VERSION 5.8 ;
BUSBITCHARS "[]" ;
DIVIDERCHAR "/" ;
UNITS
    DATABASE MICRONS 1000 ;
END UNITS

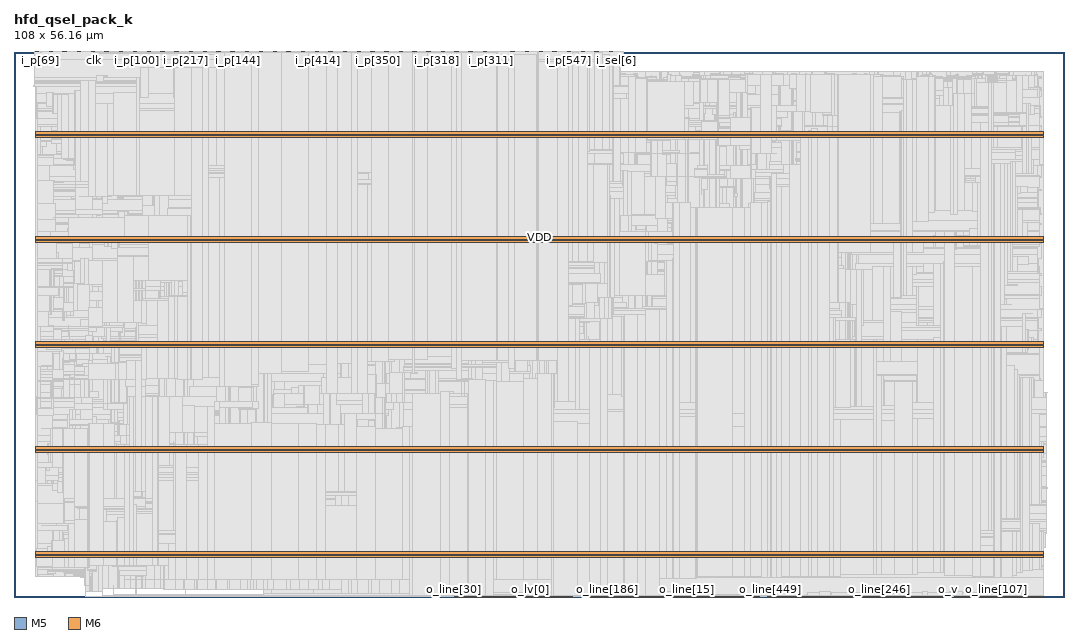
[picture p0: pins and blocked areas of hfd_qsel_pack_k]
MACRO hfd_qsel_pack_k
  FOREIGN hfd_qsel_pack_k 0 0 ;
  CLASS BLOCK ;
  SIZE 108 BY 56.16 ;
  PIN clk
    DIRECTION INPUT ;
    USE SIGNAL ;
    PORT
      LAYER M5 ;
        RECT  8.208 56.076 8.232 56.16 ;
    END
  END clk
  PIN i_fl
    DIRECTION INPUT ;
    USE SIGNAL ;
    PORT
      LAYER M5 ;
        RECT  8.304 56.076 8.328 56.16 ;
    END
  END i_fl
  PIN i_p[0]
    DIRECTION INPUT ;
    USE SIGNAL ;
    PORT
      LAYER M5 ;
        RECT  8.4 56.076 8.424 56.16 ;
    END
  END i_p[0]
  PIN i_p[100]
    DIRECTION INPUT ;
    USE SIGNAL ;
    PORT
      LAYER M5 ;
        RECT  12.624 56.076 12.648 56.16 ;
    END
  END i_p[100]
  PIN i_p[101]
    DIRECTION INPUT ;
    USE SIGNAL ;
    PORT
      LAYER M5 ;
        RECT  12.72 56.076 12.744 56.16 ;
    END
  END i_p[101]
  PIN i_p[102]
    DIRECTION INPUT ;
    USE SIGNAL ;
    PORT
      LAYER M5 ;
        RECT  12.816 56.076 12.84 56.16 ;
    END
  END i_p[102]
  PIN i_p[103]
    DIRECTION INPUT ;
    USE SIGNAL ;
    PORT
      LAYER M5 ;
        RECT  12.912 56.076 12.936 56.16 ;
    END
  END i_p[103]
  PIN i_p[104]
    DIRECTION INPUT ;
    USE SIGNAL ;
    PORT
      LAYER M5 ;
        RECT  13.008 56.076 13.032 56.16 ;
    END
  END i_p[104]
  PIN i_p[105]
    DIRECTION INPUT ;
    USE SIGNAL ;
    PORT
      LAYER M5 ;
        RECT  13.104 56.076 13.128 56.16 ;
    END
  END i_p[105]
  PIN i_p[106]
    DIRECTION INPUT ;
    USE SIGNAL ;
    PORT
      LAYER M5 ;
        RECT  13.2 56.076 13.224 56.16 ;
    END
  END i_p[106]
  PIN i_p[107]
    DIRECTION INPUT ;
    USE SIGNAL ;
    PORT
      LAYER M5 ;
        RECT  13.296 56.076 13.32 56.16 ;
    END
  END i_p[107]
  PIN i_p[108]
    DIRECTION INPUT ;
    USE SIGNAL ;
    PORT
      LAYER M5 ;
        RECT  13.392 56.076 13.416 56.16 ;
    END
  END i_p[108]
  PIN i_p[109]
    DIRECTION INPUT ;
    USE SIGNAL ;
    PORT
      LAYER M5 ;
        RECT  13.488 56.076 13.512 56.16 ;
    END
  END i_p[109]
  PIN i_p[10]
    DIRECTION INPUT ;
    USE SIGNAL ;
    PORT
      LAYER M5 ;
        RECT  9.36 56.076 9.384 56.16 ;
    END
  END i_p[10]
  PIN i_p[110]
    DIRECTION INPUT ;
    USE SIGNAL ;
    PORT
      LAYER M5 ;
        RECT  13.584 56.076 13.608 56.16 ;
    END
  END i_p[110]
  PIN i_p[111]
    DIRECTION INPUT ;
    USE SIGNAL ;
    PORT
      LAYER M5 ;
        RECT  13.68 56.076 13.704 56.16 ;
    END
  END i_p[111]
  PIN i_p[112]
    DIRECTION INPUT ;
    USE SIGNAL ;
    PORT
      LAYER M5 ;
        RECT  13.776 56.076 13.8 56.16 ;
    END
  END i_p[112]
  PIN i_p[113]
    DIRECTION INPUT ;
    USE SIGNAL ;
    PORT
      LAYER M5 ;
        RECT  13.872 56.076 13.896 56.16 ;
    END
  END i_p[113]
  PIN i_p[114]
    DIRECTION INPUT ;
    USE SIGNAL ;
    PORT
      LAYER M5 ;
        RECT  13.968 56.076 13.992 56.16 ;
    END
  END i_p[114]
  PIN i_p[115]
    DIRECTION INPUT ;
    USE SIGNAL ;
    PORT
      LAYER M5 ;
        RECT  14.064 56.076 14.088 56.16 ;
    END
  END i_p[115]
  PIN i_p[116]
    DIRECTION INPUT ;
    USE SIGNAL ;
    PORT
      LAYER M5 ;
        RECT  14.16 56.076 14.184 56.16 ;
    END
  END i_p[116]
  PIN i_p[117]
    DIRECTION INPUT ;
    USE SIGNAL ;
    PORT
      LAYER M5 ;
        RECT  14.256 56.076 14.28 56.16 ;
    END
  END i_p[117]
  PIN i_p[118]
    DIRECTION INPUT ;
    USE SIGNAL ;
    PORT
      LAYER M5 ;
        RECT  14.352 56.076 14.376 56.16 ;
    END
  END i_p[118]
  PIN i_p[119]
    DIRECTION INPUT ;
    USE SIGNAL ;
    PORT
      LAYER M5 ;
        RECT  14.448 56.076 14.472 56.16 ;
    END
  END i_p[119]
  PIN i_p[11]
    DIRECTION INPUT ;
    USE SIGNAL ;
    PORT
      LAYER M5 ;
        RECT  9.456 56.076 9.48 56.16 ;
    END
  END i_p[11]
  PIN i_p[120]
    DIRECTION INPUT ;
    USE SIGNAL ;
    PORT
      LAYER M5 ;
        RECT  14.544 56.076 14.568 56.16 ;
    END
  END i_p[120]
  PIN i_p[121]
    DIRECTION INPUT ;
    USE SIGNAL ;
    PORT
      LAYER M5 ;
        RECT  14.64 56.076 14.664 56.16 ;
    END
  END i_p[121]
  PIN i_p[122]
    DIRECTION INPUT ;
    USE SIGNAL ;
    PORT
      LAYER M5 ;
        RECT  14.736 56.076 14.76 56.16 ;
    END
  END i_p[122]
  PIN i_p[123]
    DIRECTION INPUT ;
    USE SIGNAL ;
    PORT
      LAYER M5 ;
        RECT  14.832 56.076 14.856 56.16 ;
    END
  END i_p[123]
  PIN i_p[124]
    DIRECTION INPUT ;
    USE SIGNAL ;
    PORT
      LAYER M5 ;
        RECT  14.928 56.076 14.952 56.16 ;
    END
  END i_p[124]
  PIN i_p[125]
    DIRECTION INPUT ;
    USE SIGNAL ;
    PORT
      LAYER M5 ;
        RECT  15.024 56.076 15.048 56.16 ;
    END
  END i_p[125]
  PIN i_p[126]
    DIRECTION INPUT ;
    USE SIGNAL ;
    PORT
      LAYER M5 ;
        RECT  21.264 56.076 21.288 56.16 ;
    END
  END i_p[126]
  PIN i_p[127]
    DIRECTION INPUT ;
    USE SIGNAL ;
    PORT
      LAYER M5 ;
        RECT  21.36 56.076 21.384 56.16 ;
    END
  END i_p[127]
  PIN i_p[128]
    DIRECTION INPUT ;
    USE SIGNAL ;
    PORT
      LAYER M5 ;
        RECT  21.456 56.076 21.48 56.16 ;
    END
  END i_p[128]
  PIN i_p[129]
    DIRECTION INPUT ;
    USE SIGNAL ;
    PORT
      LAYER M5 ;
        RECT  21.552 56.076 21.576 56.16 ;
    END
  END i_p[129]
  PIN i_p[12]
    DIRECTION INPUT ;
    USE SIGNAL ;
    PORT
      LAYER M5 ;
        RECT  9.552 56.076 9.576 56.16 ;
    END
  END i_p[12]
  PIN i_p[130]
    DIRECTION INPUT ;
    USE SIGNAL ;
    PORT
      LAYER M5 ;
        RECT  21.648 56.076 21.672 56.16 ;
    END
  END i_p[130]
  PIN i_p[131]
    DIRECTION INPUT ;
    USE SIGNAL ;
    PORT
      LAYER M5 ;
        RECT  21.744 56.076 21.768 56.16 ;
    END
  END i_p[131]
  PIN i_p[132]
    DIRECTION INPUT ;
    USE SIGNAL ;
    PORT
      LAYER M5 ;
        RECT  21.84 56.076 21.864 56.16 ;
    END
  END i_p[132]
  PIN i_p[133]
    DIRECTION INPUT ;
    USE SIGNAL ;
    PORT
      LAYER M5 ;
        RECT  21.936 56.076 21.96 56.16 ;
    END
  END i_p[133]
  PIN i_p[134]
    DIRECTION INPUT ;
    USE SIGNAL ;
    PORT
      LAYER M5 ;
        RECT  22.032 56.076 22.056 56.16 ;
    END
  END i_p[134]
  PIN i_p[135]
    DIRECTION INPUT ;
    USE SIGNAL ;
    PORT
      LAYER M5 ;
        RECT  22.128 56.076 22.152 56.16 ;
    END
  END i_p[135]
  PIN i_p[136]
    DIRECTION INPUT ;
    USE SIGNAL ;
    PORT
      LAYER M5 ;
        RECT  22.224 56.076 22.248 56.16 ;
    END
  END i_p[136]
  PIN i_p[137]
    DIRECTION INPUT ;
    USE SIGNAL ;
    PORT
      LAYER M5 ;
        RECT  22.32 56.076 22.344 56.16 ;
    END
  END i_p[137]
  PIN i_p[138]
    DIRECTION INPUT ;
    USE SIGNAL ;
    PORT
      LAYER M5 ;
        RECT  22.416 56.076 22.44 56.16 ;
    END
  END i_p[138]
  PIN i_p[139]
    DIRECTION INPUT ;
    USE SIGNAL ;
    PORT
      LAYER M5 ;
        RECT  22.512 56.076 22.536 56.16 ;
    END
  END i_p[139]
  PIN i_p[13]
    DIRECTION INPUT ;
    USE SIGNAL ;
    PORT
      LAYER M5 ;
        RECT  9.648 56.076 9.672 56.16 ;
    END
  END i_p[13]
  PIN i_p[140]
    DIRECTION INPUT ;
    USE SIGNAL ;
    PORT
      LAYER M5 ;
        RECT  22.608 56.076 22.632 56.16 ;
    END
  END i_p[140]
  PIN i_p[141]
    DIRECTION INPUT ;
    USE SIGNAL ;
    PORT
      LAYER M5 ;
        RECT  22.704 56.076 22.728 56.16 ;
    END
  END i_p[141]
  PIN i_p[142]
    DIRECTION INPUT ;
    USE SIGNAL ;
    PORT
      LAYER M5 ;
        RECT  22.8 56.076 22.824 56.16 ;
    END
  END i_p[142]
  PIN i_p[143]
    DIRECTION INPUT ;
    USE SIGNAL ;
    PORT
      LAYER M5 ;
        RECT  22.896 56.076 22.92 56.16 ;
    END
  END i_p[143]
  PIN i_p[144]
    DIRECTION INPUT ;
    USE SIGNAL ;
    PORT
      LAYER M5 ;
        RECT  22.992 56.076 23.016 56.16 ;
    END
  END i_p[144]
  PIN i_p[145]
    DIRECTION INPUT ;
    USE SIGNAL ;
    PORT
      LAYER M5 ;
        RECT  23.088 56.076 23.112 56.16 ;
    END
  END i_p[145]
  PIN i_p[146]
    DIRECTION INPUT ;
    USE SIGNAL ;
    PORT
      LAYER M5 ;
        RECT  23.184 56.076 23.208 56.16 ;
    END
  END i_p[146]
  PIN i_p[147]
    DIRECTION INPUT ;
    USE SIGNAL ;
    PORT
      LAYER M5 ;
        RECT  23.28 56.076 23.304 56.16 ;
    END
  END i_p[147]
  PIN i_p[148]
    DIRECTION INPUT ;
    USE SIGNAL ;
    PORT
      LAYER M5 ;
        RECT  23.376 56.076 23.4 56.16 ;
    END
  END i_p[148]
  PIN i_p[149]
    DIRECTION INPUT ;
    USE SIGNAL ;
    PORT
      LAYER M5 ;
        RECT  23.472 56.076 23.496 56.16 ;
    END
  END i_p[149]
  PIN i_p[14]
    DIRECTION INPUT ;
    USE SIGNAL ;
    PORT
      LAYER M5 ;
        RECT  9.744 56.076 9.768 56.16 ;
    END
  END i_p[14]
  PIN i_p[150]
    DIRECTION INPUT ;
    USE SIGNAL ;
    PORT
      LAYER M5 ;
        RECT  23.568 56.076 23.592 56.16 ;
    END
  END i_p[150]
  PIN i_p[151]
    DIRECTION INPUT ;
    USE SIGNAL ;
    PORT
      LAYER M5 ;
        RECT  23.664 56.076 23.688 56.16 ;
    END
  END i_p[151]
  PIN i_p[152]
    DIRECTION INPUT ;
    USE SIGNAL ;
    PORT
      LAYER M5 ;
        RECT  23.76 56.076 23.784 56.16 ;
    END
  END i_p[152]
  PIN i_p[153]
    DIRECTION INPUT ;
    USE SIGNAL ;
    PORT
      LAYER M5 ;
        RECT  23.856 56.076 23.88 56.16 ;
    END
  END i_p[153]
  PIN i_p[154]
    DIRECTION INPUT ;
    USE SIGNAL ;
    PORT
      LAYER M5 ;
        RECT  23.952 56.076 23.976 56.16 ;
    END
  END i_p[154]
  PIN i_p[155]
    DIRECTION INPUT ;
    USE SIGNAL ;
    PORT
      LAYER M5 ;
        RECT  24.048 56.076 24.072 56.16 ;
    END
  END i_p[155]
  PIN i_p[156]
    DIRECTION INPUT ;
    USE SIGNAL ;
    PORT
      LAYER M5 ;
        RECT  24.144 56.076 24.168 56.16 ;
    END
  END i_p[156]
  PIN i_p[157]
    DIRECTION INPUT ;
    USE SIGNAL ;
    PORT
      LAYER M5 ;
        RECT  24.24 56.076 24.264 56.16 ;
    END
  END i_p[157]
  PIN i_p[158]
    DIRECTION INPUT ;
    USE SIGNAL ;
    PORT
      LAYER M5 ;
        RECT  24.336 56.076 24.36 56.16 ;
    END
  END i_p[158]
  PIN i_p[159]
    DIRECTION INPUT ;
    USE SIGNAL ;
    PORT
      LAYER M5 ;
        RECT  24.432 56.076 24.456 56.16 ;
    END
  END i_p[159]
  PIN i_p[15]
    DIRECTION INPUT ;
    USE SIGNAL ;
    PORT
      LAYER M5 ;
        RECT  9.84 56.076 9.864 56.16 ;
    END
  END i_p[15]
  PIN i_p[160]
    DIRECTION INPUT ;
    USE SIGNAL ;
    PORT
      LAYER M5 ;
        RECT  24.528 56.076 24.552 56.16 ;
    END
  END i_p[160]
  PIN i_p[161]
    DIRECTION INPUT ;
    USE SIGNAL ;
    PORT
      LAYER M5 ;
        RECT  24.624 56.076 24.648 56.16 ;
    END
  END i_p[161]
  PIN i_p[162]
    DIRECTION INPUT ;
    USE SIGNAL ;
    PORT
      LAYER M5 ;
        RECT  24.72 56.076 24.744 56.16 ;
    END
  END i_p[162]
  PIN i_p[163]
    DIRECTION INPUT ;
    USE SIGNAL ;
    PORT
      LAYER M5 ;
        RECT  24.816 56.076 24.84 56.16 ;
    END
  END i_p[163]
  PIN i_p[164]
    DIRECTION INPUT ;
    USE SIGNAL ;
    PORT
      LAYER M5 ;
        RECT  24.912 56.076 24.936 56.16 ;
    END
  END i_p[164]
  PIN i_p[165]
    DIRECTION INPUT ;
    USE SIGNAL ;
    PORT
      LAYER M5 ;
        RECT  25.008 56.076 25.032 56.16 ;
    END
  END i_p[165]
  PIN i_p[166]
    DIRECTION INPUT ;
    USE SIGNAL ;
    PORT
      LAYER M5 ;
        RECT  25.104 56.076 25.128 56.16 ;
    END
  END i_p[166]
  PIN i_p[167]
    DIRECTION INPUT ;
    USE SIGNAL ;
    PORT
      LAYER M5 ;
        RECT  25.2 56.076 25.224 56.16 ;
    END
  END i_p[167]
  PIN i_p[168]
    DIRECTION INPUT ;
    USE SIGNAL ;
    PORT
      LAYER M5 ;
        RECT  25.296 56.076 25.32 56.16 ;
    END
  END i_p[168]
  PIN i_p[169]
    DIRECTION INPUT ;
    USE SIGNAL ;
    PORT
      LAYER M5 ;
        RECT  25.392 56.076 25.416 56.16 ;
    END
  END i_p[169]
  PIN i_p[16]
    DIRECTION INPUT ;
    USE SIGNAL ;
    PORT
      LAYER M5 ;
        RECT  9.936 56.076 9.96 56.16 ;
    END
  END i_p[16]
  PIN i_p[170]
    DIRECTION INPUT ;
    USE SIGNAL ;
    PORT
      LAYER M5 ;
        RECT  25.488 56.076 25.512 56.16 ;
    END
  END i_p[170]
  PIN i_p[171]
    DIRECTION INPUT ;
    USE SIGNAL ;
    PORT
      LAYER M5 ;
        RECT  25.584 56.076 25.608 56.16 ;
    END
  END i_p[171]
  PIN i_p[172]
    DIRECTION INPUT ;
    USE SIGNAL ;
    PORT
      LAYER M5 ;
        RECT  25.68 56.076 25.704 56.16 ;
    END
  END i_p[172]
  PIN i_p[173]
    DIRECTION INPUT ;
    USE SIGNAL ;
    PORT
      LAYER M5 ;
        RECT  25.776 56.076 25.8 56.16 ;
    END
  END i_p[173]
  PIN i_p[174]
    DIRECTION INPUT ;
    USE SIGNAL ;
    PORT
      LAYER M5 ;
        RECT  25.872 56.076 25.896 56.16 ;
    END
  END i_p[174]
  PIN i_p[175]
    DIRECTION INPUT ;
    USE SIGNAL ;
    PORT
      LAYER M5 ;
        RECT  25.968 56.076 25.992 56.16 ;
    END
  END i_p[175]
  PIN i_p[176]
    DIRECTION INPUT ;
    USE SIGNAL ;
    PORT
      LAYER M5 ;
        RECT  26.064 56.076 26.088 56.16 ;
    END
  END i_p[176]
  PIN i_p[177]
    DIRECTION INPUT ;
    USE SIGNAL ;
    PORT
      LAYER M5 ;
        RECT  26.16 56.076 26.184 56.16 ;
    END
  END i_p[177]
  PIN i_p[178]
    DIRECTION INPUT ;
    USE SIGNAL ;
    PORT
      LAYER M5 ;
        RECT  26.256 56.076 26.28 56.16 ;
    END
  END i_p[178]
  PIN i_p[179]
    DIRECTION INPUT ;
    USE SIGNAL ;
    PORT
      LAYER M5 ;
        RECT  26.352 56.076 26.376 56.16 ;
    END
  END i_p[179]
  PIN i_p[17]
    DIRECTION INPUT ;
    USE SIGNAL ;
    PORT
      LAYER M5 ;
        RECT  10.032 56.076 10.056 56.16 ;
    END
  END i_p[17]
  PIN i_p[180]
    DIRECTION INPUT ;
    USE SIGNAL ;
    PORT
      LAYER M5 ;
        RECT  26.448 56.076 26.472 56.16 ;
    END
  END i_p[180]
  PIN i_p[181]
    DIRECTION INPUT ;
    USE SIGNAL ;
    PORT
      LAYER M5 ;
        RECT  26.544 56.076 26.568 56.16 ;
    END
  END i_p[181]
  PIN i_p[182]
    DIRECTION INPUT ;
    USE SIGNAL ;
    PORT
      LAYER M5 ;
        RECT  26.64 56.076 26.664 56.16 ;
    END
  END i_p[182]
  PIN i_p[183]
    DIRECTION INPUT ;
    USE SIGNAL ;
    PORT
      LAYER M5 ;
        RECT  26.736 56.076 26.76 56.16 ;
    END
  END i_p[183]
  PIN i_p[184]
    DIRECTION INPUT ;
    USE SIGNAL ;
    PORT
      LAYER M5 ;
        RECT  26.832 56.076 26.856 56.16 ;
    END
  END i_p[184]
  PIN i_p[185]
    DIRECTION INPUT ;
    USE SIGNAL ;
    PORT
      LAYER M5 ;
        RECT  26.928 56.076 26.952 56.16 ;
    END
  END i_p[185]
  PIN i_p[186]
    DIRECTION INPUT ;
    USE SIGNAL ;
    PORT
      LAYER M5 ;
        RECT  27.024 56.076 27.048 56.16 ;
    END
  END i_p[186]
  PIN i_p[187]
    DIRECTION INPUT ;
    USE SIGNAL ;
    PORT
      LAYER M5 ;
        RECT  27.12 56.076 27.144 56.16 ;
    END
  END i_p[187]
  PIN i_p[188]
    DIRECTION INPUT ;
    USE SIGNAL ;
    PORT
      LAYER M5 ;
        RECT  27.216 56.076 27.24 56.16 ;
    END
  END i_p[188]
  PIN i_p[189]
    DIRECTION INPUT ;
    USE SIGNAL ;
    PORT
      LAYER M5 ;
        RECT  27.312 56.076 27.336 56.16 ;
    END
  END i_p[189]
  PIN i_p[18]
    DIRECTION INPUT ;
    USE SIGNAL ;
    PORT
      LAYER M5 ;
        RECT  10.128 56.076 10.152 56.16 ;
    END
  END i_p[18]
  PIN i_p[190]
    DIRECTION INPUT ;
    USE SIGNAL ;
    PORT
      LAYER M5 ;
        RECT  15.12 56.076 15.144 56.16 ;
    END
  END i_p[190]
  PIN i_p[191]
    DIRECTION INPUT ;
    USE SIGNAL ;
    PORT
      LAYER M5 ;
        RECT  15.216 56.076 15.24 56.16 ;
    END
  END i_p[191]
  PIN i_p[192]
    DIRECTION INPUT ;
    USE SIGNAL ;
    PORT
      LAYER M5 ;
        RECT  15.312 56.076 15.336 56.16 ;
    END
  END i_p[192]
  PIN i_p[193]
    DIRECTION INPUT ;
    USE SIGNAL ;
    PORT
      LAYER M5 ;
        RECT  15.408 56.076 15.432 56.16 ;
    END
  END i_p[193]
  PIN i_p[194]
    DIRECTION INPUT ;
    USE SIGNAL ;
    PORT
      LAYER M5 ;
        RECT  15.504 56.076 15.528 56.16 ;
    END
  END i_p[194]
  PIN i_p[195]
    DIRECTION INPUT ;
    USE SIGNAL ;
    PORT
      LAYER M5 ;
        RECT  15.6 56.076 15.624 56.16 ;
    END
  END i_p[195]
  PIN i_p[196]
    DIRECTION INPUT ;
    USE SIGNAL ;
    PORT
      LAYER M5 ;
        RECT  15.696 56.076 15.72 56.16 ;
    END
  END i_p[196]
  PIN i_p[197]
    DIRECTION INPUT ;
    USE SIGNAL ;
    PORT
      LAYER M5 ;
        RECT  15.792 56.076 15.816 56.16 ;
    END
  END i_p[197]
  PIN i_p[198]
    DIRECTION INPUT ;
    USE SIGNAL ;
    PORT
      LAYER M5 ;
        RECT  15.888 56.076 15.912 56.16 ;
    END
  END i_p[198]
  PIN i_p[199]
    DIRECTION INPUT ;
    USE SIGNAL ;
    PORT
      LAYER M5 ;
        RECT  15.984 56.076 16.008 56.16 ;
    END
  END i_p[199]
  PIN i_p[19]
    DIRECTION INPUT ;
    USE SIGNAL ;
    PORT
      LAYER M5 ;
        RECT  10.224 56.076 10.248 56.16 ;
    END
  END i_p[19]
  PIN i_p[1]
    DIRECTION INPUT ;
    USE SIGNAL ;
    PORT
      LAYER M5 ;
        RECT  8.496 56.076 8.52 56.16 ;
    END
  END i_p[1]
  PIN i_p[200]
    DIRECTION INPUT ;
    USE SIGNAL ;
    PORT
      LAYER M5 ;
        RECT  16.08 56.076 16.104 56.16 ;
    END
  END i_p[200]
  PIN i_p[201]
    DIRECTION INPUT ;
    USE SIGNAL ;
    PORT
      LAYER M5 ;
        RECT  16.176 56.076 16.2 56.16 ;
    END
  END i_p[201]
  PIN i_p[202]
    DIRECTION INPUT ;
    USE SIGNAL ;
    PORT
      LAYER M5 ;
        RECT  16.272 56.076 16.296 56.16 ;
    END
  END i_p[202]
  PIN i_p[203]
    DIRECTION INPUT ;
    USE SIGNAL ;
    PORT
      LAYER M5 ;
        RECT  16.368 56.076 16.392 56.16 ;
    END
  END i_p[203]
  PIN i_p[204]
    DIRECTION INPUT ;
    USE SIGNAL ;
    PORT
      LAYER M5 ;
        RECT  16.464 56.076 16.488 56.16 ;
    END
  END i_p[204]
  PIN i_p[205]
    DIRECTION INPUT ;
    USE SIGNAL ;
    PORT
      LAYER M5 ;
        RECT  16.56 56.076 16.584 56.16 ;
    END
  END i_p[205]
  PIN i_p[206]
    DIRECTION INPUT ;
    USE SIGNAL ;
    PORT
      LAYER M5 ;
        RECT  16.656 56.076 16.68 56.16 ;
    END
  END i_p[206]
  PIN i_p[207]
    DIRECTION INPUT ;
    USE SIGNAL ;
    PORT
      LAYER M5 ;
        RECT  16.752 56.076 16.776 56.16 ;
    END
  END i_p[207]
  PIN i_p[208]
    DIRECTION INPUT ;
    USE SIGNAL ;
    PORT
      LAYER M5 ;
        RECT  16.848 56.076 16.872 56.16 ;
    END
  END i_p[208]
  PIN i_p[209]
    DIRECTION INPUT ;
    USE SIGNAL ;
    PORT
      LAYER M5 ;
        RECT  16.944 56.076 16.968 56.16 ;
    END
  END i_p[209]
  PIN i_p[20]
    DIRECTION INPUT ;
    USE SIGNAL ;
    PORT
      LAYER M5 ;
        RECT  10.32 56.076 10.344 56.16 ;
    END
  END i_p[20]
  PIN i_p[210]
    DIRECTION INPUT ;
    USE SIGNAL ;
    PORT
      LAYER M5 ;
        RECT  17.04 56.076 17.064 56.16 ;
    END
  END i_p[210]
  PIN i_p[211]
    DIRECTION INPUT ;
    USE SIGNAL ;
    PORT
      LAYER M5 ;
        RECT  17.136 56.076 17.16 56.16 ;
    END
  END i_p[211]
  PIN i_p[212]
    DIRECTION INPUT ;
    USE SIGNAL ;
    PORT
      LAYER M5 ;
        RECT  17.232 56.076 17.256 56.16 ;
    END
  END i_p[212]
  PIN i_p[213]
    DIRECTION INPUT ;
    USE SIGNAL ;
    PORT
      LAYER M5 ;
        RECT  17.328 56.076 17.352 56.16 ;
    END
  END i_p[213]
  PIN i_p[214]
    DIRECTION INPUT ;
    USE SIGNAL ;
    PORT
      LAYER M5 ;
        RECT  17.424 56.076 17.448 56.16 ;
    END
  END i_p[214]
  PIN i_p[215]
    DIRECTION INPUT ;
    USE SIGNAL ;
    PORT
      LAYER M5 ;
        RECT  17.52 56.076 17.544 56.16 ;
    END
  END i_p[215]
  PIN i_p[216]
    DIRECTION INPUT ;
    USE SIGNAL ;
    PORT
      LAYER M5 ;
        RECT  17.616 56.076 17.64 56.16 ;
    END
  END i_p[216]
  PIN i_p[217]
    DIRECTION INPUT ;
    USE SIGNAL ;
    PORT
      LAYER M5 ;
        RECT  17.712 56.076 17.736 56.16 ;
    END
  END i_p[217]
  PIN i_p[218]
    DIRECTION INPUT ;
    USE SIGNAL ;
    PORT
      LAYER M5 ;
        RECT  17.808 56.076 17.832 56.16 ;
    END
  END i_p[218]
  PIN i_p[219]
    DIRECTION INPUT ;
    USE SIGNAL ;
    PORT
      LAYER M5 ;
        RECT  17.904 56.076 17.928 56.16 ;
    END
  END i_p[219]
  PIN i_p[21]
    DIRECTION INPUT ;
    USE SIGNAL ;
    PORT
      LAYER M5 ;
        RECT  10.416 56.076 10.44 56.16 ;
    END
  END i_p[21]
  PIN i_p[220]
    DIRECTION INPUT ;
    USE SIGNAL ;
    PORT
      LAYER M5 ;
        RECT  18 56.076 18.024 56.16 ;
    END
  END i_p[220]
  PIN i_p[221]
    DIRECTION INPUT ;
    USE SIGNAL ;
    PORT
      LAYER M5 ;
        RECT  18.096 56.076 18.12 56.16 ;
    END
  END i_p[221]
  PIN i_p[222]
    DIRECTION INPUT ;
    USE SIGNAL ;
    PORT
      LAYER M5 ;
        RECT  27.408 56.076 27.432 56.16 ;
    END
  END i_p[222]
  PIN i_p[223]
    DIRECTION INPUT ;
    USE SIGNAL ;
    PORT
      LAYER M5 ;
        RECT  27.504 56.076 27.528 56.16 ;
    END
  END i_p[223]
  PIN i_p[224]
    DIRECTION INPUT ;
    USE SIGNAL ;
    PORT
      LAYER M5 ;
        RECT  27.6 56.076 27.624 56.16 ;
    END
  END i_p[224]
  PIN i_p[225]
    DIRECTION INPUT ;
    USE SIGNAL ;
    PORT
      LAYER M5 ;
        RECT  27.696 56.076 27.72 56.16 ;
    END
  END i_p[225]
  PIN i_p[226]
    DIRECTION INPUT ;
    USE SIGNAL ;
    PORT
      LAYER M5 ;
        RECT  27.792 56.076 27.816 56.16 ;
    END
  END i_p[226]
  PIN i_p[227]
    DIRECTION INPUT ;
    USE SIGNAL ;
    PORT
      LAYER M5 ;
        RECT  27.888 56.076 27.912 56.16 ;
    END
  END i_p[227]
  PIN i_p[228]
    DIRECTION INPUT ;
    USE SIGNAL ;
    PORT
      LAYER M5 ;
        RECT  27.984 56.076 28.008 56.16 ;
    END
  END i_p[228]
  PIN i_p[229]
    DIRECTION INPUT ;
    USE SIGNAL ;
    PORT
      LAYER M5 ;
        RECT  28.08 56.076 28.104 56.16 ;
    END
  END i_p[229]
  PIN i_p[22]
    DIRECTION INPUT ;
    USE SIGNAL ;
    PORT
      LAYER M5 ;
        RECT  10.512 56.076 10.536 56.16 ;
    END
  END i_p[22]
  PIN i_p[230]
    DIRECTION INPUT ;
    USE SIGNAL ;
    PORT
      LAYER M5 ;
        RECT  28.176 56.076 28.2 56.16 ;
    END
  END i_p[230]
  PIN i_p[231]
    DIRECTION INPUT ;
    USE SIGNAL ;
    PORT
      LAYER M5 ;
        RECT  28.272 56.076 28.296 56.16 ;
    END
  END i_p[231]
  PIN i_p[232]
    DIRECTION INPUT ;
    USE SIGNAL ;
    PORT
      LAYER M5 ;
        RECT  28.368 56.076 28.392 56.16 ;
    END
  END i_p[232]
  PIN i_p[233]
    DIRECTION INPUT ;
    USE SIGNAL ;
    PORT
      LAYER M5 ;
        RECT  28.464 56.076 28.488 56.16 ;
    END
  END i_p[233]
  PIN i_p[234]
    DIRECTION INPUT ;
    USE SIGNAL ;
    PORT
      LAYER M5 ;
        RECT  28.56 56.076 28.584 56.16 ;
    END
  END i_p[234]
  PIN i_p[235]
    DIRECTION INPUT ;
    USE SIGNAL ;
    PORT
      LAYER M5 ;
        RECT  28.656 56.076 28.68 56.16 ;
    END
  END i_p[235]
  PIN i_p[236]
    DIRECTION INPUT ;
    USE SIGNAL ;
    PORT
      LAYER M5 ;
        RECT  28.752 56.076 28.776 56.16 ;
    END
  END i_p[236]
  PIN i_p[237]
    DIRECTION INPUT ;
    USE SIGNAL ;
    PORT
      LAYER M5 ;
        RECT  28.848 56.076 28.872 56.16 ;
    END
  END i_p[237]
  PIN i_p[238]
    DIRECTION INPUT ;
    USE SIGNAL ;
    PORT
      LAYER M5 ;
        RECT  28.944 56.076 28.968 56.16 ;
    END
  END i_p[238]
  PIN i_p[239]
    DIRECTION INPUT ;
    USE SIGNAL ;
    PORT
      LAYER M5 ;
        RECT  29.04 56.076 29.064 56.16 ;
    END
  END i_p[239]
  PIN i_p[23]
    DIRECTION INPUT ;
    USE SIGNAL ;
    PORT
      LAYER M5 ;
        RECT  10.608 56.076 10.632 56.16 ;
    END
  END i_p[23]
  PIN i_p[240]
    DIRECTION INPUT ;
    USE SIGNAL ;
    PORT
      LAYER M5 ;
        RECT  29.136 56.076 29.16 56.16 ;
    END
  END i_p[240]
  PIN i_p[241]
    DIRECTION INPUT ;
    USE SIGNAL ;
    PORT
      LAYER M5 ;
        RECT  29.232 56.076 29.256 56.16 ;
    END
  END i_p[241]
  PIN i_p[242]
    DIRECTION INPUT ;
    USE SIGNAL ;
    PORT
      LAYER M5 ;
        RECT  29.328 56.076 29.352 56.16 ;
    END
  END i_p[242]
  PIN i_p[243]
    DIRECTION INPUT ;
    USE SIGNAL ;
    PORT
      LAYER M5 ;
        RECT  29.424 56.076 29.448 56.16 ;
    END
  END i_p[243]
  PIN i_p[244]
    DIRECTION INPUT ;
    USE SIGNAL ;
    PORT
      LAYER M5 ;
        RECT  29.52 56.076 29.544 56.16 ;
    END
  END i_p[244]
  PIN i_p[245]
    DIRECTION INPUT ;
    USE SIGNAL ;
    PORT
      LAYER M5 ;
        RECT  29.616 56.076 29.64 56.16 ;
    END
  END i_p[245]
  PIN i_p[246]
    DIRECTION INPUT ;
    USE SIGNAL ;
    PORT
      LAYER M5 ;
        RECT  29.712 56.076 29.736 56.16 ;
    END
  END i_p[246]
  PIN i_p[247]
    DIRECTION INPUT ;
    USE SIGNAL ;
    PORT
      LAYER M5 ;
        RECT  29.808 56.076 29.832 56.16 ;
    END
  END i_p[247]
  PIN i_p[248]
    DIRECTION INPUT ;
    USE SIGNAL ;
    PORT
      LAYER M5 ;
        RECT  29.904 56.076 29.928 56.16 ;
    END
  END i_p[248]
  PIN i_p[249]
    DIRECTION INPUT ;
    USE SIGNAL ;
    PORT
      LAYER M5 ;
        RECT  30 56.076 30.024 56.16 ;
    END
  END i_p[249]
  PIN i_p[24]
    DIRECTION INPUT ;
    USE SIGNAL ;
    PORT
      LAYER M5 ;
        RECT  10.704 56.076 10.728 56.16 ;
    END
  END i_p[24]
  PIN i_p[250]
    DIRECTION INPUT ;
    USE SIGNAL ;
    PORT
      LAYER M5 ;
        RECT  30.096 56.076 30.12 56.16 ;
    END
  END i_p[250]
  PIN i_p[251]
    DIRECTION INPUT ;
    USE SIGNAL ;
    PORT
      LAYER M5 ;
        RECT  30.192 56.076 30.216 56.16 ;
    END
  END i_p[251]
  PIN i_p[252]
    DIRECTION INPUT ;
    USE SIGNAL ;
    PORT
      LAYER M5 ;
        RECT  30.288 56.076 30.312 56.16 ;
    END
  END i_p[252]
  PIN i_p[253]
    DIRECTION INPUT ;
    USE SIGNAL ;
    PORT
      LAYER M5 ;
        RECT  30.384 56.076 30.408 56.16 ;
    END
  END i_p[253]
  PIN i_p[254]
    DIRECTION INPUT ;
    USE SIGNAL ;
    PORT
      LAYER M5 ;
        RECT  18.192 56.076 18.216 56.16 ;
    END
  END i_p[254]
  PIN i_p[255]
    DIRECTION INPUT ;
    USE SIGNAL ;
    PORT
      LAYER M5 ;
        RECT  18.288 56.076 18.312 56.16 ;
    END
  END i_p[255]
  PIN i_p[256]
    DIRECTION INPUT ;
    USE SIGNAL ;
    PORT
      LAYER M5 ;
        RECT  18.384 56.076 18.408 56.16 ;
    END
  END i_p[256]
  PIN i_p[257]
    DIRECTION INPUT ;
    USE SIGNAL ;
    PORT
      LAYER M5 ;
        RECT  18.48 56.076 18.504 56.16 ;
    END
  END i_p[257]
  PIN i_p[258]
    DIRECTION INPUT ;
    USE SIGNAL ;
    PORT
      LAYER M5 ;
        RECT  18.576 56.076 18.6 56.16 ;
    END
  END i_p[258]
  PIN i_p[259]
    DIRECTION INPUT ;
    USE SIGNAL ;
    PORT
      LAYER M5 ;
        RECT  18.672 56.076 18.696 56.16 ;
    END
  END i_p[259]
  PIN i_p[25]
    DIRECTION INPUT ;
    USE SIGNAL ;
    PORT
      LAYER M5 ;
        RECT  10.8 56.076 10.824 56.16 ;
    END
  END i_p[25]
  PIN i_p[260]
    DIRECTION INPUT ;
    USE SIGNAL ;
    PORT
      LAYER M5 ;
        RECT  18.768 56.076 18.792 56.16 ;
    END
  END i_p[260]
  PIN i_p[261]
    DIRECTION INPUT ;
    USE SIGNAL ;
    PORT
      LAYER M5 ;
        RECT  18.864 56.076 18.888 56.16 ;
    END
  END i_p[261]
  PIN i_p[262]
    DIRECTION INPUT ;
    USE SIGNAL ;
    PORT
      LAYER M5 ;
        RECT  18.96 56.076 18.984 56.16 ;
    END
  END i_p[262]
  PIN i_p[263]
    DIRECTION INPUT ;
    USE SIGNAL ;
    PORT
      LAYER M5 ;
        RECT  19.056 56.076 19.08 56.16 ;
    END
  END i_p[263]
  PIN i_p[264]
    DIRECTION INPUT ;
    USE SIGNAL ;
    PORT
      LAYER M5 ;
        RECT  19.152 56.076 19.176 56.16 ;
    END
  END i_p[264]
  PIN i_p[265]
    DIRECTION INPUT ;
    USE SIGNAL ;
    PORT
      LAYER M5 ;
        RECT  19.248 56.076 19.272 56.16 ;
    END
  END i_p[265]
  PIN i_p[266]
    DIRECTION INPUT ;
    USE SIGNAL ;
    PORT
      LAYER M5 ;
        RECT  19.344 56.076 19.368 56.16 ;
    END
  END i_p[266]
  PIN i_p[267]
    DIRECTION INPUT ;
    USE SIGNAL ;
    PORT
      LAYER M5 ;
        RECT  19.44 56.076 19.464 56.16 ;
    END
  END i_p[267]
  PIN i_p[268]
    DIRECTION INPUT ;
    USE SIGNAL ;
    PORT
      LAYER M5 ;
        RECT  19.536 56.076 19.56 56.16 ;
    END
  END i_p[268]
  PIN i_p[269]
    DIRECTION INPUT ;
    USE SIGNAL ;
    PORT
      LAYER M5 ;
        RECT  19.632 56.076 19.656 56.16 ;
    END
  END i_p[269]
  PIN i_p[26]
    DIRECTION INPUT ;
    USE SIGNAL ;
    PORT
      LAYER M5 ;
        RECT  10.896 56.076 10.92 56.16 ;
    END
  END i_p[26]
  PIN i_p[270]
    DIRECTION INPUT ;
    USE SIGNAL ;
    PORT
      LAYER M5 ;
        RECT  19.728 56.076 19.752 56.16 ;
    END
  END i_p[270]
  PIN i_p[271]
    DIRECTION INPUT ;
    USE SIGNAL ;
    PORT
      LAYER M5 ;
        RECT  19.824 56.076 19.848 56.16 ;
    END
  END i_p[271]
  PIN i_p[272]
    DIRECTION INPUT ;
    USE SIGNAL ;
    PORT
      LAYER M5 ;
        RECT  19.92 56.076 19.944 56.16 ;
    END
  END i_p[272]
  PIN i_p[273]
    DIRECTION INPUT ;
    USE SIGNAL ;
    PORT
      LAYER M5 ;
        RECT  20.016 56.076 20.04 56.16 ;
    END
  END i_p[273]
  PIN i_p[274]
    DIRECTION INPUT ;
    USE SIGNAL ;
    PORT
      LAYER M5 ;
        RECT  20.112 56.076 20.136 56.16 ;
    END
  END i_p[274]
  PIN i_p[275]
    DIRECTION INPUT ;
    USE SIGNAL ;
    PORT
      LAYER M5 ;
        RECT  20.208 56.076 20.232 56.16 ;
    END
  END i_p[275]
  PIN i_p[276]
    DIRECTION INPUT ;
    USE SIGNAL ;
    PORT
      LAYER M5 ;
        RECT  20.304 56.076 20.328 56.16 ;
    END
  END i_p[276]
  PIN i_p[277]
    DIRECTION INPUT ;
    USE SIGNAL ;
    PORT
      LAYER M5 ;
        RECT  20.4 56.076 20.424 56.16 ;
    END
  END i_p[277]
  PIN i_p[278]
    DIRECTION INPUT ;
    USE SIGNAL ;
    PORT
      LAYER M5 ;
        RECT  20.496 56.076 20.52 56.16 ;
    END
  END i_p[278]
  PIN i_p[279]
    DIRECTION INPUT ;
    USE SIGNAL ;
    PORT
      LAYER M5 ;
        RECT  20.592 56.076 20.616 56.16 ;
    END
  END i_p[279]
  PIN i_p[27]
    DIRECTION INPUT ;
    USE SIGNAL ;
    PORT
      LAYER M5 ;
        RECT  10.992 56.076 11.016 56.16 ;
    END
  END i_p[27]
  PIN i_p[280]
    DIRECTION INPUT ;
    USE SIGNAL ;
    PORT
      LAYER M5 ;
        RECT  20.688 56.076 20.712 56.16 ;
    END
  END i_p[280]
  PIN i_p[281]
    DIRECTION INPUT ;
    USE SIGNAL ;
    PORT
      LAYER M5 ;
        RECT  20.784 56.076 20.808 56.16 ;
    END
  END i_p[281]
  PIN i_p[282]
    DIRECTION INPUT ;
    USE SIGNAL ;
    PORT
      LAYER M5 ;
        RECT  20.88 56.076 20.904 56.16 ;
    END
  END i_p[282]
  PIN i_p[283]
    DIRECTION INPUT ;
    USE SIGNAL ;
    PORT
      LAYER M5 ;
        RECT  20.976 56.076 21 56.16 ;
    END
  END i_p[283]
  PIN i_p[284]
    DIRECTION INPUT ;
    USE SIGNAL ;
    PORT
      LAYER M5 ;
        RECT  21.072 56.076 21.096 56.16 ;
    END
  END i_p[284]
  PIN i_p[285]
    DIRECTION INPUT ;
    USE SIGNAL ;
    PORT
      LAYER M5 ;
        RECT  21.168 56.076 21.192 56.16 ;
    END
  END i_p[285]
  PIN i_p[286]
    DIRECTION INPUT ;
    USE SIGNAL ;
    PORT
      LAYER M5 ;
        RECT  46.608 56.076 46.632 56.16 ;
    END
  END i_p[286]
  PIN i_p[287]
    DIRECTION INPUT ;
    USE SIGNAL ;
    PORT
      LAYER M5 ;
        RECT  46.704 56.076 46.728 56.16 ;
    END
  END i_p[287]
  PIN i_p[288]
    DIRECTION INPUT ;
    USE SIGNAL ;
    PORT
      LAYER M5 ;
        RECT  46.8 56.076 46.824 56.16 ;
    END
  END i_p[288]
  PIN i_p[289]
    DIRECTION INPUT ;
    USE SIGNAL ;
    PORT
      LAYER M5 ;
        RECT  46.896 56.076 46.92 56.16 ;
    END
  END i_p[289]
  PIN i_p[28]
    DIRECTION INPUT ;
    USE SIGNAL ;
    PORT
      LAYER M5 ;
        RECT  11.088 56.076 11.112 56.16 ;
    END
  END i_p[28]
  PIN i_p[290]
    DIRECTION INPUT ;
    USE SIGNAL ;
    PORT
      LAYER M5 ;
        RECT  46.992 56.076 47.016 56.16 ;
    END
  END i_p[290]
  PIN i_p[291]
    DIRECTION INPUT ;
    USE SIGNAL ;
    PORT
      LAYER M5 ;
        RECT  47.088 56.076 47.112 56.16 ;
    END
  END i_p[291]
  PIN i_p[292]
    DIRECTION INPUT ;
    USE SIGNAL ;
    PORT
      LAYER M5 ;
        RECT  47.184 56.076 47.208 56.16 ;
    END
  END i_p[292]
  PIN i_p[293]
    DIRECTION INPUT ;
    USE SIGNAL ;
    PORT
      LAYER M5 ;
        RECT  47.28 56.076 47.304 56.16 ;
    END
  END i_p[293]
  PIN i_p[294]
    DIRECTION INPUT ;
    USE SIGNAL ;
    PORT
      LAYER M5 ;
        RECT  47.376 56.076 47.4 56.16 ;
    END
  END i_p[294]
  PIN i_p[295]
    DIRECTION INPUT ;
    USE SIGNAL ;
    PORT
      LAYER M5 ;
        RECT  47.472 56.076 47.496 56.16 ;
    END
  END i_p[295]
  PIN i_p[296]
    DIRECTION INPUT ;
    USE SIGNAL ;
    PORT
      LAYER M5 ;
        RECT  47.568 56.076 47.592 56.16 ;
    END
  END i_p[296]
  PIN i_p[297]
    DIRECTION INPUT ;
    USE SIGNAL ;
    PORT
      LAYER M5 ;
        RECT  47.664 56.076 47.688 56.16 ;
    END
  END i_p[297]
  PIN i_p[298]
    DIRECTION INPUT ;
    USE SIGNAL ;
    PORT
      LAYER M5 ;
        RECT  47.76 56.076 47.784 56.16 ;
    END
  END i_p[298]
  PIN i_p[299]
    DIRECTION INPUT ;
    USE SIGNAL ;
    PORT
      LAYER M5 ;
        RECT  47.856 56.076 47.88 56.16 ;
    END
  END i_p[299]
  PIN i_p[29]
    DIRECTION INPUT ;
    USE SIGNAL ;
    PORT
      LAYER M5 ;
        RECT  11.184 56.076 11.208 56.16 ;
    END
  END i_p[29]
  PIN i_p[2]
    DIRECTION INPUT ;
    USE SIGNAL ;
    PORT
      LAYER M5 ;
        RECT  8.592 56.076 8.616 56.16 ;
    END
  END i_p[2]
  PIN i_p[300]
    DIRECTION INPUT ;
    USE SIGNAL ;
    PORT
      LAYER M5 ;
        RECT  47.952 56.076 47.976 56.16 ;
    END
  END i_p[300]
  PIN i_p[301]
    DIRECTION INPUT ;
    USE SIGNAL ;
    PORT
      LAYER M5 ;
        RECT  48.048 56.076 48.072 56.16 ;
    END
  END i_p[301]
  PIN i_p[302]
    DIRECTION INPUT ;
    USE SIGNAL ;
    PORT
      LAYER M5 ;
        RECT  48.144 56.076 48.168 56.16 ;
    END
  END i_p[302]
  PIN i_p[303]
    DIRECTION INPUT ;
    USE SIGNAL ;
    PORT
      LAYER M5 ;
        RECT  48.24 56.076 48.264 56.16 ;
    END
  END i_p[303]
  PIN i_p[304]
    DIRECTION INPUT ;
    USE SIGNAL ;
    PORT
      LAYER M5 ;
        RECT  48.336 56.076 48.36 56.16 ;
    END
  END i_p[304]
  PIN i_p[305]
    DIRECTION INPUT ;
    USE SIGNAL ;
    PORT
      LAYER M5 ;
        RECT  48.432 56.076 48.456 56.16 ;
    END
  END i_p[305]
  PIN i_p[306]
    DIRECTION INPUT ;
    USE SIGNAL ;
    PORT
      LAYER M5 ;
        RECT  48.528 56.076 48.552 56.16 ;
    END
  END i_p[306]
  PIN i_p[307]
    DIRECTION INPUT ;
    USE SIGNAL ;
    PORT
      LAYER M5 ;
        RECT  48.624 56.076 48.648 56.16 ;
    END
  END i_p[307]
  PIN i_p[308]
    DIRECTION INPUT ;
    USE SIGNAL ;
    PORT
      LAYER M5 ;
        RECT  48.72 56.076 48.744 56.16 ;
    END
  END i_p[308]
  PIN i_p[309]
    DIRECTION INPUT ;
    USE SIGNAL ;
    PORT
      LAYER M5 ;
        RECT  48.816 56.076 48.84 56.16 ;
    END
  END i_p[309]
  PIN i_p[30]
    DIRECTION INPUT ;
    USE SIGNAL ;
    PORT
      LAYER M5 ;
        RECT  5.136 56.076 5.16 56.16 ;
    END
  END i_p[30]
  PIN i_p[310]
    DIRECTION INPUT ;
    USE SIGNAL ;
    PORT
      LAYER M5 ;
        RECT  48.912 56.076 48.936 56.16 ;
    END
  END i_p[310]
  PIN i_p[311]
    DIRECTION INPUT ;
    USE SIGNAL ;
    PORT
      LAYER M5 ;
        RECT  49.008 56.076 49.032 56.16 ;
    END
  END i_p[311]
  PIN i_p[312]
    DIRECTION INPUT ;
    USE SIGNAL ;
    PORT
      LAYER M5 ;
        RECT  49.104 56.076 49.128 56.16 ;
    END
  END i_p[312]
  PIN i_p[313]
    DIRECTION INPUT ;
    USE SIGNAL ;
    PORT
      LAYER M5 ;
        RECT  49.2 56.076 49.224 56.16 ;
    END
  END i_p[313]
  PIN i_p[314]
    DIRECTION INPUT ;
    USE SIGNAL ;
    PORT
      LAYER M5 ;
        RECT  49.296 56.076 49.32 56.16 ;
    END
  END i_p[314]
  PIN i_p[315]
    DIRECTION INPUT ;
    USE SIGNAL ;
    PORT
      LAYER M5 ;
        RECT  49.392 56.076 49.416 56.16 ;
    END
  END i_p[315]
  PIN i_p[316]
    DIRECTION INPUT ;
    USE SIGNAL ;
    PORT
      LAYER M5 ;
        RECT  49.488 56.076 49.512 56.16 ;
    END
  END i_p[316]
  PIN i_p[317]
    DIRECTION INPUT ;
    USE SIGNAL ;
    PORT
      LAYER M5 ;
        RECT  49.584 56.076 49.608 56.16 ;
    END
  END i_p[317]
  PIN i_p[318]
    DIRECTION INPUT ;
    USE SIGNAL ;
    PORT
      LAYER M5 ;
        RECT  43.536 56.076 43.56 56.16 ;
    END
  END i_p[318]
  PIN i_p[319]
    DIRECTION INPUT ;
    USE SIGNAL ;
    PORT
      LAYER M5 ;
        RECT  43.632 56.076 43.656 56.16 ;
    END
  END i_p[319]
  PIN i_p[31]
    DIRECTION INPUT ;
    USE SIGNAL ;
    PORT
      LAYER M5 ;
        RECT  5.232 56.076 5.256 56.16 ;
    END
  END i_p[31]
  PIN i_p[320]
    DIRECTION INPUT ;
    USE SIGNAL ;
    PORT
      LAYER M5 ;
        RECT  43.728 56.076 43.752 56.16 ;
    END
  END i_p[320]
  PIN i_p[321]
    DIRECTION INPUT ;
    USE SIGNAL ;
    PORT
      LAYER M5 ;
        RECT  43.824 56.076 43.848 56.16 ;
    END
  END i_p[321]
  PIN i_p[322]
    DIRECTION INPUT ;
    USE SIGNAL ;
    PORT
      LAYER M5 ;
        RECT  43.92 56.076 43.944 56.16 ;
    END
  END i_p[322]
  PIN i_p[323]
    DIRECTION INPUT ;
    USE SIGNAL ;
    PORT
      LAYER M5 ;
        RECT  44.016 56.076 44.04 56.16 ;
    END
  END i_p[323]
  PIN i_p[324]
    DIRECTION INPUT ;
    USE SIGNAL ;
    PORT
      LAYER M5 ;
        RECT  44.112 56.076 44.136 56.16 ;
    END
  END i_p[324]
  PIN i_p[325]
    DIRECTION INPUT ;
    USE SIGNAL ;
    PORT
      LAYER M5 ;
        RECT  44.208 56.076 44.232 56.16 ;
    END
  END i_p[325]
  PIN i_p[326]
    DIRECTION INPUT ;
    USE SIGNAL ;
    PORT
      LAYER M5 ;
        RECT  44.304 56.076 44.328 56.16 ;
    END
  END i_p[326]
  PIN i_p[327]
    DIRECTION INPUT ;
    USE SIGNAL ;
    PORT
      LAYER M5 ;
        RECT  44.4 56.076 44.424 56.16 ;
    END
  END i_p[327]
  PIN i_p[328]
    DIRECTION INPUT ;
    USE SIGNAL ;
    PORT
      LAYER M5 ;
        RECT  44.496 56.076 44.52 56.16 ;
    END
  END i_p[328]
  PIN i_p[329]
    DIRECTION INPUT ;
    USE SIGNAL ;
    PORT
      LAYER M5 ;
        RECT  44.592 56.076 44.616 56.16 ;
    END
  END i_p[329]
  PIN i_p[32]
    DIRECTION INPUT ;
    USE SIGNAL ;
    PORT
      LAYER M5 ;
        RECT  5.328 56.076 5.352 56.16 ;
    END
  END i_p[32]
  PIN i_p[330]
    DIRECTION INPUT ;
    USE SIGNAL ;
    PORT
      LAYER M5 ;
        RECT  44.688 56.076 44.712 56.16 ;
    END
  END i_p[330]
  PIN i_p[331]
    DIRECTION INPUT ;
    USE SIGNAL ;
    PORT
      LAYER M5 ;
        RECT  44.784 56.076 44.808 56.16 ;
    END
  END i_p[331]
  PIN i_p[332]
    DIRECTION INPUT ;
    USE SIGNAL ;
    PORT
      LAYER M5 ;
        RECT  44.88 56.076 44.904 56.16 ;
    END
  END i_p[332]
  PIN i_p[333]
    DIRECTION INPUT ;
    USE SIGNAL ;
    PORT
      LAYER M5 ;
        RECT  44.976 56.076 45 56.16 ;
    END
  END i_p[333]
  PIN i_p[334]
    DIRECTION INPUT ;
    USE SIGNAL ;
    PORT
      LAYER M5 ;
        RECT  45.072 56.076 45.096 56.16 ;
    END
  END i_p[334]
  PIN i_p[335]
    DIRECTION INPUT ;
    USE SIGNAL ;
    PORT
      LAYER M5 ;
        RECT  45.168 56.076 45.192 56.16 ;
    END
  END i_p[335]
  PIN i_p[336]
    DIRECTION INPUT ;
    USE SIGNAL ;
    PORT
      LAYER M5 ;
        RECT  45.264 56.076 45.288 56.16 ;
    END
  END i_p[336]
  PIN i_p[337]
    DIRECTION INPUT ;
    USE SIGNAL ;
    PORT
      LAYER M5 ;
        RECT  45.36 56.076 45.384 56.16 ;
    END
  END i_p[337]
  PIN i_p[338]
    DIRECTION INPUT ;
    USE SIGNAL ;
    PORT
      LAYER M5 ;
        RECT  45.456 56.076 45.48 56.16 ;
    END
  END i_p[338]
  PIN i_p[339]
    DIRECTION INPUT ;
    USE SIGNAL ;
    PORT
      LAYER M5 ;
        RECT  45.552 56.076 45.576 56.16 ;
    END
  END i_p[339]
  PIN i_p[33]
    DIRECTION INPUT ;
    USE SIGNAL ;
    PORT
      LAYER M5 ;
        RECT  5.424 56.076 5.448 56.16 ;
    END
  END i_p[33]
  PIN i_p[340]
    DIRECTION INPUT ;
    USE SIGNAL ;
    PORT
      LAYER M5 ;
        RECT  45.648 56.076 45.672 56.16 ;
    END
  END i_p[340]
  PIN i_p[341]
    DIRECTION INPUT ;
    USE SIGNAL ;
    PORT
      LAYER M5 ;
        RECT  45.744 56.076 45.768 56.16 ;
    END
  END i_p[341]
  PIN i_p[342]
    DIRECTION INPUT ;
    USE SIGNAL ;
    PORT
      LAYER M5 ;
        RECT  45.84 56.076 45.864 56.16 ;
    END
  END i_p[342]
  PIN i_p[343]
    DIRECTION INPUT ;
    USE SIGNAL ;
    PORT
      LAYER M5 ;
        RECT  45.936 56.076 45.96 56.16 ;
    END
  END i_p[343]
  PIN i_p[344]
    DIRECTION INPUT ;
    USE SIGNAL ;
    PORT
      LAYER M5 ;
        RECT  46.032 56.076 46.056 56.16 ;
    END
  END i_p[344]
  PIN i_p[345]
    DIRECTION INPUT ;
    USE SIGNAL ;
    PORT
      LAYER M5 ;
        RECT  46.128 56.076 46.152 56.16 ;
    END
  END i_p[345]
  PIN i_p[346]
    DIRECTION INPUT ;
    USE SIGNAL ;
    PORT
      LAYER M5 ;
        RECT  46.224 56.076 46.248 56.16 ;
    END
  END i_p[346]
  PIN i_p[347]
    DIRECTION INPUT ;
    USE SIGNAL ;
    PORT
      LAYER M5 ;
        RECT  46.32 56.076 46.344 56.16 ;
    END
  END i_p[347]
  PIN i_p[348]
    DIRECTION INPUT ;
    USE SIGNAL ;
    PORT
      LAYER M5 ;
        RECT  46.416 56.076 46.44 56.16 ;
    END
  END i_p[348]
  PIN i_p[349]
    DIRECTION INPUT ;
    USE SIGNAL ;
    PORT
      LAYER M5 ;
        RECT  46.512 56.076 46.536 56.16 ;
    END
  END i_p[349]
  PIN i_p[34]
    DIRECTION INPUT ;
    USE SIGNAL ;
    PORT
      LAYER M5 ;
        RECT  5.52 56.076 5.544 56.16 ;
    END
  END i_p[34]
  PIN i_p[350]
    DIRECTION INPUT ;
    USE SIGNAL ;
    PORT
      LAYER M5 ;
        RECT  37.392 56.076 37.416 56.16 ;
    END
  END i_p[350]
  PIN i_p[351]
    DIRECTION INPUT ;
    USE SIGNAL ;
    PORT
      LAYER M5 ;
        RECT  37.488 56.076 37.512 56.16 ;
    END
  END i_p[351]
  PIN i_p[352]
    DIRECTION INPUT ;
    USE SIGNAL ;
    PORT
      LAYER M5 ;
        RECT  37.584 56.076 37.608 56.16 ;
    END
  END i_p[352]
  PIN i_p[353]
    DIRECTION INPUT ;
    USE SIGNAL ;
    PORT
      LAYER M5 ;
        RECT  37.68 56.076 37.704 56.16 ;
    END
  END i_p[353]
  PIN i_p[354]
    DIRECTION INPUT ;
    USE SIGNAL ;
    PORT
      LAYER M5 ;
        RECT  37.776 56.076 37.8 56.16 ;
    END
  END i_p[354]
  PIN i_p[355]
    DIRECTION INPUT ;
    USE SIGNAL ;
    PORT
      LAYER M5 ;
        RECT  37.872 56.076 37.896 56.16 ;
    END
  END i_p[355]
  PIN i_p[356]
    DIRECTION INPUT ;
    USE SIGNAL ;
    PORT
      LAYER M5 ;
        RECT  37.968 56.076 37.992 56.16 ;
    END
  END i_p[356]
  PIN i_p[357]
    DIRECTION INPUT ;
    USE SIGNAL ;
    PORT
      LAYER M5 ;
        RECT  38.064 56.076 38.088 56.16 ;
    END
  END i_p[357]
  PIN i_p[358]
    DIRECTION INPUT ;
    USE SIGNAL ;
    PORT
      LAYER M5 ;
        RECT  38.16 56.076 38.184 56.16 ;
    END
  END i_p[358]
  PIN i_p[359]
    DIRECTION INPUT ;
    USE SIGNAL ;
    PORT
      LAYER M5 ;
        RECT  38.256 56.076 38.28 56.16 ;
    END
  END i_p[359]
  PIN i_p[35]
    DIRECTION INPUT ;
    USE SIGNAL ;
    PORT
      LAYER M5 ;
        RECT  5.616 56.076 5.64 56.16 ;
    END
  END i_p[35]
  PIN i_p[360]
    DIRECTION INPUT ;
    USE SIGNAL ;
    PORT
      LAYER M5 ;
        RECT  38.352 56.076 38.376 56.16 ;
    END
  END i_p[360]
  PIN i_p[361]
    DIRECTION INPUT ;
    USE SIGNAL ;
    PORT
      LAYER M5 ;
        RECT  38.448 56.076 38.472 56.16 ;
    END
  END i_p[361]
  PIN i_p[362]
    DIRECTION INPUT ;
    USE SIGNAL ;
    PORT
      LAYER M5 ;
        RECT  38.544 56.076 38.568 56.16 ;
    END
  END i_p[362]
  PIN i_p[363]
    DIRECTION INPUT ;
    USE SIGNAL ;
    PORT
      LAYER M5 ;
        RECT  38.64 56.076 38.664 56.16 ;
    END
  END i_p[363]
  PIN i_p[364]
    DIRECTION INPUT ;
    USE SIGNAL ;
    PORT
      LAYER M5 ;
        RECT  38.736 56.076 38.76 56.16 ;
    END
  END i_p[364]
  PIN i_p[365]
    DIRECTION INPUT ;
    USE SIGNAL ;
    PORT
      LAYER M5 ;
        RECT  38.832 56.076 38.856 56.16 ;
    END
  END i_p[365]
  PIN i_p[366]
    DIRECTION INPUT ;
    USE SIGNAL ;
    PORT
      LAYER M5 ;
        RECT  38.928 56.076 38.952 56.16 ;
    END
  END i_p[366]
  PIN i_p[367]
    DIRECTION INPUT ;
    USE SIGNAL ;
    PORT
      LAYER M5 ;
        RECT  39.024 56.076 39.048 56.16 ;
    END
  END i_p[367]
  PIN i_p[368]
    DIRECTION INPUT ;
    USE SIGNAL ;
    PORT
      LAYER M5 ;
        RECT  39.12 56.076 39.144 56.16 ;
    END
  END i_p[368]
  PIN i_p[369]
    DIRECTION INPUT ;
    USE SIGNAL ;
    PORT
      LAYER M5 ;
        RECT  39.216 56.076 39.24 56.16 ;
    END
  END i_p[369]
  PIN i_p[36]
    DIRECTION INPUT ;
    USE SIGNAL ;
    PORT
      LAYER M5 ;
        RECT  5.712 56.076 5.736 56.16 ;
    END
  END i_p[36]
  PIN i_p[370]
    DIRECTION INPUT ;
    USE SIGNAL ;
    PORT
      LAYER M5 ;
        RECT  39.312 56.076 39.336 56.16 ;
    END
  END i_p[370]
  PIN i_p[371]
    DIRECTION INPUT ;
    USE SIGNAL ;
    PORT
      LAYER M5 ;
        RECT  39.408 56.076 39.432 56.16 ;
    END
  END i_p[371]
  PIN i_p[372]
    DIRECTION INPUT ;
    USE SIGNAL ;
    PORT
      LAYER M5 ;
        RECT  39.504 56.076 39.528 56.16 ;
    END
  END i_p[372]
  PIN i_p[373]
    DIRECTION INPUT ;
    USE SIGNAL ;
    PORT
      LAYER M5 ;
        RECT  39.6 56.076 39.624 56.16 ;
    END
  END i_p[373]
  PIN i_p[374]
    DIRECTION INPUT ;
    USE SIGNAL ;
    PORT
      LAYER M5 ;
        RECT  39.696 56.076 39.72 56.16 ;
    END
  END i_p[374]
  PIN i_p[375]
    DIRECTION INPUT ;
    USE SIGNAL ;
    PORT
      LAYER M5 ;
        RECT  39.792 56.076 39.816 56.16 ;
    END
  END i_p[375]
  PIN i_p[376]
    DIRECTION INPUT ;
    USE SIGNAL ;
    PORT
      LAYER M5 ;
        RECT  39.888 56.076 39.912 56.16 ;
    END
  END i_p[376]
  PIN i_p[377]
    DIRECTION INPUT ;
    USE SIGNAL ;
    PORT
      LAYER M5 ;
        RECT  39.984 56.076 40.008 56.16 ;
    END
  END i_p[377]
  PIN i_p[378]
    DIRECTION INPUT ;
    USE SIGNAL ;
    PORT
      LAYER M5 ;
        RECT  40.08 56.076 40.104 56.16 ;
    END
  END i_p[378]
  PIN i_p[379]
    DIRECTION INPUT ;
    USE SIGNAL ;
    PORT
      LAYER M5 ;
        RECT  40.176 56.076 40.2 56.16 ;
    END
  END i_p[379]
  PIN i_p[37]
    DIRECTION INPUT ;
    USE SIGNAL ;
    PORT
      LAYER M5 ;
        RECT  5.808 56.076 5.832 56.16 ;
    END
  END i_p[37]
  PIN i_p[380]
    DIRECTION INPUT ;
    USE SIGNAL ;
    PORT
      LAYER M5 ;
        RECT  40.272 56.076 40.296 56.16 ;
    END
  END i_p[380]
  PIN i_p[381]
    DIRECTION INPUT ;
    USE SIGNAL ;
    PORT
      LAYER M5 ;
        RECT  40.368 56.076 40.392 56.16 ;
    END
  END i_p[381]
  PIN i_p[382]
    DIRECTION INPUT ;
    USE SIGNAL ;
    PORT
      LAYER M5 ;
        RECT  34.32 56.076 34.344 56.16 ;
    END
  END i_p[382]
  PIN i_p[383]
    DIRECTION INPUT ;
    USE SIGNAL ;
    PORT
      LAYER M5 ;
        RECT  34.416 56.076 34.44 56.16 ;
    END
  END i_p[383]
  PIN i_p[384]
    DIRECTION INPUT ;
    USE SIGNAL ;
    PORT
      LAYER M5 ;
        RECT  34.512 56.076 34.536 56.16 ;
    END
  END i_p[384]
  PIN i_p[385]
    DIRECTION INPUT ;
    USE SIGNAL ;
    PORT
      LAYER M5 ;
        RECT  34.608 56.076 34.632 56.16 ;
    END
  END i_p[385]
  PIN i_p[386]
    DIRECTION INPUT ;
    USE SIGNAL ;
    PORT
      LAYER M5 ;
        RECT  34.704 56.076 34.728 56.16 ;
    END
  END i_p[386]
  PIN i_p[387]
    DIRECTION INPUT ;
    USE SIGNAL ;
    PORT
      LAYER M5 ;
        RECT  34.8 56.076 34.824 56.16 ;
    END
  END i_p[387]
  PIN i_p[388]
    DIRECTION INPUT ;
    USE SIGNAL ;
    PORT
      LAYER M5 ;
        RECT  34.896 56.076 34.92 56.16 ;
    END
  END i_p[388]
  PIN i_p[389]
    DIRECTION INPUT ;
    USE SIGNAL ;
    PORT
      LAYER M5 ;
        RECT  34.992 56.076 35.016 56.16 ;
    END
  END i_p[389]
  PIN i_p[38]
    DIRECTION INPUT ;
    USE SIGNAL ;
    PORT
      LAYER M5 ;
        RECT  5.904 56.076 5.928 56.16 ;
    END
  END i_p[38]
  PIN i_p[390]
    DIRECTION INPUT ;
    USE SIGNAL ;
    PORT
      LAYER M5 ;
        RECT  35.088 56.076 35.112 56.16 ;
    END
  END i_p[390]
  PIN i_p[391]
    DIRECTION INPUT ;
    USE SIGNAL ;
    PORT
      LAYER M5 ;
        RECT  35.184 56.076 35.208 56.16 ;
    END
  END i_p[391]
  PIN i_p[392]
    DIRECTION INPUT ;
    USE SIGNAL ;
    PORT
      LAYER M5 ;
        RECT  35.28 56.076 35.304 56.16 ;
    END
  END i_p[392]
  PIN i_p[393]
    DIRECTION INPUT ;
    USE SIGNAL ;
    PORT
      LAYER M5 ;
        RECT  35.376 56.076 35.4 56.16 ;
    END
  END i_p[393]
  PIN i_p[394]
    DIRECTION INPUT ;
    USE SIGNAL ;
    PORT
      LAYER M5 ;
        RECT  35.472 56.076 35.496 56.16 ;
    END
  END i_p[394]
  PIN i_p[395]
    DIRECTION INPUT ;
    USE SIGNAL ;
    PORT
      LAYER M5 ;
        RECT  35.568 56.076 35.592 56.16 ;
    END
  END i_p[395]
  PIN i_p[396]
    DIRECTION INPUT ;
    USE SIGNAL ;
    PORT
      LAYER M5 ;
        RECT  35.664 56.076 35.688 56.16 ;
    END
  END i_p[396]
  PIN i_p[397]
    DIRECTION INPUT ;
    USE SIGNAL ;
    PORT
      LAYER M5 ;
        RECT  35.76 56.076 35.784 56.16 ;
    END
  END i_p[397]
  PIN i_p[398]
    DIRECTION INPUT ;
    USE SIGNAL ;
    PORT
      LAYER M5 ;
        RECT  35.856 56.076 35.88 56.16 ;
    END
  END i_p[398]
  PIN i_p[399]
    DIRECTION INPUT ;
    USE SIGNAL ;
    PORT
      LAYER M5 ;
        RECT  35.952 56.076 35.976 56.16 ;
    END
  END i_p[399]
  PIN i_p[39]
    DIRECTION INPUT ;
    USE SIGNAL ;
    PORT
      LAYER M5 ;
        RECT  6 56.076 6.024 56.16 ;
    END
  END i_p[39]
  PIN i_p[3]
    DIRECTION INPUT ;
    USE SIGNAL ;
    PORT
      LAYER M5 ;
        RECT  8.688 56.076 8.712 56.16 ;
    END
  END i_p[3]
  PIN i_p[400]
    DIRECTION INPUT ;
    USE SIGNAL ;
    PORT
      LAYER M5 ;
        RECT  36.048 56.076 36.072 56.16 ;
    END
  END i_p[400]
  PIN i_p[401]
    DIRECTION INPUT ;
    USE SIGNAL ;
    PORT
      LAYER M5 ;
        RECT  36.144 56.076 36.168 56.16 ;
    END
  END i_p[401]
  PIN i_p[402]
    DIRECTION INPUT ;
    USE SIGNAL ;
    PORT
      LAYER M5 ;
        RECT  36.24 56.076 36.264 56.16 ;
    END
  END i_p[402]
  PIN i_p[403]
    DIRECTION INPUT ;
    USE SIGNAL ;
    PORT
      LAYER M5 ;
        RECT  36.336 56.076 36.36 56.16 ;
    END
  END i_p[403]
  PIN i_p[404]
    DIRECTION INPUT ;
    USE SIGNAL ;
    PORT
      LAYER M5 ;
        RECT  36.432 56.076 36.456 56.16 ;
    END
  END i_p[404]
  PIN i_p[405]
    DIRECTION INPUT ;
    USE SIGNAL ;
    PORT
      LAYER M5 ;
        RECT  36.528 56.076 36.552 56.16 ;
    END
  END i_p[405]
  PIN i_p[406]
    DIRECTION INPUT ;
    USE SIGNAL ;
    PORT
      LAYER M5 ;
        RECT  36.624 56.076 36.648 56.16 ;
    END
  END i_p[406]
  PIN i_p[407]
    DIRECTION INPUT ;
    USE SIGNAL ;
    PORT
      LAYER M5 ;
        RECT  36.72 56.076 36.744 56.16 ;
    END
  END i_p[407]
  PIN i_p[408]
    DIRECTION INPUT ;
    USE SIGNAL ;
    PORT
      LAYER M5 ;
        RECT  36.816 56.076 36.84 56.16 ;
    END
  END i_p[408]
  PIN i_p[409]
    DIRECTION INPUT ;
    USE SIGNAL ;
    PORT
      LAYER M5 ;
        RECT  36.912 56.076 36.936 56.16 ;
    END
  END i_p[409]
  PIN i_p[40]
    DIRECTION INPUT ;
    USE SIGNAL ;
    PORT
      LAYER M5 ;
        RECT  6.096 56.076 6.12 56.16 ;
    END
  END i_p[40]
  PIN i_p[410]
    DIRECTION INPUT ;
    USE SIGNAL ;
    PORT
      LAYER M5 ;
        RECT  37.008 56.076 37.032 56.16 ;
    END
  END i_p[410]
  PIN i_p[411]
    DIRECTION INPUT ;
    USE SIGNAL ;
    PORT
      LAYER M5 ;
        RECT  37.104 56.076 37.128 56.16 ;
    END
  END i_p[411]
  PIN i_p[412]
    DIRECTION INPUT ;
    USE SIGNAL ;
    PORT
      LAYER M5 ;
        RECT  37.2 56.076 37.224 56.16 ;
    END
  END i_p[412]
  PIN i_p[413]
    DIRECTION INPUT ;
    USE SIGNAL ;
    PORT
      LAYER M5 ;
        RECT  37.296 56.076 37.32 56.16 ;
    END
  END i_p[413]
  PIN i_p[414]
    DIRECTION INPUT ;
    USE SIGNAL ;
    PORT
      LAYER M5 ;
        RECT  31.248 56.076 31.272 56.16 ;
    END
  END i_p[414]
  PIN i_p[415]
    DIRECTION INPUT ;
    USE SIGNAL ;
    PORT
      LAYER M5 ;
        RECT  31.344 56.076 31.368 56.16 ;
    END
  END i_p[415]
  PIN i_p[416]
    DIRECTION INPUT ;
    USE SIGNAL ;
    PORT
      LAYER M5 ;
        RECT  31.44 56.076 31.464 56.16 ;
    END
  END i_p[416]
  PIN i_p[417]
    DIRECTION INPUT ;
    USE SIGNAL ;
    PORT
      LAYER M5 ;
        RECT  31.536 56.076 31.56 56.16 ;
    END
  END i_p[417]
  PIN i_p[418]
    DIRECTION INPUT ;
    USE SIGNAL ;
    PORT
      LAYER M5 ;
        RECT  31.632 56.076 31.656 56.16 ;
    END
  END i_p[418]
  PIN i_p[419]
    DIRECTION INPUT ;
    USE SIGNAL ;
    PORT
      LAYER M5 ;
        RECT  31.728 56.076 31.752 56.16 ;
    END
  END i_p[419]
  PIN i_p[41]
    DIRECTION INPUT ;
    USE SIGNAL ;
    PORT
      LAYER M5 ;
        RECT  6.192 56.076 6.216 56.16 ;
    END
  END i_p[41]
  PIN i_p[420]
    DIRECTION INPUT ;
    USE SIGNAL ;
    PORT
      LAYER M5 ;
        RECT  31.824 56.076 31.848 56.16 ;
    END
  END i_p[420]
  PIN i_p[421]
    DIRECTION INPUT ;
    USE SIGNAL ;
    PORT
      LAYER M5 ;
        RECT  31.92 56.076 31.944 56.16 ;
    END
  END i_p[421]
  PIN i_p[422]
    DIRECTION INPUT ;
    USE SIGNAL ;
    PORT
      LAYER M5 ;
        RECT  32.016 56.076 32.04 56.16 ;
    END
  END i_p[422]
  PIN i_p[423]
    DIRECTION INPUT ;
    USE SIGNAL ;
    PORT
      LAYER M5 ;
        RECT  32.112 56.076 32.136 56.16 ;
    END
  END i_p[423]
  PIN i_p[424]
    DIRECTION INPUT ;
    USE SIGNAL ;
    PORT
      LAYER M5 ;
        RECT  32.208 56.076 32.232 56.16 ;
    END
  END i_p[424]
  PIN i_p[425]
    DIRECTION INPUT ;
    USE SIGNAL ;
    PORT
      LAYER M5 ;
        RECT  32.304 56.076 32.328 56.16 ;
    END
  END i_p[425]
  PIN i_p[426]
    DIRECTION INPUT ;
    USE SIGNAL ;
    PORT
      LAYER M5 ;
        RECT  32.4 56.076 32.424 56.16 ;
    END
  END i_p[426]
  PIN i_p[427]
    DIRECTION INPUT ;
    USE SIGNAL ;
    PORT
      LAYER M5 ;
        RECT  32.496 56.076 32.52 56.16 ;
    END
  END i_p[427]
  PIN i_p[428]
    DIRECTION INPUT ;
    USE SIGNAL ;
    PORT
      LAYER M5 ;
        RECT  32.592 56.076 32.616 56.16 ;
    END
  END i_p[428]
  PIN i_p[429]
    DIRECTION INPUT ;
    USE SIGNAL ;
    PORT
      LAYER M5 ;
        RECT  32.688 56.076 32.712 56.16 ;
    END
  END i_p[429]
  PIN i_p[42]
    DIRECTION INPUT ;
    USE SIGNAL ;
    PORT
      LAYER M5 ;
        RECT  6.288 56.076 6.312 56.16 ;
    END
  END i_p[42]
  PIN i_p[430]
    DIRECTION INPUT ;
    USE SIGNAL ;
    PORT
      LAYER M5 ;
        RECT  32.784 56.076 32.808 56.16 ;
    END
  END i_p[430]
  PIN i_p[431]
    DIRECTION INPUT ;
    USE SIGNAL ;
    PORT
      LAYER M5 ;
        RECT  32.88 56.076 32.904 56.16 ;
    END
  END i_p[431]
  PIN i_p[432]
    DIRECTION INPUT ;
    USE SIGNAL ;
    PORT
      LAYER M5 ;
        RECT  32.976 56.076 33 56.16 ;
    END
  END i_p[432]
  PIN i_p[433]
    DIRECTION INPUT ;
    USE SIGNAL ;
    PORT
      LAYER M5 ;
        RECT  33.072 56.076 33.096 56.16 ;
    END
  END i_p[433]
  PIN i_p[434]
    DIRECTION INPUT ;
    USE SIGNAL ;
    PORT
      LAYER M5 ;
        RECT  33.168 56.076 33.192 56.16 ;
    END
  END i_p[434]
  PIN i_p[435]
    DIRECTION INPUT ;
    USE SIGNAL ;
    PORT
      LAYER M5 ;
        RECT  33.264 56.076 33.288 56.16 ;
    END
  END i_p[435]
  PIN i_p[436]
    DIRECTION INPUT ;
    USE SIGNAL ;
    PORT
      LAYER M5 ;
        RECT  33.36 56.076 33.384 56.16 ;
    END
  END i_p[436]
  PIN i_p[437]
    DIRECTION INPUT ;
    USE SIGNAL ;
    PORT
      LAYER M5 ;
        RECT  33.456 56.076 33.48 56.16 ;
    END
  END i_p[437]
  PIN i_p[438]
    DIRECTION INPUT ;
    USE SIGNAL ;
    PORT
      LAYER M5 ;
        RECT  33.552 56.076 33.576 56.16 ;
    END
  END i_p[438]
  PIN i_p[439]
    DIRECTION INPUT ;
    USE SIGNAL ;
    PORT
      LAYER M5 ;
        RECT  33.648 56.076 33.672 56.16 ;
    END
  END i_p[439]
  PIN i_p[43]
    DIRECTION INPUT ;
    USE SIGNAL ;
    PORT
      LAYER M5 ;
        RECT  6.384 56.076 6.408 56.16 ;
    END
  END i_p[43]
  PIN i_p[440]
    DIRECTION INPUT ;
    USE SIGNAL ;
    PORT
      LAYER M5 ;
        RECT  33.744 56.076 33.768 56.16 ;
    END
  END i_p[440]
  PIN i_p[441]
    DIRECTION INPUT ;
    USE SIGNAL ;
    PORT
      LAYER M5 ;
        RECT  33.84 56.076 33.864 56.16 ;
    END
  END i_p[441]
  PIN i_p[442]
    DIRECTION INPUT ;
    USE SIGNAL ;
    PORT
      LAYER M5 ;
        RECT  33.936 56.076 33.96 56.16 ;
    END
  END i_p[442]
  PIN i_p[443]
    DIRECTION INPUT ;
    USE SIGNAL ;
    PORT
      LAYER M5 ;
        RECT  34.032 56.076 34.056 56.16 ;
    END
  END i_p[443]
  PIN i_p[444]
    DIRECTION INPUT ;
    USE SIGNAL ;
    PORT
      LAYER M5 ;
        RECT  34.128 56.076 34.152 56.16 ;
    END
  END i_p[444]
  PIN i_p[445]
    DIRECTION INPUT ;
    USE SIGNAL ;
    PORT
      LAYER M5 ;
        RECT  34.224 56.076 34.248 56.16 ;
    END
  END i_p[445]
  PIN i_p[446]
    DIRECTION INPUT ;
    USE SIGNAL ;
    PORT
      LAYER M5 ;
        RECT  40.464 56.076 40.488 56.16 ;
    END
  END i_p[446]
  PIN i_p[447]
    DIRECTION INPUT ;
    USE SIGNAL ;
    PORT
      LAYER M5 ;
        RECT  40.56 56.076 40.584 56.16 ;
    END
  END i_p[447]
  PIN i_p[448]
    DIRECTION INPUT ;
    USE SIGNAL ;
    PORT
      LAYER M5 ;
        RECT  40.656 56.076 40.68 56.16 ;
    END
  END i_p[448]
  PIN i_p[449]
    DIRECTION INPUT ;
    USE SIGNAL ;
    PORT
      LAYER M5 ;
        RECT  40.752 56.076 40.776 56.16 ;
    END
  END i_p[449]
  PIN i_p[44]
    DIRECTION INPUT ;
    USE SIGNAL ;
    PORT
      LAYER M5 ;
        RECT  6.48 56.076 6.504 56.16 ;
    END
  END i_p[44]
  PIN i_p[450]
    DIRECTION INPUT ;
    USE SIGNAL ;
    PORT
      LAYER M5 ;
        RECT  40.848 56.076 40.872 56.16 ;
    END
  END i_p[450]
  PIN i_p[451]
    DIRECTION INPUT ;
    USE SIGNAL ;
    PORT
      LAYER M5 ;
        RECT  40.944 56.076 40.968 56.16 ;
    END
  END i_p[451]
  PIN i_p[452]
    DIRECTION INPUT ;
    USE SIGNAL ;
    PORT
      LAYER M5 ;
        RECT  41.04 56.076 41.064 56.16 ;
    END
  END i_p[452]
  PIN i_p[453]
    DIRECTION INPUT ;
    USE SIGNAL ;
    PORT
      LAYER M5 ;
        RECT  41.136 56.076 41.16 56.16 ;
    END
  END i_p[453]
  PIN i_p[454]
    DIRECTION INPUT ;
    USE SIGNAL ;
    PORT
      LAYER M5 ;
        RECT  41.232 56.076 41.256 56.16 ;
    END
  END i_p[454]
  PIN i_p[455]
    DIRECTION INPUT ;
    USE SIGNAL ;
    PORT
      LAYER M5 ;
        RECT  41.328 56.076 41.352 56.16 ;
    END
  END i_p[455]
  PIN i_p[456]
    DIRECTION INPUT ;
    USE SIGNAL ;
    PORT
      LAYER M5 ;
        RECT  41.424 56.076 41.448 56.16 ;
    END
  END i_p[456]
  PIN i_p[457]
    DIRECTION INPUT ;
    USE SIGNAL ;
    PORT
      LAYER M5 ;
        RECT  41.52 56.076 41.544 56.16 ;
    END
  END i_p[457]
  PIN i_p[458]
    DIRECTION INPUT ;
    USE SIGNAL ;
    PORT
      LAYER M5 ;
        RECT  41.616 56.076 41.64 56.16 ;
    END
  END i_p[458]
  PIN i_p[459]
    DIRECTION INPUT ;
    USE SIGNAL ;
    PORT
      LAYER M5 ;
        RECT  41.712 56.076 41.736 56.16 ;
    END
  END i_p[459]
  PIN i_p[45]
    DIRECTION INPUT ;
    USE SIGNAL ;
    PORT
      LAYER M5 ;
        RECT  6.576 56.076 6.6 56.16 ;
    END
  END i_p[45]
  PIN i_p[460]
    DIRECTION INPUT ;
    USE SIGNAL ;
    PORT
      LAYER M5 ;
        RECT  41.808 56.076 41.832 56.16 ;
    END
  END i_p[460]
  PIN i_p[461]
    DIRECTION INPUT ;
    USE SIGNAL ;
    PORT
      LAYER M5 ;
        RECT  41.904 56.076 41.928 56.16 ;
    END
  END i_p[461]
  PIN i_p[462]
    DIRECTION INPUT ;
    USE SIGNAL ;
    PORT
      LAYER M5 ;
        RECT  42 56.076 42.024 56.16 ;
    END
  END i_p[462]
  PIN i_p[463]
    DIRECTION INPUT ;
    USE SIGNAL ;
    PORT
      LAYER M5 ;
        RECT  42.096 56.076 42.12 56.16 ;
    END
  END i_p[463]
  PIN i_p[464]
    DIRECTION INPUT ;
    USE SIGNAL ;
    PORT
      LAYER M5 ;
        RECT  42.192 56.076 42.216 56.16 ;
    END
  END i_p[464]
  PIN i_p[465]
    DIRECTION INPUT ;
    USE SIGNAL ;
    PORT
      LAYER M5 ;
        RECT  42.288 56.076 42.312 56.16 ;
    END
  END i_p[465]
  PIN i_p[466]
    DIRECTION INPUT ;
    USE SIGNAL ;
    PORT
      LAYER M5 ;
        RECT  42.384 56.076 42.408 56.16 ;
    END
  END i_p[466]
  PIN i_p[467]
    DIRECTION INPUT ;
    USE SIGNAL ;
    PORT
      LAYER M5 ;
        RECT  42.48 56.076 42.504 56.16 ;
    END
  END i_p[467]
  PIN i_p[468]
    DIRECTION INPUT ;
    USE SIGNAL ;
    PORT
      LAYER M5 ;
        RECT  42.576 56.076 42.6 56.16 ;
    END
  END i_p[468]
  PIN i_p[469]
    DIRECTION INPUT ;
    USE SIGNAL ;
    PORT
      LAYER M5 ;
        RECT  42.672 56.076 42.696 56.16 ;
    END
  END i_p[469]
  PIN i_p[46]
    DIRECTION INPUT ;
    USE SIGNAL ;
    PORT
      LAYER M5 ;
        RECT  6.672 56.076 6.696 56.16 ;
    END
  END i_p[46]
  PIN i_p[470]
    DIRECTION INPUT ;
    USE SIGNAL ;
    PORT
      LAYER M5 ;
        RECT  42.768 56.076 42.792 56.16 ;
    END
  END i_p[470]
  PIN i_p[471]
    DIRECTION INPUT ;
    USE SIGNAL ;
    PORT
      LAYER M5 ;
        RECT  42.864 56.076 42.888 56.16 ;
    END
  END i_p[471]
  PIN i_p[472]
    DIRECTION INPUT ;
    USE SIGNAL ;
    PORT
      LAYER M5 ;
        RECT  42.96 56.076 42.984 56.16 ;
    END
  END i_p[472]
  PIN i_p[473]
    DIRECTION INPUT ;
    USE SIGNAL ;
    PORT
      LAYER M5 ;
        RECT  43.056 56.076 43.08 56.16 ;
    END
  END i_p[473]
  PIN i_p[474]
    DIRECTION INPUT ;
    USE SIGNAL ;
    PORT
      LAYER M5 ;
        RECT  43.152 56.076 43.176 56.16 ;
    END
  END i_p[474]
  PIN i_p[475]
    DIRECTION INPUT ;
    USE SIGNAL ;
    PORT
      LAYER M5 ;
        RECT  43.248 56.076 43.272 56.16 ;
    END
  END i_p[475]
  PIN i_p[476]
    DIRECTION INPUT ;
    USE SIGNAL ;
    PORT
      LAYER M5 ;
        RECT  43.344 56.076 43.368 56.16 ;
    END
  END i_p[476]
  PIN i_p[477]
    DIRECTION INPUT ;
    USE SIGNAL ;
    PORT
      LAYER M5 ;
        RECT  43.44 56.076 43.464 56.16 ;
    END
  END i_p[477]
  PIN i_p[478]
    DIRECTION INPUT ;
    USE SIGNAL ;
    PORT
      LAYER M5 ;
        RECT  50.448 56.076 50.472 56.16 ;
    END
  END i_p[478]
  PIN i_p[479]
    DIRECTION INPUT ;
    USE SIGNAL ;
    PORT
      LAYER M5 ;
        RECT  50.544 56.076 50.568 56.16 ;
    END
  END i_p[479]
  PIN i_p[47]
    DIRECTION INPUT ;
    USE SIGNAL ;
    PORT
      LAYER M5 ;
        RECT  6.768 56.076 6.792 56.16 ;
    END
  END i_p[47]
  PIN i_p[480]
    DIRECTION INPUT ;
    USE SIGNAL ;
    PORT
      LAYER M5 ;
        RECT  50.64 56.076 50.664 56.16 ;
    END
  END i_p[480]
  PIN i_p[481]
    DIRECTION INPUT ;
    USE SIGNAL ;
    PORT
      LAYER M5 ;
        RECT  50.736 56.076 50.76 56.16 ;
    END
  END i_p[481]
  PIN i_p[482]
    DIRECTION INPUT ;
    USE SIGNAL ;
    PORT
      LAYER M5 ;
        RECT  50.832 56.076 50.856 56.16 ;
    END
  END i_p[482]
  PIN i_p[483]
    DIRECTION INPUT ;
    USE SIGNAL ;
    PORT
      LAYER M5 ;
        RECT  50.928 56.076 50.952 56.16 ;
    END
  END i_p[483]
  PIN i_p[484]
    DIRECTION INPUT ;
    USE SIGNAL ;
    PORT
      LAYER M5 ;
        RECT  51.024 56.076 51.048 56.16 ;
    END
  END i_p[484]
  PIN i_p[485]
    DIRECTION INPUT ;
    USE SIGNAL ;
    PORT
      LAYER M5 ;
        RECT  51.12 56.076 51.144 56.16 ;
    END
  END i_p[485]
  PIN i_p[486]
    DIRECTION INPUT ;
    USE SIGNAL ;
    PORT
      LAYER M5 ;
        RECT  51.216 56.076 51.24 56.16 ;
    END
  END i_p[486]
  PIN i_p[487]
    DIRECTION INPUT ;
    USE SIGNAL ;
    PORT
      LAYER M5 ;
        RECT  51.312 56.076 51.336 56.16 ;
    END
  END i_p[487]
  PIN i_p[488]
    DIRECTION INPUT ;
    USE SIGNAL ;
    PORT
      LAYER M5 ;
        RECT  51.408 56.076 51.432 56.16 ;
    END
  END i_p[488]
  PIN i_p[489]
    DIRECTION INPUT ;
    USE SIGNAL ;
    PORT
      LAYER M5 ;
        RECT  51.504 56.076 51.528 56.16 ;
    END
  END i_p[489]
  PIN i_p[48]
    DIRECTION INPUT ;
    USE SIGNAL ;
    PORT
      LAYER M5 ;
        RECT  6.864 56.076 6.888 56.16 ;
    END
  END i_p[48]
  PIN i_p[490]
    DIRECTION INPUT ;
    USE SIGNAL ;
    PORT
      LAYER M5 ;
        RECT  51.6 56.076 51.624 56.16 ;
    END
  END i_p[490]
  PIN i_p[491]
    DIRECTION INPUT ;
    USE SIGNAL ;
    PORT
      LAYER M5 ;
        RECT  51.696 56.076 51.72 56.16 ;
    END
  END i_p[491]
  PIN i_p[492]
    DIRECTION INPUT ;
    USE SIGNAL ;
    PORT
      LAYER M5 ;
        RECT  51.792 56.076 51.816 56.16 ;
    END
  END i_p[492]
  PIN i_p[493]
    DIRECTION INPUT ;
    USE SIGNAL ;
    PORT
      LAYER M5 ;
        RECT  51.888 56.076 51.912 56.16 ;
    END
  END i_p[493]
  PIN i_p[494]
    DIRECTION INPUT ;
    USE SIGNAL ;
    PORT
      LAYER M5 ;
        RECT  51.984 56.076 52.008 56.16 ;
    END
  END i_p[494]
  PIN i_p[495]
    DIRECTION INPUT ;
    USE SIGNAL ;
    PORT
      LAYER M5 ;
        RECT  52.08 56.076 52.104 56.16 ;
    END
  END i_p[495]
  PIN i_p[496]
    DIRECTION INPUT ;
    USE SIGNAL ;
    PORT
      LAYER M5 ;
        RECT  52.176 56.076 52.2 56.16 ;
    END
  END i_p[496]
  PIN i_p[497]
    DIRECTION INPUT ;
    USE SIGNAL ;
    PORT
      LAYER M5 ;
        RECT  52.272 56.076 52.296 56.16 ;
    END
  END i_p[497]
  PIN i_p[498]
    DIRECTION INPUT ;
    USE SIGNAL ;
    PORT
      LAYER M5 ;
        RECT  52.368 56.076 52.392 56.16 ;
    END
  END i_p[498]
  PIN i_p[499]
    DIRECTION INPUT ;
    USE SIGNAL ;
    PORT
      LAYER M5 ;
        RECT  52.464 56.076 52.488 56.16 ;
    END
  END i_p[499]
  PIN i_p[49]
    DIRECTION INPUT ;
    USE SIGNAL ;
    PORT
      LAYER M5 ;
        RECT  6.96 56.076 6.984 56.16 ;
    END
  END i_p[49]
  PIN i_p[4]
    DIRECTION INPUT ;
    USE SIGNAL ;
    PORT
      LAYER M5 ;
        RECT  8.784 56.076 8.808 56.16 ;
    END
  END i_p[4]
  PIN i_p[500]
    DIRECTION INPUT ;
    USE SIGNAL ;
    PORT
      LAYER M5 ;
        RECT  52.56 56.076 52.584 56.16 ;
    END
  END i_p[500]
  PIN i_p[501]
    DIRECTION INPUT ;
    USE SIGNAL ;
    PORT
      LAYER M5 ;
        RECT  52.656 56.076 52.68 56.16 ;
    END
  END i_p[501]
  PIN i_p[502]
    DIRECTION INPUT ;
    USE SIGNAL ;
    PORT
      LAYER M5 ;
        RECT  52.752 56.076 52.776 56.16 ;
    END
  END i_p[502]
  PIN i_p[503]
    DIRECTION INPUT ;
    USE SIGNAL ;
    PORT
      LAYER M5 ;
        RECT  52.848 56.076 52.872 56.16 ;
    END
  END i_p[503]
  PIN i_p[504]
    DIRECTION INPUT ;
    USE SIGNAL ;
    PORT
      LAYER M5 ;
        RECT  52.944 56.076 52.968 56.16 ;
    END
  END i_p[504]
  PIN i_p[505]
    DIRECTION INPUT ;
    USE SIGNAL ;
    PORT
      LAYER M5 ;
        RECT  53.04 56.076 53.064 56.16 ;
    END
  END i_p[505]
  PIN i_p[506]
    DIRECTION INPUT ;
    USE SIGNAL ;
    PORT
      LAYER M5 ;
        RECT  53.136 56.076 53.16 56.16 ;
    END
  END i_p[506]
  PIN i_p[507]
    DIRECTION INPUT ;
    USE SIGNAL ;
    PORT
      LAYER M5 ;
        RECT  53.232 56.076 53.256 56.16 ;
    END
  END i_p[507]
  PIN i_p[508]
    DIRECTION INPUT ;
    USE SIGNAL ;
    PORT
      LAYER M5 ;
        RECT  53.328 56.076 53.352 56.16 ;
    END
  END i_p[508]
  PIN i_p[509]
    DIRECTION INPUT ;
    USE SIGNAL ;
    PORT
      LAYER M5 ;
        RECT  53.424 56.076 53.448 56.16 ;
    END
  END i_p[509]
  PIN i_p[50]
    DIRECTION INPUT ;
    USE SIGNAL ;
    PORT
      LAYER M5 ;
        RECT  7.056 56.076 7.08 56.16 ;
    END
  END i_p[50]
  PIN i_p[510]
    DIRECTION INPUT ;
    USE SIGNAL ;
    PORT
      LAYER M5 ;
        RECT  53.52 56.076 53.544 56.16 ;
    END
  END i_p[510]
  PIN i_p[511]
    DIRECTION INPUT ;
    USE SIGNAL ;
    PORT
      LAYER M5 ;
        RECT  53.616 56.076 53.64 56.16 ;
    END
  END i_p[511]
  PIN i_p[512]
    DIRECTION INPUT ;
    USE SIGNAL ;
    PORT
      LAYER M5 ;
        RECT  53.712 56.076 53.736 56.16 ;
    END
  END i_p[512]
  PIN i_p[513]
    DIRECTION INPUT ;
    USE SIGNAL ;
    PORT
      LAYER M5 ;
        RECT  53.808 56.076 53.832 56.16 ;
    END
  END i_p[513]
  PIN i_p[514]
    DIRECTION INPUT ;
    USE SIGNAL ;
    PORT
      LAYER M5 ;
        RECT  53.904 56.076 53.928 56.16 ;
    END
  END i_p[514]
  PIN i_p[515]
    DIRECTION INPUT ;
    USE SIGNAL ;
    PORT
      LAYER M5 ;
        RECT  54 56.076 54.024 56.16 ;
    END
  END i_p[515]
  PIN i_p[516]
    DIRECTION INPUT ;
    USE SIGNAL ;
    PORT
      LAYER M5 ;
        RECT  54.096 56.076 54.12 56.16 ;
    END
  END i_p[516]
  PIN i_p[517]
    DIRECTION INPUT ;
    USE SIGNAL ;
    PORT
      LAYER M5 ;
        RECT  54.192 56.076 54.216 56.16 ;
    END
  END i_p[517]
  PIN i_p[518]
    DIRECTION INPUT ;
    USE SIGNAL ;
    PORT
      LAYER M5 ;
        RECT  54.288 56.076 54.312 56.16 ;
    END
  END i_p[518]
  PIN i_p[519]
    DIRECTION INPUT ;
    USE SIGNAL ;
    PORT
      LAYER M5 ;
        RECT  54.384 56.076 54.408 56.16 ;
    END
  END i_p[519]
  PIN i_p[51]
    DIRECTION INPUT ;
    USE SIGNAL ;
    PORT
      LAYER M5 ;
        RECT  7.152 56.076 7.176 56.16 ;
    END
  END i_p[51]
  PIN i_p[520]
    DIRECTION INPUT ;
    USE SIGNAL ;
    PORT
      LAYER M5 ;
        RECT  54.48 56.076 54.504 56.16 ;
    END
  END i_p[520]
  PIN i_p[521]
    DIRECTION INPUT ;
    USE SIGNAL ;
    PORT
      LAYER M5 ;
        RECT  54.576 56.076 54.6 56.16 ;
    END
  END i_p[521]
  PIN i_p[522]
    DIRECTION INPUT ;
    USE SIGNAL ;
    PORT
      LAYER M5 ;
        RECT  54.672 56.076 54.696 56.16 ;
    END
  END i_p[522]
  PIN i_p[523]
    DIRECTION INPUT ;
    USE SIGNAL ;
    PORT
      LAYER M5 ;
        RECT  54.768 56.076 54.792 56.16 ;
    END
  END i_p[523]
  PIN i_p[524]
    DIRECTION INPUT ;
    USE SIGNAL ;
    PORT
      LAYER M5 ;
        RECT  54.864 56.076 54.888 56.16 ;
    END
  END i_p[524]
  PIN i_p[525]
    DIRECTION INPUT ;
    USE SIGNAL ;
    PORT
      LAYER M5 ;
        RECT  54.96 56.076 54.984 56.16 ;
    END
  END i_p[525]
  PIN i_p[526]
    DIRECTION INPUT ;
    USE SIGNAL ;
    PORT
      LAYER M5 ;
        RECT  55.056 56.076 55.08 56.16 ;
    END
  END i_p[526]
  PIN i_p[527]
    DIRECTION INPUT ;
    USE SIGNAL ;
    PORT
      LAYER M5 ;
        RECT  55.152 56.076 55.176 56.16 ;
    END
  END i_p[527]
  PIN i_p[528]
    DIRECTION INPUT ;
    USE SIGNAL ;
    PORT
      LAYER M5 ;
        RECT  55.248 56.076 55.272 56.16 ;
    END
  END i_p[528]
  PIN i_p[529]
    DIRECTION INPUT ;
    USE SIGNAL ;
    PORT
      LAYER M5 ;
        RECT  55.344 56.076 55.368 56.16 ;
    END
  END i_p[529]
  PIN i_p[52]
    DIRECTION INPUT ;
    USE SIGNAL ;
    PORT
      LAYER M5 ;
        RECT  7.248 56.076 7.272 56.16 ;
    END
  END i_p[52]
  PIN i_p[530]
    DIRECTION INPUT ;
    USE SIGNAL ;
    PORT
      LAYER M5 ;
        RECT  55.44 56.076 55.464 56.16 ;
    END
  END i_p[530]
  PIN i_p[531]
    DIRECTION INPUT ;
    USE SIGNAL ;
    PORT
      LAYER M5 ;
        RECT  55.536 56.076 55.56 56.16 ;
    END
  END i_p[531]
  PIN i_p[532]
    DIRECTION INPUT ;
    USE SIGNAL ;
    PORT
      LAYER M5 ;
        RECT  55.632 56.076 55.656 56.16 ;
    END
  END i_p[532]
  PIN i_p[533]
    DIRECTION INPUT ;
    USE SIGNAL ;
    PORT
      LAYER M5 ;
        RECT  55.728 56.076 55.752 56.16 ;
    END
  END i_p[533]
  PIN i_p[534]
    DIRECTION INPUT ;
    USE SIGNAL ;
    PORT
      LAYER M5 ;
        RECT  55.824 56.076 55.848 56.16 ;
    END
  END i_p[534]
  PIN i_p[535]
    DIRECTION INPUT ;
    USE SIGNAL ;
    PORT
      LAYER M5 ;
        RECT  55.92 56.076 55.944 56.16 ;
    END
  END i_p[535]
  PIN i_p[536]
    DIRECTION INPUT ;
    USE SIGNAL ;
    PORT
      LAYER M5 ;
        RECT  56.016 56.076 56.04 56.16 ;
    END
  END i_p[536]
  PIN i_p[537]
    DIRECTION INPUT ;
    USE SIGNAL ;
    PORT
      LAYER M5 ;
        RECT  56.112 56.076 56.136 56.16 ;
    END
  END i_p[537]
  PIN i_p[538]
    DIRECTION INPUT ;
    USE SIGNAL ;
    PORT
      LAYER M5 ;
        RECT  56.208 56.076 56.232 56.16 ;
    END
  END i_p[538]
  PIN i_p[539]
    DIRECTION INPUT ;
    USE SIGNAL ;
    PORT
      LAYER M5 ;
        RECT  56.304 56.076 56.328 56.16 ;
    END
  END i_p[539]
  PIN i_p[53]
    DIRECTION INPUT ;
    USE SIGNAL ;
    PORT
      LAYER M5 ;
        RECT  7.344 56.076 7.368 56.16 ;
    END
  END i_p[53]
  PIN i_p[540]
    DIRECTION INPUT ;
    USE SIGNAL ;
    PORT
      LAYER M5 ;
        RECT  56.4 56.076 56.424 56.16 ;
    END
  END i_p[540]
  PIN i_p[541]
    DIRECTION INPUT ;
    USE SIGNAL ;
    PORT
      LAYER M5 ;
        RECT  56.496 56.076 56.52 56.16 ;
    END
  END i_p[541]
  PIN i_p[542]
    DIRECTION INPUT ;
    USE SIGNAL ;
    PORT
      LAYER M5 ;
        RECT  56.592 56.076 56.616 56.16 ;
    END
  END i_p[542]
  PIN i_p[543]
    DIRECTION INPUT ;
    USE SIGNAL ;
    PORT
      LAYER M5 ;
        RECT  56.688 56.076 56.712 56.16 ;
    END
  END i_p[543]
  PIN i_p[544]
    DIRECTION INPUT ;
    USE SIGNAL ;
    PORT
      LAYER M5 ;
        RECT  56.784 56.076 56.808 56.16 ;
    END
  END i_p[544]
  PIN i_p[545]
    DIRECTION INPUT ;
    USE SIGNAL ;
    PORT
      LAYER M5 ;
        RECT  56.88 56.076 56.904 56.16 ;
    END
  END i_p[545]
  PIN i_p[546]
    DIRECTION INPUT ;
    USE SIGNAL ;
    PORT
      LAYER M5 ;
        RECT  56.976 56.076 57 56.16 ;
    END
  END i_p[546]
  PIN i_p[547]
    DIRECTION INPUT ;
    USE SIGNAL ;
    PORT
      LAYER M5 ;
        RECT  57.072 56.076 57.096 56.16 ;
    END
  END i_p[547]
  PIN i_p[548]
    DIRECTION INPUT ;
    USE SIGNAL ;
    PORT
      LAYER M5 ;
        RECT  57.168 56.076 57.192 56.16 ;
    END
  END i_p[548]
  PIN i_p[549]
    DIRECTION INPUT ;
    USE SIGNAL ;
    PORT
      LAYER M5 ;
        RECT  57.264 56.076 57.288 56.16 ;
    END
  END i_p[549]
  PIN i_p[54]
    DIRECTION INPUT ;
    USE SIGNAL ;
    PORT
      LAYER M5 ;
        RECT  7.44 56.076 7.464 56.16 ;
    END
  END i_p[54]
  PIN i_p[550]
    DIRECTION INPUT ;
    USE SIGNAL ;
    PORT
      LAYER M5 ;
        RECT  57.36 56.076 57.384 56.16 ;
    END
  END i_p[550]
  PIN i_p[551]
    DIRECTION INPUT ;
    USE SIGNAL ;
    PORT
      LAYER M5 ;
        RECT  57.456 56.076 57.48 56.16 ;
    END
  END i_p[551]
  PIN i_p[552]
    DIRECTION INPUT ;
    USE SIGNAL ;
    PORT
      LAYER M5 ;
        RECT  57.552 56.076 57.576 56.16 ;
    END
  END i_p[552]
  PIN i_p[553]
    DIRECTION INPUT ;
    USE SIGNAL ;
    PORT
      LAYER M5 ;
        RECT  57.648 56.076 57.672 56.16 ;
    END
  END i_p[553]
  PIN i_p[554]
    DIRECTION INPUT ;
    USE SIGNAL ;
    PORT
      LAYER M5 ;
        RECT  57.744 56.076 57.768 56.16 ;
    END
  END i_p[554]
  PIN i_p[555]
    DIRECTION INPUT ;
    USE SIGNAL ;
    PORT
      LAYER M5 ;
        RECT  57.84 56.076 57.864 56.16 ;
    END
  END i_p[555]
  PIN i_p[556]
    DIRECTION INPUT ;
    USE SIGNAL ;
    PORT
      LAYER M5 ;
        RECT  57.936 56.076 57.96 56.16 ;
    END
  END i_p[556]
  PIN i_p[557]
    DIRECTION INPUT ;
    USE SIGNAL ;
    PORT
      LAYER M5 ;
        RECT  58.032 56.076 58.056 56.16 ;
    END
  END i_p[557]
  PIN i_p[558]
    DIRECTION INPUT ;
    USE SIGNAL ;
    PORT
      LAYER M5 ;
        RECT  58.128 56.076 58.152 56.16 ;
    END
  END i_p[558]
  PIN i_p[559]
    DIRECTION INPUT ;
    USE SIGNAL ;
    PORT
      LAYER M5 ;
        RECT  58.224 56.076 58.248 56.16 ;
    END
  END i_p[559]
  PIN i_p[55]
    DIRECTION INPUT ;
    USE SIGNAL ;
    PORT
      LAYER M5 ;
        RECT  7.536 56.076 7.56 56.16 ;
    END
  END i_p[55]
  PIN i_p[560]
    DIRECTION INPUT ;
    USE SIGNAL ;
    PORT
      LAYER M5 ;
        RECT  58.32 56.076 58.344 56.16 ;
    END
  END i_p[560]
  PIN i_p[561]
    DIRECTION INPUT ;
    USE SIGNAL ;
    PORT
      LAYER M5 ;
        RECT  58.416 56.076 58.44 56.16 ;
    END
  END i_p[561]
  PIN i_p[562]
    DIRECTION INPUT ;
    USE SIGNAL ;
    PORT
      LAYER M5 ;
        RECT  58.512 56.076 58.536 56.16 ;
    END
  END i_p[562]
  PIN i_p[563]
    DIRECTION INPUT ;
    USE SIGNAL ;
    PORT
      LAYER M5 ;
        RECT  58.608 56.076 58.632 56.16 ;
    END
  END i_p[563]
  PIN i_p[564]
    DIRECTION INPUT ;
    USE SIGNAL ;
    PORT
      LAYER M5 ;
        RECT  58.704 56.076 58.728 56.16 ;
    END
  END i_p[564]
  PIN i_p[565]
    DIRECTION INPUT ;
    USE SIGNAL ;
    PORT
      LAYER M5 ;
        RECT  58.8 56.076 58.824 56.16 ;
    END
  END i_p[565]
  PIN i_p[566]
    DIRECTION INPUT ;
    USE SIGNAL ;
    PORT
      LAYER M5 ;
        RECT  58.896 56.076 58.92 56.16 ;
    END
  END i_p[566]
  PIN i_p[567]
    DIRECTION INPUT ;
    USE SIGNAL ;
    PORT
      LAYER M5 ;
        RECT  58.992 56.076 59.016 56.16 ;
    END
  END i_p[567]
  PIN i_p[568]
    DIRECTION INPUT ;
    USE SIGNAL ;
    PORT
      LAYER M5 ;
        RECT  59.088 56.076 59.112 56.16 ;
    END
  END i_p[568]
  PIN i_p[569]
    DIRECTION INPUT ;
    USE SIGNAL ;
    PORT
      LAYER M5 ;
        RECT  59.184 56.076 59.208 56.16 ;
    END
  END i_p[569]
  PIN i_p[56]
    DIRECTION INPUT ;
    USE SIGNAL ;
    PORT
      LAYER M5 ;
        RECT  7.632 56.076 7.656 56.16 ;
    END
  END i_p[56]
  PIN i_p[570]
    DIRECTION INPUT ;
    USE SIGNAL ;
    PORT
      LAYER M5 ;
        RECT  59.28 56.076 59.304 56.16 ;
    END
  END i_p[570]
  PIN i_p[571]
    DIRECTION INPUT ;
    USE SIGNAL ;
    PORT
      LAYER M5 ;
        RECT  59.376 56.076 59.4 56.16 ;
    END
  END i_p[571]
  PIN i_p[572]
    DIRECTION INPUT ;
    USE SIGNAL ;
    PORT
      LAYER M5 ;
        RECT  59.472 56.076 59.496 56.16 ;
    END
  END i_p[572]
  PIN i_p[573]
    DIRECTION INPUT ;
    USE SIGNAL ;
    PORT
      LAYER M5 ;
        RECT  59.568 56.076 59.592 56.16 ;
    END
  END i_p[573]
  PIN i_p[574]
    DIRECTION INPUT ;
    USE SIGNAL ;
    PORT
      LAYER M5 ;
        RECT  59.664 56.076 59.688 56.16 ;
    END
  END i_p[574]
  PIN i_p[575]
    DIRECTION INPUT ;
    USE SIGNAL ;
    PORT
      LAYER M5 ;
        RECT  59.76 56.076 59.784 56.16 ;
    END
  END i_p[575]
  PIN i_p[576]
    DIRECTION INPUT ;
    USE SIGNAL ;
    PORT
      LAYER M5 ;
        RECT  59.856 56.076 59.88 56.16 ;
    END
  END i_p[576]
  PIN i_p[577]
    DIRECTION INPUT ;
    USE SIGNAL ;
    PORT
      LAYER M5 ;
        RECT  59.952 56.076 59.976 56.16 ;
    END
  END i_p[577]
  PIN i_p[578]
    DIRECTION INPUT ;
    USE SIGNAL ;
    PORT
      LAYER M5 ;
        RECT  60.048 56.076 60.072 56.16 ;
    END
  END i_p[578]
  PIN i_p[579]
    DIRECTION INPUT ;
    USE SIGNAL ;
    PORT
      LAYER M5 ;
        RECT  60.144 56.076 60.168 56.16 ;
    END
  END i_p[579]
  PIN i_p[57]
    DIRECTION INPUT ;
    USE SIGNAL ;
    PORT
      LAYER M5 ;
        RECT  7.728 56.076 7.752 56.16 ;
    END
  END i_p[57]
  PIN i_p[580]
    DIRECTION INPUT ;
    USE SIGNAL ;
    PORT
      LAYER M5 ;
        RECT  60.24 56.076 60.264 56.16 ;
    END
  END i_p[580]
  PIN i_p[581]
    DIRECTION INPUT ;
    USE SIGNAL ;
    PORT
      LAYER M5 ;
        RECT  60.336 56.076 60.36 56.16 ;
    END
  END i_p[581]
  PIN i_p[582]
    DIRECTION INPUT ;
    USE SIGNAL ;
    PORT
      LAYER M5 ;
        RECT  60.432 56.076 60.456 56.16 ;
    END
  END i_p[582]
  PIN i_p[583]
    DIRECTION INPUT ;
    USE SIGNAL ;
    PORT
      LAYER M5 ;
        RECT  60.528 56.076 60.552 56.16 ;
    END
  END i_p[583]
  PIN i_p[584]
    DIRECTION INPUT ;
    USE SIGNAL ;
    PORT
      LAYER M5 ;
        RECT  60.624 56.076 60.648 56.16 ;
    END
  END i_p[584]
  PIN i_p[585]
    DIRECTION INPUT ;
    USE SIGNAL ;
    PORT
      LAYER M5 ;
        RECT  60.72 56.076 60.744 56.16 ;
    END
  END i_p[585]
  PIN i_p[586]
    DIRECTION INPUT ;
    USE SIGNAL ;
    PORT
      LAYER M5 ;
        RECT  60.816 56.076 60.84 56.16 ;
    END
  END i_p[586]
  PIN i_p[587]
    DIRECTION INPUT ;
    USE SIGNAL ;
    PORT
      LAYER M5 ;
        RECT  60.912 56.076 60.936 56.16 ;
    END
  END i_p[587]
  PIN i_p[588]
    DIRECTION INPUT ;
    USE SIGNAL ;
    PORT
      LAYER M5 ;
        RECT  61.008 56.076 61.032 56.16 ;
    END
  END i_p[588]
  PIN i_p[589]
    DIRECTION INPUT ;
    USE SIGNAL ;
    PORT
      LAYER M5 ;
        RECT  61.104 56.076 61.128 56.16 ;
    END
  END i_p[589]
  PIN i_p[58]
    DIRECTION INPUT ;
    USE SIGNAL ;
    PORT
      LAYER M5 ;
        RECT  7.824 56.076 7.848 56.16 ;
    END
  END i_p[58]
  PIN i_p[590]
    DIRECTION INPUT ;
    USE SIGNAL ;
    PORT
      LAYER M5 ;
        RECT  61.2 56.076 61.224 56.16 ;
    END
  END i_p[590]
  PIN i_p[591]
    DIRECTION INPUT ;
    USE SIGNAL ;
    PORT
      LAYER M5 ;
        RECT  61.296 56.076 61.32 56.16 ;
    END
  END i_p[591]
  PIN i_p[59]
    DIRECTION INPUT ;
    USE SIGNAL ;
    PORT
      LAYER M5 ;
        RECT  7.92 56.076 7.944 56.16 ;
    END
  END i_p[59]
  PIN i_p[5]
    DIRECTION INPUT ;
    USE SIGNAL ;
    PORT
      LAYER M5 ;
        RECT  8.88 56.076 8.904 56.16 ;
    END
  END i_p[5]
  PIN i_p[60]
    DIRECTION INPUT ;
    USE SIGNAL ;
    PORT
      LAYER M5 ;
        RECT  8.016 56.076 8.04 56.16 ;
    END
  END i_p[60]
  PIN i_p[61]
    DIRECTION INPUT ;
    USE SIGNAL ;
    PORT
      LAYER M5 ;
        RECT  8.112 56.076 8.136 56.16 ;
    END
  END i_p[61]
  PIN i_p[62]
    DIRECTION INPUT ;
    USE SIGNAL ;
    PORT
      LAYER M5 ;
        RECT  2.064 56.076 2.088 56.16 ;
    END
  END i_p[62]
  PIN i_p[63]
    DIRECTION INPUT ;
    USE SIGNAL ;
    PORT
      LAYER M5 ;
        RECT  2.16 56.076 2.184 56.16 ;
    END
  END i_p[63]
  PIN i_p[64]
    DIRECTION INPUT ;
    USE SIGNAL ;
    PORT
      LAYER M5 ;
        RECT  2.256 56.076 2.28 56.16 ;
    END
  END i_p[64]
  PIN i_p[65]
    DIRECTION INPUT ;
    USE SIGNAL ;
    PORT
      LAYER M5 ;
        RECT  2.352 56.076 2.376 56.16 ;
    END
  END i_p[65]
  PIN i_p[66]
    DIRECTION INPUT ;
    USE SIGNAL ;
    PORT
      LAYER M5 ;
        RECT  2.448 56.076 2.472 56.16 ;
    END
  END i_p[66]
  PIN i_p[67]
    DIRECTION INPUT ;
    USE SIGNAL ;
    PORT
      LAYER M5 ;
        RECT  2.544 56.076 2.568 56.16 ;
    END
  END i_p[67]
  PIN i_p[68]
    DIRECTION INPUT ;
    USE SIGNAL ;
    PORT
      LAYER M5 ;
        RECT  2.64 56.076 2.664 56.16 ;
    END
  END i_p[68]
  PIN i_p[69]
    DIRECTION INPUT ;
    USE SIGNAL ;
    PORT
      LAYER M5 ;
        RECT  2.736 56.076 2.76 56.16 ;
    END
  END i_p[69]
  PIN i_p[6]
    DIRECTION INPUT ;
    USE SIGNAL ;
    PORT
      LAYER M5 ;
        RECT  8.976 56.076 9 56.16 ;
    END
  END i_p[6]
  PIN i_p[70]
    DIRECTION INPUT ;
    USE SIGNAL ;
    PORT
      LAYER M5 ;
        RECT  2.832 56.076 2.856 56.16 ;
    END
  END i_p[70]
  PIN i_p[71]
    DIRECTION INPUT ;
    USE SIGNAL ;
    PORT
      LAYER M5 ;
        RECT  2.928 56.076 2.952 56.16 ;
    END
  END i_p[71]
  PIN i_p[72]
    DIRECTION INPUT ;
    USE SIGNAL ;
    PORT
      LAYER M5 ;
        RECT  3.024 56.076 3.048 56.16 ;
    END
  END i_p[72]
  PIN i_p[73]
    DIRECTION INPUT ;
    USE SIGNAL ;
    PORT
      LAYER M5 ;
        RECT  3.12 56.076 3.144 56.16 ;
    END
  END i_p[73]
  PIN i_p[74]
    DIRECTION INPUT ;
    USE SIGNAL ;
    PORT
      LAYER M5 ;
        RECT  3.216 56.076 3.24 56.16 ;
    END
  END i_p[74]
  PIN i_p[75]
    DIRECTION INPUT ;
    USE SIGNAL ;
    PORT
      LAYER M5 ;
        RECT  3.312 56.076 3.336 56.16 ;
    END
  END i_p[75]
  PIN i_p[76]
    DIRECTION INPUT ;
    USE SIGNAL ;
    PORT
      LAYER M5 ;
        RECT  3.408 56.076 3.432 56.16 ;
    END
  END i_p[76]
  PIN i_p[77]
    DIRECTION INPUT ;
    USE SIGNAL ;
    PORT
      LAYER M5 ;
        RECT  3.504 56.076 3.528 56.16 ;
    END
  END i_p[77]
  PIN i_p[78]
    DIRECTION INPUT ;
    USE SIGNAL ;
    PORT
      LAYER M5 ;
        RECT  3.6 56.076 3.624 56.16 ;
    END
  END i_p[78]
  PIN i_p[79]
    DIRECTION INPUT ;
    USE SIGNAL ;
    PORT
      LAYER M5 ;
        RECT  3.696 56.076 3.72 56.16 ;
    END
  END i_p[79]
  PIN i_p[7]
    DIRECTION INPUT ;
    USE SIGNAL ;
    PORT
      LAYER M5 ;
        RECT  9.072 56.076 9.096 56.16 ;
    END
  END i_p[7]
  PIN i_p[80]
    DIRECTION INPUT ;
    USE SIGNAL ;
    PORT
      LAYER M5 ;
        RECT  3.792 56.076 3.816 56.16 ;
    END
  END i_p[80]
  PIN i_p[81]
    DIRECTION INPUT ;
    USE SIGNAL ;
    PORT
      LAYER M5 ;
        RECT  3.888 56.076 3.912 56.16 ;
    END
  END i_p[81]
  PIN i_p[82]
    DIRECTION INPUT ;
    USE SIGNAL ;
    PORT
      LAYER M5 ;
        RECT  3.984 56.076 4.008 56.16 ;
    END
  END i_p[82]
  PIN i_p[83]
    DIRECTION INPUT ;
    USE SIGNAL ;
    PORT
      LAYER M5 ;
        RECT  4.08 56.076 4.104 56.16 ;
    END
  END i_p[83]
  PIN i_p[84]
    DIRECTION INPUT ;
    USE SIGNAL ;
    PORT
      LAYER M5 ;
        RECT  4.176 56.076 4.2 56.16 ;
    END
  END i_p[84]
  PIN i_p[85]
    DIRECTION INPUT ;
    USE SIGNAL ;
    PORT
      LAYER M5 ;
        RECT  4.272 56.076 4.296 56.16 ;
    END
  END i_p[85]
  PIN i_p[86]
    DIRECTION INPUT ;
    USE SIGNAL ;
    PORT
      LAYER M5 ;
        RECT  4.368 56.076 4.392 56.16 ;
    END
  END i_p[86]
  PIN i_p[87]
    DIRECTION INPUT ;
    USE SIGNAL ;
    PORT
      LAYER M5 ;
        RECT  4.464 56.076 4.488 56.16 ;
    END
  END i_p[87]
  PIN i_p[88]
    DIRECTION INPUT ;
    USE SIGNAL ;
    PORT
      LAYER M5 ;
        RECT  4.56 56.076 4.584 56.16 ;
    END
  END i_p[88]
  PIN i_p[89]
    DIRECTION INPUT ;
    USE SIGNAL ;
    PORT
      LAYER M5 ;
        RECT  4.656 56.076 4.68 56.16 ;
    END
  END i_p[89]
  PIN i_p[8]
    DIRECTION INPUT ;
    USE SIGNAL ;
    PORT
      LAYER M5 ;
        RECT  9.168 56.076 9.192 56.16 ;
    END
  END i_p[8]
  PIN i_p[90]
    DIRECTION INPUT ;
    USE SIGNAL ;
    PORT
      LAYER M5 ;
        RECT  4.752 56.076 4.776 56.16 ;
    END
  END i_p[90]
  PIN i_p[91]
    DIRECTION INPUT ;
    USE SIGNAL ;
    PORT
      LAYER M5 ;
        RECT  4.848 56.076 4.872 56.16 ;
    END
  END i_p[91]
  PIN i_p[92]
    DIRECTION INPUT ;
    USE SIGNAL ;
    PORT
      LAYER M5 ;
        RECT  4.944 56.076 4.968 56.16 ;
    END
  END i_p[92]
  PIN i_p[93]
    DIRECTION INPUT ;
    USE SIGNAL ;
    PORT
      LAYER M5 ;
        RECT  5.04 56.076 5.064 56.16 ;
    END
  END i_p[93]
  PIN i_p[94]
    DIRECTION INPUT ;
    USE SIGNAL ;
    PORT
      LAYER M5 ;
        RECT  12.048 56.076 12.072 56.16 ;
    END
  END i_p[94]
  PIN i_p[95]
    DIRECTION INPUT ;
    USE SIGNAL ;
    PORT
      LAYER M5 ;
        RECT  12.144 56.076 12.168 56.16 ;
    END
  END i_p[95]
  PIN i_p[96]
    DIRECTION INPUT ;
    USE SIGNAL ;
    PORT
      LAYER M5 ;
        RECT  12.24 56.076 12.264 56.16 ;
    END
  END i_p[96]
  PIN i_p[97]
    DIRECTION INPUT ;
    USE SIGNAL ;
    PORT
      LAYER M5 ;
        RECT  12.336 56.076 12.36 56.16 ;
    END
  END i_p[97]
  PIN i_p[98]
    DIRECTION INPUT ;
    USE SIGNAL ;
    PORT
      LAYER M5 ;
        RECT  12.432 56.076 12.456 56.16 ;
    END
  END i_p[98]
  PIN i_p[99]
    DIRECTION INPUT ;
    USE SIGNAL ;
    PORT
      LAYER M5 ;
        RECT  12.528 56.076 12.552 56.16 ;
    END
  END i_p[99]
  PIN i_p[9]
    DIRECTION INPUT ;
    USE SIGNAL ;
    PORT
      LAYER M5 ;
        RECT  9.264 56.076 9.288 56.16 ;
    END
  END i_p[9]
  PIN i_sel[0]
    DIRECTION INPUT ;
    USE SIGNAL ;
    PORT
      LAYER M5 ;
        RECT  61.392 56.076 61.416 56.16 ;
    END
  END i_sel[0]
  PIN i_sel[10]
    DIRECTION INPUT ;
    USE SIGNAL ;
    PORT
      LAYER M5 ;
        RECT  62.352 56.076 62.376 56.16 ;
    END
  END i_sel[10]
  PIN i_sel[11]
    DIRECTION INPUT ;
    USE SIGNAL ;
    PORT
      LAYER M5 ;
        RECT  62.448 56.076 62.472 56.16 ;
    END
  END i_sel[11]
  PIN i_sel[12]
    DIRECTION INPUT ;
    USE SIGNAL ;
    PORT
      LAYER M5 ;
        RECT  62.544 56.076 62.568 56.16 ;
    END
  END i_sel[12]
  PIN i_sel[13]
    DIRECTION INPUT ;
    USE SIGNAL ;
    PORT
      LAYER M5 ;
        RECT  62.64 56.076 62.664 56.16 ;
    END
  END i_sel[13]
  PIN i_sel[14]
    DIRECTION INPUT ;
    USE SIGNAL ;
    PORT
      LAYER M5 ;
        RECT  30.864 56.076 30.888 56.16 ;
    END
  END i_sel[14]
  PIN i_sel[15]
    DIRECTION INPUT ;
    USE SIGNAL ;
    PORT
      LAYER M5 ;
        RECT  30.96 56.076 30.984 56.16 ;
    END
  END i_sel[15]
  PIN i_sel[1]
    DIRECTION INPUT ;
    USE SIGNAL ;
    PORT
      LAYER M5 ;
        RECT  61.488 56.076 61.512 56.16 ;
    END
  END i_sel[1]
  PIN i_sel[2]
    DIRECTION INPUT ;
    USE SIGNAL ;
    PORT
      LAYER M5 ;
        RECT  61.584 56.076 61.608 56.16 ;
    END
  END i_sel[2]
  PIN i_sel[3]
    DIRECTION INPUT ;
    USE SIGNAL ;
    PORT
      LAYER M5 ;
        RECT  61.68 56.076 61.704 56.16 ;
    END
  END i_sel[3]
  PIN i_sel[4]
    DIRECTION INPUT ;
    USE SIGNAL ;
    PORT
      LAYER M5 ;
        RECT  61.776 56.076 61.8 56.16 ;
    END
  END i_sel[4]
  PIN i_sel[5]
    DIRECTION INPUT ;
    USE SIGNAL ;
    PORT
      LAYER M5 ;
        RECT  61.872 56.076 61.896 56.16 ;
    END
  END i_sel[5]
  PIN i_sel[6]
    DIRECTION INPUT ;
    USE SIGNAL ;
    PORT
      LAYER M5 ;
        RECT  61.968 56.076 61.992 56.16 ;
    END
  END i_sel[6]
  PIN i_sel[7]
    DIRECTION INPUT ;
    USE SIGNAL ;
    PORT
      LAYER M5 ;
        RECT  62.064 56.076 62.088 56.16 ;
    END
  END i_sel[7]
  PIN i_sel[8]
    DIRECTION INPUT ;
    USE SIGNAL ;
    PORT
      LAYER M5 ;
        RECT  62.16 56.076 62.184 56.16 ;
    END
  END i_sel[8]
  PIN i_sel[9]
    DIRECTION INPUT ;
    USE SIGNAL ;
    PORT
      LAYER M5 ;
        RECT  62.256 56.076 62.28 56.16 ;
    END
  END i_sel[9]
  PIN i_v
    DIRECTION INPUT ;
    USE SIGNAL ;
    PORT
      LAYER M5 ;
        RECT  31.056 56.076 31.08 56.16 ;
    END
  END i_v
  PIN o_bv
    DIRECTION OUTPUT ;
    USE SIGNAL ;
    PORT
      LAYER M5 ;
        RECT  67.536 0 67.56 0.084 ;
    END
  END o_bv
  PIN o_fl
    DIRECTION OUTPUT ;
    USE SIGNAL ;
    PORT
      LAYER M5 ;
        RECT  67.632 0 67.656 0.084 ;
    END
  END o_fl
  PIN o_line[0]
    DIRECTION OUTPUT ;
    USE SIGNAL ;
    PORT
      LAYER M5 ;
        RECT  67.728 0 67.752 0.084 ;
    END
  END o_line[0]
  PIN o_line[100]
    DIRECTION OUTPUT ;
    USE SIGNAL ;
    PORT
      LAYER M5 ;
        RECT  100.368 0 100.392 0.084 ;
    END
  END o_line[100]
  PIN o_line[101]
    DIRECTION OUTPUT ;
    USE SIGNAL ;
    PORT
      LAYER M5 ;
        RECT  100.464 0 100.488 0.084 ;
    END
  END o_line[101]
  PIN o_line[102]
    DIRECTION OUTPUT ;
    USE SIGNAL ;
    PORT
      LAYER M5 ;
        RECT  100.56 0 100.584 0.084 ;
    END
  END o_line[102]
  PIN o_line[103]
    DIRECTION OUTPUT ;
    USE SIGNAL ;
    PORT
      LAYER M5 ;
        RECT  100.656 0 100.68 0.084 ;
    END
  END o_line[103]
  PIN o_line[104]
    DIRECTION OUTPUT ;
    USE SIGNAL ;
    PORT
      LAYER M5 ;
        RECT  100.752 0 100.776 0.084 ;
    END
  END o_line[104]
  PIN o_line[105]
    DIRECTION OUTPUT ;
    USE SIGNAL ;
    PORT
      LAYER M5 ;
        RECT  100.848 0 100.872 0.084 ;
    END
  END o_line[105]
  PIN o_line[106]
    DIRECTION OUTPUT ;
    USE SIGNAL ;
    PORT
      LAYER M5 ;
        RECT  100.944 0 100.968 0.084 ;
    END
  END o_line[106]
  PIN o_line[107]
    DIRECTION OUTPUT ;
    USE SIGNAL ;
    PORT
      LAYER M5 ;
        RECT  101.04 0 101.064 0.084 ;
    END
  END o_line[107]
  PIN o_line[108]
    DIRECTION OUTPUT ;
    USE SIGNAL ;
    PORT
      LAYER M5 ;
        RECT  101.136 0 101.16 0.084 ;
    END
  END o_line[108]
  PIN o_line[109]
    DIRECTION OUTPUT ;
    USE SIGNAL ;
    PORT
      LAYER M5 ;
        RECT  101.232 0 101.256 0.084 ;
    END
  END o_line[109]
  PIN o_line[10]
    DIRECTION OUTPUT ;
    USE SIGNAL ;
    PORT
      LAYER M5 ;
        RECT  68.688 0 68.712 0.084 ;
    END
  END o_line[10]
  PIN o_line[110]
    DIRECTION OUTPUT ;
    USE SIGNAL ;
    PORT
      LAYER M5 ;
        RECT  101.328 0 101.352 0.084 ;
    END
  END o_line[110]
  PIN o_line[111]
    DIRECTION OUTPUT ;
    USE SIGNAL ;
    PORT
      LAYER M5 ;
        RECT  101.424 0 101.448 0.084 ;
    END
  END o_line[111]
  PIN o_line[112]
    DIRECTION OUTPUT ;
    USE SIGNAL ;
    PORT
      LAYER M5 ;
        RECT  101.52 0 101.544 0.084 ;
    END
  END o_line[112]
  PIN o_line[113]
    DIRECTION OUTPUT ;
    USE SIGNAL ;
    PORT
      LAYER M5 ;
        RECT  101.616 0 101.64 0.084 ;
    END
  END o_line[113]
  PIN o_line[114]
    DIRECTION OUTPUT ;
    USE SIGNAL ;
    PORT
      LAYER M5 ;
        RECT  101.712 0 101.736 0.084 ;
    END
  END o_line[114]
  PIN o_line[115]
    DIRECTION OUTPUT ;
    USE SIGNAL ;
    PORT
      LAYER M5 ;
        RECT  101.808 0 101.832 0.084 ;
    END
  END o_line[115]
  PIN o_line[116]
    DIRECTION OUTPUT ;
    USE SIGNAL ;
    PORT
      LAYER M5 ;
        RECT  101.904 0 101.928 0.084 ;
    END
  END o_line[116]
  PIN o_line[117]
    DIRECTION OUTPUT ;
    USE SIGNAL ;
    PORT
      LAYER M5 ;
        RECT  102 0 102.024 0.084 ;
    END
  END o_line[117]
  PIN o_line[118]
    DIRECTION OUTPUT ;
    USE SIGNAL ;
    PORT
      LAYER M5 ;
        RECT  102.096 0 102.12 0.084 ;
    END
  END o_line[118]
  PIN o_line[119]
    DIRECTION OUTPUT ;
    USE SIGNAL ;
    PORT
      LAYER M5 ;
        RECT  102.192 0 102.216 0.084 ;
    END
  END o_line[119]
  PIN o_line[11]
    DIRECTION OUTPUT ;
    USE SIGNAL ;
    PORT
      LAYER M5 ;
        RECT  68.784 0 68.808 0.084 ;
    END
  END o_line[11]
  PIN o_line[120]
    DIRECTION OUTPUT ;
    USE SIGNAL ;
    PORT
      LAYER M5 ;
        RECT  102.288 0 102.312 0.084 ;
    END
  END o_line[120]
  PIN o_line[121]
    DIRECTION OUTPUT ;
    USE SIGNAL ;
    PORT
      LAYER M5 ;
        RECT  102.384 0 102.408 0.084 ;
    END
  END o_line[121]
  PIN o_line[122]
    DIRECTION OUTPUT ;
    USE SIGNAL ;
    PORT
      LAYER M5 ;
        RECT  102.48 0 102.504 0.084 ;
    END
  END o_line[122]
  PIN o_line[123]
    DIRECTION OUTPUT ;
    USE SIGNAL ;
    PORT
      LAYER M5 ;
        RECT  102.576 0 102.6 0.084 ;
    END
  END o_line[123]
  PIN o_line[124]
    DIRECTION OUTPUT ;
    USE SIGNAL ;
    PORT
      LAYER M5 ;
        RECT  102.672 0 102.696 0.084 ;
    END
  END o_line[124]
  PIN o_line[125]
    DIRECTION OUTPUT ;
    USE SIGNAL ;
    PORT
      LAYER M5 ;
        RECT  102.768 0 102.792 0.084 ;
    END
  END o_line[125]
  PIN o_line[126]
    DIRECTION OUTPUT ;
    USE SIGNAL ;
    PORT
      LAYER M5 ;
        RECT  96.72 0 96.744 0.084 ;
    END
  END o_line[126]
  PIN o_line[127]
    DIRECTION OUTPUT ;
    USE SIGNAL ;
    PORT
      LAYER M5 ;
        RECT  96.816 0 96.84 0.084 ;
    END
  END o_line[127]
  PIN o_line[128]
    DIRECTION OUTPUT ;
    USE SIGNAL ;
    PORT
      LAYER M5 ;
        RECT  96.912 0 96.936 0.084 ;
    END
  END o_line[128]
  PIN o_line[129]
    DIRECTION OUTPUT ;
    USE SIGNAL ;
    PORT
      LAYER M5 ;
        RECT  97.008 0 97.032 0.084 ;
    END
  END o_line[129]
  PIN o_line[12]
    DIRECTION OUTPUT ;
    USE SIGNAL ;
    PORT
      LAYER M5 ;
        RECT  68.88 0 68.904 0.084 ;
    END
  END o_line[12]
  PIN o_line[130]
    DIRECTION OUTPUT ;
    USE SIGNAL ;
    PORT
      LAYER M5 ;
        RECT  97.104 0 97.128 0.084 ;
    END
  END o_line[130]
  PIN o_line[131]
    DIRECTION OUTPUT ;
    USE SIGNAL ;
    PORT
      LAYER M5 ;
        RECT  97.2 0 97.224 0.084 ;
    END
  END o_line[131]
  PIN o_line[132]
    DIRECTION OUTPUT ;
    USE SIGNAL ;
    PORT
      LAYER M5 ;
        RECT  97.296 0 97.32 0.084 ;
    END
  END o_line[132]
  PIN o_line[133]
    DIRECTION OUTPUT ;
    USE SIGNAL ;
    PORT
      LAYER M5 ;
        RECT  97.392 0 97.416 0.084 ;
    END
  END o_line[133]
  PIN o_line[134]
    DIRECTION OUTPUT ;
    USE SIGNAL ;
    PORT
      LAYER M5 ;
        RECT  97.488 0 97.512 0.084 ;
    END
  END o_line[134]
  PIN o_line[135]
    DIRECTION OUTPUT ;
    USE SIGNAL ;
    PORT
      LAYER M5 ;
        RECT  97.584 0 97.608 0.084 ;
    END
  END o_line[135]
  PIN o_line[136]
    DIRECTION OUTPUT ;
    USE SIGNAL ;
    PORT
      LAYER M5 ;
        RECT  97.68 0 97.704 0.084 ;
    END
  END o_line[136]
  PIN o_line[137]
    DIRECTION OUTPUT ;
    USE SIGNAL ;
    PORT
      LAYER M5 ;
        RECT  97.776 0 97.8 0.084 ;
    END
  END o_line[137]
  PIN o_line[138]
    DIRECTION OUTPUT ;
    USE SIGNAL ;
    PORT
      LAYER M5 ;
        RECT  97.872 0 97.896 0.084 ;
    END
  END o_line[138]
  PIN o_line[139]
    DIRECTION OUTPUT ;
    USE SIGNAL ;
    PORT
      LAYER M5 ;
        RECT  97.968 0 97.992 0.084 ;
    END
  END o_line[139]
  PIN o_line[13]
    DIRECTION OUTPUT ;
    USE SIGNAL ;
    PORT
      LAYER M5 ;
        RECT  68.976 0 69 0.084 ;
    END
  END o_line[13]
  PIN o_line[140]
    DIRECTION OUTPUT ;
    USE SIGNAL ;
    PORT
      LAYER M5 ;
        RECT  98.064 0 98.088 0.084 ;
    END
  END o_line[140]
  PIN o_line[141]
    DIRECTION OUTPUT ;
    USE SIGNAL ;
    PORT
      LAYER M5 ;
        RECT  98.16 0 98.184 0.084 ;
    END
  END o_line[141]
  PIN o_line[142]
    DIRECTION OUTPUT ;
    USE SIGNAL ;
    PORT
      LAYER M5 ;
        RECT  98.256 0 98.28 0.084 ;
    END
  END o_line[142]
  PIN o_line[143]
    DIRECTION OUTPUT ;
    USE SIGNAL ;
    PORT
      LAYER M5 ;
        RECT  98.352 0 98.376 0.084 ;
    END
  END o_line[143]
  PIN o_line[144]
    DIRECTION OUTPUT ;
    USE SIGNAL ;
    PORT
      LAYER M5 ;
        RECT  98.448 0 98.472 0.084 ;
    END
  END o_line[144]
  PIN o_line[145]
    DIRECTION OUTPUT ;
    USE SIGNAL ;
    PORT
      LAYER M5 ;
        RECT  98.544 0 98.568 0.084 ;
    END
  END o_line[145]
  PIN o_line[146]
    DIRECTION OUTPUT ;
    USE SIGNAL ;
    PORT
      LAYER M5 ;
        RECT  98.64 0 98.664 0.084 ;
    END
  END o_line[146]
  PIN o_line[147]
    DIRECTION OUTPUT ;
    USE SIGNAL ;
    PORT
      LAYER M5 ;
        RECT  98.736 0 98.76 0.084 ;
    END
  END o_line[147]
  PIN o_line[148]
    DIRECTION OUTPUT ;
    USE SIGNAL ;
    PORT
      LAYER M5 ;
        RECT  98.832 0 98.856 0.084 ;
    END
  END o_line[148]
  PIN o_line[149]
    DIRECTION OUTPUT ;
    USE SIGNAL ;
    PORT
      LAYER M5 ;
        RECT  98.928 0 98.952 0.084 ;
    END
  END o_line[149]
  PIN o_line[14]
    DIRECTION OUTPUT ;
    USE SIGNAL ;
    PORT
      LAYER M5 ;
        RECT  69.072 0 69.096 0.084 ;
    END
  END o_line[14]
  PIN o_line[150]
    DIRECTION OUTPUT ;
    USE SIGNAL ;
    PORT
      LAYER M5 ;
        RECT  99.024 0 99.048 0.084 ;
    END
  END o_line[150]
  PIN o_line[151]
    DIRECTION OUTPUT ;
    USE SIGNAL ;
    PORT
      LAYER M5 ;
        RECT  99.12 0 99.144 0.084 ;
    END
  END o_line[151]
  PIN o_line[152]
    DIRECTION OUTPUT ;
    USE SIGNAL ;
    PORT
      LAYER M5 ;
        RECT  99.216 0 99.24 0.084 ;
    END
  END o_line[152]
  PIN o_line[153]
    DIRECTION OUTPUT ;
    USE SIGNAL ;
    PORT
      LAYER M5 ;
        RECT  99.312 0 99.336 0.084 ;
    END
  END o_line[153]
  PIN o_line[154]
    DIRECTION OUTPUT ;
    USE SIGNAL ;
    PORT
      LAYER M5 ;
        RECT  99.408 0 99.432 0.084 ;
    END
  END o_line[154]
  PIN o_line[155]
    DIRECTION OUTPUT ;
    USE SIGNAL ;
    PORT
      LAYER M5 ;
        RECT  99.504 0 99.528 0.084 ;
    END
  END o_line[155]
  PIN o_line[156]
    DIRECTION OUTPUT ;
    USE SIGNAL ;
    PORT
      LAYER M5 ;
        RECT  99.6 0 99.624 0.084 ;
    END
  END o_line[156]
  PIN o_line[157]
    DIRECTION OUTPUT ;
    USE SIGNAL ;
    PORT
      LAYER M5 ;
        RECT  99.696 0 99.72 0.084 ;
    END
  END o_line[157]
  PIN o_line[158]
    DIRECTION OUTPUT ;
    USE SIGNAL ;
    PORT
      LAYER M5 ;
        RECT  58.32 0 58.344 0.084 ;
    END
  END o_line[158]
  PIN o_line[159]
    DIRECTION OUTPUT ;
    USE SIGNAL ;
    PORT
      LAYER M5 ;
        RECT  58.416 0 58.44 0.084 ;
    END
  END o_line[159]
  PIN o_line[15]
    DIRECTION OUTPUT ;
    USE SIGNAL ;
    PORT
      LAYER M5 ;
        RECT  69.168 0 69.192 0.084 ;
    END
  END o_line[15]
  PIN o_line[160]
    DIRECTION OUTPUT ;
    USE SIGNAL ;
    PORT
      LAYER M5 ;
        RECT  58.512 0 58.536 0.084 ;
    END
  END o_line[160]
  PIN o_line[161]
    DIRECTION OUTPUT ;
    USE SIGNAL ;
    PORT
      LAYER M5 ;
        RECT  58.608 0 58.632 0.084 ;
    END
  END o_line[161]
  PIN o_line[162]
    DIRECTION OUTPUT ;
    USE SIGNAL ;
    PORT
      LAYER M5 ;
        RECT  58.704 0 58.728 0.084 ;
    END
  END o_line[162]
  PIN o_line[163]
    DIRECTION OUTPUT ;
    USE SIGNAL ;
    PORT
      LAYER M5 ;
        RECT  58.8 0 58.824 0.084 ;
    END
  END o_line[163]
  PIN o_line[164]
    DIRECTION OUTPUT ;
    USE SIGNAL ;
    PORT
      LAYER M5 ;
        RECT  58.896 0 58.92 0.084 ;
    END
  END o_line[164]
  PIN o_line[165]
    DIRECTION OUTPUT ;
    USE SIGNAL ;
    PORT
      LAYER M5 ;
        RECT  58.992 0 59.016 0.084 ;
    END
  END o_line[165]
  PIN o_line[166]
    DIRECTION OUTPUT ;
    USE SIGNAL ;
    PORT
      LAYER M5 ;
        RECT  59.088 0 59.112 0.084 ;
    END
  END o_line[166]
  PIN o_line[167]
    DIRECTION OUTPUT ;
    USE SIGNAL ;
    PORT
      LAYER M5 ;
        RECT  59.184 0 59.208 0.084 ;
    END
  END o_line[167]
  PIN o_line[168]
    DIRECTION OUTPUT ;
    USE SIGNAL ;
    PORT
      LAYER M5 ;
        RECT  59.28 0 59.304 0.084 ;
    END
  END o_line[168]
  PIN o_line[169]
    DIRECTION OUTPUT ;
    USE SIGNAL ;
    PORT
      LAYER M5 ;
        RECT  59.376 0 59.4 0.084 ;
    END
  END o_line[169]
  PIN o_line[16]
    DIRECTION OUTPUT ;
    USE SIGNAL ;
    PORT
      LAYER M5 ;
        RECT  69.264 0 69.288 0.084 ;
    END
  END o_line[16]
  PIN o_line[170]
    DIRECTION OUTPUT ;
    USE SIGNAL ;
    PORT
      LAYER M5 ;
        RECT  59.472 0 59.496 0.084 ;
    END
  END o_line[170]
  PIN o_line[171]
    DIRECTION OUTPUT ;
    USE SIGNAL ;
    PORT
      LAYER M5 ;
        RECT  59.568 0 59.592 0.084 ;
    END
  END o_line[171]
  PIN o_line[172]
    DIRECTION OUTPUT ;
    USE SIGNAL ;
    PORT
      LAYER M5 ;
        RECT  59.664 0 59.688 0.084 ;
    END
  END o_line[172]
  PIN o_line[173]
    DIRECTION OUTPUT ;
    USE SIGNAL ;
    PORT
      LAYER M5 ;
        RECT  59.76 0 59.784 0.084 ;
    END
  END o_line[173]
  PIN o_line[174]
    DIRECTION OUTPUT ;
    USE SIGNAL ;
    PORT
      LAYER M5 ;
        RECT  59.856 0 59.88 0.084 ;
    END
  END o_line[174]
  PIN o_line[175]
    DIRECTION OUTPUT ;
    USE SIGNAL ;
    PORT
      LAYER M5 ;
        RECT  59.952 0 59.976 0.084 ;
    END
  END o_line[175]
  PIN o_line[176]
    DIRECTION OUTPUT ;
    USE SIGNAL ;
    PORT
      LAYER M5 ;
        RECT  60.048 0 60.072 0.084 ;
    END
  END o_line[176]
  PIN o_line[177]
    DIRECTION OUTPUT ;
    USE SIGNAL ;
    PORT
      LAYER M5 ;
        RECT  60.144 0 60.168 0.084 ;
    END
  END o_line[177]
  PIN o_line[178]
    DIRECTION OUTPUT ;
    USE SIGNAL ;
    PORT
      LAYER M5 ;
        RECT  60.24 0 60.264 0.084 ;
    END
  END o_line[178]
  PIN o_line[179]
    DIRECTION OUTPUT ;
    USE SIGNAL ;
    PORT
      LAYER M5 ;
        RECT  60.336 0 60.36 0.084 ;
    END
  END o_line[179]
  PIN o_line[17]
    DIRECTION OUTPUT ;
    USE SIGNAL ;
    PORT
      LAYER M5 ;
        RECT  69.36 0 69.384 0.084 ;
    END
  END o_line[17]
  PIN o_line[180]
    DIRECTION OUTPUT ;
    USE SIGNAL ;
    PORT
      LAYER M5 ;
        RECT  60.432 0 60.456 0.084 ;
    END
  END o_line[180]
  PIN o_line[181]
    DIRECTION OUTPUT ;
    USE SIGNAL ;
    PORT
      LAYER M5 ;
        RECT  60.528 0 60.552 0.084 ;
    END
  END o_line[181]
  PIN o_line[182]
    DIRECTION OUTPUT ;
    USE SIGNAL ;
    PORT
      LAYER M5 ;
        RECT  60.624 0 60.648 0.084 ;
    END
  END o_line[182]
  PIN o_line[183]
    DIRECTION OUTPUT ;
    USE SIGNAL ;
    PORT
      LAYER M5 ;
        RECT  60.72 0 60.744 0.084 ;
    END
  END o_line[183]
  PIN o_line[184]
    DIRECTION OUTPUT ;
    USE SIGNAL ;
    PORT
      LAYER M5 ;
        RECT  60.816 0 60.84 0.084 ;
    END
  END o_line[184]
  PIN o_line[185]
    DIRECTION OUTPUT ;
    USE SIGNAL ;
    PORT
      LAYER M5 ;
        RECT  60.912 0 60.936 0.084 ;
    END
  END o_line[185]
  PIN o_line[186]
    DIRECTION OUTPUT ;
    USE SIGNAL ;
    PORT
      LAYER M5 ;
        RECT  61.008 0 61.032 0.084 ;
    END
  END o_line[186]
  PIN o_line[187]
    DIRECTION OUTPUT ;
    USE SIGNAL ;
    PORT
      LAYER M5 ;
        RECT  61.104 0 61.128 0.084 ;
    END
  END o_line[187]
  PIN o_line[188]
    DIRECTION OUTPUT ;
    USE SIGNAL ;
    PORT
      LAYER M5 ;
        RECT  61.2 0 61.224 0.084 ;
    END
  END o_line[188]
  PIN o_line[189]
    DIRECTION OUTPUT ;
    USE SIGNAL ;
    PORT
      LAYER M5 ;
        RECT  61.296 0 61.32 0.084 ;
    END
  END o_line[189]
  PIN o_line[18]
    DIRECTION OUTPUT ;
    USE SIGNAL ;
    PORT
      LAYER M5 ;
        RECT  69.456 0 69.48 0.084 ;
    END
  END o_line[18]
  PIN o_line[190]
    DIRECTION OUTPUT ;
    USE SIGNAL ;
    PORT
      LAYER M5 ;
        RECT  64.464 0 64.488 0.084 ;
    END
  END o_line[190]
  PIN o_line[191]
    DIRECTION OUTPUT ;
    USE SIGNAL ;
    PORT
      LAYER M5 ;
        RECT  64.56 0 64.584 0.084 ;
    END
  END o_line[191]
  PIN o_line[192]
    DIRECTION OUTPUT ;
    USE SIGNAL ;
    PORT
      LAYER M5 ;
        RECT  64.656 0 64.68 0.084 ;
    END
  END o_line[192]
  PIN o_line[193]
    DIRECTION OUTPUT ;
    USE SIGNAL ;
    PORT
      LAYER M5 ;
        RECT  64.752 0 64.776 0.084 ;
    END
  END o_line[193]
  PIN o_line[194]
    DIRECTION OUTPUT ;
    USE SIGNAL ;
    PORT
      LAYER M5 ;
        RECT  64.848 0 64.872 0.084 ;
    END
  END o_line[194]
  PIN o_line[195]
    DIRECTION OUTPUT ;
    USE SIGNAL ;
    PORT
      LAYER M5 ;
        RECT  64.944 0 64.968 0.084 ;
    END
  END o_line[195]
  PIN o_line[196]
    DIRECTION OUTPUT ;
    USE SIGNAL ;
    PORT
      LAYER M5 ;
        RECT  65.04 0 65.064 0.084 ;
    END
  END o_line[196]
  PIN o_line[197]
    DIRECTION OUTPUT ;
    USE SIGNAL ;
    PORT
      LAYER M5 ;
        RECT  65.136 0 65.16 0.084 ;
    END
  END o_line[197]
  PIN o_line[198]
    DIRECTION OUTPUT ;
    USE SIGNAL ;
    PORT
      LAYER M5 ;
        RECT  65.232 0 65.256 0.084 ;
    END
  END o_line[198]
  PIN o_line[199]
    DIRECTION OUTPUT ;
    USE SIGNAL ;
    PORT
      LAYER M5 ;
        RECT  65.328 0 65.352 0.084 ;
    END
  END o_line[199]
  PIN o_line[19]
    DIRECTION OUTPUT ;
    USE SIGNAL ;
    PORT
      LAYER M5 ;
        RECT  69.552 0 69.576 0.084 ;
    END
  END o_line[19]
  PIN o_line[1]
    DIRECTION OUTPUT ;
    USE SIGNAL ;
    PORT
      LAYER M5 ;
        RECT  67.824 0 67.848 0.084 ;
    END
  END o_line[1]
  PIN o_line[200]
    DIRECTION OUTPUT ;
    USE SIGNAL ;
    PORT
      LAYER M5 ;
        RECT  65.424 0 65.448 0.084 ;
    END
  END o_line[200]
  PIN o_line[201]
    DIRECTION OUTPUT ;
    USE SIGNAL ;
    PORT
      LAYER M5 ;
        RECT  65.52 0 65.544 0.084 ;
    END
  END o_line[201]
  PIN o_line[202]
    DIRECTION OUTPUT ;
    USE SIGNAL ;
    PORT
      LAYER M5 ;
        RECT  65.616 0 65.64 0.084 ;
    END
  END o_line[202]
  PIN o_line[203]
    DIRECTION OUTPUT ;
    USE SIGNAL ;
    PORT
      LAYER M5 ;
        RECT  65.712 0 65.736 0.084 ;
    END
  END o_line[203]
  PIN o_line[204]
    DIRECTION OUTPUT ;
    USE SIGNAL ;
    PORT
      LAYER M5 ;
        RECT  65.808 0 65.832 0.084 ;
    END
  END o_line[204]
  PIN o_line[205]
    DIRECTION OUTPUT ;
    USE SIGNAL ;
    PORT
      LAYER M5 ;
        RECT  65.904 0 65.928 0.084 ;
    END
  END o_line[205]
  PIN o_line[206]
    DIRECTION OUTPUT ;
    USE SIGNAL ;
    PORT
      LAYER M5 ;
        RECT  66 0 66.024 0.084 ;
    END
  END o_line[206]
  PIN o_line[207]
    DIRECTION OUTPUT ;
    USE SIGNAL ;
    PORT
      LAYER M5 ;
        RECT  66.096 0 66.12 0.084 ;
    END
  END o_line[207]
  PIN o_line[208]
    DIRECTION OUTPUT ;
    USE SIGNAL ;
    PORT
      LAYER M5 ;
        RECT  66.192 0 66.216 0.084 ;
    END
  END o_line[208]
  PIN o_line[209]
    DIRECTION OUTPUT ;
    USE SIGNAL ;
    PORT
      LAYER M5 ;
        RECT  66.288 0 66.312 0.084 ;
    END
  END o_line[209]
  PIN o_line[20]
    DIRECTION OUTPUT ;
    USE SIGNAL ;
    PORT
      LAYER M5 ;
        RECT  69.648 0 69.672 0.084 ;
    END
  END o_line[20]
  PIN o_line[210]
    DIRECTION OUTPUT ;
    USE SIGNAL ;
    PORT
      LAYER M5 ;
        RECT  66.384 0 66.408 0.084 ;
    END
  END o_line[210]
  PIN o_line[211]
    DIRECTION OUTPUT ;
    USE SIGNAL ;
    PORT
      LAYER M5 ;
        RECT  66.48 0 66.504 0.084 ;
    END
  END o_line[211]
  PIN o_line[212]
    DIRECTION OUTPUT ;
    USE SIGNAL ;
    PORT
      LAYER M5 ;
        RECT  66.576 0 66.6 0.084 ;
    END
  END o_line[212]
  PIN o_line[213]
    DIRECTION OUTPUT ;
    USE SIGNAL ;
    PORT
      LAYER M5 ;
        RECT  66.672 0 66.696 0.084 ;
    END
  END o_line[213]
  PIN o_line[214]
    DIRECTION OUTPUT ;
    USE SIGNAL ;
    PORT
      LAYER M5 ;
        RECT  66.768 0 66.792 0.084 ;
    END
  END o_line[214]
  PIN o_line[215]
    DIRECTION OUTPUT ;
    USE SIGNAL ;
    PORT
      LAYER M5 ;
        RECT  66.864 0 66.888 0.084 ;
    END
  END o_line[215]
  PIN o_line[216]
    DIRECTION OUTPUT ;
    USE SIGNAL ;
    PORT
      LAYER M5 ;
        RECT  66.96 0 66.984 0.084 ;
    END
  END o_line[216]
  PIN o_line[217]
    DIRECTION OUTPUT ;
    USE SIGNAL ;
    PORT
      LAYER M5 ;
        RECT  67.056 0 67.08 0.084 ;
    END
  END o_line[217]
  PIN o_line[218]
    DIRECTION OUTPUT ;
    USE SIGNAL ;
    PORT
      LAYER M5 ;
        RECT  67.152 0 67.176 0.084 ;
    END
  END o_line[218]
  PIN o_line[219]
    DIRECTION OUTPUT ;
    USE SIGNAL ;
    PORT
      LAYER M5 ;
        RECT  67.248 0 67.272 0.084 ;
    END
  END o_line[219]
  PIN o_line[21]
    DIRECTION OUTPUT ;
    USE SIGNAL ;
    PORT
      LAYER M5 ;
        RECT  69.744 0 69.768 0.084 ;
    END
  END o_line[21]
  PIN o_line[220]
    DIRECTION OUTPUT ;
    USE SIGNAL ;
    PORT
      LAYER M5 ;
        RECT  67.344 0 67.368 0.084 ;
    END
  END o_line[220]
  PIN o_line[221]
    DIRECTION OUTPUT ;
    USE SIGNAL ;
    PORT
      LAYER M5 ;
        RECT  67.44 0 67.464 0.084 ;
    END
  END o_line[221]
  PIN o_line[222]
    DIRECTION OUTPUT ;
    USE SIGNAL ;
    PORT
      LAYER M5 ;
        RECT  86.736 0 86.76 0.084 ;
    END
  END o_line[222]
  PIN o_line[223]
    DIRECTION OUTPUT ;
    USE SIGNAL ;
    PORT
      LAYER M5 ;
        RECT  86.832 0 86.856 0.084 ;
    END
  END o_line[223]
  PIN o_line[224]
    DIRECTION OUTPUT ;
    USE SIGNAL ;
    PORT
      LAYER M5 ;
        RECT  86.928 0 86.952 0.084 ;
    END
  END o_line[224]
  PIN o_line[225]
    DIRECTION OUTPUT ;
    USE SIGNAL ;
    PORT
      LAYER M5 ;
        RECT  87.024 0 87.048 0.084 ;
    END
  END o_line[225]
  PIN o_line[226]
    DIRECTION OUTPUT ;
    USE SIGNAL ;
    PORT
      LAYER M5 ;
        RECT  87.12 0 87.144 0.084 ;
    END
  END o_line[226]
  PIN o_line[227]
    DIRECTION OUTPUT ;
    USE SIGNAL ;
    PORT
      LAYER M5 ;
        RECT  87.216 0 87.24 0.084 ;
    END
  END o_line[227]
  PIN o_line[228]
    DIRECTION OUTPUT ;
    USE SIGNAL ;
    PORT
      LAYER M5 ;
        RECT  87.312 0 87.336 0.084 ;
    END
  END o_line[228]
  PIN o_line[229]
    DIRECTION OUTPUT ;
    USE SIGNAL ;
    PORT
      LAYER M5 ;
        RECT  87.408 0 87.432 0.084 ;
    END
  END o_line[229]
  PIN o_line[22]
    DIRECTION OUTPUT ;
    USE SIGNAL ;
    PORT
      LAYER M5 ;
        RECT  69.84 0 69.864 0.084 ;
    END
  END o_line[22]
  PIN o_line[230]
    DIRECTION OUTPUT ;
    USE SIGNAL ;
    PORT
      LAYER M5 ;
        RECT  87.504 0 87.528 0.084 ;
    END
  END o_line[230]
  PIN o_line[231]
    DIRECTION OUTPUT ;
    USE SIGNAL ;
    PORT
      LAYER M5 ;
        RECT  87.6 0 87.624 0.084 ;
    END
  END o_line[231]
  PIN o_line[232]
    DIRECTION OUTPUT ;
    USE SIGNAL ;
    PORT
      LAYER M5 ;
        RECT  87.696 0 87.72 0.084 ;
    END
  END o_line[232]
  PIN o_line[233]
    DIRECTION OUTPUT ;
    USE SIGNAL ;
    PORT
      LAYER M5 ;
        RECT  87.792 0 87.816 0.084 ;
    END
  END o_line[233]
  PIN o_line[234]
    DIRECTION OUTPUT ;
    USE SIGNAL ;
    PORT
      LAYER M5 ;
        RECT  87.888 0 87.912 0.084 ;
    END
  END o_line[234]
  PIN o_line[235]
    DIRECTION OUTPUT ;
    USE SIGNAL ;
    PORT
      LAYER M5 ;
        RECT  87.984 0 88.008 0.084 ;
    END
  END o_line[235]
  PIN o_line[236]
    DIRECTION OUTPUT ;
    USE SIGNAL ;
    PORT
      LAYER M5 ;
        RECT  88.08 0 88.104 0.084 ;
    END
  END o_line[236]
  PIN o_line[237]
    DIRECTION OUTPUT ;
    USE SIGNAL ;
    PORT
      LAYER M5 ;
        RECT  88.176 0 88.2 0.084 ;
    END
  END o_line[237]
  PIN o_line[238]
    DIRECTION OUTPUT ;
    USE SIGNAL ;
    PORT
      LAYER M5 ;
        RECT  88.272 0 88.296 0.084 ;
    END
  END o_line[238]
  PIN o_line[239]
    DIRECTION OUTPUT ;
    USE SIGNAL ;
    PORT
      LAYER M5 ;
        RECT  88.368 0 88.392 0.084 ;
    END
  END o_line[239]
  PIN o_line[23]
    DIRECTION OUTPUT ;
    USE SIGNAL ;
    PORT
      LAYER M5 ;
        RECT  69.936 0 69.96 0.084 ;
    END
  END o_line[23]
  PIN o_line[240]
    DIRECTION OUTPUT ;
    USE SIGNAL ;
    PORT
      LAYER M5 ;
        RECT  88.464 0 88.488 0.084 ;
    END
  END o_line[240]
  PIN o_line[241]
    DIRECTION OUTPUT ;
    USE SIGNAL ;
    PORT
      LAYER M5 ;
        RECT  88.56 0 88.584 0.084 ;
    END
  END o_line[241]
  PIN o_line[242]
    DIRECTION OUTPUT ;
    USE SIGNAL ;
    PORT
      LAYER M5 ;
        RECT  88.656 0 88.68 0.084 ;
    END
  END o_line[242]
  PIN o_line[243]
    DIRECTION OUTPUT ;
    USE SIGNAL ;
    PORT
      LAYER M5 ;
        RECT  88.752 0 88.776 0.084 ;
    END
  END o_line[243]
  PIN o_line[244]
    DIRECTION OUTPUT ;
    USE SIGNAL ;
    PORT
      LAYER M5 ;
        RECT  88.848 0 88.872 0.084 ;
    END
  END o_line[244]
  PIN o_line[245]
    DIRECTION OUTPUT ;
    USE SIGNAL ;
    PORT
      LAYER M5 ;
        RECT  88.944 0 88.968 0.084 ;
    END
  END o_line[245]
  PIN o_line[246]
    DIRECTION OUTPUT ;
    USE SIGNAL ;
    PORT
      LAYER M5 ;
        RECT  89.04 0 89.064 0.084 ;
    END
  END o_line[246]
  PIN o_line[247]
    DIRECTION OUTPUT ;
    USE SIGNAL ;
    PORT
      LAYER M5 ;
        RECT  89.136 0 89.16 0.084 ;
    END
  END o_line[247]
  PIN o_line[248]
    DIRECTION OUTPUT ;
    USE SIGNAL ;
    PORT
      LAYER M5 ;
        RECT  89.232 0 89.256 0.084 ;
    END
  END o_line[248]
  PIN o_line[249]
    DIRECTION OUTPUT ;
    USE SIGNAL ;
    PORT
      LAYER M5 ;
        RECT  89.328 0 89.352 0.084 ;
    END
  END o_line[249]
  PIN o_line[24]
    DIRECTION OUTPUT ;
    USE SIGNAL ;
    PORT
      LAYER M5 ;
        RECT  70.032 0 70.056 0.084 ;
    END
  END o_line[24]
  PIN o_line[250]
    DIRECTION OUTPUT ;
    USE SIGNAL ;
    PORT
      LAYER M5 ;
        RECT  89.424 0 89.448 0.084 ;
    END
  END o_line[250]
  PIN o_line[251]
    DIRECTION OUTPUT ;
    USE SIGNAL ;
    PORT
      LAYER M5 ;
        RECT  89.52 0 89.544 0.084 ;
    END
  END o_line[251]
  PIN o_line[252]
    DIRECTION OUTPUT ;
    USE SIGNAL ;
    PORT
      LAYER M5 ;
        RECT  89.616 0 89.64 0.084 ;
    END
  END o_line[252]
  PIN o_line[253]
    DIRECTION OUTPUT ;
    USE SIGNAL ;
    PORT
      LAYER M5 ;
        RECT  89.712 0 89.736 0.084 ;
    END
  END o_line[253]
  PIN o_line[254]
    DIRECTION OUTPUT ;
    USE SIGNAL ;
    PORT
      LAYER M5 ;
        RECT  102.864 0 102.888 0.084 ;
    END
  END o_line[254]
  PIN o_line[255]
    DIRECTION OUTPUT ;
    USE SIGNAL ;
    PORT
      LAYER M5 ;
        RECT  102.96 0 102.984 0.084 ;
    END
  END o_line[255]
  PIN o_line[256]
    DIRECTION OUTPUT ;
    USE SIGNAL ;
    PORT
      LAYER M5 ;
        RECT  103.056 0 103.08 0.084 ;
    END
  END o_line[256]
  PIN o_line[257]
    DIRECTION OUTPUT ;
    USE SIGNAL ;
    PORT
      LAYER M5 ;
        RECT  103.152 0 103.176 0.084 ;
    END
  END o_line[257]
  PIN o_line[258]
    DIRECTION OUTPUT ;
    USE SIGNAL ;
    PORT
      LAYER M5 ;
        RECT  103.248 0 103.272 0.084 ;
    END
  END o_line[258]
  PIN o_line[259]
    DIRECTION OUTPUT ;
    USE SIGNAL ;
    PORT
      LAYER M5 ;
        RECT  103.344 0 103.368 0.084 ;
    END
  END o_line[259]
  PIN o_line[25]
    DIRECTION OUTPUT ;
    USE SIGNAL ;
    PORT
      LAYER M5 ;
        RECT  70.128 0 70.152 0.084 ;
    END
  END o_line[25]
  PIN o_line[260]
    DIRECTION OUTPUT ;
    USE SIGNAL ;
    PORT
      LAYER M5 ;
        RECT  103.44 0 103.464 0.084 ;
    END
  END o_line[260]
  PIN o_line[261]
    DIRECTION OUTPUT ;
    USE SIGNAL ;
    PORT
      LAYER M5 ;
        RECT  103.536 0 103.56 0.084 ;
    END
  END o_line[261]
  PIN o_line[262]
    DIRECTION OUTPUT ;
    USE SIGNAL ;
    PORT
      LAYER M5 ;
        RECT  103.632 0 103.656 0.084 ;
    END
  END o_line[262]
  PIN o_line[263]
    DIRECTION OUTPUT ;
    USE SIGNAL ;
    PORT
      LAYER M5 ;
        RECT  103.728 0 103.752 0.084 ;
    END
  END o_line[263]
  PIN o_line[264]
    DIRECTION OUTPUT ;
    USE SIGNAL ;
    PORT
      LAYER M5 ;
        RECT  103.824 0 103.848 0.084 ;
    END
  END o_line[264]
  PIN o_line[265]
    DIRECTION OUTPUT ;
    USE SIGNAL ;
    PORT
      LAYER M5 ;
        RECT  103.92 0 103.944 0.084 ;
    END
  END o_line[265]
  PIN o_line[266]
    DIRECTION OUTPUT ;
    USE SIGNAL ;
    PORT
      LAYER M5 ;
        RECT  104.016 0 104.04 0.084 ;
    END
  END o_line[266]
  PIN o_line[267]
    DIRECTION OUTPUT ;
    USE SIGNAL ;
    PORT
      LAYER M5 ;
        RECT  104.112 0 104.136 0.084 ;
    END
  END o_line[267]
  PIN o_line[268]
    DIRECTION OUTPUT ;
    USE SIGNAL ;
    PORT
      LAYER M5 ;
        RECT  104.208 0 104.232 0.084 ;
    END
  END o_line[268]
  PIN o_line[269]
    DIRECTION OUTPUT ;
    USE SIGNAL ;
    PORT
      LAYER M5 ;
        RECT  104.304 0 104.328 0.084 ;
    END
  END o_line[269]
  PIN o_line[26]
    DIRECTION OUTPUT ;
    USE SIGNAL ;
    PORT
      LAYER M5 ;
        RECT  70.224 0 70.248 0.084 ;
    END
  END o_line[26]
  PIN o_line[270]
    DIRECTION OUTPUT ;
    USE SIGNAL ;
    PORT
      LAYER M5 ;
        RECT  104.4 0 104.424 0.084 ;
    END
  END o_line[270]
  PIN o_line[271]
    DIRECTION OUTPUT ;
    USE SIGNAL ;
    PORT
      LAYER M5 ;
        RECT  104.496 0 104.52 0.084 ;
    END
  END o_line[271]
  PIN o_line[272]
    DIRECTION OUTPUT ;
    USE SIGNAL ;
    PORT
      LAYER M5 ;
        RECT  104.592 0 104.616 0.084 ;
    END
  END o_line[272]
  PIN o_line[273]
    DIRECTION OUTPUT ;
    USE SIGNAL ;
    PORT
      LAYER M5 ;
        RECT  104.688 0 104.712 0.084 ;
    END
  END o_line[273]
  PIN o_line[274]
    DIRECTION OUTPUT ;
    USE SIGNAL ;
    PORT
      LAYER M5 ;
        RECT  104.784 0 104.808 0.084 ;
    END
  END o_line[274]
  PIN o_line[275]
    DIRECTION OUTPUT ;
    USE SIGNAL ;
    PORT
      LAYER M5 ;
        RECT  104.88 0 104.904 0.084 ;
    END
  END o_line[275]
  PIN o_line[276]
    DIRECTION OUTPUT ;
    USE SIGNAL ;
    PORT
      LAYER M5 ;
        RECT  104.976 0 105 0.084 ;
    END
  END o_line[276]
  PIN o_line[277]
    DIRECTION OUTPUT ;
    USE SIGNAL ;
    PORT
      LAYER M5 ;
        RECT  105.072 0 105.096 0.084 ;
    END
  END o_line[277]
  PIN o_line[278]
    DIRECTION OUTPUT ;
    USE SIGNAL ;
    PORT
      LAYER M5 ;
        RECT  105.168 0 105.192 0.084 ;
    END
  END o_line[278]
  PIN o_line[279]
    DIRECTION OUTPUT ;
    USE SIGNAL ;
    PORT
      LAYER M5 ;
        RECT  105.264 0 105.288 0.084 ;
    END
  END o_line[279]
  PIN o_line[27]
    DIRECTION OUTPUT ;
    USE SIGNAL ;
    PORT
      LAYER M5 ;
        RECT  70.32 0 70.344 0.084 ;
    END
  END o_line[27]
  PIN o_line[280]
    DIRECTION OUTPUT ;
    USE SIGNAL ;
    PORT
      LAYER M5 ;
        RECT  105.36 0 105.384 0.084 ;
    END
  END o_line[280]
  PIN o_line[281]
    DIRECTION OUTPUT ;
    USE SIGNAL ;
    PORT
      LAYER M5 ;
        RECT  105.456 0 105.48 0.084 ;
    END
  END o_line[281]
  PIN o_line[282]
    DIRECTION OUTPUT ;
    USE SIGNAL ;
    PORT
      LAYER M5 ;
        RECT  105.552 0 105.576 0.084 ;
    END
  END o_line[282]
  PIN o_line[283]
    DIRECTION OUTPUT ;
    USE SIGNAL ;
    PORT
      LAYER M5 ;
        RECT  105.648 0 105.672 0.084 ;
    END
  END o_line[283]
  PIN o_line[284]
    DIRECTION OUTPUT ;
    USE SIGNAL ;
    PORT
      LAYER M5 ;
        RECT  105.744 0 105.768 0.084 ;
    END
  END o_line[284]
  PIN o_line[285]
    DIRECTION OUTPUT ;
    USE SIGNAL ;
    PORT
      LAYER M5 ;
        RECT  105.84 0 105.864 0.084 ;
    END
  END o_line[285]
  PIN o_line[286]
    DIRECTION OUTPUT ;
    USE SIGNAL ;
    PORT
      LAYER M5 ;
        RECT  83.664 0 83.688 0.084 ;
    END
  END o_line[286]
  PIN o_line[287]
    DIRECTION OUTPUT ;
    USE SIGNAL ;
    PORT
      LAYER M5 ;
        RECT  83.76 0 83.784 0.084 ;
    END
  END o_line[287]
  PIN o_line[288]
    DIRECTION OUTPUT ;
    USE SIGNAL ;
    PORT
      LAYER M5 ;
        RECT  83.856 0 83.88 0.084 ;
    END
  END o_line[288]
  PIN o_line[289]
    DIRECTION OUTPUT ;
    USE SIGNAL ;
    PORT
      LAYER M5 ;
        RECT  83.952 0 83.976 0.084 ;
    END
  END o_line[289]
  PIN o_line[28]
    DIRECTION OUTPUT ;
    USE SIGNAL ;
    PORT
      LAYER M5 ;
        RECT  70.416 0 70.44 0.084 ;
    END
  END o_line[28]
  PIN o_line[290]
    DIRECTION OUTPUT ;
    USE SIGNAL ;
    PORT
      LAYER M5 ;
        RECT  84.048 0 84.072 0.084 ;
    END
  END o_line[290]
  PIN o_line[291]
    DIRECTION OUTPUT ;
    USE SIGNAL ;
    PORT
      LAYER M5 ;
        RECT  84.144 0 84.168 0.084 ;
    END
  END o_line[291]
  PIN o_line[292]
    DIRECTION OUTPUT ;
    USE SIGNAL ;
    PORT
      LAYER M5 ;
        RECT  84.24 0 84.264 0.084 ;
    END
  END o_line[292]
  PIN o_line[293]
    DIRECTION OUTPUT ;
    USE SIGNAL ;
    PORT
      LAYER M5 ;
        RECT  84.336 0 84.36 0.084 ;
    END
  END o_line[293]
  PIN o_line[294]
    DIRECTION OUTPUT ;
    USE SIGNAL ;
    PORT
      LAYER M5 ;
        RECT  84.432 0 84.456 0.084 ;
    END
  END o_line[294]
  PIN o_line[295]
    DIRECTION OUTPUT ;
    USE SIGNAL ;
    PORT
      LAYER M5 ;
        RECT  84.528 0 84.552 0.084 ;
    END
  END o_line[295]
  PIN o_line[296]
    DIRECTION OUTPUT ;
    USE SIGNAL ;
    PORT
      LAYER M5 ;
        RECT  84.624 0 84.648 0.084 ;
    END
  END o_line[296]
  PIN o_line[297]
    DIRECTION OUTPUT ;
    USE SIGNAL ;
    PORT
      LAYER M5 ;
        RECT  84.72 0 84.744 0.084 ;
    END
  END o_line[297]
  PIN o_line[298]
    DIRECTION OUTPUT ;
    USE SIGNAL ;
    PORT
      LAYER M5 ;
        RECT  84.816 0 84.84 0.084 ;
    END
  END o_line[298]
  PIN o_line[299]
    DIRECTION OUTPUT ;
    USE SIGNAL ;
    PORT
      LAYER M5 ;
        RECT  84.912 0 84.936 0.084 ;
    END
  END o_line[299]
  PIN o_line[29]
    DIRECTION OUTPUT ;
    USE SIGNAL ;
    PORT
      LAYER M5 ;
        RECT  70.512 0 70.536 0.084 ;
    END
  END o_line[29]
  PIN o_line[2]
    DIRECTION OUTPUT ;
    USE SIGNAL ;
    PORT
      LAYER M5 ;
        RECT  67.92 0 67.944 0.084 ;
    END
  END o_line[2]
  PIN o_line[300]
    DIRECTION OUTPUT ;
    USE SIGNAL ;
    PORT
      LAYER M5 ;
        RECT  85.008 0 85.032 0.084 ;
    END
  END o_line[300]
  PIN o_line[301]
    DIRECTION OUTPUT ;
    USE SIGNAL ;
    PORT
      LAYER M5 ;
        RECT  85.104 0 85.128 0.084 ;
    END
  END o_line[301]
  PIN o_line[302]
    DIRECTION OUTPUT ;
    USE SIGNAL ;
    PORT
      LAYER M5 ;
        RECT  85.2 0 85.224 0.084 ;
    END
  END o_line[302]
  PIN o_line[303]
    DIRECTION OUTPUT ;
    USE SIGNAL ;
    PORT
      LAYER M5 ;
        RECT  85.296 0 85.32 0.084 ;
    END
  END o_line[303]
  PIN o_line[304]
    DIRECTION OUTPUT ;
    USE SIGNAL ;
    PORT
      LAYER M5 ;
        RECT  85.392 0 85.416 0.084 ;
    END
  END o_line[304]
  PIN o_line[305]
    DIRECTION OUTPUT ;
    USE SIGNAL ;
    PORT
      LAYER M5 ;
        RECT  85.488 0 85.512 0.084 ;
    END
  END o_line[305]
  PIN o_line[306]
    DIRECTION OUTPUT ;
    USE SIGNAL ;
    PORT
      LAYER M5 ;
        RECT  85.584 0 85.608 0.084 ;
    END
  END o_line[306]
  PIN o_line[307]
    DIRECTION OUTPUT ;
    USE SIGNAL ;
    PORT
      LAYER M5 ;
        RECT  85.68 0 85.704 0.084 ;
    END
  END o_line[307]
  PIN o_line[308]
    DIRECTION OUTPUT ;
    USE SIGNAL ;
    PORT
      LAYER M5 ;
        RECT  85.776 0 85.8 0.084 ;
    END
  END o_line[308]
  PIN o_line[309]
    DIRECTION OUTPUT ;
    USE SIGNAL ;
    PORT
      LAYER M5 ;
        RECT  85.872 0 85.896 0.084 ;
    END
  END o_line[309]
  PIN o_line[30]
    DIRECTION OUTPUT ;
    USE SIGNAL ;
    PORT
      LAYER M5 ;
        RECT  45.264 0 45.288 0.084 ;
    END
  END o_line[30]
  PIN o_line[310]
    DIRECTION OUTPUT ;
    USE SIGNAL ;
    PORT
      LAYER M5 ;
        RECT  85.968 0 85.992 0.084 ;
    END
  END o_line[310]
  PIN o_line[311]
    DIRECTION OUTPUT ;
    USE SIGNAL ;
    PORT
      LAYER M5 ;
        RECT  86.064 0 86.088 0.084 ;
    END
  END o_line[311]
  PIN o_line[312]
    DIRECTION OUTPUT ;
    USE SIGNAL ;
    PORT
      LAYER M5 ;
        RECT  86.16 0 86.184 0.084 ;
    END
  END o_line[312]
  PIN o_line[313]
    DIRECTION OUTPUT ;
    USE SIGNAL ;
    PORT
      LAYER M5 ;
        RECT  86.256 0 86.28 0.084 ;
    END
  END o_line[313]
  PIN o_line[314]
    DIRECTION OUTPUT ;
    USE SIGNAL ;
    PORT
      LAYER M5 ;
        RECT  86.352 0 86.376 0.084 ;
    END
  END o_line[314]
  PIN o_line[315]
    DIRECTION OUTPUT ;
    USE SIGNAL ;
    PORT
      LAYER M5 ;
        RECT  86.448 0 86.472 0.084 ;
    END
  END o_line[315]
  PIN o_line[316]
    DIRECTION OUTPUT ;
    USE SIGNAL ;
    PORT
      LAYER M5 ;
        RECT  86.544 0 86.568 0.084 ;
    END
  END o_line[316]
  PIN o_line[317]
    DIRECTION OUTPUT ;
    USE SIGNAL ;
    PORT
      LAYER M5 ;
        RECT  86.64 0 86.664 0.084 ;
    END
  END o_line[317]
  PIN o_line[318]
    DIRECTION OUTPUT ;
    USE SIGNAL ;
    PORT
      LAYER M5 ;
        RECT  61.392 0 61.416 0.084 ;
    END
  END o_line[318]
  PIN o_line[319]
    DIRECTION OUTPUT ;
    USE SIGNAL ;
    PORT
      LAYER M5 ;
        RECT  61.488 0 61.512 0.084 ;
    END
  END o_line[319]
  PIN o_line[31]
    DIRECTION OUTPUT ;
    USE SIGNAL ;
    PORT
      LAYER M5 ;
        RECT  45.36 0 45.384 0.084 ;
    END
  END o_line[31]
  PIN o_line[320]
    DIRECTION OUTPUT ;
    USE SIGNAL ;
    PORT
      LAYER M5 ;
        RECT  61.584 0 61.608 0.084 ;
    END
  END o_line[320]
  PIN o_line[321]
    DIRECTION OUTPUT ;
    USE SIGNAL ;
    PORT
      LAYER M5 ;
        RECT  61.68 0 61.704 0.084 ;
    END
  END o_line[321]
  PIN o_line[322]
    DIRECTION OUTPUT ;
    USE SIGNAL ;
    PORT
      LAYER M5 ;
        RECT  61.776 0 61.8 0.084 ;
    END
  END o_line[322]
  PIN o_line[323]
    DIRECTION OUTPUT ;
    USE SIGNAL ;
    PORT
      LAYER M5 ;
        RECT  61.872 0 61.896 0.084 ;
    END
  END o_line[323]
  PIN o_line[324]
    DIRECTION OUTPUT ;
    USE SIGNAL ;
    PORT
      LAYER M5 ;
        RECT  61.968 0 61.992 0.084 ;
    END
  END o_line[324]
  PIN o_line[325]
    DIRECTION OUTPUT ;
    USE SIGNAL ;
    PORT
      LAYER M5 ;
        RECT  62.064 0 62.088 0.084 ;
    END
  END o_line[325]
  PIN o_line[326]
    DIRECTION OUTPUT ;
    USE SIGNAL ;
    PORT
      LAYER M5 ;
        RECT  62.16 0 62.184 0.084 ;
    END
  END o_line[326]
  PIN o_line[327]
    DIRECTION OUTPUT ;
    USE SIGNAL ;
    PORT
      LAYER M5 ;
        RECT  62.256 0 62.28 0.084 ;
    END
  END o_line[327]
  PIN o_line[328]
    DIRECTION OUTPUT ;
    USE SIGNAL ;
    PORT
      LAYER M5 ;
        RECT  62.352 0 62.376 0.084 ;
    END
  END o_line[328]
  PIN o_line[329]
    DIRECTION OUTPUT ;
    USE SIGNAL ;
    PORT
      LAYER M5 ;
        RECT  62.448 0 62.472 0.084 ;
    END
  END o_line[329]
  PIN o_line[32]
    DIRECTION OUTPUT ;
    USE SIGNAL ;
    PORT
      LAYER M5 ;
        RECT  45.456 0 45.48 0.084 ;
    END
  END o_line[32]
  PIN o_line[330]
    DIRECTION OUTPUT ;
    USE SIGNAL ;
    PORT
      LAYER M5 ;
        RECT  62.544 0 62.568 0.084 ;
    END
  END o_line[330]
  PIN o_line[331]
    DIRECTION OUTPUT ;
    USE SIGNAL ;
    PORT
      LAYER M5 ;
        RECT  62.64 0 62.664 0.084 ;
    END
  END o_line[331]
  PIN o_line[332]
    DIRECTION OUTPUT ;
    USE SIGNAL ;
    PORT
      LAYER M5 ;
        RECT  62.736 0 62.76 0.084 ;
    END
  END o_line[332]
  PIN o_line[333]
    DIRECTION OUTPUT ;
    USE SIGNAL ;
    PORT
      LAYER M5 ;
        RECT  62.832 0 62.856 0.084 ;
    END
  END o_line[333]
  PIN o_line[334]
    DIRECTION OUTPUT ;
    USE SIGNAL ;
    PORT
      LAYER M5 ;
        RECT  62.928 0 62.952 0.084 ;
    END
  END o_line[334]
  PIN o_line[335]
    DIRECTION OUTPUT ;
    USE SIGNAL ;
    PORT
      LAYER M5 ;
        RECT  63.024 0 63.048 0.084 ;
    END
  END o_line[335]
  PIN o_line[336]
    DIRECTION OUTPUT ;
    USE SIGNAL ;
    PORT
      LAYER M5 ;
        RECT  63.12 0 63.144 0.084 ;
    END
  END o_line[336]
  PIN o_line[337]
    DIRECTION OUTPUT ;
    USE SIGNAL ;
    PORT
      LAYER M5 ;
        RECT  63.216 0 63.24 0.084 ;
    END
  END o_line[337]
  PIN o_line[338]
    DIRECTION OUTPUT ;
    USE SIGNAL ;
    PORT
      LAYER M5 ;
        RECT  63.312 0 63.336 0.084 ;
    END
  END o_line[338]
  PIN o_line[339]
    DIRECTION OUTPUT ;
    USE SIGNAL ;
    PORT
      LAYER M5 ;
        RECT  63.408 0 63.432 0.084 ;
    END
  END o_line[339]
  PIN o_line[33]
    DIRECTION OUTPUT ;
    USE SIGNAL ;
    PORT
      LAYER M5 ;
        RECT  45.552 0 45.576 0.084 ;
    END
  END o_line[33]
  PIN o_line[340]
    DIRECTION OUTPUT ;
    USE SIGNAL ;
    PORT
      LAYER M5 ;
        RECT  63.504 0 63.528 0.084 ;
    END
  END o_line[340]
  PIN o_line[341]
    DIRECTION OUTPUT ;
    USE SIGNAL ;
    PORT
      LAYER M5 ;
        RECT  63.6 0 63.624 0.084 ;
    END
  END o_line[341]
  PIN o_line[342]
    DIRECTION OUTPUT ;
    USE SIGNAL ;
    PORT
      LAYER M5 ;
        RECT  63.696 0 63.72 0.084 ;
    END
  END o_line[342]
  PIN o_line[343]
    DIRECTION OUTPUT ;
    USE SIGNAL ;
    PORT
      LAYER M5 ;
        RECT  63.792 0 63.816 0.084 ;
    END
  END o_line[343]
  PIN o_line[344]
    DIRECTION OUTPUT ;
    USE SIGNAL ;
    PORT
      LAYER M5 ;
        RECT  63.888 0 63.912 0.084 ;
    END
  END o_line[344]
  PIN o_line[345]
    DIRECTION OUTPUT ;
    USE SIGNAL ;
    PORT
      LAYER M5 ;
        RECT  63.984 0 64.008 0.084 ;
    END
  END o_line[345]
  PIN o_line[346]
    DIRECTION OUTPUT ;
    USE SIGNAL ;
    PORT
      LAYER M5 ;
        RECT  64.08 0 64.104 0.084 ;
    END
  END o_line[346]
  PIN o_line[347]
    DIRECTION OUTPUT ;
    USE SIGNAL ;
    PORT
      LAYER M5 ;
        RECT  64.176 0 64.2 0.084 ;
    END
  END o_line[347]
  PIN o_line[348]
    DIRECTION OUTPUT ;
    USE SIGNAL ;
    PORT
      LAYER M5 ;
        RECT  64.272 0 64.296 0.084 ;
    END
  END o_line[348]
  PIN o_line[349]
    DIRECTION OUTPUT ;
    USE SIGNAL ;
    PORT
      LAYER M5 ;
        RECT  64.368 0 64.392 0.084 ;
    END
  END o_line[349]
  PIN o_line[34]
    DIRECTION OUTPUT ;
    USE SIGNAL ;
    PORT
      LAYER M5 ;
        RECT  45.648 0 45.672 0.084 ;
    END
  END o_line[34]
  PIN o_line[350]
    DIRECTION OUTPUT ;
    USE SIGNAL ;
    PORT
      LAYER M5 ;
        RECT  70.608 0 70.632 0.084 ;
    END
  END o_line[350]
  PIN o_line[351]
    DIRECTION OUTPUT ;
    USE SIGNAL ;
    PORT
      LAYER M5 ;
        RECT  70.704 0 70.728 0.084 ;
    END
  END o_line[351]
  PIN o_line[352]
    DIRECTION OUTPUT ;
    USE SIGNAL ;
    PORT
      LAYER M5 ;
        RECT  70.8 0 70.824 0.084 ;
    END
  END o_line[352]
  PIN o_line[353]
    DIRECTION OUTPUT ;
    USE SIGNAL ;
    PORT
      LAYER M5 ;
        RECT  70.896 0 70.92 0.084 ;
    END
  END o_line[353]
  PIN o_line[354]
    DIRECTION OUTPUT ;
    USE SIGNAL ;
    PORT
      LAYER M5 ;
        RECT  70.992 0 71.016 0.084 ;
    END
  END o_line[354]
  PIN o_line[355]
    DIRECTION OUTPUT ;
    USE SIGNAL ;
    PORT
      LAYER M5 ;
        RECT  71.088 0 71.112 0.084 ;
    END
  END o_line[355]
  PIN o_line[356]
    DIRECTION OUTPUT ;
    USE SIGNAL ;
    PORT
      LAYER M5 ;
        RECT  71.184 0 71.208 0.084 ;
    END
  END o_line[356]
  PIN o_line[357]
    DIRECTION OUTPUT ;
    USE SIGNAL ;
    PORT
      LAYER M5 ;
        RECT  71.28 0 71.304 0.084 ;
    END
  END o_line[357]
  PIN o_line[358]
    DIRECTION OUTPUT ;
    USE SIGNAL ;
    PORT
      LAYER M5 ;
        RECT  71.376 0 71.4 0.084 ;
    END
  END o_line[358]
  PIN o_line[359]
    DIRECTION OUTPUT ;
    USE SIGNAL ;
    PORT
      LAYER M5 ;
        RECT  71.472 0 71.496 0.084 ;
    END
  END o_line[359]
  PIN o_line[35]
    DIRECTION OUTPUT ;
    USE SIGNAL ;
    PORT
      LAYER M5 ;
        RECT  45.744 0 45.768 0.084 ;
    END
  END o_line[35]
  PIN o_line[360]
    DIRECTION OUTPUT ;
    USE SIGNAL ;
    PORT
      LAYER M5 ;
        RECT  71.568 0 71.592 0.084 ;
    END
  END o_line[360]
  PIN o_line[361]
    DIRECTION OUTPUT ;
    USE SIGNAL ;
    PORT
      LAYER M5 ;
        RECT  71.664 0 71.688 0.084 ;
    END
  END o_line[361]
  PIN o_line[362]
    DIRECTION OUTPUT ;
    USE SIGNAL ;
    PORT
      LAYER M5 ;
        RECT  71.76 0 71.784 0.084 ;
    END
  END o_line[362]
  PIN o_line[363]
    DIRECTION OUTPUT ;
    USE SIGNAL ;
    PORT
      LAYER M5 ;
        RECT  71.856 0 71.88 0.084 ;
    END
  END o_line[363]
  PIN o_line[364]
    DIRECTION OUTPUT ;
    USE SIGNAL ;
    PORT
      LAYER M5 ;
        RECT  71.952 0 71.976 0.084 ;
    END
  END o_line[364]
  PIN o_line[365]
    DIRECTION OUTPUT ;
    USE SIGNAL ;
    PORT
      LAYER M5 ;
        RECT  72.048 0 72.072 0.084 ;
    END
  END o_line[365]
  PIN o_line[366]
    DIRECTION OUTPUT ;
    USE SIGNAL ;
    PORT
      LAYER M5 ;
        RECT  72.144 0 72.168 0.084 ;
    END
  END o_line[366]
  PIN o_line[367]
    DIRECTION OUTPUT ;
    USE SIGNAL ;
    PORT
      LAYER M5 ;
        RECT  72.24 0 72.264 0.084 ;
    END
  END o_line[367]
  PIN o_line[368]
    DIRECTION OUTPUT ;
    USE SIGNAL ;
    PORT
      LAYER M5 ;
        RECT  72.336 0 72.36 0.084 ;
    END
  END o_line[368]
  PIN o_line[369]
    DIRECTION OUTPUT ;
    USE SIGNAL ;
    PORT
      LAYER M5 ;
        RECT  72.432 0 72.456 0.084 ;
    END
  END o_line[369]
  PIN o_line[36]
    DIRECTION OUTPUT ;
    USE SIGNAL ;
    PORT
      LAYER M5 ;
        RECT  45.84 0 45.864 0.084 ;
    END
  END o_line[36]
  PIN o_line[370]
    DIRECTION OUTPUT ;
    USE SIGNAL ;
    PORT
      LAYER M5 ;
        RECT  72.528 0 72.552 0.084 ;
    END
  END o_line[370]
  PIN o_line[371]
    DIRECTION OUTPUT ;
    USE SIGNAL ;
    PORT
      LAYER M5 ;
        RECT  72.624 0 72.648 0.084 ;
    END
  END o_line[371]
  PIN o_line[372]
    DIRECTION OUTPUT ;
    USE SIGNAL ;
    PORT
      LAYER M5 ;
        RECT  72.72 0 72.744 0.084 ;
    END
  END o_line[372]
  PIN o_line[373]
    DIRECTION OUTPUT ;
    USE SIGNAL ;
    PORT
      LAYER M5 ;
        RECT  72.816 0 72.84 0.084 ;
    END
  END o_line[373]
  PIN o_line[374]
    DIRECTION OUTPUT ;
    USE SIGNAL ;
    PORT
      LAYER M5 ;
        RECT  72.912 0 72.936 0.084 ;
    END
  END o_line[374]
  PIN o_line[375]
    DIRECTION OUTPUT ;
    USE SIGNAL ;
    PORT
      LAYER M5 ;
        RECT  73.008 0 73.032 0.084 ;
    END
  END o_line[375]
  PIN o_line[376]
    DIRECTION OUTPUT ;
    USE SIGNAL ;
    PORT
      LAYER M5 ;
        RECT  73.104 0 73.128 0.084 ;
    END
  END o_line[376]
  PIN o_line[377]
    DIRECTION OUTPUT ;
    USE SIGNAL ;
    PORT
      LAYER M5 ;
        RECT  73.2 0 73.224 0.084 ;
    END
  END o_line[377]
  PIN o_line[378]
    DIRECTION OUTPUT ;
    USE SIGNAL ;
    PORT
      LAYER M5 ;
        RECT  73.296 0 73.32 0.084 ;
    END
  END o_line[378]
  PIN o_line[379]
    DIRECTION OUTPUT ;
    USE SIGNAL ;
    PORT
      LAYER M5 ;
        RECT  73.392 0 73.416 0.084 ;
    END
  END o_line[379]
  PIN o_line[37]
    DIRECTION OUTPUT ;
    USE SIGNAL ;
    PORT
      LAYER M5 ;
        RECT  45.936 0 45.96 0.084 ;
    END
  END o_line[37]
  PIN o_line[380]
    DIRECTION OUTPUT ;
    USE SIGNAL ;
    PORT
      LAYER M5 ;
        RECT  73.488 0 73.512 0.084 ;
    END
  END o_line[380]
  PIN o_line[381]
    DIRECTION OUTPUT ;
    USE SIGNAL ;
    PORT
      LAYER M5 ;
        RECT  73.584 0 73.608 0.084 ;
    END
  END o_line[381]
  PIN o_line[382]
    DIRECTION OUTPUT ;
    USE SIGNAL ;
    PORT
      LAYER M5 ;
        RECT  89.808 0 89.832 0.084 ;
    END
  END o_line[382]
  PIN o_line[383]
    DIRECTION OUTPUT ;
    USE SIGNAL ;
    PORT
      LAYER M5 ;
        RECT  89.904 0 89.928 0.084 ;
    END
  END o_line[383]
  PIN o_line[384]
    DIRECTION OUTPUT ;
    USE SIGNAL ;
    PORT
      LAYER M5 ;
        RECT  90 0 90.024 0.084 ;
    END
  END o_line[384]
  PIN o_line[385]
    DIRECTION OUTPUT ;
    USE SIGNAL ;
    PORT
      LAYER M5 ;
        RECT  90.096 0 90.12 0.084 ;
    END
  END o_line[385]
  PIN o_line[386]
    DIRECTION OUTPUT ;
    USE SIGNAL ;
    PORT
      LAYER M5 ;
        RECT  90.192 0 90.216 0.084 ;
    END
  END o_line[386]
  PIN o_line[387]
    DIRECTION OUTPUT ;
    USE SIGNAL ;
    PORT
      LAYER M5 ;
        RECT  90.288 0 90.312 0.084 ;
    END
  END o_line[387]
  PIN o_line[388]
    DIRECTION OUTPUT ;
    USE SIGNAL ;
    PORT
      LAYER M5 ;
        RECT  90.384 0 90.408 0.084 ;
    END
  END o_line[388]
  PIN o_line[389]
    DIRECTION OUTPUT ;
    USE SIGNAL ;
    PORT
      LAYER M5 ;
        RECT  90.48 0 90.504 0.084 ;
    END
  END o_line[389]
  PIN o_line[38]
    DIRECTION OUTPUT ;
    USE SIGNAL ;
    PORT
      LAYER M5 ;
        RECT  46.032 0 46.056 0.084 ;
    END
  END o_line[38]
  PIN o_line[390]
    DIRECTION OUTPUT ;
    USE SIGNAL ;
    PORT
      LAYER M5 ;
        RECT  90.576 0 90.6 0.084 ;
    END
  END o_line[390]
  PIN o_line[391]
    DIRECTION OUTPUT ;
    USE SIGNAL ;
    PORT
      LAYER M5 ;
        RECT  90.672 0 90.696 0.084 ;
    END
  END o_line[391]
  PIN o_line[392]
    DIRECTION OUTPUT ;
    USE SIGNAL ;
    PORT
      LAYER M5 ;
        RECT  90.768 0 90.792 0.084 ;
    END
  END o_line[392]
  PIN o_line[393]
    DIRECTION OUTPUT ;
    USE SIGNAL ;
    PORT
      LAYER M5 ;
        RECT  90.864 0 90.888 0.084 ;
    END
  END o_line[393]
  PIN o_line[394]
    DIRECTION OUTPUT ;
    USE SIGNAL ;
    PORT
      LAYER M5 ;
        RECT  90.96 0 90.984 0.084 ;
    END
  END o_line[394]
  PIN o_line[395]
    DIRECTION OUTPUT ;
    USE SIGNAL ;
    PORT
      LAYER M5 ;
        RECT  91.056 0 91.08 0.084 ;
    END
  END o_line[395]
  PIN o_line[396]
    DIRECTION OUTPUT ;
    USE SIGNAL ;
    PORT
      LAYER M5 ;
        RECT  91.152 0 91.176 0.084 ;
    END
  END o_line[396]
  PIN o_line[397]
    DIRECTION OUTPUT ;
    USE SIGNAL ;
    PORT
      LAYER M5 ;
        RECT  91.248 0 91.272 0.084 ;
    END
  END o_line[397]
  PIN o_line[398]
    DIRECTION OUTPUT ;
    USE SIGNAL ;
    PORT
      LAYER M5 ;
        RECT  91.344 0 91.368 0.084 ;
    END
  END o_line[398]
  PIN o_line[399]
    DIRECTION OUTPUT ;
    USE SIGNAL ;
    PORT
      LAYER M5 ;
        RECT  91.44 0 91.464 0.084 ;
    END
  END o_line[399]
  PIN o_line[39]
    DIRECTION OUTPUT ;
    USE SIGNAL ;
    PORT
      LAYER M5 ;
        RECT  46.128 0 46.152 0.084 ;
    END
  END o_line[39]
  PIN o_line[3]
    DIRECTION OUTPUT ;
    USE SIGNAL ;
    PORT
      LAYER M5 ;
        RECT  68.016 0 68.04 0.084 ;
    END
  END o_line[3]
  PIN o_line[400]
    DIRECTION OUTPUT ;
    USE SIGNAL ;
    PORT
      LAYER M5 ;
        RECT  91.536 0 91.56 0.084 ;
    END
  END o_line[400]
  PIN o_line[401]
    DIRECTION OUTPUT ;
    USE SIGNAL ;
    PORT
      LAYER M5 ;
        RECT  91.632 0 91.656 0.084 ;
    END
  END o_line[401]
  PIN o_line[402]
    DIRECTION OUTPUT ;
    USE SIGNAL ;
    PORT
      LAYER M5 ;
        RECT  91.728 0 91.752 0.084 ;
    END
  END o_line[402]
  PIN o_line[403]
    DIRECTION OUTPUT ;
    USE SIGNAL ;
    PORT
      LAYER M5 ;
        RECT  91.824 0 91.848 0.084 ;
    END
  END o_line[403]
  PIN o_line[404]
    DIRECTION OUTPUT ;
    USE SIGNAL ;
    PORT
      LAYER M5 ;
        RECT  91.92 0 91.944 0.084 ;
    END
  END o_line[404]
  PIN o_line[405]
    DIRECTION OUTPUT ;
    USE SIGNAL ;
    PORT
      LAYER M5 ;
        RECT  92.016 0 92.04 0.084 ;
    END
  END o_line[405]
  PIN o_line[406]
    DIRECTION OUTPUT ;
    USE SIGNAL ;
    PORT
      LAYER M5 ;
        RECT  92.112 0 92.136 0.084 ;
    END
  END o_line[406]
  PIN o_line[407]
    DIRECTION OUTPUT ;
    USE SIGNAL ;
    PORT
      LAYER M5 ;
        RECT  92.208 0 92.232 0.084 ;
    END
  END o_line[407]
  PIN o_line[408]
    DIRECTION OUTPUT ;
    USE SIGNAL ;
    PORT
      LAYER M5 ;
        RECT  92.304 0 92.328 0.084 ;
    END
  END o_line[408]
  PIN o_line[409]
    DIRECTION OUTPUT ;
    USE SIGNAL ;
    PORT
      LAYER M5 ;
        RECT  92.4 0 92.424 0.084 ;
    END
  END o_line[409]
  PIN o_line[40]
    DIRECTION OUTPUT ;
    USE SIGNAL ;
    PORT
      LAYER M5 ;
        RECT  46.224 0 46.248 0.084 ;
    END
  END o_line[40]
  PIN o_line[410]
    DIRECTION OUTPUT ;
    USE SIGNAL ;
    PORT
      LAYER M5 ;
        RECT  92.496 0 92.52 0.084 ;
    END
  END o_line[410]
  PIN o_line[411]
    DIRECTION OUTPUT ;
    USE SIGNAL ;
    PORT
      LAYER M5 ;
        RECT  92.592 0 92.616 0.084 ;
    END
  END o_line[411]
  PIN o_line[412]
    DIRECTION OUTPUT ;
    USE SIGNAL ;
    PORT
      LAYER M5 ;
        RECT  92.688 0 92.712 0.084 ;
    END
  END o_line[412]
  PIN o_line[413]
    DIRECTION OUTPUT ;
    USE SIGNAL ;
    PORT
      LAYER M5 ;
        RECT  92.784 0 92.808 0.084 ;
    END
  END o_line[413]
  PIN o_line[414]
    DIRECTION OUTPUT ;
    USE SIGNAL ;
    PORT
      LAYER M5 ;
        RECT  92.88 0 92.904 0.084 ;
    END
  END o_line[414]
  PIN o_line[415]
    DIRECTION OUTPUT ;
    USE SIGNAL ;
    PORT
      LAYER M5 ;
        RECT  92.976 0 93 0.084 ;
    END
  END o_line[415]
  PIN o_line[416]
    DIRECTION OUTPUT ;
    USE SIGNAL ;
    PORT
      LAYER M5 ;
        RECT  93.072 0 93.096 0.084 ;
    END
  END o_line[416]
  PIN o_line[417]
    DIRECTION OUTPUT ;
    USE SIGNAL ;
    PORT
      LAYER M5 ;
        RECT  93.168 0 93.192 0.084 ;
    END
  END o_line[417]
  PIN o_line[418]
    DIRECTION OUTPUT ;
    USE SIGNAL ;
    PORT
      LAYER M5 ;
        RECT  93.264 0 93.288 0.084 ;
    END
  END o_line[418]
  PIN o_line[419]
    DIRECTION OUTPUT ;
    USE SIGNAL ;
    PORT
      LAYER M5 ;
        RECT  93.36 0 93.384 0.084 ;
    END
  END o_line[419]
  PIN o_line[41]
    DIRECTION OUTPUT ;
    USE SIGNAL ;
    PORT
      LAYER M5 ;
        RECT  46.32 0 46.344 0.084 ;
    END
  END o_line[41]
  PIN o_line[420]
    DIRECTION OUTPUT ;
    USE SIGNAL ;
    PORT
      LAYER M5 ;
        RECT  93.456 0 93.48 0.084 ;
    END
  END o_line[420]
  PIN o_line[421]
    DIRECTION OUTPUT ;
    USE SIGNAL ;
    PORT
      LAYER M5 ;
        RECT  93.552 0 93.576 0.084 ;
    END
  END o_line[421]
  PIN o_line[422]
    DIRECTION OUTPUT ;
    USE SIGNAL ;
    PORT
      LAYER M5 ;
        RECT  93.648 0 93.672 0.084 ;
    END
  END o_line[422]
  PIN o_line[423]
    DIRECTION OUTPUT ;
    USE SIGNAL ;
    PORT
      LAYER M5 ;
        RECT  93.744 0 93.768 0.084 ;
    END
  END o_line[423]
  PIN o_line[424]
    DIRECTION OUTPUT ;
    USE SIGNAL ;
    PORT
      LAYER M5 ;
        RECT  93.84 0 93.864 0.084 ;
    END
  END o_line[424]
  PIN o_line[425]
    DIRECTION OUTPUT ;
    USE SIGNAL ;
    PORT
      LAYER M5 ;
        RECT  93.936 0 93.96 0.084 ;
    END
  END o_line[425]
  PIN o_line[426]
    DIRECTION OUTPUT ;
    USE SIGNAL ;
    PORT
      LAYER M5 ;
        RECT  94.032 0 94.056 0.084 ;
    END
  END o_line[426]
  PIN o_line[427]
    DIRECTION OUTPUT ;
    USE SIGNAL ;
    PORT
      LAYER M5 ;
        RECT  94.128 0 94.152 0.084 ;
    END
  END o_line[427]
  PIN o_line[428]
    DIRECTION OUTPUT ;
    USE SIGNAL ;
    PORT
      LAYER M5 ;
        RECT  94.224 0 94.248 0.084 ;
    END
  END o_line[428]
  PIN o_line[429]
    DIRECTION OUTPUT ;
    USE SIGNAL ;
    PORT
      LAYER M5 ;
        RECT  94.32 0 94.344 0.084 ;
    END
  END o_line[429]
  PIN o_line[42]
    DIRECTION OUTPUT ;
    USE SIGNAL ;
    PORT
      LAYER M5 ;
        RECT  46.416 0 46.44 0.084 ;
    END
  END o_line[42]
  PIN o_line[430]
    DIRECTION OUTPUT ;
    USE SIGNAL ;
    PORT
      LAYER M5 ;
        RECT  94.416 0 94.44 0.084 ;
    END
  END o_line[430]
  PIN o_line[431]
    DIRECTION OUTPUT ;
    USE SIGNAL ;
    PORT
      LAYER M5 ;
        RECT  94.512 0 94.536 0.084 ;
    END
  END o_line[431]
  PIN o_line[432]
    DIRECTION OUTPUT ;
    USE SIGNAL ;
    PORT
      LAYER M5 ;
        RECT  94.608 0 94.632 0.084 ;
    END
  END o_line[432]
  PIN o_line[433]
    DIRECTION OUTPUT ;
    USE SIGNAL ;
    PORT
      LAYER M5 ;
        RECT  94.704 0 94.728 0.084 ;
    END
  END o_line[433]
  PIN o_line[434]
    DIRECTION OUTPUT ;
    USE SIGNAL ;
    PORT
      LAYER M5 ;
        RECT  94.8 0 94.824 0.084 ;
    END
  END o_line[434]
  PIN o_line[435]
    DIRECTION OUTPUT ;
    USE SIGNAL ;
    PORT
      LAYER M5 ;
        RECT  94.896 0 94.92 0.084 ;
    END
  END o_line[435]
  PIN o_line[436]
    DIRECTION OUTPUT ;
    USE SIGNAL ;
    PORT
      LAYER M5 ;
        RECT  94.992 0 95.016 0.084 ;
    END
  END o_line[436]
  PIN o_line[437]
    DIRECTION OUTPUT ;
    USE SIGNAL ;
    PORT
      LAYER M5 ;
        RECT  95.088 0 95.112 0.084 ;
    END
  END o_line[437]
  PIN o_line[438]
    DIRECTION OUTPUT ;
    USE SIGNAL ;
    PORT
      LAYER M5 ;
        RECT  95.184 0 95.208 0.084 ;
    END
  END o_line[438]
  PIN o_line[439]
    DIRECTION OUTPUT ;
    USE SIGNAL ;
    PORT
      LAYER M5 ;
        RECT  95.28 0 95.304 0.084 ;
    END
  END o_line[439]
  PIN o_line[43]
    DIRECTION OUTPUT ;
    USE SIGNAL ;
    PORT
      LAYER M5 ;
        RECT  46.512 0 46.536 0.084 ;
    END
  END o_line[43]
  PIN o_line[440]
    DIRECTION OUTPUT ;
    USE SIGNAL ;
    PORT
      LAYER M5 ;
        RECT  95.376 0 95.4 0.084 ;
    END
  END o_line[440]
  PIN o_line[441]
    DIRECTION OUTPUT ;
    USE SIGNAL ;
    PORT
      LAYER M5 ;
        RECT  95.472 0 95.496 0.084 ;
    END
  END o_line[441]
  PIN o_line[442]
    DIRECTION OUTPUT ;
    USE SIGNAL ;
    PORT
      LAYER M5 ;
        RECT  95.568 0 95.592 0.084 ;
    END
  END o_line[442]
  PIN o_line[443]
    DIRECTION OUTPUT ;
    USE SIGNAL ;
    PORT
      LAYER M5 ;
        RECT  95.664 0 95.688 0.084 ;
    END
  END o_line[443]
  PIN o_line[444]
    DIRECTION OUTPUT ;
    USE SIGNAL ;
    PORT
      LAYER M5 ;
        RECT  95.76 0 95.784 0.084 ;
    END
  END o_line[444]
  PIN o_line[445]
    DIRECTION OUTPUT ;
    USE SIGNAL ;
    PORT
      LAYER M5 ;
        RECT  95.856 0 95.88 0.084 ;
    END
  END o_line[445]
  PIN o_line[446]
    DIRECTION OUTPUT ;
    USE SIGNAL ;
    PORT
      LAYER M5 ;
        RECT  77.52 0 77.544 0.084 ;
    END
  END o_line[446]
  PIN o_line[447]
    DIRECTION OUTPUT ;
    USE SIGNAL ;
    PORT
      LAYER M5 ;
        RECT  77.616 0 77.64 0.084 ;
    END
  END o_line[447]
  PIN o_line[448]
    DIRECTION OUTPUT ;
    USE SIGNAL ;
    PORT
      LAYER M5 ;
        RECT  77.712 0 77.736 0.084 ;
    END
  END o_line[448]
  PIN o_line[449]
    DIRECTION OUTPUT ;
    USE SIGNAL ;
    PORT
      LAYER M5 ;
        RECT  77.808 0 77.832 0.084 ;
    END
  END o_line[449]
  PIN o_line[44]
    DIRECTION OUTPUT ;
    USE SIGNAL ;
    PORT
      LAYER M5 ;
        RECT  46.608 0 46.632 0.084 ;
    END
  END o_line[44]
  PIN o_line[450]
    DIRECTION OUTPUT ;
    USE SIGNAL ;
    PORT
      LAYER M5 ;
        RECT  77.904 0 77.928 0.084 ;
    END
  END o_line[450]
  PIN o_line[451]
    DIRECTION OUTPUT ;
    USE SIGNAL ;
    PORT
      LAYER M5 ;
        RECT  78 0 78.024 0.084 ;
    END
  END o_line[451]
  PIN o_line[452]
    DIRECTION OUTPUT ;
    USE SIGNAL ;
    PORT
      LAYER M5 ;
        RECT  78.096 0 78.12 0.084 ;
    END
  END o_line[452]
  PIN o_line[453]
    DIRECTION OUTPUT ;
    USE SIGNAL ;
    PORT
      LAYER M5 ;
        RECT  78.192 0 78.216 0.084 ;
    END
  END o_line[453]
  PIN o_line[454]
    DIRECTION OUTPUT ;
    USE SIGNAL ;
    PORT
      LAYER M5 ;
        RECT  78.288 0 78.312 0.084 ;
    END
  END o_line[454]
  PIN o_line[455]
    DIRECTION OUTPUT ;
    USE SIGNAL ;
    PORT
      LAYER M5 ;
        RECT  78.384 0 78.408 0.084 ;
    END
  END o_line[455]
  PIN o_line[456]
    DIRECTION OUTPUT ;
    USE SIGNAL ;
    PORT
      LAYER M5 ;
        RECT  78.48 0 78.504 0.084 ;
    END
  END o_line[456]
  PIN o_line[457]
    DIRECTION OUTPUT ;
    USE SIGNAL ;
    PORT
      LAYER M5 ;
        RECT  78.576 0 78.6 0.084 ;
    END
  END o_line[457]
  PIN o_line[458]
    DIRECTION OUTPUT ;
    USE SIGNAL ;
    PORT
      LAYER M5 ;
        RECT  78.672 0 78.696 0.084 ;
    END
  END o_line[458]
  PIN o_line[459]
    DIRECTION OUTPUT ;
    USE SIGNAL ;
    PORT
      LAYER M5 ;
        RECT  78.768 0 78.792 0.084 ;
    END
  END o_line[459]
  PIN o_line[45]
    DIRECTION OUTPUT ;
    USE SIGNAL ;
    PORT
      LAYER M5 ;
        RECT  46.704 0 46.728 0.084 ;
    END
  END o_line[45]
  PIN o_line[460]
    DIRECTION OUTPUT ;
    USE SIGNAL ;
    PORT
      LAYER M5 ;
        RECT  78.864 0 78.888 0.084 ;
    END
  END o_line[460]
  PIN o_line[461]
    DIRECTION OUTPUT ;
    USE SIGNAL ;
    PORT
      LAYER M5 ;
        RECT  78.96 0 78.984 0.084 ;
    END
  END o_line[461]
  PIN o_line[462]
    DIRECTION OUTPUT ;
    USE SIGNAL ;
    PORT
      LAYER M5 ;
        RECT  79.056 0 79.08 0.084 ;
    END
  END o_line[462]
  PIN o_line[463]
    DIRECTION OUTPUT ;
    USE SIGNAL ;
    PORT
      LAYER M5 ;
        RECT  79.152 0 79.176 0.084 ;
    END
  END o_line[463]
  PIN o_line[464]
    DIRECTION OUTPUT ;
    USE SIGNAL ;
    PORT
      LAYER M5 ;
        RECT  79.248 0 79.272 0.084 ;
    END
  END o_line[464]
  PIN o_line[465]
    DIRECTION OUTPUT ;
    USE SIGNAL ;
    PORT
      LAYER M5 ;
        RECT  79.344 0 79.368 0.084 ;
    END
  END o_line[465]
  PIN o_line[466]
    DIRECTION OUTPUT ;
    USE SIGNAL ;
    PORT
      LAYER M5 ;
        RECT  79.44 0 79.464 0.084 ;
    END
  END o_line[466]
  PIN o_line[467]
    DIRECTION OUTPUT ;
    USE SIGNAL ;
    PORT
      LAYER M5 ;
        RECT  79.536 0 79.56 0.084 ;
    END
  END o_line[467]
  PIN o_line[468]
    DIRECTION OUTPUT ;
    USE SIGNAL ;
    PORT
      LAYER M5 ;
        RECT  79.632 0 79.656 0.084 ;
    END
  END o_line[468]
  PIN o_line[469]
    DIRECTION OUTPUT ;
    USE SIGNAL ;
    PORT
      LAYER M5 ;
        RECT  79.728 0 79.752 0.084 ;
    END
  END o_line[469]
  PIN o_line[46]
    DIRECTION OUTPUT ;
    USE SIGNAL ;
    PORT
      LAYER M5 ;
        RECT  46.8 0 46.824 0.084 ;
    END
  END o_line[46]
  PIN o_line[470]
    DIRECTION OUTPUT ;
    USE SIGNAL ;
    PORT
      LAYER M5 ;
        RECT  79.824 0 79.848 0.084 ;
    END
  END o_line[470]
  PIN o_line[471]
    DIRECTION OUTPUT ;
    USE SIGNAL ;
    PORT
      LAYER M5 ;
        RECT  79.92 0 79.944 0.084 ;
    END
  END o_line[471]
  PIN o_line[472]
    DIRECTION OUTPUT ;
    USE SIGNAL ;
    PORT
      LAYER M5 ;
        RECT  80.016 0 80.04 0.084 ;
    END
  END o_line[472]
  PIN o_line[473]
    DIRECTION OUTPUT ;
    USE SIGNAL ;
    PORT
      LAYER M5 ;
        RECT  80.112 0 80.136 0.084 ;
    END
  END o_line[473]
  PIN o_line[474]
    DIRECTION OUTPUT ;
    USE SIGNAL ;
    PORT
      LAYER M5 ;
        RECT  80.208 0 80.232 0.084 ;
    END
  END o_line[474]
  PIN o_line[475]
    DIRECTION OUTPUT ;
    USE SIGNAL ;
    PORT
      LAYER M5 ;
        RECT  80.304 0 80.328 0.084 ;
    END
  END o_line[475]
  PIN o_line[476]
    DIRECTION OUTPUT ;
    USE SIGNAL ;
    PORT
      LAYER M5 ;
        RECT  80.4 0 80.424 0.084 ;
    END
  END o_line[476]
  PIN o_line[477]
    DIRECTION OUTPUT ;
    USE SIGNAL ;
    PORT
      LAYER M5 ;
        RECT  80.496 0 80.52 0.084 ;
    END
  END o_line[477]
  PIN o_line[478]
    DIRECTION OUTPUT ;
    USE SIGNAL ;
    PORT
      LAYER M5 ;
        RECT  48.336 0 48.36 0.084 ;
    END
  END o_line[478]
  PIN o_line[479]
    DIRECTION OUTPUT ;
    USE SIGNAL ;
    PORT
      LAYER M5 ;
        RECT  48.432 0 48.456 0.084 ;
    END
  END o_line[479]
  PIN o_line[47]
    DIRECTION OUTPUT ;
    USE SIGNAL ;
    PORT
      LAYER M5 ;
        RECT  46.896 0 46.92 0.084 ;
    END
  END o_line[47]
  PIN o_line[480]
    DIRECTION OUTPUT ;
    USE SIGNAL ;
    PORT
      LAYER M5 ;
        RECT  48.528 0 48.552 0.084 ;
    END
  END o_line[480]
  PIN o_line[481]
    DIRECTION OUTPUT ;
    USE SIGNAL ;
    PORT
      LAYER M5 ;
        RECT  48.624 0 48.648 0.084 ;
    END
  END o_line[481]
  PIN o_line[482]
    DIRECTION OUTPUT ;
    USE SIGNAL ;
    PORT
      LAYER M5 ;
        RECT  48.72 0 48.744 0.084 ;
    END
  END o_line[482]
  PIN o_line[483]
    DIRECTION OUTPUT ;
    USE SIGNAL ;
    PORT
      LAYER M5 ;
        RECT  48.816 0 48.84 0.084 ;
    END
  END o_line[483]
  PIN o_line[484]
    DIRECTION OUTPUT ;
    USE SIGNAL ;
    PORT
      LAYER M5 ;
        RECT  48.912 0 48.936 0.084 ;
    END
  END o_line[484]
  PIN o_line[485]
    DIRECTION OUTPUT ;
    USE SIGNAL ;
    PORT
      LAYER M5 ;
        RECT  49.008 0 49.032 0.084 ;
    END
  END o_line[485]
  PIN o_line[486]
    DIRECTION OUTPUT ;
    USE SIGNAL ;
    PORT
      LAYER M5 ;
        RECT  49.104 0 49.128 0.084 ;
    END
  END o_line[486]
  PIN o_line[487]
    DIRECTION OUTPUT ;
    USE SIGNAL ;
    PORT
      LAYER M5 ;
        RECT  49.2 0 49.224 0.084 ;
    END
  END o_line[487]
  PIN o_line[488]
    DIRECTION OUTPUT ;
    USE SIGNAL ;
    PORT
      LAYER M5 ;
        RECT  49.296 0 49.32 0.084 ;
    END
  END o_line[488]
  PIN o_line[489]
    DIRECTION OUTPUT ;
    USE SIGNAL ;
    PORT
      LAYER M5 ;
        RECT  49.392 0 49.416 0.084 ;
    END
  END o_line[489]
  PIN o_line[48]
    DIRECTION OUTPUT ;
    USE SIGNAL ;
    PORT
      LAYER M5 ;
        RECT  46.992 0 47.016 0.084 ;
    END
  END o_line[48]
  PIN o_line[490]
    DIRECTION OUTPUT ;
    USE SIGNAL ;
    PORT
      LAYER M5 ;
        RECT  49.488 0 49.512 0.084 ;
    END
  END o_line[490]
  PIN o_line[491]
    DIRECTION OUTPUT ;
    USE SIGNAL ;
    PORT
      LAYER M5 ;
        RECT  49.584 0 49.608 0.084 ;
    END
  END o_line[491]
  PIN o_line[492]
    DIRECTION OUTPUT ;
    USE SIGNAL ;
    PORT
      LAYER M5 ;
        RECT  49.68 0 49.704 0.084 ;
    END
  END o_line[492]
  PIN o_line[493]
    DIRECTION OUTPUT ;
    USE SIGNAL ;
    PORT
      LAYER M5 ;
        RECT  49.776 0 49.8 0.084 ;
    END
  END o_line[493]
  PIN o_line[494]
    DIRECTION OUTPUT ;
    USE SIGNAL ;
    PORT
      LAYER M5 ;
        RECT  49.872 0 49.896 0.084 ;
    END
  END o_line[494]
  PIN o_line[495]
    DIRECTION OUTPUT ;
    USE SIGNAL ;
    PORT
      LAYER M5 ;
        RECT  49.968 0 49.992 0.084 ;
    END
  END o_line[495]
  PIN o_line[496]
    DIRECTION OUTPUT ;
    USE SIGNAL ;
    PORT
      LAYER M5 ;
        RECT  50.064 0 50.088 0.084 ;
    END
  END o_line[496]
  PIN o_line[497]
    DIRECTION OUTPUT ;
    USE SIGNAL ;
    PORT
      LAYER M5 ;
        RECT  50.16 0 50.184 0.084 ;
    END
  END o_line[497]
  PIN o_line[498]
    DIRECTION OUTPUT ;
    USE SIGNAL ;
    PORT
      LAYER M5 ;
        RECT  50.256 0 50.28 0.084 ;
    END
  END o_line[498]
  PIN o_line[499]
    DIRECTION OUTPUT ;
    USE SIGNAL ;
    PORT
      LAYER M5 ;
        RECT  50.352 0 50.376 0.084 ;
    END
  END o_line[499]
  PIN o_line[49]
    DIRECTION OUTPUT ;
    USE SIGNAL ;
    PORT
      LAYER M5 ;
        RECT  47.088 0 47.112 0.084 ;
    END
  END o_line[49]
  PIN o_line[4]
    DIRECTION OUTPUT ;
    USE SIGNAL ;
    PORT
      LAYER M5 ;
        RECT  68.112 0 68.136 0.084 ;
    END
  END o_line[4]
  PIN o_line[500]
    DIRECTION OUTPUT ;
    USE SIGNAL ;
    PORT
      LAYER M5 ;
        RECT  50.448 0 50.472 0.084 ;
    END
  END o_line[500]
  PIN o_line[501]
    DIRECTION OUTPUT ;
    USE SIGNAL ;
    PORT
      LAYER M5 ;
        RECT  50.544 0 50.568 0.084 ;
    END
  END o_line[501]
  PIN o_line[502]
    DIRECTION OUTPUT ;
    USE SIGNAL ;
    PORT
      LAYER M5 ;
        RECT  50.64 0 50.664 0.084 ;
    END
  END o_line[502]
  PIN o_line[503]
    DIRECTION OUTPUT ;
    USE SIGNAL ;
    PORT
      LAYER M5 ;
        RECT  50.736 0 50.76 0.084 ;
    END
  END o_line[503]
  PIN o_line[504]
    DIRECTION OUTPUT ;
    USE SIGNAL ;
    PORT
      LAYER M5 ;
        RECT  50.832 0 50.856 0.084 ;
    END
  END o_line[504]
  PIN o_line[505]
    DIRECTION OUTPUT ;
    USE SIGNAL ;
    PORT
      LAYER M5 ;
        RECT  50.928 0 50.952 0.084 ;
    END
  END o_line[505]
  PIN o_line[506]
    DIRECTION OUTPUT ;
    USE SIGNAL ;
    PORT
      LAYER M5 ;
        RECT  51.024 0 51.048 0.084 ;
    END
  END o_line[506]
  PIN o_line[507]
    DIRECTION OUTPUT ;
    USE SIGNAL ;
    PORT
      LAYER M5 ;
        RECT  51.12 0 51.144 0.084 ;
    END
  END o_line[507]
  PIN o_line[508]
    DIRECTION OUTPUT ;
    USE SIGNAL ;
    PORT
      LAYER M5 ;
        RECT  51.216 0 51.24 0.084 ;
    END
  END o_line[508]
  PIN o_line[509]
    DIRECTION OUTPUT ;
    USE SIGNAL ;
    PORT
      LAYER M5 ;
        RECT  51.312 0 51.336 0.084 ;
    END
  END o_line[509]
  PIN o_line[50]
    DIRECTION OUTPUT ;
    USE SIGNAL ;
    PORT
      LAYER M5 ;
        RECT  47.184 0 47.208 0.084 ;
    END
  END o_line[50]
  PIN o_line[510]
    DIRECTION OUTPUT ;
    USE SIGNAL ;
    PORT
      LAYER M5 ;
        RECT  80.592 0 80.616 0.084 ;
    END
  END o_line[510]
  PIN o_line[511]
    DIRECTION OUTPUT ;
    USE SIGNAL ;
    PORT
      LAYER M5 ;
        RECT  80.688 0 80.712 0.084 ;
    END
  END o_line[511]
  PIN o_line[512]
    DIRECTION OUTPUT ;
    USE SIGNAL ;
    PORT
      LAYER M5 ;
        RECT  80.784 0 80.808 0.084 ;
    END
  END o_line[512]
  PIN o_line[513]
    DIRECTION OUTPUT ;
    USE SIGNAL ;
    PORT
      LAYER M5 ;
        RECT  80.88 0 80.904 0.084 ;
    END
  END o_line[513]
  PIN o_line[514]
    DIRECTION OUTPUT ;
    USE SIGNAL ;
    PORT
      LAYER M5 ;
        RECT  80.976 0 81 0.084 ;
    END
  END o_line[514]
  PIN o_line[515]
    DIRECTION OUTPUT ;
    USE SIGNAL ;
    PORT
      LAYER M5 ;
        RECT  81.072 0 81.096 0.084 ;
    END
  END o_line[515]
  PIN o_line[516]
    DIRECTION OUTPUT ;
    USE SIGNAL ;
    PORT
      LAYER M5 ;
        RECT  81.168 0 81.192 0.084 ;
    END
  END o_line[516]
  PIN o_line[517]
    DIRECTION OUTPUT ;
    USE SIGNAL ;
    PORT
      LAYER M5 ;
        RECT  81.264 0 81.288 0.084 ;
    END
  END o_line[517]
  PIN o_line[518]
    DIRECTION OUTPUT ;
    USE SIGNAL ;
    PORT
      LAYER M5 ;
        RECT  81.36 0 81.384 0.084 ;
    END
  END o_line[518]
  PIN o_line[519]
    DIRECTION OUTPUT ;
    USE SIGNAL ;
    PORT
      LAYER M5 ;
        RECT  81.456 0 81.48 0.084 ;
    END
  END o_line[519]
  PIN o_line[51]
    DIRECTION OUTPUT ;
    USE SIGNAL ;
    PORT
      LAYER M5 ;
        RECT  47.28 0 47.304 0.084 ;
    END
  END o_line[51]
  PIN o_line[520]
    DIRECTION OUTPUT ;
    USE SIGNAL ;
    PORT
      LAYER M5 ;
        RECT  81.552 0 81.576 0.084 ;
    END
  END o_line[520]
  PIN o_line[521]
    DIRECTION OUTPUT ;
    USE SIGNAL ;
    PORT
      LAYER M5 ;
        RECT  81.648 0 81.672 0.084 ;
    END
  END o_line[521]
  PIN o_line[522]
    DIRECTION OUTPUT ;
    USE SIGNAL ;
    PORT
      LAYER M5 ;
        RECT  81.744 0 81.768 0.084 ;
    END
  END o_line[522]
  PIN o_line[523]
    DIRECTION OUTPUT ;
    USE SIGNAL ;
    PORT
      LAYER M5 ;
        RECT  81.84 0 81.864 0.084 ;
    END
  END o_line[523]
  PIN o_line[524]
    DIRECTION OUTPUT ;
    USE SIGNAL ;
    PORT
      LAYER M5 ;
        RECT  81.936 0 81.96 0.084 ;
    END
  END o_line[524]
  PIN o_line[525]
    DIRECTION OUTPUT ;
    USE SIGNAL ;
    PORT
      LAYER M5 ;
        RECT  82.032 0 82.056 0.084 ;
    END
  END o_line[525]
  PIN o_line[526]
    DIRECTION OUTPUT ;
    USE SIGNAL ;
    PORT
      LAYER M5 ;
        RECT  82.128 0 82.152 0.084 ;
    END
  END o_line[526]
  PIN o_line[527]
    DIRECTION OUTPUT ;
    USE SIGNAL ;
    PORT
      LAYER M5 ;
        RECT  82.224 0 82.248 0.084 ;
    END
  END o_line[527]
  PIN o_line[528]
    DIRECTION OUTPUT ;
    USE SIGNAL ;
    PORT
      LAYER M5 ;
        RECT  82.32 0 82.344 0.084 ;
    END
  END o_line[528]
  PIN o_line[529]
    DIRECTION OUTPUT ;
    USE SIGNAL ;
    PORT
      LAYER M5 ;
        RECT  82.416 0 82.44 0.084 ;
    END
  END o_line[529]
  PIN o_line[52]
    DIRECTION OUTPUT ;
    USE SIGNAL ;
    PORT
      LAYER M5 ;
        RECT  47.376 0 47.4 0.084 ;
    END
  END o_line[52]
  PIN o_line[530]
    DIRECTION OUTPUT ;
    USE SIGNAL ;
    PORT
      LAYER M5 ;
        RECT  82.512 0 82.536 0.084 ;
    END
  END o_line[530]
  PIN o_line[531]
    DIRECTION OUTPUT ;
    USE SIGNAL ;
    PORT
      LAYER M5 ;
        RECT  82.608 0 82.632 0.084 ;
    END
  END o_line[531]
  PIN o_line[532]
    DIRECTION OUTPUT ;
    USE SIGNAL ;
    PORT
      LAYER M5 ;
        RECT  82.704 0 82.728 0.084 ;
    END
  END o_line[532]
  PIN o_line[533]
    DIRECTION OUTPUT ;
    USE SIGNAL ;
    PORT
      LAYER M5 ;
        RECT  82.8 0 82.824 0.084 ;
    END
  END o_line[533]
  PIN o_line[534]
    DIRECTION OUTPUT ;
    USE SIGNAL ;
    PORT
      LAYER M5 ;
        RECT  82.896 0 82.92 0.084 ;
    END
  END o_line[534]
  PIN o_line[535]
    DIRECTION OUTPUT ;
    USE SIGNAL ;
    PORT
      LAYER M5 ;
        RECT  82.992 0 83.016 0.084 ;
    END
  END o_line[535]
  PIN o_line[536]
    DIRECTION OUTPUT ;
    USE SIGNAL ;
    PORT
      LAYER M5 ;
        RECT  83.088 0 83.112 0.084 ;
    END
  END o_line[536]
  PIN o_line[537]
    DIRECTION OUTPUT ;
    USE SIGNAL ;
    PORT
      LAYER M5 ;
        RECT  83.184 0 83.208 0.084 ;
    END
  END o_line[537]
  PIN o_line[538]
    DIRECTION OUTPUT ;
    USE SIGNAL ;
    PORT
      LAYER M5 ;
        RECT  83.28 0 83.304 0.084 ;
    END
  END o_line[538]
  PIN o_line[539]
    DIRECTION OUTPUT ;
    USE SIGNAL ;
    PORT
      LAYER M5 ;
        RECT  83.376 0 83.4 0.084 ;
    END
  END o_line[539]
  PIN o_line[53]
    DIRECTION OUTPUT ;
    USE SIGNAL ;
    PORT
      LAYER M5 ;
        RECT  47.472 0 47.496 0.084 ;
    END
  END o_line[53]
  PIN o_line[540]
    DIRECTION OUTPUT ;
    USE SIGNAL ;
    PORT
      LAYER M5 ;
        RECT  83.472 0 83.496 0.084 ;
    END
  END o_line[540]
  PIN o_line[541]
    DIRECTION OUTPUT ;
    USE SIGNAL ;
    PORT
      LAYER M5 ;
        RECT  83.568 0 83.592 0.084 ;
    END
  END o_line[541]
  PIN o_line[542]
    DIRECTION OUTPUT ;
    USE SIGNAL ;
    PORT
      LAYER M5 ;
        RECT  54.48 0 54.504 0.084 ;
    END
  END o_line[542]
  PIN o_line[543]
    DIRECTION OUTPUT ;
    USE SIGNAL ;
    PORT
      LAYER M5 ;
        RECT  54.576 0 54.6 0.084 ;
    END
  END o_line[543]
  PIN o_line[544]
    DIRECTION OUTPUT ;
    USE SIGNAL ;
    PORT
      LAYER M5 ;
        RECT  54.672 0 54.696 0.084 ;
    END
  END o_line[544]
  PIN o_line[545]
    DIRECTION OUTPUT ;
    USE SIGNAL ;
    PORT
      LAYER M5 ;
        RECT  54.768 0 54.792 0.084 ;
    END
  END o_line[545]
  PIN o_line[546]
    DIRECTION OUTPUT ;
    USE SIGNAL ;
    PORT
      LAYER M5 ;
        RECT  54.864 0 54.888 0.084 ;
    END
  END o_line[546]
  PIN o_line[547]
    DIRECTION OUTPUT ;
    USE SIGNAL ;
    PORT
      LAYER M5 ;
        RECT  54.96 0 54.984 0.084 ;
    END
  END o_line[547]
  PIN o_line[548]
    DIRECTION OUTPUT ;
    USE SIGNAL ;
    PORT
      LAYER M5 ;
        RECT  55.056 0 55.08 0.084 ;
    END
  END o_line[548]
  PIN o_line[549]
    DIRECTION OUTPUT ;
    USE SIGNAL ;
    PORT
      LAYER M5 ;
        RECT  55.152 0 55.176 0.084 ;
    END
  END o_line[549]
  PIN o_line[54]
    DIRECTION OUTPUT ;
    USE SIGNAL ;
    PORT
      LAYER M5 ;
        RECT  47.568 0 47.592 0.084 ;
    END
  END o_line[54]
  PIN o_line[550]
    DIRECTION OUTPUT ;
    USE SIGNAL ;
    PORT
      LAYER M5 ;
        RECT  55.248 0 55.272 0.084 ;
    END
  END o_line[550]
  PIN o_line[551]
    DIRECTION OUTPUT ;
    USE SIGNAL ;
    PORT
      LAYER M5 ;
        RECT  55.344 0 55.368 0.084 ;
    END
  END o_line[551]
  PIN o_line[552]
    DIRECTION OUTPUT ;
    USE SIGNAL ;
    PORT
      LAYER M5 ;
        RECT  55.44 0 55.464 0.084 ;
    END
  END o_line[552]
  PIN o_line[553]
    DIRECTION OUTPUT ;
    USE SIGNAL ;
    PORT
      LAYER M5 ;
        RECT  55.536 0 55.56 0.084 ;
    END
  END o_line[553]
  PIN o_line[554]
    DIRECTION OUTPUT ;
    USE SIGNAL ;
    PORT
      LAYER M5 ;
        RECT  55.632 0 55.656 0.084 ;
    END
  END o_line[554]
  PIN o_line[555]
    DIRECTION OUTPUT ;
    USE SIGNAL ;
    PORT
      LAYER M5 ;
        RECT  55.728 0 55.752 0.084 ;
    END
  END o_line[555]
  PIN o_line[556]
    DIRECTION OUTPUT ;
    USE SIGNAL ;
    PORT
      LAYER M5 ;
        RECT  55.824 0 55.848 0.084 ;
    END
  END o_line[556]
  PIN o_line[557]
    DIRECTION OUTPUT ;
    USE SIGNAL ;
    PORT
      LAYER M5 ;
        RECT  55.92 0 55.944 0.084 ;
    END
  END o_line[557]
  PIN o_line[558]
    DIRECTION OUTPUT ;
    USE SIGNAL ;
    PORT
      LAYER M5 ;
        RECT  56.016 0 56.04 0.084 ;
    END
  END o_line[558]
  PIN o_line[559]
    DIRECTION OUTPUT ;
    USE SIGNAL ;
    PORT
      LAYER M5 ;
        RECT  56.112 0 56.136 0.084 ;
    END
  END o_line[559]
  PIN o_line[55]
    DIRECTION OUTPUT ;
    USE SIGNAL ;
    PORT
      LAYER M5 ;
        RECT  47.664 0 47.688 0.084 ;
    END
  END o_line[55]
  PIN o_line[560]
    DIRECTION OUTPUT ;
    USE SIGNAL ;
    PORT
      LAYER M5 ;
        RECT  56.208 0 56.232 0.084 ;
    END
  END o_line[560]
  PIN o_line[561]
    DIRECTION OUTPUT ;
    USE SIGNAL ;
    PORT
      LAYER M5 ;
        RECT  56.304 0 56.328 0.084 ;
    END
  END o_line[561]
  PIN o_line[562]
    DIRECTION OUTPUT ;
    USE SIGNAL ;
    PORT
      LAYER M5 ;
        RECT  56.4 0 56.424 0.084 ;
    END
  END o_line[562]
  PIN o_line[563]
    DIRECTION OUTPUT ;
    USE SIGNAL ;
    PORT
      LAYER M5 ;
        RECT  56.496 0 56.52 0.084 ;
    END
  END o_line[563]
  PIN o_line[564]
    DIRECTION OUTPUT ;
    USE SIGNAL ;
    PORT
      LAYER M5 ;
        RECT  56.592 0 56.616 0.084 ;
    END
  END o_line[564]
  PIN o_line[565]
    DIRECTION OUTPUT ;
    USE SIGNAL ;
    PORT
      LAYER M5 ;
        RECT  56.688 0 56.712 0.084 ;
    END
  END o_line[565]
  PIN o_line[566]
    DIRECTION OUTPUT ;
    USE SIGNAL ;
    PORT
      LAYER M5 ;
        RECT  56.784 0 56.808 0.084 ;
    END
  END o_line[566]
  PIN o_line[567]
    DIRECTION OUTPUT ;
    USE SIGNAL ;
    PORT
      LAYER M5 ;
        RECT  56.88 0 56.904 0.084 ;
    END
  END o_line[567]
  PIN o_line[568]
    DIRECTION OUTPUT ;
    USE SIGNAL ;
    PORT
      LAYER M5 ;
        RECT  56.976 0 57 0.084 ;
    END
  END o_line[568]
  PIN o_line[569]
    DIRECTION OUTPUT ;
    USE SIGNAL ;
    PORT
      LAYER M5 ;
        RECT  57.072 0 57.096 0.084 ;
    END
  END o_line[569]
  PIN o_line[56]
    DIRECTION OUTPUT ;
    USE SIGNAL ;
    PORT
      LAYER M5 ;
        RECT  47.76 0 47.784 0.084 ;
    END
  END o_line[56]
  PIN o_line[570]
    DIRECTION OUTPUT ;
    USE SIGNAL ;
    PORT
      LAYER M5 ;
        RECT  57.168 0 57.192 0.084 ;
    END
  END o_line[570]
  PIN o_line[571]
    DIRECTION OUTPUT ;
    USE SIGNAL ;
    PORT
      LAYER M5 ;
        RECT  57.264 0 57.288 0.084 ;
    END
  END o_line[571]
  PIN o_line[572]
    DIRECTION OUTPUT ;
    USE SIGNAL ;
    PORT
      LAYER M5 ;
        RECT  57.36 0 57.384 0.084 ;
    END
  END o_line[572]
  PIN o_line[573]
    DIRECTION OUTPUT ;
    USE SIGNAL ;
    PORT
      LAYER M5 ;
        RECT  57.456 0 57.48 0.084 ;
    END
  END o_line[573]
  PIN o_line[574]
    DIRECTION OUTPUT ;
    USE SIGNAL ;
    PORT
      LAYER M5 ;
        RECT  51.408 0 51.432 0.084 ;
    END
  END o_line[574]
  PIN o_line[575]
    DIRECTION OUTPUT ;
    USE SIGNAL ;
    PORT
      LAYER M5 ;
        RECT  51.504 0 51.528 0.084 ;
    END
  END o_line[575]
  PIN o_line[576]
    DIRECTION OUTPUT ;
    USE SIGNAL ;
    PORT
      LAYER M5 ;
        RECT  51.6 0 51.624 0.084 ;
    END
  END o_line[576]
  PIN o_line[577]
    DIRECTION OUTPUT ;
    USE SIGNAL ;
    PORT
      LAYER M5 ;
        RECT  51.696 0 51.72 0.084 ;
    END
  END o_line[577]
  PIN o_line[578]
    DIRECTION OUTPUT ;
    USE SIGNAL ;
    PORT
      LAYER M5 ;
        RECT  51.792 0 51.816 0.084 ;
    END
  END o_line[578]
  PIN o_line[579]
    DIRECTION OUTPUT ;
    USE SIGNAL ;
    PORT
      LAYER M5 ;
        RECT  51.888 0 51.912 0.084 ;
    END
  END o_line[579]
  PIN o_line[57]
    DIRECTION OUTPUT ;
    USE SIGNAL ;
    PORT
      LAYER M5 ;
        RECT  47.856 0 47.88 0.084 ;
    END
  END o_line[57]
  PIN o_line[580]
    DIRECTION OUTPUT ;
    USE SIGNAL ;
    PORT
      LAYER M5 ;
        RECT  51.984 0 52.008 0.084 ;
    END
  END o_line[580]
  PIN o_line[581]
    DIRECTION OUTPUT ;
    USE SIGNAL ;
    PORT
      LAYER M5 ;
        RECT  52.08 0 52.104 0.084 ;
    END
  END o_line[581]
  PIN o_line[582]
    DIRECTION OUTPUT ;
    USE SIGNAL ;
    PORT
      LAYER M5 ;
        RECT  52.176 0 52.2 0.084 ;
    END
  END o_line[582]
  PIN o_line[583]
    DIRECTION OUTPUT ;
    USE SIGNAL ;
    PORT
      LAYER M5 ;
        RECT  52.272 0 52.296 0.084 ;
    END
  END o_line[583]
  PIN o_line[584]
    DIRECTION OUTPUT ;
    USE SIGNAL ;
    PORT
      LAYER M5 ;
        RECT  52.368 0 52.392 0.084 ;
    END
  END o_line[584]
  PIN o_line[585]
    DIRECTION OUTPUT ;
    USE SIGNAL ;
    PORT
      LAYER M5 ;
        RECT  52.464 0 52.488 0.084 ;
    END
  END o_line[585]
  PIN o_line[586]
    DIRECTION OUTPUT ;
    USE SIGNAL ;
    PORT
      LAYER M5 ;
        RECT  52.56 0 52.584 0.084 ;
    END
  END o_line[586]
  PIN o_line[587]
    DIRECTION OUTPUT ;
    USE SIGNAL ;
    PORT
      LAYER M5 ;
        RECT  52.656 0 52.68 0.084 ;
    END
  END o_line[587]
  PIN o_line[588]
    DIRECTION OUTPUT ;
    USE SIGNAL ;
    PORT
      LAYER M5 ;
        RECT  52.752 0 52.776 0.084 ;
    END
  END o_line[588]
  PIN o_line[589]
    DIRECTION OUTPUT ;
    USE SIGNAL ;
    PORT
      LAYER M5 ;
        RECT  52.848 0 52.872 0.084 ;
    END
  END o_line[589]
  PIN o_line[58]
    DIRECTION OUTPUT ;
    USE SIGNAL ;
    PORT
      LAYER M5 ;
        RECT  47.952 0 47.976 0.084 ;
    END
  END o_line[58]
  PIN o_line[590]
    DIRECTION OUTPUT ;
    USE SIGNAL ;
    PORT
      LAYER M5 ;
        RECT  52.944 0 52.968 0.084 ;
    END
  END o_line[590]
  PIN o_line[591]
    DIRECTION OUTPUT ;
    USE SIGNAL ;
    PORT
      LAYER M5 ;
        RECT  53.04 0 53.064 0.084 ;
    END
  END o_line[591]
  PIN o_line[59]
    DIRECTION OUTPUT ;
    USE SIGNAL ;
    PORT
      LAYER M5 ;
        RECT  48.048 0 48.072 0.084 ;
    END
  END o_line[59]
  PIN o_line[5]
    DIRECTION OUTPUT ;
    USE SIGNAL ;
    PORT
      LAYER M5 ;
        RECT  68.208 0 68.232 0.084 ;
    END
  END o_line[5]
  PIN o_line[60]
    DIRECTION OUTPUT ;
    USE SIGNAL ;
    PORT
      LAYER M5 ;
        RECT  48.144 0 48.168 0.084 ;
    END
  END o_line[60]
  PIN o_line[61]
    DIRECTION OUTPUT ;
    USE SIGNAL ;
    PORT
      LAYER M5 ;
        RECT  48.24 0 48.264 0.084 ;
    END
  END o_line[61]
  PIN o_line[62]
    DIRECTION OUTPUT ;
    USE SIGNAL ;
    PORT
      LAYER M5 ;
        RECT  73.68 0 73.704 0.084 ;
    END
  END o_line[62]
  PIN o_line[63]
    DIRECTION OUTPUT ;
    USE SIGNAL ;
    PORT
      LAYER M5 ;
        RECT  73.776 0 73.8 0.084 ;
    END
  END o_line[63]
  PIN o_line[64]
    DIRECTION OUTPUT ;
    USE SIGNAL ;
    PORT
      LAYER M5 ;
        RECT  73.872 0 73.896 0.084 ;
    END
  END o_line[64]
  PIN o_line[65]
    DIRECTION OUTPUT ;
    USE SIGNAL ;
    PORT
      LAYER M5 ;
        RECT  73.968 0 73.992 0.084 ;
    END
  END o_line[65]
  PIN o_line[66]
    DIRECTION OUTPUT ;
    USE SIGNAL ;
    PORT
      LAYER M5 ;
        RECT  74.064 0 74.088 0.084 ;
    END
  END o_line[66]
  PIN o_line[67]
    DIRECTION OUTPUT ;
    USE SIGNAL ;
    PORT
      LAYER M5 ;
        RECT  74.16 0 74.184 0.084 ;
    END
  END o_line[67]
  PIN o_line[68]
    DIRECTION OUTPUT ;
    USE SIGNAL ;
    PORT
      LAYER M5 ;
        RECT  74.256 0 74.28 0.084 ;
    END
  END o_line[68]
  PIN o_line[69]
    DIRECTION OUTPUT ;
    USE SIGNAL ;
    PORT
      LAYER M5 ;
        RECT  74.352 0 74.376 0.084 ;
    END
  END o_line[69]
  PIN o_line[6]
    DIRECTION OUTPUT ;
    USE SIGNAL ;
    PORT
      LAYER M5 ;
        RECT  68.304 0 68.328 0.084 ;
    END
  END o_line[6]
  PIN o_line[70]
    DIRECTION OUTPUT ;
    USE SIGNAL ;
    PORT
      LAYER M5 ;
        RECT  74.448 0 74.472 0.084 ;
    END
  END o_line[70]
  PIN o_line[71]
    DIRECTION OUTPUT ;
    USE SIGNAL ;
    PORT
      LAYER M5 ;
        RECT  74.544 0 74.568 0.084 ;
    END
  END o_line[71]
  PIN o_line[72]
    DIRECTION OUTPUT ;
    USE SIGNAL ;
    PORT
      LAYER M5 ;
        RECT  74.64 0 74.664 0.084 ;
    END
  END o_line[72]
  PIN o_line[73]
    DIRECTION OUTPUT ;
    USE SIGNAL ;
    PORT
      LAYER M5 ;
        RECT  74.736 0 74.76 0.084 ;
    END
  END o_line[73]
  PIN o_line[74]
    DIRECTION OUTPUT ;
    USE SIGNAL ;
    PORT
      LAYER M5 ;
        RECT  74.832 0 74.856 0.084 ;
    END
  END o_line[74]
  PIN o_line[75]
    DIRECTION OUTPUT ;
    USE SIGNAL ;
    PORT
      LAYER M5 ;
        RECT  74.928 0 74.952 0.084 ;
    END
  END o_line[75]
  PIN o_line[76]
    DIRECTION OUTPUT ;
    USE SIGNAL ;
    PORT
      LAYER M5 ;
        RECT  75.024 0 75.048 0.084 ;
    END
  END o_line[76]
  PIN o_line[77]
    DIRECTION OUTPUT ;
    USE SIGNAL ;
    PORT
      LAYER M5 ;
        RECT  75.12 0 75.144 0.084 ;
    END
  END o_line[77]
  PIN o_line[78]
    DIRECTION OUTPUT ;
    USE SIGNAL ;
    PORT
      LAYER M5 ;
        RECT  75.216 0 75.24 0.084 ;
    END
  END o_line[78]
  PIN o_line[79]
    DIRECTION OUTPUT ;
    USE SIGNAL ;
    PORT
      LAYER M5 ;
        RECT  75.312 0 75.336 0.084 ;
    END
  END o_line[79]
  PIN o_line[7]
    DIRECTION OUTPUT ;
    USE SIGNAL ;
    PORT
      LAYER M5 ;
        RECT  68.4 0 68.424 0.084 ;
    END
  END o_line[7]
  PIN o_line[80]
    DIRECTION OUTPUT ;
    USE SIGNAL ;
    PORT
      LAYER M5 ;
        RECT  75.408 0 75.432 0.084 ;
    END
  END o_line[80]
  PIN o_line[81]
    DIRECTION OUTPUT ;
    USE SIGNAL ;
    PORT
      LAYER M5 ;
        RECT  75.504 0 75.528 0.084 ;
    END
  END o_line[81]
  PIN o_line[82]
    DIRECTION OUTPUT ;
    USE SIGNAL ;
    PORT
      LAYER M5 ;
        RECT  75.6 0 75.624 0.084 ;
    END
  END o_line[82]
  PIN o_line[83]
    DIRECTION OUTPUT ;
    USE SIGNAL ;
    PORT
      LAYER M5 ;
        RECT  75.696 0 75.72 0.084 ;
    END
  END o_line[83]
  PIN o_line[84]
    DIRECTION OUTPUT ;
    USE SIGNAL ;
    PORT
      LAYER M5 ;
        RECT  75.792 0 75.816 0.084 ;
    END
  END o_line[84]
  PIN o_line[85]
    DIRECTION OUTPUT ;
    USE SIGNAL ;
    PORT
      LAYER M5 ;
        RECT  75.888 0 75.912 0.084 ;
    END
  END o_line[85]
  PIN o_line[86]
    DIRECTION OUTPUT ;
    USE SIGNAL ;
    PORT
      LAYER M5 ;
        RECT  75.984 0 76.008 0.084 ;
    END
  END o_line[86]
  PIN o_line[87]
    DIRECTION OUTPUT ;
    USE SIGNAL ;
    PORT
      LAYER M5 ;
        RECT  76.08 0 76.104 0.084 ;
    END
  END o_line[87]
  PIN o_line[88]
    DIRECTION OUTPUT ;
    USE SIGNAL ;
    PORT
      LAYER M5 ;
        RECT  76.176 0 76.2 0.084 ;
    END
  END o_line[88]
  PIN o_line[89]
    DIRECTION OUTPUT ;
    USE SIGNAL ;
    PORT
      LAYER M5 ;
        RECT  76.272 0 76.296 0.084 ;
    END
  END o_line[89]
  PIN o_line[8]
    DIRECTION OUTPUT ;
    USE SIGNAL ;
    PORT
      LAYER M5 ;
        RECT  68.496 0 68.52 0.084 ;
    END
  END o_line[8]
  PIN o_line[90]
    DIRECTION OUTPUT ;
    USE SIGNAL ;
    PORT
      LAYER M5 ;
        RECT  76.368 0 76.392 0.084 ;
    END
  END o_line[90]
  PIN o_line[91]
    DIRECTION OUTPUT ;
    USE SIGNAL ;
    PORT
      LAYER M5 ;
        RECT  76.464 0 76.488 0.084 ;
    END
  END o_line[91]
  PIN o_line[92]
    DIRECTION OUTPUT ;
    USE SIGNAL ;
    PORT
      LAYER M5 ;
        RECT  76.56 0 76.584 0.084 ;
    END
  END o_line[92]
  PIN o_line[93]
    DIRECTION OUTPUT ;
    USE SIGNAL ;
    PORT
      LAYER M5 ;
        RECT  76.656 0 76.68 0.084 ;
    END
  END o_line[93]
  PIN o_line[94]
    DIRECTION OUTPUT ;
    USE SIGNAL ;
    PORT
      LAYER M5 ;
        RECT  99.792 0 99.816 0.084 ;
    END
  END o_line[94]
  PIN o_line[95]
    DIRECTION OUTPUT ;
    USE SIGNAL ;
    PORT
      LAYER M5 ;
        RECT  99.888 0 99.912 0.084 ;
    END
  END o_line[95]
  PIN o_line[96]
    DIRECTION OUTPUT ;
    USE SIGNAL ;
    PORT
      LAYER M5 ;
        RECT  99.984 0 100.008 0.084 ;
    END
  END o_line[96]
  PIN o_line[97]
    DIRECTION OUTPUT ;
    USE SIGNAL ;
    PORT
      LAYER M5 ;
        RECT  100.08 0 100.104 0.084 ;
    END
  END o_line[97]
  PIN o_line[98]
    DIRECTION OUTPUT ;
    USE SIGNAL ;
    PORT
      LAYER M5 ;
        RECT  100.176 0 100.2 0.084 ;
    END
  END o_line[98]
  PIN o_line[99]
    DIRECTION OUTPUT ;
    USE SIGNAL ;
    PORT
      LAYER M5 ;
        RECT  100.272 0 100.296 0.084 ;
    END
  END o_line[99]
  PIN o_line[9]
    DIRECTION OUTPUT ;
    USE SIGNAL ;
    PORT
      LAYER M5 ;
        RECT  68.592 0 68.616 0.084 ;
    END
  END o_line[9]
  PIN o_lv[0]
    DIRECTION OUTPUT ;
    USE SIGNAL ;
    PORT
      LAYER M5 ;
        RECT  53.136 0 53.16 0.084 ;
    END
  END o_lv[0]
  PIN o_lv[10]
    DIRECTION OUTPUT ;
    USE SIGNAL ;
    PORT
      LAYER M5 ;
        RECT  54.096 0 54.12 0.084 ;
    END
  END o_lv[10]
  PIN o_lv[11]
    DIRECTION OUTPUT ;
    USE SIGNAL ;
    PORT
      LAYER M5 ;
        RECT  54.192 0 54.216 0.084 ;
    END
  END o_lv[11]
  PIN o_lv[12]
    DIRECTION OUTPUT ;
    USE SIGNAL ;
    PORT
      LAYER M5 ;
        RECT  54.288 0 54.312 0.084 ;
    END
  END o_lv[12]
  PIN o_lv[13]
    DIRECTION OUTPUT ;
    USE SIGNAL ;
    PORT
      LAYER M5 ;
        RECT  54.384 0 54.408 0.084 ;
    END
  END o_lv[13]
  PIN o_lv[14]
    DIRECTION OUTPUT ;
    USE SIGNAL ;
    PORT
      LAYER M5 ;
        RECT  95.952 0 95.976 0.084 ;
    END
  END o_lv[14]
  PIN o_lv[15]
    DIRECTION OUTPUT ;
    USE SIGNAL ;
    PORT
      LAYER M5 ;
        RECT  96.048 0 96.072 0.084 ;
    END
  END o_lv[15]
  PIN o_lv[1]
    DIRECTION OUTPUT ;
    USE SIGNAL ;
    PORT
      LAYER M5 ;
        RECT  53.232 0 53.256 0.084 ;
    END
  END o_lv[1]
  PIN o_lv[2]
    DIRECTION OUTPUT ;
    USE SIGNAL ;
    PORT
      LAYER M5 ;
        RECT  53.328 0 53.352 0.084 ;
    END
  END o_lv[2]
  PIN o_lv[3]
    DIRECTION OUTPUT ;
    USE SIGNAL ;
    PORT
      LAYER M5 ;
        RECT  53.424 0 53.448 0.084 ;
    END
  END o_lv[3]
  PIN o_lv[4]
    DIRECTION OUTPUT ;
    USE SIGNAL ;
    PORT
      LAYER M5 ;
        RECT  53.52 0 53.544 0.084 ;
    END
  END o_lv[4]
  PIN o_lv[5]
    DIRECTION OUTPUT ;
    USE SIGNAL ;
    PORT
      LAYER M5 ;
        RECT  53.616 0 53.64 0.084 ;
    END
  END o_lv[5]
  PIN o_lv[6]
    DIRECTION OUTPUT ;
    USE SIGNAL ;
    PORT
      LAYER M5 ;
        RECT  53.712 0 53.736 0.084 ;
    END
  END o_lv[6]
  PIN o_lv[7]
    DIRECTION OUTPUT ;
    USE SIGNAL ;
    PORT
      LAYER M5 ;
        RECT  53.808 0 53.832 0.084 ;
    END
  END o_lv[7]
  PIN o_lv[8]
    DIRECTION OUTPUT ;
    USE SIGNAL ;
    PORT
      LAYER M5 ;
        RECT  53.904 0 53.928 0.084 ;
    END
  END o_lv[8]
  PIN o_lv[9]
    DIRECTION OUTPUT ;
    USE SIGNAL ;
    PORT
      LAYER M5 ;
        RECT  54 0 54.024 0.084 ;
    END
  END o_lv[9]
  PIN o_v
    DIRECTION OUTPUT ;
    USE SIGNAL ;
    PORT
      LAYER M5 ;
        RECT  96.144 0 96.168 0.084 ;
    END
  END o_v
  PIN rst_n
    DIRECTION INPUT ;
    USE SIGNAL ;
    PORT
      LAYER M5 ;
        RECT  31.152 56.076 31.176 56.16 ;
    END
  END rst_n
  PIN VDD
    DIRECTION INOUT ;
    USE POWER ;
    PORT
      LAYER M6 ;
        RECT  2.16 47.6 105.84 47.888 ;
        RECT  2.16 36.8 105.84 37.088 ;
        RECT  2.16 26 105.84 26.288 ;
        RECT  2.16 15.2 105.84 15.488 ;
        RECT  2.16 4.4 105.84 4.688 ;
    END
  END VDD
  PIN VSS
    DIRECTION INOUT ;
    USE GROUND ;
    PORT
      LAYER M6 ;
        RECT  2.16 47.216 105.84 47.504 ;
        RECT  2.16 36.416 105.84 36.704 ;
        RECT  2.16 25.616 105.84 25.904 ;
        RECT  2.16 14.816 105.84 15.104 ;
        RECT  2.16 4.016 105.84 4.304 ;
    END
  END VSS
  OBS
    LAYER RVTN ;
     RECT  2.16 2.16 105.84 2.295 ;
     RECT  2.16 2.565 105.84 2.835 ;
     RECT  2.16 3.105 105.84 3.375 ;
     RECT  2.16 3.645 105.84 3.915 ;
     RECT  2.16 4.185 105.84 4.455 ;
     RECT  2.16 4.725 105.84 4.995 ;
     RECT  2.16 5.265 105.84 5.535 ;
     RECT  2.16 5.805 105.84 6.075 ;
     RECT  2.16 6.345 105.84 6.615 ;
     RECT  2.16 6.885 105.84 7.155 ;
     RECT  2.16 7.425 105.84 7.695 ;
     RECT  2.16 7.965 105.84 8.235 ;
     RECT  2.16 8.505 105.84 8.775 ;
     RECT  2.16 9.045 105.84 9.315 ;
     RECT  2.16 9.585 105.84 9.855 ;
     RECT  2.16 10.125 105.84 10.395 ;
     RECT  2.16 10.665 105.84 10.935 ;
     RECT  2.16 11.205 105.84 11.475 ;
     RECT  2.16 11.745 105.84 12.015 ;
     RECT  2.16 12.285 105.84 12.555 ;
     RECT  2.16 12.825 105.84 13.095 ;
     RECT  2.16 13.365 105.84 13.635 ;
     RECT  2.16 13.905 105.84 14.175 ;
     RECT  2.16 14.445 105.84 14.715 ;
     RECT  2.16 14.985 105.84 15.255 ;
     RECT  2.16 15.525 105.84 15.795 ;
     RECT  2.16 16.065 105.84 16.335 ;
     RECT  2.16 16.605 105.84 16.875 ;
     RECT  2.16 17.145 105.84 17.415 ;
     RECT  2.16 17.685 105.84 17.955 ;
     RECT  2.16 18.225 105.84 18.495 ;
     RECT  2.16 18.765 105.84 19.035 ;
     RECT  2.16 19.305 105.84 19.575 ;
     RECT  2.16 19.845 105.84 20.115 ;
     RECT  2.16 20.385 105.84 20.655 ;
     RECT  2.16 20.925 105.84 21.195 ;
     RECT  2.16 21.465 105.84 21.735 ;
     RECT  2.16 22.005 105.84 22.275 ;
     RECT  2.16 22.545 105.84 22.815 ;
     RECT  2.16 23.085 105.84 23.355 ;
     RECT  2.16 23.625 105.84 23.895 ;
     RECT  2.16 24.165 105.84 24.435 ;
     RECT  2.16 24.705 105.84 24.975 ;
     RECT  2.16 25.245 105.84 25.515 ;
     RECT  2.16 25.785 105.84 26.055 ;
     RECT  2.16 26.325 105.84 26.595 ;
     RECT  2.16 26.865 105.84 27.135 ;
     RECT  2.16 27.405 105.84 27.675 ;
     RECT  2.16 27.945 105.84 28.215 ;
     RECT  2.16 28.485 105.84 28.755 ;
     RECT  2.16 29.025 105.84 29.295 ;
     RECT  2.16 29.565 105.84 29.835 ;
     RECT  2.16 30.105 105.84 30.375 ;
     RECT  2.16 30.645 105.84 30.915 ;
     RECT  2.16 31.185 105.84 31.455 ;
     RECT  2.16 31.725 105.84 31.995 ;
     RECT  2.16 32.265 105.84 32.535 ;
     RECT  2.16 32.805 105.84 33.075 ;
     RECT  2.16 33.345 105.84 33.615 ;
     RECT  2.16 33.885 105.84 34.155 ;
     RECT  2.16 34.425 105.84 34.695 ;
     RECT  2.16 34.965 105.84 35.235 ;
     RECT  2.16 35.505 105.84 35.775 ;
     RECT  2.16 36.045 105.84 36.315 ;
     RECT  2.16 36.585 105.84 36.855 ;
     RECT  2.16 37.125 105.84 37.395 ;
     RECT  2.16 37.665 105.84 37.935 ;
     RECT  2.16 38.205 105.84 38.475 ;
     RECT  2.16 38.745 105.84 39.015 ;
     RECT  2.16 39.285 105.84 39.555 ;
     RECT  2.16 39.825 105.84 40.095 ;
     RECT  2.16 40.365 105.84 40.635 ;
     RECT  2.16 40.905 105.84 41.175 ;
     RECT  2.16 41.445 105.84 41.715 ;
     RECT  2.16 41.985 105.84 42.255 ;
     RECT  2.16 42.525 105.84 42.795 ;
     RECT  2.16 43.065 105.84 43.335 ;
     RECT  2.16 43.605 105.84 43.875 ;
     RECT  2.16 44.145 105.84 44.415 ;
     RECT  2.16 44.685 105.84 44.955 ;
     RECT  2.16 45.225 105.84 45.495 ;
     RECT  2.16 45.765 105.84 46.035 ;
     RECT  2.16 46.305 105.84 46.575 ;
     RECT  2.16 46.845 105.84 47.115 ;
     RECT  2.16 47.385 105.84 47.655 ;
     RECT  2.16 47.925 105.84 48.195 ;
     RECT  2.16 48.465 105.84 48.735 ;
     RECT  2.16 49.005 105.84 49.275 ;
     RECT  2.16 49.545 105.84 49.815 ;
     RECT  2.16 50.085 105.84 50.355 ;
     RECT  2.16 50.625 105.84 50.895 ;
     RECT  2.16 51.165 105.84 51.435 ;
     RECT  2.16 51.705 105.84 51.975 ;
     RECT  2.16 52.245 105.84 52.515 ;
     RECT  2.16 52.785 105.84 53.055 ;
     RECT  2.16 53.325 105.84 53.595 ;
     RECT  2.16 53.865 105.84 54 ;
    LAYER RVTP ;
     RECT  2.16 2.295 105.84 2.565 ;
     RECT  2.16 2.835 105.84 3.105 ;
     RECT  2.16 3.375 105.84 3.645 ;
     RECT  2.16 3.915 105.84 4.185 ;
     RECT  2.16 4.455 105.84 4.725 ;
     RECT  2.16 4.995 105.84 5.265 ;
     RECT  2.16 5.535 105.84 5.805 ;
     RECT  2.16 6.075 105.84 6.345 ;
     RECT  2.16 6.615 105.84 6.885 ;
     RECT  2.16 7.155 105.84 7.425 ;
     RECT  2.16 7.695 105.84 7.965 ;
     RECT  2.16 8.235 105.84 8.505 ;
     RECT  2.16 8.775 105.84 9.045 ;
     RECT  2.16 9.315 105.84 9.585 ;
     RECT  2.16 9.855 105.84 10.125 ;
     RECT  2.16 10.395 105.84 10.665 ;
     RECT  2.16 10.935 105.84 11.205 ;
     RECT  2.16 11.475 105.84 11.745 ;
     RECT  2.16 12.015 105.84 12.285 ;
     RECT  2.16 12.555 105.84 12.825 ;
     RECT  2.16 13.095 105.84 13.365 ;
     RECT  2.16 13.635 105.84 13.905 ;
     RECT  2.16 14.175 105.84 14.445 ;
     RECT  2.16 14.715 105.84 14.985 ;
     RECT  2.16 15.255 105.84 15.525 ;
     RECT  2.16 15.795 105.84 16.065 ;
     RECT  2.16 16.335 105.84 16.605 ;
     RECT  2.16 16.875 105.84 17.145 ;
     RECT  2.16 17.415 105.84 17.685 ;
     RECT  2.16 17.955 105.84 18.225 ;
     RECT  2.16 18.495 105.84 18.765 ;
     RECT  2.16 19.035 105.84 19.305 ;
     RECT  2.16 19.575 105.84 19.845 ;
     RECT  2.16 20.115 105.84 20.385 ;
     RECT  2.16 20.655 105.84 20.925 ;
     RECT  2.16 21.195 105.84 21.465 ;
     RECT  2.16 21.735 105.84 22.005 ;
     RECT  2.16 22.275 105.84 22.545 ;
     RECT  2.16 22.815 105.84 23.085 ;
     RECT  2.16 23.355 105.84 23.625 ;
     RECT  2.16 23.895 105.84 24.165 ;
     RECT  2.16 24.435 105.84 24.705 ;
     RECT  2.16 24.975 105.84 25.245 ;
     RECT  2.16 25.515 105.84 25.785 ;
     RECT  2.16 26.055 105.84 26.325 ;
     RECT  2.16 26.595 105.84 26.865 ;
     RECT  2.16 27.135 105.84 27.405 ;
     RECT  2.16 27.675 105.84 27.945 ;
     RECT  2.16 28.215 105.84 28.485 ;
     RECT  2.16 28.755 105.84 29.025 ;
     RECT  2.16 29.295 105.84 29.565 ;
     RECT  2.16 29.835 105.84 30.105 ;
     RECT  2.16 30.375 105.84 30.645 ;
     RECT  2.16 30.915 105.84 31.185 ;
     RECT  2.16 31.455 105.84 31.725 ;
     RECT  2.16 31.995 105.84 32.265 ;
     RECT  2.16 32.535 105.84 32.805 ;
     RECT  2.16 33.075 105.84 33.345 ;
     RECT  2.16 33.615 105.84 33.885 ;
     RECT  2.16 34.155 105.84 34.425 ;
     RECT  2.16 34.695 105.84 34.965 ;
     RECT  2.16 35.235 105.84 35.505 ;
     RECT  2.16 35.775 105.84 36.045 ;
     RECT  2.16 36.315 105.84 36.585 ;
     RECT  2.16 36.855 105.84 37.125 ;
     RECT  2.16 37.395 105.84 37.665 ;
     RECT  2.16 37.935 105.84 38.205 ;
     RECT  2.16 38.475 105.84 38.745 ;
     RECT  2.16 39.015 105.84 39.285 ;
     RECT  2.16 39.555 105.84 39.825 ;
     RECT  2.16 40.095 105.84 40.365 ;
     RECT  2.16 40.635 105.84 40.905 ;
     RECT  2.16 41.175 105.84 41.445 ;
     RECT  2.16 41.715 105.84 41.985 ;
     RECT  2.16 42.255 105.84 42.525 ;
     RECT  2.16 42.795 105.84 43.065 ;
     RECT  2.16 43.335 105.84 43.605 ;
     RECT  2.16 43.875 105.84 44.145 ;
     RECT  2.16 44.415 105.84 44.685 ;
     RECT  2.16 44.955 105.84 45.225 ;
     RECT  2.16 45.495 105.84 45.765 ;
     RECT  2.16 46.035 105.84 46.305 ;
     RECT  2.16 46.575 105.84 46.845 ;
     RECT  2.16 47.115 105.84 47.385 ;
     RECT  2.16 47.655 105.84 47.925 ;
     RECT  2.16 48.195 105.84 48.465 ;
     RECT  2.16 48.735 105.84 49.005 ;
     RECT  2.16 49.275 105.84 49.545 ;
     RECT  2.16 49.815 105.84 50.085 ;
     RECT  2.16 50.355 105.84 50.625 ;
     RECT  2.16 50.895 105.84 51.165 ;
     RECT  2.16 51.435 105.84 51.705 ;
     RECT  2.16 51.975 105.84 52.245 ;
     RECT  2.16 52.515 105.84 52.785 ;
     RECT  2.16 53.055 105.84 53.325 ;
     RECT  2.16 53.595 105.84 53.865 ;
    LAYER M1 ;
     RECT  2.16 2.151 105.84 54.009 ;
    LAYER M2 ;
     RECT  2.16 2.151 5.179 54.009 ;
     RECT  5.179 2.106 6.799 54.009 ;
     RECT  6.799 2.034 8.663 54.009 ;
     RECT  9.067 0.846 10.219 0.864 ;
     RECT  8.663 2.106 10.219 54.009 ;
     RECT  7.375 0.036 17.599 0.054 ;
     RECT  10.219 0.846 18.967 54.009 ;
     RECT  18.967 0.846 25.619 54.126 ;
     RECT  17.599 0.036 25.663 0.09 ;
     RECT  25.619 0.846 25.663 54.054 ;
     RECT  25.663 0.036 30.803 54.054 ;
     RECT  30.803 0.036 39.307 54.009 ;
     RECT  39.307 0.036 41.063 54.126 ;
     RECT  41.063 0.036 43.231 54.009 ;
     RECT  43.231 0.036 45.059 54.126 ;
     RECT  45.059 0.036 46.147 54.009 ;
     RECT  46.147 0.036 48.551 54.054 ;
     RECT  48.551 0.036 54.383 54.009 ;
     RECT  54.383 0.846 56.299 54.009 ;
     RECT  56.299 0.846 56.615 54.054 ;
     RECT  54.383 0.036 58.747 0.054 ;
     RECT  56.615 0.846 58.747 54.009 ;
     RECT  58.747 0.036 58.847 54.009 ;
     RECT  58.847 0.846 61.115 54.009 ;
     RECT  58.847 0.036 63.995 0.054 ;
     RECT  61.115 0.882 64.967 54.009 ;
     RECT  64.967 0.882 65.147 0.9 ;
     RECT  64.967 1.692 66.343 54.009 ;
     RECT  66.343 1.152 66.479 54.009 ;
     RECT  66.479 1.224 66.551 54.009 ;
     RECT  66.551 1.692 71.051 54.009 ;
     RECT  71.051 2.151 72.931 54.009 ;
     RECT  73.327 1.152 73.535 1.17 ;
     RECT  72.931 2.106 73.823 54.009 ;
     RECT  73.823 2.151 75.091 54.009 ;
     RECT  75.091 2.106 75.991 54.009 ;
     RECT  75.991 1.926 76.963 54.009 ;
     RECT  76.963 1.881 78.331 54.009 ;
     RECT  78.331 1.152 79.583 54.009 ;
     RECT  79.583 1.881 80.843 54.009 ;
     RECT  80.843 2.151 83.587 54.009 ;
     RECT  83.587 1.881 87.971 54.009 ;
     RECT  87.971 1.926 88.511 54.009 ;
     RECT  88.511 1.962 90.419 54.009 ;
     RECT  90.419 2.106 91.651 54.009 ;
     RECT  91.651 2.034 91.723 54.009 ;
     RECT  91.723 1.998 92.299 54.009 ;
     RECT  92.299 1.881 92.803 54.009 ;
     RECT  92.803 1.836 92.911 54.009 ;
     RECT  92.911 1.152 93.047 54.009 ;
     RECT  93.047 1.836 93.847 54.009 ;
     RECT  93.847 1.764 94.171 54.009 ;
     RECT  94.171 1.728 95.891 54.009 ;
     RECT  95.891 1.764 96.287 54.009 ;
     RECT  96.287 1.836 98.599 54.009 ;
     RECT  98.599 1.836 98.987 54.054 ;
     RECT  98.987 1.926 100.823 54.054 ;
     RECT  100.823 2.034 100.931 54.054 ;
     RECT  100.931 2.07 102.371 54.054 ;
     RECT  102.371 2.07 102.839 54.009 ;
     RECT  102.839 2.151 104.611 54.009 ;
     RECT  104.611 2.106 104.999 54.009 ;
     RECT  104.999 2.151 105.84 54.009 ;
     RECT  105.84 4.086 105.863 4.104 ;
     RECT  105.84 14.346 105.899 14.364 ;
    LAYER M3 ;
     RECT  49.68 0.031 50.202 0.067 ;
     RECT  46.26 0.043 46.278 0.091 ;
     RECT  49.608 0.067 50.202 0.091 ;
     RECT  63.972 0.031 63.99 0.091 ;
     RECT  100.116 0.043 100.134 0.091 ;
     RECT  54.72 0.091 58.662 0.103 ;
     RECT  42.768 0.043 42.786 0.139 ;
     RECT  45.144 0.091 45.306 0.139 ;
     RECT  46.26 0.091 47.466 0.139 ;
     RECT  49.608 0.091 51.534 0.139 ;
     RECT  52.38 0.091 53.01 0.139 ;
     RECT  54.36 0.103 58.662 0.139 ;
     RECT  60.372 0.091 63.99 0.139 ;
     RECT  64.944 0.091 65.142 0.139 ;
     RECT  68.544 0.091 69.498 0.139 ;
     RECT  70.632 0.091 72.954 0.139 ;
     RECT  73.764 0.091 74.43 0.139 ;
     RECT  75.168 0.091 75.186 0.139 ;
     RECT  76.788 0.091 76.806 0.139 ;
     RECT  81.828 0.091 84.006 0.139 ;
     RECT  84.816 0.091 84.834 0.139 ;
     RECT  85.788 0.091 85.806 0.139 ;
     RECT  87.084 0.091 87.102 0.139 ;
     RECT  88.236 0.091 88.254 0.139 ;
     RECT  89.856 0.091 91.674 0.139 ;
     RECT  92.916 0.091 93.042 0.139 ;
     RECT  96.552 0.091 96.966 0.139 ;
     RECT  99.036 0.091 99.054 0.139 ;
     RECT  100.044 0.091 100.566 0.139 ;
     RECT  101.304 0.091 103.266 0.139 ;
     RECT  52.38 0.139 53.37 0.187 ;
     RECT  54.108 0.139 59.202 0.187 ;
     RECT  87.084 0.139 87.174 0.187 ;
     RECT  89.856 0.139 93.114 0.187 ;
     RECT  96.444 0.139 96.966 0.187 ;
     RECT  98.784 0.139 99.054 0.187 ;
     RECT  42.768 0.139 42.822 0.221 ;
     RECT  60.372 0.139 65.142 0.235 ;
     RECT  89.1 0.187 93.51 0.235 ;
     RECT  95.22 0.043 95.238 0.235 ;
     RECT  89.1 0.235 95.238 0.269 ;
     RECT  78.876 0.091 80.658 0.283 ;
     RECT  98.46 0.187 99.054 0.283 ;
     RECT  42.804 0.221 42.822 0.284 ;
     RECT  49.5 0.139 51.534 0.317 ;
     RECT  45.144 0.139 47.466 0.413 ;
     RECT  45.144 0.413 45.306 0.427 ;
     RECT  96.444 0.187 97.146 0.475 ;
     RECT  97.956 0.283 99.09 0.475 ;
     RECT  67.5 0.091 67.518 0.523 ;
     RECT  78.48 0.283 80.658 0.523 ;
     RECT  86.976 0.187 87.174 0.523 ;
     RECT  88.236 0.139 88.326 0.523 ;
     RECT  7.38 0.031 7.398 0.571 ;
     RECT  66.06 0.091 66.69 0.571 ;
     RECT  67.5 0.523 67.626 0.571 ;
     RECT  68.544 0.139 76.914 0.571 ;
     RECT  78.336 0.523 80.658 0.571 ;
     RECT  81.396 0.139 84.834 0.571 ;
     RECT  85.788 0.139 85.914 0.571 ;
     RECT  86.976 0.523 88.326 0.571 ;
     RECT  89.1 0.269 95.166 0.571 ;
     RECT  96.444 0.475 99.09 0.571 ;
     RECT  100.044 0.139 103.266 0.571 ;
     RECT  60.264 0.235 65.142 0.619 ;
     RECT  66.06 0.571 67.626 0.619 ;
     RECT  78.336 0.571 84.834 0.667 ;
     RECT  34.74 0.475 34.758 0.715 ;
     RECT  9.072 0.841 9.09 0.859 ;
     RECT  60.048 0.619 65.142 0.905 ;
     RECT  25.668 0.139 25.686 0.985 ;
     RECT  31.32 1.003 31.338 1.021 ;
     RECT  31.32 1.021 32.058 1.051 ;
     RECT  66.06 0.619 67.698 1.099 ;
     RECT  85.788 0.571 95.166 1.099 ;
     RECT  7.38 0.571 7.758 1.147 ;
     RECT  33.696 0.091 33.714 1.147 ;
     RECT  44.568 0.427 45.306 1.147 ;
     RECT  46.044 0.413 47.466 1.147 ;
     RECT  48.348 0.571 48.366 1.147 ;
     RECT  49.608 0.317 51.534 1.147 ;
     RECT  78.336 0.667 84.978 1.147 ;
     RECT  85.788 1.099 95.202 1.147 ;
     RECT  33.696 1.147 33.786 1.175 ;
     RECT  78.336 1.147 95.202 1.175 ;
     RECT  78.48 1.175 95.202 1.195 ;
     RECT  9.072 0.859 9.486 1.387 ;
     RECT  15.372 0.811 15.39 1.387 ;
     RECT  13.572 0.877 13.59 1.453 ;
     RECT  14.544 0.949 14.562 1.453 ;
     RECT  60.048 0.905 64.962 1.481 ;
     RECT  26.46 0.103 26.478 1.489 ;
     RECT  27.288 0.907 27.306 1.489 ;
     RECT  30.204 1.099 30.222 1.579 ;
     RECT  18.756 0.763 18.774 1.627 ;
     RECT  12.384 0.913 12.402 1.675 ;
     RECT  13.572 1.453 14.562 1.675 ;
     RECT  44.568 1.147 47.466 1.675 ;
     RECT  48.204 1.147 48.366 1.675 ;
     RECT  16.524 1.435 16.542 1.687 ;
     RECT  44.568 1.675 48.366 1.723 ;
     RECT  49.608 1.147 51.606 1.723 ;
     RECT  52.38 0.187 59.202 1.723 ;
     RECT  60.048 1.481 62.694 1.723 ;
     RECT  63.432 1.481 64.962 1.723 ;
     RECT  78.48 1.195 95.562 1.723 ;
     RECT  96.444 0.571 103.266 1.723 ;
     RECT  104.148 0.091 105.678 1.723 ;
     RECT  43.344 1.723 43.362 1.759 ;
     RECT  44.568 1.723 51.606 1.759 ;
     RECT  52.38 1.723 62.694 1.759 ;
     RECT  65.808 1.099 67.698 1.771 ;
     RECT  36.576 0.235 36.594 1.819 ;
     RECT  37.476 0.139 37.494 1.819 ;
     RECT  36.576 1.819 37.494 1.831 ;
     RECT  41.22 1.795 41.238 1.831 ;
     RECT  41.148 1.831 41.886 1.876 ;
     RECT  44.568 1.759 62.694 1.876 ;
     RECT  25.632 0.985 25.686 1.921 ;
     RECT  26.46 1.489 27.306 1.921 ;
     RECT  42.984 1.759 43.362 1.921 ;
     RECT  36.18 1.831 37.494 1.957 ;
     RECT  42.804 1.921 43.362 1.957 ;
     RECT  68.508 0.571 77.49 1.957 ;
     RECT  78.48 1.723 105.678 1.957 ;
     RECT  18.756 1.627 19.206 1.963 ;
     RECT  12.384 1.675 14.562 1.993 ;
     RECT  15.372 1.387 15.75 1.993 ;
     RECT  31.32 1.051 32.382 1.993 ;
     RECT  34.74 0.715 34.902 1.993 ;
     RECT  30.024 1.579 30.222 2.011 ;
     RECT  31.176 1.993 32.382 2.011 ;
     RECT  7.236 1.147 7.758 2.029 ;
     RECT  8.82 1.387 9.486 2.029 ;
     RECT  10.224 1.417 10.242 2.029 ;
     RECT  11.376 1.819 11.394 2.029 ;
     RECT  12.384 1.993 15.75 2.029 ;
     RECT  24.336 1.531 24.354 2.029 ;
     RECT  36.18 1.957 37.782 2.029 ;
     RECT  38.736 0.187 38.754 2.029 ;
     RECT  65.772 1.771 67.698 2.029 ;
     RECT  68.508 1.957 105.678 2.029 ;
     RECT  63.432 1.723 65.034 2.059 ;
     RECT  65.772 2.029 105.678 2.059 ;
     RECT  6.804 2.029 7.758 2.101 ;
     RECT  8.64 2.029 9.486 2.101 ;
     RECT  10.224 2.029 11.394 2.101 ;
     RECT  12.168 2.029 15.75 2.101 ;
     RECT  16.524 1.687 16.83 2.101 ;
     RECT  22.14 1.993 22.158 2.101 ;
     RECT  25.632 1.921 27.306 2.101 ;
     RECT  28.152 0.955 28.17 2.101 ;
     RECT  36.18 2.029 38.754 2.101 ;
     RECT  42.804 1.957 43.614 2.101 ;
     RECT  44.352 1.876 62.694 2.101 ;
     RECT  6.084 2.101 7.758 2.143 ;
     RECT  8.568 2.101 9.486 2.143 ;
     RECT  18.756 1.963 19.566 2.143 ;
     RECT  24.336 2.029 24.39 2.143 ;
     RECT  25.632 2.101 28.746 2.143 ;
     RECT  30.024 2.011 32.382 2.143 ;
     RECT  40.215 2.143 40.305 2.155 ;
     RECT  41.04 1.876 41.886 2.155 ;
     RECT  42.804 2.101 62.694 2.155 ;
     RECT  6.084 2.143 9.486 2.191 ;
     RECT  10.224 2.101 16.83 2.191 ;
     RECT  17.604 0.067 17.622 2.191 ;
     RECT  20.736 1.483 20.754 2.191 ;
     RECT  24.015 2.143 24.39 2.191 ;
     RECT  25.632 2.143 32.382 2.191 ;
     RECT  33.768 1.175 33.786 2.191 ;
     RECT  34.74 1.993 34.974 2.191 ;
     RECT  39.6 2.155 40.305 2.191 ;
     RECT  41.04 2.155 62.694 2.191 ;
     RECT  34.74 2.191 35.154 2.203 ;
     RECT  35.928 2.101 38.754 2.203 ;
     RECT  5.184 2.101 5.202 2.227 ;
     RECT  6.084 2.191 17.622 2.227 ;
     RECT  22.068 2.101 22.158 2.227 ;
     RECT  24.015 2.191 24.858 2.227 ;
     RECT  25.632 2.191 32.634 2.227 ;
     RECT  33.696 2.191 33.786 2.227 ;
     RECT  34.74 2.203 38.754 2.227 ;
     RECT  39.6 2.191 62.694 2.227 ;
     RECT  24.015 2.227 32.778 2.251 ;
     RECT  34.74 2.227 62.694 2.251 ;
     RECT  63.432 2.059 105.678 2.251 ;
     RECT  6.084 2.227 17.694 2.263 ;
     RECT  18.615 2.143 19.566 2.263 ;
     RECT  20.412 2.191 21.078 2.263 ;
     RECT  22.068 2.227 22.23 2.263 ;
     RECT  23.724 2.251 32.778 2.263 ;
     RECT  33.696 2.227 33.966 2.263 ;
     RECT  34.74 2.251 105.678 2.263 ;
     RECT  4.032 2.227 4.05 2.299 ;
     RECT  6.084 2.263 21.078 2.299 ;
     RECT  22.068 2.263 22.446 2.299 ;
     RECT  2.415 2.143 2.505 2.335 ;
     RECT  3.456 2.299 4.05 2.335 ;
     RECT  2.415 2.335 2.646 2.371 ;
     RECT  3.42 2.335 4.05 2.371 ;
     RECT  5.184 2.227 5.31 2.371 ;
     RECT  6.084 2.299 22.446 2.371 ;
     RECT  23.4 2.263 105.678 2.371 ;
     RECT  5.148 2.371 22.446 2.497 ;
     RECT  23.184 2.371 105.678 2.497 ;
     RECT  2.415 2.371 4.302 2.641 ;
     RECT  5.076 2.497 105.678 2.641 ;
     RECT  2.415 2.641 105.678 2.731 ;
     RECT  2.376 2.731 105.678 2.831 ;
     RECT  2.415 2.831 105.678 2.839 ;
     RECT  2.415 2.839 105.75 3.811 ;
     RECT  2.415 3.811 105.786 3.979 ;
     RECT  2.415 3.979 105.858 4.109 ;
     RECT  2.415 4.109 105.786 4.801 ;
     RECT  2.34 4.801 105.786 4.955 ;
     RECT  2.415 4.955 105.786 8.879 ;
     RECT  54.972 8.879 105.786 8.969 ;
     RECT  2.415 8.879 51.606 9.085 ;
     RECT  2.376 9.085 51.606 9.643 ;
     RECT  52.488 8.879 54.234 9.643 ;
     RECT  2.376 9.643 54.234 9.691 ;
     RECT  54.972 8.969 105.714 9.691 ;
     RECT  2.376 9.691 105.714 9.821 ;
     RECT  2.415 9.821 105.714 10.319 ;
     RECT  19.944 10.319 105.714 10.589 ;
     RECT  2.415 10.319 19.17 11.137 ;
     RECT  19.944 10.589 105.678 11.137 ;
     RECT  2.415 11.137 105.678 11.467 ;
     RECT  2.415 11.467 105.714 11.995 ;
     RECT  2.376 11.995 105.714 12.479 ;
     RECT  2.415 12.479 105.714 14.135 ;
     RECT  20.628 14.135 105.714 14.251 ;
     RECT  20.628 14.251 105.894 14.369 ;
     RECT  20.628 14.369 105.714 14.639 ;
     RECT  2.415 14.135 19.854 14.675 ;
     RECT  4.716 14.675 19.854 14.875 ;
     RECT  20.628 14.639 105.642 14.875 ;
     RECT  2.415 14.675 3.978 15.403 ;
     RECT  4.716 14.875 105.642 15.403 ;
     RECT  2.415 15.403 105.714 15.449 ;
     RECT  2.415 15.449 105.642 15.755 ;
     RECT  5.004 15.755 105.642 15.863 ;
     RECT  2.415 15.755 4.266 16.141 ;
     RECT  5.112 15.863 105.642 16.259 ;
     RECT  2.376 16.141 4.266 16.445 ;
     RECT  2.376 16.445 4.194 16.565 ;
     RECT  5.112 16.259 105.606 16.651 ;
     RECT  5.004 16.651 105.606 16.799 ;
     RECT  5.004 16.799 105.534 17.339 ;
     RECT  2.376 16.565 4.122 17.455 ;
     RECT  5.004 17.339 96.318 17.455 ;
     RECT  97.056 17.339 105.534 17.617 ;
     RECT  97.056 17.617 105.714 17.693 ;
     RECT  2.376 17.455 96.318 18.121 ;
     RECT  97.056 17.693 105.57 18.121 ;
     RECT  2.376 18.121 105.57 18.221 ;
     RECT  2.376 18.221 105.534 18.293 ;
     RECT  2.376 18.293 105.462 18.805 ;
     RECT  2.34 18.805 105.462 19.507 ;
     RECT  2.34 19.507 105.642 20.155 ;
     RECT  2.34 20.155 105.714 20.579 ;
     RECT  2.415 20.579 105.714 20.909 ;
     RECT  2.415 20.909 105.534 21.821 ;
     RECT  71.244 21.821 105.534 22.469 ;
     RECT  2.415 21.821 70.506 22.621 ;
     RECT  2.376 22.621 70.506 22.891 ;
     RECT  71.244 22.469 105.39 22.891 ;
     RECT  2.376 22.891 105.39 23.189 ;
     RECT  2.415 23.189 105.297 23.935 ;
     RECT  2.376 23.935 105.297 24.431 ;
     RECT  2.415 24.431 105.297 25.085 ;
     RECT  2.415 25.085 8.478 25.511 ;
     RECT  6.012 25.511 8.478 25.853 ;
     RECT  2.415 25.511 5.238 25.861 ;
     RECT  2.376 25.861 5.238 26.045 ;
     RECT  9.216 25.085 105.297 26.365 ;
     RECT  2.415 26.045 5.238 26.491 ;
     RECT  6.012 25.853 8.19 26.491 ;
     RECT  9.216 26.365 105.426 26.563 ;
     RECT  2.415 26.491 8.19 26.761 ;
     RECT  9 26.563 105.426 26.761 ;
     RECT  2.415 26.761 105.426 27.445 ;
     RECT  2.415 27.445 105.714 27.599 ;
     RECT  2.415 27.599 105.39 28.795 ;
     RECT  2.415 28.795 105.714 29.605 ;
     RECT  2.415 29.605 105.75 29.645 ;
     RECT  2.415 29.645 105.354 30.919 ;
     RECT  2.415 30.919 105.39 30.991 ;
     RECT  2.415 30.991 105.714 31.919 ;
     RECT  2.415 31.919 105.498 33.115 ;
     RECT  2.415 33.115 105.714 33.269 ;
     RECT  2.415 33.269 105.498 33.539 ;
     RECT  2.415 33.539 105.462 33.989 ;
     RECT  2.415 33.989 105.39 34.771 ;
     RECT  2.415 34.771 105.714 36.383 ;
     RECT  2.415 36.383 105.354 38.281 ;
     RECT  2.415 38.281 105.714 38.399 ;
     RECT  2.415 38.399 105.39 38.525 ;
     RECT  2.415 38.525 105.354 39.361 ;
     RECT  2.415 39.361 105.714 39.479 ;
     RECT  2.415 39.479 105.606 39.749 ;
     RECT  97.452 39.749 105.606 39.893 ;
     RECT  97.488 39.893 105.606 40.019 ;
     RECT  97.488 40.019 105.39 40.055 ;
     RECT  97.488 40.055 105.354 40.469 ;
     RECT  2.415 39.749 96.714 40.873 ;
     RECT  2.415 40.873 96.75 41.179 ;
     RECT  2.415 41.179 96.894 41.215 ;
     RECT  97.704 40.469 105.354 41.215 ;
     RECT  2.415 41.215 105.354 41.719 ;
     RECT  2.415 41.719 105.39 41.791 ;
     RECT  2.415 41.791 105.714 41.909 ;
     RECT  2.415 41.909 105.39 42.089 ;
     RECT  2.415 42.089 94.59 42.449 ;
     RECT  95.364 42.089 105.39 42.799 ;
     RECT  10.26 42.449 94.59 42.835 ;
     RECT  95.364 42.799 105.498 42.835 ;
     RECT  10.26 42.835 105.498 43.105 ;
     RECT  2.415 42.449 9.414 43.267 ;
     RECT  10.26 43.105 105.714 43.267 ;
     RECT  2.415 43.267 105.714 44.419 ;
     RECT  2.415 44.419 105.75 44.447 ;
     RECT  86.58 44.447 105.75 44.477 ;
     RECT  86.58 44.477 105.354 44.483 ;
     RECT  2.415 44.447 85.842 44.519 ;
     RECT  86.58 44.483 105.297 44.789 ;
     RECT  2.415 44.519 85.698 45.419 ;
     RECT  96.012 44.789 105.297 45.427 ;
     RECT  4.14 45.419 85.698 45.563 ;
     RECT  4.32 45.563 85.698 45.571 ;
     RECT  86.58 44.789 95.238 45.571 ;
     RECT  4.32 45.571 95.238 45.841 ;
     RECT  96.012 45.427 105.39 45.841 ;
     RECT  4.32 45.841 105.39 45.869 ;
     RECT  2.415 45.419 2.934 46.381 ;
     RECT  95.472 45.869 105.39 46.409 ;
     RECT  95.472 46.409 105.297 46.499 ;
     RECT  4.32 45.869 94.554 46.615 ;
     RECT  95.76 46.499 105.297 46.769 ;
     RECT  4.14 46.615 94.554 46.843 ;
     RECT  2.415 46.381 3.33 46.885 ;
     RECT  4.14 46.843 94.878 46.885 ;
     RECT  96.192 46.769 105.297 47.323 ;
     RECT  2.415 46.885 94.878 47.453 ;
     RECT  6.156 47.453 94.878 47.461 ;
     RECT  96.192 47.323 105.39 47.461 ;
     RECT  6.156 47.461 95.13 47.623 ;
     RECT  96.192 47.461 105.714 47.623 ;
     RECT  6.156 47.623 105.714 47.921 ;
     RECT  96.984 47.921 105.714 47.957 ;
     RECT  2.415 47.453 5.382 48.379 ;
     RECT  6.156 47.921 96.138 48.379 ;
     RECT  97.092 47.957 105.714 48.461 ;
     RECT  2.415 48.379 96.138 48.695 ;
     RECT  97.092 48.461 105.297 48.811 ;
     RECT  71.748 48.695 96.138 48.839 ;
     RECT  71.928 48.839 96.138 48.893 ;
     RECT  72 48.893 96.138 48.901 ;
     RECT  97.02 48.811 105.297 48.901 ;
     RECT  2.415 48.695 70.902 49.243 ;
     RECT  72 48.901 105.297 49.315 ;
     RECT  72 49.315 105.714 49.469 ;
     RECT  72 49.469 105.606 49.621 ;
     RECT  2.34 49.243 70.902 49.711 ;
     RECT  2.34 49.711 71.082 50.251 ;
     RECT  71.892 49.621 105.606 50.251 ;
     RECT  2.34 50.251 105.606 50.459 ;
     RECT  2.34 50.459 95.382 50.549 ;
     RECT  96.12 50.459 105.606 50.549 ;
     RECT  72.288 50.549 95.382 50.573 ;
     RECT  96.12 50.549 105.39 50.621 ;
     RECT  72.324 50.573 95.382 51.125 ;
     RECT  2.34 50.549 71.514 51.205 ;
     RECT  80.64 51.125 95.382 51.211 ;
     RECT  96.12 50.621 105.297 51.211 ;
     RECT  2.304 51.205 71.514 51.241 ;
     RECT  80.64 51.211 105.297 51.293 ;
     RECT  2.268 51.241 71.514 51.439 ;
     RECT  80.712 51.293 105.297 51.511 ;
     RECT  2.232 51.439 71.514 51.907 ;
     RECT  72.324 51.125 79.902 51.907 ;
     RECT  2.232 51.907 79.902 51.917 ;
     RECT  68.328 51.917 79.902 52.051 ;
     RECT  80.712 51.511 105.714 52.051 ;
     RECT  68.328 52.051 105.714 52.205 ;
     RECT  76.68 52.205 105.714 52.313 ;
     RECT  76.86 52.313 105.714 52.439 ;
     RECT  76.86 52.439 105.498 52.445 ;
     RECT  2.232 51.917 67.59 52.681 ;
     RECT  68.328 52.205 75.942 52.681 ;
     RECT  2.232 52.681 75.942 52.979 ;
     RECT  64.944 52.979 75.942 53.035 ;
     RECT  76.86 52.445 105.354 53.035 ;
     RECT  64.944 53.035 105.354 53.123 ;
     RECT  64.944 53.123 76.986 53.249 ;
     RECT  77.724 53.123 105.354 53.249 ;
     RECT  77.724 53.249 91.53 53.321 ;
     RECT  77.724 53.321 89.514 53.357 ;
     RECT  92.268 53.249 105.354 53.357 ;
     RECT  92.844 53.357 105.354 53.365 ;
     RECT  77.724 53.357 85.302 53.393 ;
     RECT  92.844 53.365 105.714 53.393 ;
     RECT  64.944 53.249 66.078 53.429 ;
     RECT  66.816 53.249 76.986 53.429 ;
     RECT  65.124 53.429 66.078 53.519 ;
     RECT  67.104 53.429 76.986 53.519 ;
     RECT  78.015 53.393 85.302 53.519 ;
     RECT  86.076 53.357 89.514 53.519 ;
     RECT  90.252 53.321 91.53 53.519 ;
     RECT  92.844 53.393 95.49 53.519 ;
     RECT  96.336 53.393 105.714 53.519 ;
     RECT  2.232 52.979 64.206 53.555 ;
     RECT  65.556 53.519 65.934 53.555 ;
     RECT  67.104 53.519 68.67 53.555 ;
     RECT  69.804 53.519 76.986 53.555 ;
     RECT  78.015 53.519 85.158 53.555 ;
     RECT  90.252 53.519 91.458 53.555 ;
     RECT  92.844 53.519 95.418 53.555 ;
     RECT  65.556 53.555 65.574 53.591 ;
     RECT  90.54 53.555 91.17 53.591 ;
     RECT  96.408 53.519 97.182 53.591 ;
     RECT  97.992 53.519 105.297 53.591 ;
     RECT  67.176 53.555 68.67 53.597 ;
     RECT  86.112 53.519 89.514 53.597 ;
     RECT  97.992 53.591 104.094 53.597 ;
     RECT  90.576 53.591 91.17 53.627 ;
     RECT  93.276 53.555 94.77 53.627 ;
     RECT  96.408 53.591 97.146 53.627 ;
     RECT  103.752 53.597 104.094 53.627 ;
     RECT  97.992 53.597 103.014 53.645 ;
     RECT  104.976 53.591 105.297 53.645 ;
     RECT  67.176 53.597 68.598 53.663 ;
     RECT  69.804 53.555 76.194 53.663 ;
     RECT  79.884 53.555 85.05 53.663 ;
     RECT  90.756 53.627 91.17 53.663 ;
     RECT  93.42 53.627 94.77 53.663 ;
     RECT  97.992 53.645 102.942 53.663 ;
     RECT  104.04 53.627 104.094 53.663 ;
     RECT  67.176 53.663 67.662 53.699 ;
     RECT  79.92 53.663 80.478 53.699 ;
     RECT  84.708 53.663 85.05 53.699 ;
     RECT  86.112 53.597 89.478 53.699 ;
     RECT  93.42 53.663 94.497 53.699 ;
     RECT  94.215 53.699 94.497 53.747 ;
     RECT  98.604 53.663 102.366 53.747 ;
     RECT  105.015 53.645 105.297 53.747 ;
     RECT  2.232 53.555 64.134 53.789 ;
     RECT  67.176 53.699 67.626 53.789 ;
     RECT  68.4 53.663 68.598 53.789 ;
     RECT  69.804 53.663 70.542 53.789 ;
     RECT  71.64 53.663 76.194 53.789 ;
     RECT  76.968 53.555 76.986 53.789 ;
     RECT  82.08 53.663 83.898 53.789 ;
     RECT  84.708 53.699 84.726 53.789 ;
     RECT  86.292 53.699 88.002 53.789 ;
     RECT  88.776 53.699 89.478 53.789 ;
     RECT  96.876 53.627 97.146 53.789 ;
     RECT  100.584 53.747 102.366 53.789 ;
     RECT  104.04 53.663 104.058 53.789 ;
     RECT  2.268 53.789 26.622 53.825 ;
     RECT  63.72 53.789 64.134 53.825 ;
     RECT  67.176 53.789 67.305 53.825 ;
     RECT  71.64 53.789 72.705 53.825 ;
     RECT  73.872 53.789 73.89 53.825 ;
     RECT  74.7 53.789 74.718 53.825 ;
     RECT  78.015 53.555 78.678 53.825 ;
     RECT  79.992 53.699 80.478 53.825 ;
     RECT  82.08 53.789 82.17 53.825 ;
     RECT  86.292 53.789 86.634 53.825 ;
     RECT  87.516 53.789 87.678 53.825 ;
     RECT  88.776 53.789 88.905 53.825 ;
     RECT  94.215 53.747 94.374 53.825 ;
     RECT  97.02 53.789 97.038 53.825 ;
     RECT  98.604 53.747 99.705 53.825 ;
     RECT  101.052 53.789 102.366 53.825 ;
     RECT  11.988 53.825 19.17 53.861 ;
     RECT  19.98 53.825 26.622 53.861 ;
     RECT  47.052 53.789 62.91 53.861 ;
     RECT  75.564 53.789 75.726 53.861 ;
     RECT  87.66 53.825 87.678 53.861 ;
     RECT  47.088 53.861 62.91 53.897 ;
     RECT  64.116 53.825 64.134 53.897 ;
     RECT  72.324 53.825 72.705 53.897 ;
     RECT  86.292 53.825 86.31 53.897 ;
     RECT  91.152 53.663 91.17 53.897 ;
     RECT  12.168 53.861 19.17 53.933 ;
     RECT  47.088 53.897 62.19 53.933 ;
     RECT  69.84 53.789 70.542 53.933 ;
     RECT  75.636 53.861 75.654 53.933 ;
     RECT  101.052 53.825 101.07 53.933 ;
     RECT  102.312 53.825 102.366 53.933 ;
     RECT  2.268 53.825 11.25 53.969 ;
     RECT  68.4 53.789 68.418 53.969 ;
     RECT  69.84 53.933 69.858 53.969 ;
     RECT  82.08 53.825 82.098 53.969 ;
     RECT  93.42 53.699 93.438 53.969 ;
     RECT  12.276 53.933 19.17 53.981 ;
     RECT  20.052 53.861 26.622 53.981 ;
     RECT  27.468 53.789 46.17 53.981 ;
     RECT  33.552 53.981 46.17 54.017 ;
     RECT  47.088 53.933 61.905 54.017 ;
     RECT  67.215 53.825 67.305 54.017 ;
     RECT  72.615 53.897 72.705 54.017 ;
     RECT  78.015 53.825 78.105 54.017 ;
     RECT  83.415 53.789 83.505 54.017 ;
     RECT  88.815 53.825 88.905 54.017 ;
     RECT  94.215 53.825 94.305 54.017 ;
     RECT  99.615 53.825 99.705 54.017 ;
     RECT  105.015 53.747 105.105 54.017 ;
     RECT  27.468 53.981 32.814 54.029 ;
     RECT  45.864 54.017 46.17 54.059 ;
     RECT  98.604 53.825 98.622 54.059 ;
     RECT  102.348 53.933 102.366 54.059 ;
     RECT  2.268 53.969 11.178 54.125 ;
     RECT  12.816 53.981 19.17 54.125 ;
     RECT  20.052 53.981 21.87 54.125 ;
     RECT  33.552 54.017 45.09 54.125 ;
     RECT  47.088 54.017 61.542 54.125 ;
     RECT  4.284 54.125 11.178 54.173 ;
     RECT  2.268 54.125 3.438 54.221 ;
     RECT  3.096 54.221 3.438 55.325 ;
     RECT  4.284 54.173 7.794 55.325 ;
     RECT  8.568 54.173 11.178 55.325 ;
     RECT  16.884 54.125 19.17 55.325 ;
     RECT  22.608 53.981 24.606 55.325 ;
     RECT  25.416 53.981 26.622 55.325 ;
     RECT  27.468 54.029 31.626 55.325 ;
     RECT  33.552 54.125 41.058 55.325 ;
     RECT  41.904 54.125 45.09 55.325 ;
     RECT  47.088 54.125 54.306 55.325 ;
     RECT  55.296 54.125 61.434 55.325 ;
     RECT  27.468 55.325 29.322 55.373 ;
     RECT  52.2 55.325 54.306 55.373 ;
     RECT  30.78 55.325 31.374 55.421 ;
     RECT  48.204 55.325 48.546 55.421 ;
     RECT  57.42 55.325 61.434 55.421 ;
     RECT  24.336 55.325 24.606 55.517 ;
     RECT  55.764 55.325 56.214 55.853 ;
     RECT  17.1 55.325 19.17 55.901 ;
     RECT  55.764 55.853 56.142 55.901 ;
     RECT  9 55.325 10.17 55.949 ;
     RECT  38.052 55.325 40.194 55.949 ;
     RECT  41.004 55.325 41.022 55.949 ;
     RECT  15.084 54.125 16.11 55.997 ;
     RECT  35.82 55.325 36.45 55.997 ;
     RECT  38.052 55.949 40.122 55.997 ;
     RECT  57.42 55.421 60.246 55.997 ;
     RECT  61.164 55.421 61.434 55.997 ;
     RECT  41.94 55.325 45.09 56.011 ;
     RECT  45.864 54.059 45.882 56.011 ;
     RECT  2.268 54.221 2.286 56.045 ;
     RECT  3.42 55.325 3.438 56.045 ;
     RECT  4.392 55.325 4.662 56.045 ;
     RECT  5.652 55.325 7.65 56.045 ;
     RECT  9.036 55.949 10.17 56.045 ;
     RECT  11.16 55.325 11.178 56.045 ;
     RECT  12.816 54.125 14.202 56.045 ;
     RECT  15.084 55.997 16.038 56.045 ;
     RECT  17.1 55.901 18.882 56.045 ;
     RECT  20.052 54.125 21.582 56.045 ;
     RECT  22.608 55.325 23.166 56.045 ;
     RECT  24.336 55.517 24.354 56.045 ;
     RECT  26.424 55.325 26.442 56.045 ;
     RECT  27.468 55.373 28.386 56.045 ;
     RECT  29.304 55.373 29.322 56.045 ;
     RECT  31.356 55.421 31.374 56.045 ;
     RECT  32.58 54.029 32.814 56.045 ;
     RECT  33.552 55.325 34.758 56.045 ;
     RECT  35.82 55.997 36.162 56.045 ;
     RECT  38.052 55.997 40.014 56.045 ;
     RECT  41.94 56.011 45.882 56.045 ;
     RECT  47.16 55.325 47.178 56.045 ;
     RECT  48.204 55.421 48.474 56.045 ;
     RECT  49.392 55.325 49.878 56.045 ;
     RECT  50.832 55.325 51.426 56.045 ;
     RECT  52.2 55.373 54.018 56.045 ;
     RECT  55.764 55.901 55.782 56.045 ;
     RECT  57.42 55.997 57.942 56.045 ;
     RECT  58.968 55.997 60.246 56.045 ;
     RECT  61.164 55.997 61.182 56.045 ;
     RECT  38.052 56.045 38.718 56.093 ;
     RECT  44.1 56.045 44.118 56.093 ;
     RECT  25.416 55.325 25.434 56.141 ;
     RECT  38.052 56.093 38.07 56.141 ;
     RECT  39.708 56.045 39.726 56.141 ;
     RECT  45.144 56.045 45.162 56.141 ;
    LAYER M4 ;
     RECT  2.245 56.016 2.293 56.04 ;
     RECT  2.293 55.92 2.297 56.04 ;
     RECT  2.149 53.568 2.341 53.592 ;
     RECT  2.293 3.12 2.408 3.144 ;
     RECT  2.293 4.944 2.408 4.968 ;
     RECT  2.365 9.792 2.408 9.816 ;
     RECT  2.365 12 2.408 12.024 ;
     RECT  2.329 19.344 2.408 19.368 ;
     RECT  2.365 26.016 2.408 26.04 ;
     RECT  2.293 50.928 2.408 51.24 ;
     RECT  2.053 52.56 2.408 52.584 ;
     RECT  2.341 53.568 2.408 54.168 ;
     RECT  2.408 2.148 2.437 54.168 ;
     RECT  2.437 2.148 2.512 54.216 ;
     RECT  2.512 2.304 2.585 54.216 ;
     RECT  2.585 2.304 2.704 54.12 ;
     RECT  2.297 55.92 2.725 55.992 ;
     RECT  2.704 2.304 2.819 18.216 ;
     RECT  2.725 55.872 3.085 55.992 ;
     RECT  3.085 55.296 3.155 55.992 ;
     RECT  3.155 55.968 3.301 55.992 ;
     RECT  2.819 13.056 3.341 18.216 ;
     RECT  2.704 19.344 3.341 19.416 ;
     RECT  2.704 23.424 3.443 26.232 ;
     RECT  2.819 2.304 3.491 12.024 ;
     RECT  3.341 13.056 3.701 17.496 ;
     RECT  2.704 20.448 3.769 21 ;
     RECT  2.704 22.176 3.769 22.2 ;
     RECT  2.704 29.04 3.769 29.352 ;
     RECT  2.704 30.48 3.769 35.448 ;
     RECT  2.704 37.584 3.779 37.608 ;
     RECT  3.491 2.736 3.809 12.024 ;
     RECT  2.704 42.144 3.809 42.168 ;
     RECT  2.704 46.896 3.829 46.92 ;
     RECT  3.769 29.04 3.845 35.448 ;
     RECT  3.769 20.448 3.877 22.2 ;
     RECT  3.829 46.656 3.877 46.92 ;
     RECT  3.809 3.936 3.923 12.024 ;
     RECT  3.701 13.296 3.923 17.496 ;
     RECT  3.809 2.736 3.971 2.904 ;
     RECT  3.923 13.296 3.971 17.16 ;
     RECT  3.877 19.968 3.973 22.2 ;
     RECT  3.443 23.424 3.973 25.08 ;
     RECT  2.704 45.12 3.985 45.144 ;
     RECT  3.443 26.208 4.019 26.232 ;
     RECT  2.704 27.36 4.021 27.912 ;
     RECT  3.971 2.736 4.025 2.76 ;
     RECT  3.973 19.968 4.025 25.08 ;
     RECT  4.021 26.448 4.025 27.912 ;
     RECT  3.971 13.92 4.061 17.16 ;
     RECT  4.025 20.448 4.061 25.08 ;
     RECT  3.923 4.416 4.067 12.024 ;
     RECT  3.949 18.72 4.067 18.792 ;
     RECT  3.985 44.352 4.067 45.144 ;
     RECT  3.845 29.328 4.097 35.448 ;
     RECT  4.057 42.672 4.115 42.792 ;
     RECT  4.097 30.816 4.205 35.448 ;
     RECT  2.704 38.784 4.213 38.808 ;
     RECT  2.704 40.464 4.259 40.488 ;
     RECT  3.301 55.968 4.273 56.04 ;
     RECT  4.213 38.784 4.277 39.096 ;
     RECT  4.277 38.784 4.307 38.808 ;
     RECT  4.205 33.984 4.309 35.448 ;
     RECT  4.309 33.984 4.349 35.736 ;
     RECT  4.349 34.8 4.355 35.736 ;
     RECT  3.877 46.656 4.453 47.208 ;
     RECT  2.704 48.384 4.453 54.12 ;
     RECT  4.355 34.8 4.601 35.448 ;
     RECT  4.061 23.232 4.669 25.08 ;
     RECT  4.205 30.816 4.673 32.952 ;
     RECT  4.067 4.512 4.705 12.024 ;
     RECT  4.453 46.656 4.709 54.12 ;
     RECT  4.025 26.448 4.853 27.528 ;
     RECT  4.853 26.448 4.889 27.384 ;
     RECT  4.129 45.216 4.921 45.528 ;
     RECT  4.709 46.656 4.921 53.976 ;
     RECT  4.097 29.328 4.957 29.544 ;
     RECT  4.705 4.512 4.981 12.264 ;
     RECT  4.061 13.92 4.981 16.68 ;
     RECT  4.957 29.04 5.029 29.544 ;
     RECT  5.029 28.464 5.077 29.544 ;
     RECT  4.673 30.816 5.077 31.944 ;
     RECT  4.061 20.448 5.101 22.248 ;
     RECT  4.669 23.232 5.101 25.32 ;
     RECT  4.601 34.8 5.105 34.824 ;
     RECT  5.065 3.36 5.123 3.384 ;
     RECT  4.115 42.672 5.123 42.696 ;
     RECT  5.101 20.448 5.141 25.32 ;
     RECT  5.077 28.464 5.171 31.944 ;
     RECT  4.981 4.512 5.177 16.68 ;
     RECT  4.921 45.216 5.209 53.976 ;
     RECT  5.177 4.512 5.219 6.888 ;
     RECT  5.209 44.976 5.249 53.976 ;
     RECT  5.249 44.976 5.353 53.64 ;
     RECT  5.171 28.8 5.393 31.944 ;
     RECT  5.219 4.512 5.413 6.84 ;
     RECT  4.067 18.768 5.497 18.792 ;
     RECT  5.353 44.928 5.501 53.64 ;
     RECT  5.177 10.704 5.533 16.68 ;
     RECT  5.497 18.288 5.533 18.792 ;
     RECT  4.261 37.008 5.533 37.032 ;
     RECT  5.413 3.888 5.609 6.84 ;
     RECT  5.533 37.008 5.641 37.896 ;
     RECT  4.889 26.496 5.681 27.336 ;
     RECT  5.609 4.512 5.699 6.84 ;
     RECT  5.141 20.448 5.699 22.824 ;
     RECT  5.641 37.008 5.699 38.04 ;
     RECT  5.533 10.704 5.701 18.792 ;
     RECT  5.141 24.096 5.717 25.08 ;
     RECT  5.681 26.496 5.717 26.52 ;
     RECT  4.673 32.928 5.749 32.952 ;
     RECT  5.713 34.32 5.749 34.344 ;
     RECT  5.699 22.8 5.789 22.824 ;
     RECT  5.393 28.944 5.821 31.944 ;
     RECT  5.749 32.928 5.821 34.344 ;
     RECT  5.281 41.184 5.893 41.208 ;
     RECT  5.701 10.704 5.987 19.272 ;
     RECT  5.987 10.704 6.077 13.224 ;
     RECT  5.821 28.944 6.077 34.344 ;
     RECT  6.077 29.376 6.083 34.344 ;
     RECT  6.037 36.48 6.083 36.504 ;
     RECT  5.501 44.928 6.145 49.704 ;
     RECT  5.501 50.736 6.229 53.64 ;
     RECT  5.177 7.872 6.253 9.672 ;
     RECT  6.077 10.704 6.253 13.176 ;
     RECT  5.987 14.208 6.275 19.272 ;
     RECT  6.145 26.256 6.277 26.28 ;
     RECT  6.073 42.72 6.289 42.744 ;
     RECT  6.145 44.016 6.289 49.704 ;
     RECT  5.717 25.056 6.419 25.08 ;
     RECT  5.893 41.04 6.421 41.208 ;
     RECT  6.289 42.72 6.421 49.704 ;
     RECT  6.421 41.04 6.505 49.704 ;
     RECT  6.229 50.736 6.505 53.784 ;
     RECT  6.505 41.04 6.509 53.784 ;
     RECT  6.509 42.72 6.541 53.784 ;
     RECT  6.541 42.72 6.545 53.976 ;
     RECT  6.083 29.472 6.581 34.344 ;
     RECT  6.581 33.216 6.649 34.344 ;
     RECT  6.325 39.312 6.661 39.336 ;
     RECT  6.649 33.216 6.707 35.016 ;
     RECT  6.545 43.2 6.707 53.976 ;
     RECT  5.699 4.512 6.721 6.6 ;
     RECT  6.509 41.04 6.721 41.208 ;
     RECT  6.721 4.512 6.757 6.648 ;
     RECT  6.253 7.872 6.757 13.176 ;
     RECT  5.699 20.448 6.805 21.816 ;
     RECT  5.699 38.016 6.853 38.04 ;
     RECT  6.661 39.072 6.853 39.336 ;
     RECT  6.829 3.408 6.937 3.432 ;
     RECT  6.853 38.016 7.009 39.336 ;
     RECT  6.721 40.416 7.009 41.208 ;
     RECT  6.757 4.512 7.081 13.176 ;
     RECT  6.275 14.208 7.081 18.792 ;
     RECT  6.937 3.216 7.189 3.432 ;
     RECT  7.081 4.512 7.189 18.792 ;
     RECT  7.189 3.216 7.225 18.792 ;
     RECT  7.225 2.88 7.297 18.792 ;
     RECT  6.805 20.448 7.297 22.728 ;
     RECT  6.973 23.712 7.297 23.736 ;
     RECT  7.225 1.152 7.333 1.176 ;
     RECT  7.297 2.352 7.333 18.792 ;
     RECT  6.707 46.464 7.369 53.976 ;
     RECT  6.277 26.208 7.381 26.28 ;
     RECT  6.793 28.32 7.477 28.344 ;
     RECT  7.297 20.448 7.621 23.736 ;
     RECT  7.009 38.016 7.621 41.208 ;
     RECT  4.273 55.296 7.661 56.04 ;
     RECT  7.381 26.208 7.669 26.904 ;
     RECT  7.477 28.32 7.669 28.488 ;
     RECT  7.621 38.016 7.669 41.688 ;
     RECT  6.707 43.2 7.669 45.384 ;
     RECT  7.333 1.152 7.729 18.792 ;
     RECT  7.661 55.296 7.763 55.944 ;
     RECT  7.729 0.576 7.808 18.792 ;
     RECT  7.621 20.448 7.808 24.312 ;
     RECT  7.669 26.208 7.808 28.488 ;
     RECT  6.581 29.472 7.808 32.184 ;
     RECT  6.707 33.216 7.808 34.824 ;
     RECT  6.829 35.952 7.808 35.976 ;
     RECT  7.669 38.016 7.808 45.384 ;
     RECT  7.369 46.464 7.808 54.12 ;
     RECT  7.808 0.576 7.909 54.12 ;
     RECT  7.909 0.576 7.985 54.168 ;
     RECT  7.985 0.576 8.104 53.88 ;
     RECT  8.104 34.512 8.387 34.536 ;
     RECT  8.104 8.64 8.453 18.552 ;
     RECT  8.104 41.04 8.489 44.472 ;
     RECT  8.104 39.072 8.525 39.816 ;
     RECT  8.489 41.04 8.525 42.552 ;
     RECT  8.453 8.64 8.531 18.264 ;
     RECT  8.104 33.36 8.531 33.384 ;
     RECT  8.104 25.056 8.561 25.848 ;
     RECT  8.104 29.472 8.705 31.896 ;
     RECT  8.104 45.648 8.705 53.88 ;
     RECT  8.104 0.576 8.723 7.416 ;
     RECT  7.763 55.296 8.819 55.848 ;
     RECT  8.525 39.264 8.849 39.816 ;
     RECT  8.849 39.264 8.885 39.288 ;
     RECT  8.525 41.04 8.993 42.168 ;
     RECT  8.723 6.576 9.097 7.416 ;
     RECT  8.531 8.64 9.097 12.6 ;
     RECT  8.705 46.224 9.097 53.88 ;
     RECT  8.723 0.576 9.107 5.496 ;
     RECT  9.097 6.576 9.107 12.6 ;
     RECT  8.705 29.472 9.107 31.416 ;
     RECT  8.993 41.04 9.109 41.976 ;
     RECT  9.107 29.472 9.157 31.368 ;
     RECT  8.104 20.304 9.169 23.688 ;
     RECT  8.104 26.832 9.277 27.72 ;
     RECT  9.157 29.28 9.277 31.368 ;
     RECT  8.104 36.288 9.313 37.704 ;
     RECT  8.561 25.824 9.529 25.848 ;
     RECT  9.277 26.832 9.529 31.368 ;
     RECT  9.313 36.096 9.569 37.704 ;
     RECT  8.489 43.824 9.589 44.472 ;
     RECT  9.109 40.464 9.635 41.976 ;
     RECT  9.589 43.296 9.635 44.472 ;
     RECT  9.169 19.296 9.637 23.688 ;
     RECT  9.385 24.72 9.637 24.744 ;
     RECT  9.635 40.464 9.641 41.688 ;
     RECT  9.635 43.296 9.677 43.848 ;
     RECT  9.107 0.864 9.683 5.496 ;
     RECT  9.569 36.096 9.683 36.84 ;
     RECT  9.107 6.576 9.733 9 ;
     RECT  9.107 10.128 9.733 12.6 ;
     RECT  8.531 13.68 9.733 18.264 ;
     RECT  9.733 10.128 9.889 18.264 ;
     RECT  9.637 19.296 9.889 24.744 ;
     RECT  9.097 46.224 9.889 54.408 ;
     RECT  9.529 25.824 9.929 31.368 ;
     RECT  9.889 45.552 9.961 54.408 ;
     RECT  8.869 55.92 9.961 56.04 ;
     RECT  9.683 36.096 10.033 36.504 ;
     RECT  9.889 10.128 10.069 24.744 ;
     RECT  9.733 6.48 10.309 9 ;
     RECT  10.069 10.08 10.309 25.704 ;
     RECT  10.177 32.448 10.357 32.472 ;
     RECT  9.641 40.848 10.597 41.688 ;
     RECT  9.683 0.864 10.645 5.256 ;
     RECT  10.357 32.448 10.645 32.52 ;
     RECT  9.529 34.08 10.645 34.104 ;
     RECT  10.597 40.848 10.685 42.6 ;
     RECT  10.645 32.448 10.691 32.568 ;
     RECT  10.033 35.856 10.693 36.504 ;
     RECT  10.141 38.256 10.693 38.28 ;
     RECT  9.677 43.824 10.717 43.848 ;
     RECT  10.645 0.864 10.741 5.448 ;
     RECT  10.309 6.48 10.741 25.704 ;
     RECT  9.929 26.784 10.741 31.368 ;
     RECT  10.693 35.856 10.741 38.28 ;
     RECT  10.609 39.6 10.741 39.624 ;
     RECT  10.741 35.856 10.757 39.624 ;
     RECT  10.685 40.848 10.757 41.688 ;
     RECT  10.717 43.68 10.789 43.848 ;
     RECT  10.741 0.864 10.835 25.704 ;
     RECT  10.741 26.784 10.835 31.704 ;
     RECT  10.757 35.856 10.835 36.504 ;
     RECT  9.961 45.552 10.835 56.04 ;
     RECT  10.645 34.08 10.837 34.248 ;
     RECT  10.757 41.04 10.883 41.448 ;
     RECT  10.835 45.552 10.897 54.408 ;
     RECT  10.835 13.536 10.901 25.704 ;
     RECT  10.835 26.784 10.901 31.56 ;
     RECT  10.835 35.856 10.901 36.168 ;
     RECT  10.897 44.976 10.931 54.408 ;
     RECT  11.005 32.688 11.113 32.712 ;
     RECT  10.837 34.08 11.113 34.824 ;
     RECT  10.789 43.632 11.185 43.848 ;
     RECT  10.931 44.976 11.185 50.808 ;
     RECT  10.835 56.016 11.189 56.04 ;
     RECT  10.883 41.04 11.261 41.064 ;
     RECT  10.901 30.336 11.267 31.56 ;
     RECT  10.901 26.784 11.333 29.112 ;
     RECT  10.757 38.16 11.405 39.624 ;
     RECT  10.835 0.864 11.411 12.504 ;
     RECT  11.333 28.56 11.441 29.112 ;
     RECT  10.901 14.064 11.545 25.704 ;
     RECT  11.185 43.632 11.621 50.808 ;
     RECT  11.411 11.52 11.651 12.504 ;
     RECT  11.405 39.216 11.657 39.624 ;
     RECT  11.657 39.6 11.765 39.624 ;
     RECT  11.545 14.064 11.833 25.752 ;
     RECT  11.113 32.688 11.977 35.256 ;
     RECT  11.621 50.784 11.977 50.808 ;
     RECT  10.931 51.888 11.977 54.408 ;
     RECT  11.411 0.864 11.981 10.104 ;
     RECT  11.621 43.632 12.013 49.608 ;
     RECT  11.651 11.568 12.037 12.504 ;
     RECT  11.833 14.064 12.037 25.8 ;
     RECT  11.267 30.336 12.049 31.224 ;
     RECT  12.049 30.288 12.229 31.224 ;
     RECT  12.229 30.288 12.265 31.56 ;
     RECT  11.977 32.688 12.265 35.928 ;
     RECT  11.333 26.784 12.481 27.336 ;
     RECT  11.441 29.04 12.481 29.112 ;
     RECT  12.265 30.288 12.481 36.12 ;
     RECT  12.037 11.568 12.517 25.8 ;
     RECT  12.481 26.784 12.517 27.672 ;
     RECT  12.517 11.568 12.613 27.672 ;
     RECT  12.481 29.04 12.613 36.12 ;
     RECT  12.445 41.76 12.613 41.784 ;
     RECT  12.013 43.104 12.613 49.608 ;
     RECT  12.613 41.76 12.625 49.608 ;
     RECT  12.625 41.616 12.709 49.608 ;
     RECT  11.977 50.784 12.709 54.408 ;
     RECT  12.613 11.568 12.805 36.12 ;
     RECT  12.277 37.104 12.805 37.128 ;
     RECT  12.805 11.568 12.853 37.128 ;
     RECT  12.853 11.28 12.877 37.128 ;
     RECT  11.981 0.864 13.129 9.96 ;
     RECT  12.877 11.184 13.129 37.128 ;
     RECT  12.709 41.616 13.165 54.408 ;
     RECT  12.709 56.016 13.165 56.04 ;
     RECT  13.129 0.864 13.208 37.128 ;
     RECT  11.405 38.16 13.208 38.184 ;
     RECT  13.165 41.616 13.208 56.04 ;
     RECT  13.208 0.864 13.235 56.04 ;
     RECT  13.235 0.864 13.504 54.408 ;
     RECT  13.504 32.88 13.619 54.408 ;
     RECT  13.235 55.68 13.667 56.04 ;
     RECT  13.619 32.928 13.925 54.408 ;
     RECT  13.504 10.128 13.955 14.76 ;
     RECT  13.925 32.928 14.249 49.656 ;
     RECT  13.925 50.688 14.341 54.408 ;
     RECT  14.249 32.976 14.357 49.656 ;
     RECT  13.955 10.704 14.429 14.76 ;
     RECT  13.504 0.864 14.485 8.76 ;
     RECT  14.357 36.288 14.501 49.656 ;
     RECT  14.357 32.976 14.645 35.304 ;
     RECT  14.501 36.288 14.717 37.128 ;
     RECT  14.341 50.688 14.723 54.696 ;
     RECT  14.429 11.712 14.821 14.76 ;
     RECT  13.504 15.744 14.821 20.712 ;
     RECT  14.821 11.712 14.857 20.712 ;
     RECT  13.504 21.744 14.857 31.56 ;
     RECT  14.717 36.48 14.861 37.128 ;
     RECT  14.645 34.224 14.897 35.304 ;
     RECT  14.857 11.712 14.915 31.56 ;
     RECT  14.501 38.208 14.965 49.656 ;
     RECT  14.723 50.688 14.965 54.408 ;
     RECT  14.485 0.864 15.061 9.672 ;
     RECT  15.061 0.864 15.361 10.584 ;
     RECT  15.361 0.816 15.433 10.584 ;
     RECT  14.915 11.712 15.433 14.76 ;
     RECT  14.915 15.792 15.433 31.56 ;
     RECT  14.645 32.976 15.433 33.24 ;
     RECT  15.433 15.792 15.725 33.24 ;
     RECT  14.861 36.48 15.829 36.6 ;
     RECT  15.725 24.624 15.865 33.24 ;
     RECT  14.897 34.224 15.865 34.776 ;
     RECT  14.965 38.208 15.973 54.408 ;
     RECT  13.667 56.016 16.069 56.04 ;
     RECT  15.973 38.16 16.189 54.408 ;
     RECT  15.829 36.48 16.333 37.032 ;
     RECT  16.189 38.112 16.333 54.408 ;
     RECT  15.865 24.624 16.477 34.776 ;
     RECT  16.477 24.624 16.513 35.352 ;
     RECT  16.333 36.48 16.513 54.408 ;
     RECT  15.433 0.816 16.597 14.76 ;
     RECT  15.725 15.792 16.597 23.64 ;
     RECT  16.513 24.624 16.873 54.408 ;
     RECT  16.069 55.968 16.873 56.04 ;
     RECT  16.873 24.624 16.877 56.04 ;
     RECT  16.877 32.448 16.979 56.04 ;
     RECT  16.597 0.816 17.485 23.64 ;
     RECT  16.877 24.624 17.485 30.936 ;
     RECT  17.485 0.816 17.489 30.936 ;
     RECT  17.489 0.816 17.507 10.92 ;
     RECT  17.489 12.336 17.881 30.936 ;
     RECT  16.979 32.448 17.881 54.408 ;
     RECT  17.881 12.336 18.469 54.408 ;
     RECT  17.507 0.816 18.608 10.632 ;
     RECT  18.469 11.712 18.608 54.408 ;
     RECT  18.608 0.816 18.745 54.408 ;
     RECT  16.979 55.872 18.893 56.04 ;
     RECT  18.745 0.768 18.904 54.408 ;
     RECT  18.893 55.872 19.621 55.992 ;
     RECT  19.621 55.776 19.763 55.992 ;
     RECT  18.904 0.768 19.933 11.256 ;
     RECT  18.904 12.336 19.933 54.408 ;
     RECT  19.933 0.768 20.693 54.408 ;
     RECT  20.693 0.768 20.765 37.368 ;
     RECT  20.765 0.768 20.801 12.12 ;
     RECT  20.693 38.544 20.869 54.408 ;
     RECT  20.005 56.016 20.869 56.04 ;
     RECT  20.801 11.376 20.981 12.12 ;
     RECT  20.981 11.376 21.299 11.4 ;
     RECT  20.869 38.544 21.491 56.04 ;
     RECT  20.765 13.104 21.733 37.368 ;
     RECT  20.801 0.768 21.985 10.248 ;
     RECT  21.733 12.672 22.093 37.368 ;
     RECT  21.491 38.544 22.093 54.408 ;
     RECT  22.093 12.672 22.165 54.408 ;
     RECT  21.985 0.768 22.211 10.872 ;
     RECT  22.165 12.528 22.211 54.408 ;
     RECT  22.211 12.528 22.213 22.536 ;
     RECT  22.211 8.976 22.273 10.872 ;
     RECT  22.213 12.288 22.273 22.536 ;
     RECT  22.211 23.664 22.421 54.408 ;
     RECT  21.491 56.016 22.597 56.04 ;
     RECT  22.421 23.664 22.787 37.128 ;
     RECT  22.597 55.968 23.029 56.04 ;
     RECT  23.029 55.92 23.173 56.04 ;
     RECT  22.273 8.976 23.245 22.536 ;
     RECT  22.787 23.664 23.245 26.232 ;
     RECT  22.211 0.768 23.281 7.992 ;
     RECT  23.245 8.976 23.281 26.232 ;
     RECT  22.787 27.696 23.413 37.128 ;
     RECT  22.421 38.112 23.413 54.408 ;
     RECT  23.413 27.696 23.713 54.408 ;
     RECT  23.173 55.824 23.713 56.04 ;
     RECT  23.713 27.696 23.821 56.04 ;
     RECT  23.281 0.768 24.008 26.232 ;
     RECT  23.821 27.408 24.008 56.04 ;
     RECT  24.008 0.768 24.365 56.04 ;
     RECT  24.365 0.768 24.659 55.992 ;
     RECT  24.659 55.392 24.755 55.992 ;
     RECT  24.755 55.488 24.851 55.992 ;
     RECT  24.659 0.768 24.977 54.408 ;
     RECT  24.977 9.984 25.625 54.408 ;
     RECT  25.625 30.624 25.667 54.408 ;
     RECT  25.625 9.984 25.763 29.544 ;
     RECT  24.977 0.768 26.053 8.904 ;
     RECT  25.763 9.984 26.053 29.16 ;
     RECT  25.667 30.768 26.053 54.408 ;
     RECT  25.405 56.112 26.053 56.136 ;
     RECT  26.053 30.768 26.675 56.136 ;
     RECT  26.675 30.768 26.677 54.408 ;
     RECT  26.053 0.768 26.725 29.16 ;
     RECT  26.677 30.384 26.725 54.408 ;
     RECT  26.675 56.016 27.973 56.136 ;
     RECT  26.725 0.768 28.073 54.408 ;
     RECT  28.073 0.768 28.433 29.544 ;
     RECT  28.073 30.624 28.789 54.408 ;
     RECT  27.973 55.968 28.789 56.136 ;
     RECT  28.433 9.888 29.329 29.544 ;
     RECT  28.433 0.768 29.401 8.76 ;
     RECT  29.329 9.888 29.401 29.64 ;
     RECT  29.401 0.768 29.408 29.64 ;
     RECT  28.789 30.624 29.408 56.136 ;
     RECT  29.408 0.768 30.275 56.136 ;
     RECT  30.275 0.768 31.285 8.328 ;
     RECT  30.275 9.36 31.285 56.136 ;
     RECT  31.285 0.768 31.763 56.136 ;
     RECT  31.763 0.768 32.501 54.408 ;
     RECT  32.501 7.344 32.579 54.408 ;
     RECT  31.763 56.016 33.637 56.136 ;
     RECT  32.501 0.768 33.685 6.312 ;
     RECT  32.579 7.68 33.685 54.408 ;
     RECT  33.685 0.096 34.357 54.408 ;
     RECT  34.357 0.096 34.765 54.456 ;
     RECT  33.637 55.824 34.765 56.136 ;
     RECT  34.765 0.096 35.315 56.136 ;
     RECT  35.315 0.096 35.363 53.4 ;
     RECT  35.363 7.344 36.467 53.4 ;
     RECT  35.363 0.096 36.469 6.072 ;
     RECT  36.469 0.096 36.785 6.84 ;
     RECT  36.467 7.872 37.045 53.4 ;
     RECT  35.315 54.384 37.045 56.136 ;
     RECT  36.785 0.096 37.619 6.696 ;
     RECT  37.045 7.872 37.861 56.136 ;
     RECT  37.861 7.728 38.077 56.136 ;
     RECT  38.077 7.44 38.081 56.136 ;
     RECT  37.619 0.096 38.797 6.312 ;
     RECT  38.081 7.44 38.797 56.088 ;
     RECT  38.797 0.096 39.697 56.088 ;
     RECT  39.697 0.096 41.501 56.136 ;
     RECT  41.501 5.424 42.227 56.136 ;
     RECT  42.227 5.424 42.565 54.744 ;
     RECT  41.501 0.096 42.577 4.248 ;
     RECT  42.565 5.328 42.577 54.744 ;
     RECT  42.577 0.096 42.757 54.744 ;
     RECT  42.757 0.048 43.333 54.744 ;
     RECT  42.227 55.92 43.333 56.136 ;
     RECT  43.333 0.048 45.173 56.136 ;
     RECT  45.173 0.048 45.491 56.04 ;
     RECT  45.491 55.92 45.893 56.04 ;
     RECT  45.893 55.92 46.067 55.944 ;
     RECT  45.491 0.048 46.289 54.504 ;
     RECT  46.289 0.096 47.077 54.504 ;
     RECT  47.077 0.096 47.507 56.04 ;
     RECT  47.507 0.144 49.187 56.04 ;
     RECT  49.187 0.144 49.669 54.984 ;
     RECT  49.669 0.096 50.173 54.984 ;
     RECT  49.187 56.016 50.173 56.04 ;
     RECT  50.173 0.096 51.539 56.04 ;
     RECT  51.539 56.016 52.645 56.04 ;
     RECT  51.539 0.096 53.021 54.984 ;
     RECT  53.021 0.096 53.129 6.888 ;
     RECT  53.129 0.096 53.201 6.648 ;
     RECT  53.021 7.872 53.305 54.984 ;
     RECT  52.645 55.968 53.305 56.04 ;
     RECT  53.305 7.872 53.885 56.04 ;
     RECT  53.885 9.6 53.891 56.04 ;
     RECT  53.891 9.696 54.035 56.04 ;
     RECT  53.201 0.096 54.349 6.6 ;
     RECT  53.885 7.872 54.349 8.328 ;
     RECT  54.035 9.696 54.755 55.8 ;
     RECT  54.755 9.888 54.997 55.8 ;
     RECT  54.997 9.888 55.753 55.896 ;
     RECT  55.753 9.888 55.859 56.04 ;
     RECT  54.349 0.096 56.005 8.328 ;
     RECT  55.859 9.888 56.005 55.992 ;
     RECT  56.005 0.096 57.349 55.992 ;
     RECT  57.349 0.096 58.673 56.04 ;
     RECT  58.673 0.144 58.835 56.04 ;
     RECT  58.835 0.144 60.229 54.984 ;
     RECT  60.229 0.096 60.721 54.984 ;
     RECT  58.835 55.968 60.721 56.04 ;
     RECT  60.721 0.096 61.193 56.04 ;
     RECT  61.193 0.096 61.445 55.992 ;
     RECT  61.445 0.096 61.523 55.416 ;
     RECT  61.523 0.096 62.099 54.984 ;
     RECT  62.099 0.096 62.195 54.744 ;
     RECT  62.195 54.432 62.483 54.744 ;
     RECT  62.483 54.48 62.579 54.744 ;
     RECT  62.579 54.72 62.675 54.744 ;
     RECT  62.195 0.096 63.253 53.064 ;
     RECT  63.253 0.096 63.829 53.208 ;
     RECT  63.829 0.096 63.893 53.784 ;
     RECT  63.893 0.096 63.929 53.592 ;
     RECT  63.929 0.096 63.965 36.84 ;
     RECT  63.929 37.824 64.073 53.592 ;
     RECT  63.965 0.096 65.005 36.552 ;
     RECT  64.073 37.824 65.005 53.4 ;
     RECT  65.005 0.096 65.077 53.4 ;
     RECT  65.077 0.096 65.153 53.496 ;
     RECT  65.153 0.096 65.189 53.256 ;
     RECT  65.189 0.096 65.555 53.016 ;
     RECT  65.555 0.096 65.621 52.92 ;
     RECT  65.621 0.096 66.227 52.872 ;
     RECT  66.227 2.256 67.208 52.872 ;
     RECT  67.208 2.148 67.312 54.012 ;
     RECT  66.227 0.096 67.379 1.128 ;
     RECT  67.312 2.256 67.504 53.742 ;
     RECT  67.504 2.256 68.069 53.592 ;
     RECT  68.069 2.256 68.281 48.216 ;
     RECT  67.379 0.096 68.581 0.648 ;
     RECT  68.069 49.344 68.681 53.592 ;
     RECT  68.581 0.096 69.109 1.176 ;
     RECT  68.281 2.208 69.109 48.216 ;
     RECT  69.109 0.096 69.299 48.216 ;
     RECT  69.299 1.728 69.349 48.216 ;
     RECT  68.681 49.344 69.349 53.352 ;
     RECT  69.349 1.728 70.477 53.352 ;
     RECT  69.299 0.096 70.643 0.6 ;
     RECT  70.477 1.728 70.913 53.592 ;
     RECT  70.913 1.728 70.981 48.984 ;
     RECT  70.913 50.544 71.093 53.592 ;
     RECT  70.643 0.096 71.411 0.552 ;
     RECT  70.981 1.68 71.525 48.984 ;
     RECT  71.525 37.872 72.169 48.984 ;
     RECT  72.169 37.872 72.205 49.368 ;
     RECT  72.205 37.872 72.277 49.608 ;
     RECT  71.093 50.88 72.277 53.592 ;
     RECT  71.411 0.096 72.457 0.312 ;
     RECT  71.525 1.68 72.457 36.888 ;
     RECT  72.457 0.096 72.565 36.888 ;
     RECT  72.277 37.872 72.565 53.592 ;
     RECT  72.565 0.096 72.608 53.592 ;
     RECT  72.608 0.096 72.712 54.012 ;
     RECT  72.712 0.096 72.904 53.742 ;
     RECT  72.904 0.096 73.289 49.656 ;
     RECT  72.904 50.88 73.475 53.592 ;
     RECT  73.289 2.256 74.041 49.656 ;
     RECT  74.041 2.256 74.195 49.848 ;
     RECT  74.195 2.304 74.365 49.848 ;
     RECT  73.475 50.88 74.365 52.872 ;
     RECT  74.365 2.304 74.677 52.872 ;
     RECT  74.677 2.304 74.801 53.592 ;
     RECT  74.801 2.4 74.867 53.592 ;
     RECT  74.867 2.592 74.905 53.592 ;
     RECT  74.905 2.592 75.829 53.784 ;
     RECT  75.829 2.256 76.067 53.784 ;
     RECT  73.289 0.096 76.069 1.176 ;
     RECT  76.067 2.256 76.277 53.736 ;
     RECT  76.277 50.112 76.307 53.736 ;
     RECT  76.069 0.096 76.405 1.272 ;
     RECT  76.277 2.256 76.405 48.792 ;
     RECT  76.405 0.096 76.457 48.792 ;
     RECT  76.457 0.096 76.817 1.176 ;
     RECT  76.817 0.144 76.835 1.176 ;
     RECT  76.457 2.208 77.389 48.792 ;
     RECT  77.389 2.208 77.425 48.984 ;
     RECT  76.307 50.304 77.425 53.736 ;
     RECT  76.835 0.144 77.989 0.6 ;
     RECT  77.425 2.208 78.008 53.736 ;
     RECT  78.008 2.148 78.112 54.012 ;
     RECT  77.989 0.096 78.325 0.6 ;
     RECT  78.112 2.148 78.325 53.784 ;
     RECT  78.325 0.096 78.617 53.784 ;
     RECT  78.617 48 78.707 53.784 ;
     RECT  78.617 0.096 78.797 46.968 ;
     RECT  78.707 48 78.851 53.064 ;
     RECT  78.797 0.096 78.899 1.176 ;
     RECT  78.797 2.256 79.801 46.968 ;
     RECT  79.801 1.728 79.945 46.968 ;
     RECT  78.851 48 79.945 53.016 ;
     RECT  78.899 0.096 79.957 0.552 ;
     RECT  79.945 1.728 79.957 53.016 ;
     RECT  79.957 0.096 80.051 53.016 ;
     RECT  80.051 1.152 80.161 53.016 ;
     RECT  80.051 0.096 80.723 0.168 ;
     RECT  80.161 1.152 81.059 53.592 ;
     RECT  80.723 0.144 81.061 0.168 ;
     RECT  81.059 1.152 81.061 1.176 ;
     RECT  81.061 0.144 81.299 1.176 ;
     RECT  81.299 1.152 81.317 1.176 ;
     RECT  81.299 0.144 81.817 0.168 ;
     RECT  81.059 2.208 82.021 53.592 ;
     RECT  82.021 2.112 82.433 53.592 ;
     RECT  81.817 0.096 82.501 0.168 ;
     RECT  82.501 0.096 82.597 0.216 ;
     RECT  82.597 0.096 82.969 0.888 ;
     RECT  82.969 0.096 83.027 1.128 ;
     RECT  82.433 2.256 83.408 53.592 ;
     RECT  83.408 2.148 83.512 54.012 ;
     RECT  83.512 2.148 83.704 53.784 ;
     RECT  83.704 2.148 84.179 51.336 ;
     RECT  83.027 0.096 84.229 0.888 ;
     RECT  84.179 2.148 84.229 51 ;
     RECT  84.229 0.096 84.707 51 ;
     RECT  83.704 52.32 84.737 53.784 ;
     RECT  84.737 52.32 84.913 53.544 ;
     RECT  84.913 52.224 85.381 53.544 ;
     RECT  84.707 26.352 85.525 51 ;
     RECT  85.381 52.176 85.525 53.544 ;
     RECT  84.707 0.096 85.741 25.368 ;
     RECT  85.525 26.352 85.741 53.544 ;
     RECT  85.741 0.096 85.817 53.544 ;
     RECT  85.817 0.144 85.925 53.544 ;
     RECT  85.925 0.576 86.005 53.544 ;
     RECT  86.005 0.576 86.053 53.592 ;
     RECT  86.053 0.576 86.281 53.688 ;
     RECT  86.281 0.576 86.645 53.784 ;
     RECT  86.645 0.576 86.965 53.64 ;
     RECT  86.965 0.192 87.013 53.64 ;
     RECT  87.013 0.096 88.808 53.64 ;
     RECT  88.808 0.096 88.912 54.012 ;
     RECT  88.912 0.096 89.104 53.742 ;
     RECT  89.104 0.096 89.699 53.592 ;
     RECT  89.699 0.096 90.467 37.944 ;
     RECT  90.467 33.024 90.781 37.944 ;
     RECT  89.699 39.072 90.781 53.592 ;
     RECT  90.781 33.024 90.929 53.592 ;
     RECT  90.467 0.096 90.947 32.04 ;
     RECT  90.929 33.024 91.001 53.544 ;
     RECT  90.947 2.592 91.283 32.04 ;
     RECT  91.001 33.024 91.325 53.496 ;
     RECT  91.283 12.528 91.613 32.04 ;
     RECT  91.325 33.024 91.613 53.112 ;
     RECT  91.613 13.008 91.909 32.04 ;
     RECT  91.613 33.024 91.909 52.488 ;
     RECT  91.283 2.592 92.041 11.448 ;
     RECT  91.909 13.008 92.147 52.488 ;
     RECT  92.041 2.544 92.341 11.448 ;
     RECT  92.341 2.544 92.581 11.976 ;
     RECT  92.147 13.008 92.581 52.344 ;
     RECT  90.947 0.096 92.621 1.416 ;
     RECT  92.581 2.544 92.917 52.344 ;
     RECT  92.917 2.352 92.981 52.344 ;
     RECT  92.981 2.544 93.121 52.344 ;
     RECT  93.121 2.544 93.157 53.064 ;
     RECT  93.157 2.544 93.161 53.16 ;
     RECT  93.161 38.688 93.233 53.16 ;
     RECT  93.233 38.736 93.337 53.16 ;
     RECT  93.161 2.544 94.069 34.392 ;
     RECT  94.069 2.256 94.208 34.392 ;
     RECT  93.161 35.472 94.208 37.224 ;
     RECT  93.337 38.736 94.208 53.544 ;
     RECT  94.208 2.148 94.312 54.012 ;
     RECT  94.312 2.148 94.504 53.742 ;
     RECT  92.621 0.096 94.597 1.128 ;
     RECT  94.504 2.148 94.601 48.984 ;
     RECT  94.597 0.096 94.669 1.176 ;
     RECT  94.601 2.148 94.669 42.696 ;
     RECT  94.669 0.096 94.673 42.696 ;
     RECT  94.601 43.92 94.889 48.984 ;
     RECT  94.504 49.968 94.889 53.112 ;
     RECT  94.673 32.448 94.997 42.696 ;
     RECT  94.889 49.968 95.027 52.488 ;
     RECT  94.997 32.448 95.033 41.592 ;
     RECT  94.889 43.92 95.105 46.2 ;
     RECT  95.105 43.92 95.171 44.712 ;
     RECT  94.673 0.096 95.209 31.368 ;
     RECT  95.105 46.08 95.501 46.2 ;
     RECT  95.209 0.048 95.537 31.368 ;
     RECT  94.889 47.712 95.605 48.984 ;
     RECT  95.027 49.968 95.605 52.44 ;
     RECT  95.537 2.256 95.641 31.368 ;
     RECT  95.033 32.448 95.641 40.008 ;
     RECT  95.641 2.256 95.651 40.008 ;
     RECT  95.651 34.848 95.747 40.008 ;
     RECT  95.747 34.848 95.789 34.872 ;
     RECT  95.537 0.048 95.939 1.224 ;
     RECT  95.033 41.04 95.965 41.592 ;
     RECT  94.997 42.672 95.965 42.696 ;
     RECT  95.747 35.952 96.001 40.008 ;
     RECT  95.965 41.04 96.001 42.696 ;
     RECT  95.605 47.712 96.077 52.44 ;
     RECT  95.171 44.304 96.133 44.712 ;
     RECT  95.501 46.08 96.133 46.152 ;
     RECT  95.939 0.048 96.179 0.744 ;
     RECT  96.001 35.952 96.181 42.696 ;
     RECT  96.077 47.712 96.181 47.736 ;
     RECT  96.179 0.048 96.275 0.648 ;
     RECT  96.181 35.952 96.277 42.792 ;
     RECT  96.133 44.304 96.277 46.152 ;
     RECT  96.277 35.952 96.323 46.152 ;
     RECT  95.651 2.256 96.329 33.624 ;
     RECT  95.989 53.568 96.437 53.592 ;
     RECT  96.077 48.864 96.505 52.44 ;
     RECT  96.329 2.256 96.613 17.304 ;
     RECT  96.323 40.8 96.613 46.152 ;
     RECT  96.181 47.328 96.613 47.736 ;
     RECT  96.613 40.8 96.653 47.736 ;
     RECT  96.329 18.288 96.805 33.624 ;
     RECT  96.505 48.864 96.899 53.448 ;
     RECT  96.323 35.952 96.901 39.768 ;
     RECT  96.901 35.712 96.941 39.768 ;
     RECT  96.653 45.696 97.093 47.736 ;
     RECT  96.899 48.864 97.093 53.208 ;
     RECT  96.805 18.288 97.141 34.248 ;
     RECT  96.613 1.728 97.441 17.304 ;
     RECT  97.141 18.288 97.441 34.632 ;
     RECT  97.441 1.728 97.513 34.632 ;
     RECT  96.941 35.712 97.513 36.888 ;
     RECT  96.941 38.208 97.513 39.768 ;
     RECT  96.653 40.8 97.513 44.664 ;
     RECT  96.275 0.048 97.573 0.216 ;
     RECT  97.093 45.696 97.667 53.208 ;
     RECT  97.513 1.728 97.909 36.888 ;
     RECT  97.513 38.208 97.909 44.664 ;
     RECT  97.909 1.728 97.913 44.664 ;
     RECT  97.913 1.728 98.003 41.64 ;
     RECT  97.573 0.048 98.017 0.6 ;
     RECT  98.003 1.728 98.017 39.096 ;
     RECT  98.017 0.048 98.021 39.096 ;
     RECT  98.003 40.08 98.051 41.64 ;
     RECT  97.913 43.008 98.413 44.664 ;
     RECT  97.667 45.696 98.413 47.352 ;
     RECT  97.667 48.432 98.437 53.208 ;
     RECT  98.413 43.008 98.869 47.352 ;
     RECT  98.437 48.432 98.869 53.496 ;
     RECT  98.869 43.008 98.917 53.496 ;
     RECT  98.051 40.272 99.097 41.64 ;
     RECT  98.917 43.008 99.097 53.592 ;
     RECT  98.021 0.048 99.155 1.176 ;
     RECT  98.021 2.16 99.253 39.096 ;
     RECT  99.097 40.272 99.253 53.592 ;
     RECT  99.253 2.16 99.529 53.592 ;
     RECT  99.529 2.016 99.608 53.592 ;
     RECT  99.155 0.048 99.635 0.792 ;
     RECT  99.608 2.016 99.712 54.012 ;
     RECT  99.712 2.016 99.904 53.742 ;
     RECT  99.904 2.016 100.109 53.592 ;
     RECT  99.635 0.048 100.145 0.312 ;
     RECT  100.109 2.016 100.361 53.064 ;
     RECT  100.361 34.416 100.577 53.064 ;
     RECT  100.361 2.016 100.837 33.432 ;
     RECT  100.577 38.784 100.973 53.064 ;
     RECT  100.837 1.728 101.117 33.432 ;
     RECT  100.973 50.544 101.125 53.064 ;
     RECT  100.145 0.096 101.221 0.312 ;
     RECT  101.221 0.096 101.363 0.408 ;
     RECT  101.125 50.544 101.405 53.784 ;
     RECT  101.117 2.256 101.461 33.432 ;
     RECT  100.577 34.416 101.461 37.656 ;
     RECT  101.461 2.256 101.605 37.656 ;
     RECT  100.973 38.784 101.605 49.512 ;
     RECT  101.605 2.256 101.693 49.512 ;
     RECT  101.693 49.488 101.837 49.512 ;
     RECT  101.509 1.152 101.873 1.176 ;
     RECT  101.693 2.256 101.939 48.456 ;
     RECT  101.405 50.544 102.085 53.592 ;
     RECT  101.939 31.344 102.197 48.456 ;
     RECT  101.939 2.256 102.277 30.216 ;
     RECT  101.363 0.096 102.325 0.168 ;
     RECT  102.277 2.208 102.341 30.216 ;
     RECT  102.197 31.344 102.341 40.152 ;
     RECT  102.341 32.496 102.563 40.152 ;
     RECT  102.341 31.344 102.611 31.368 ;
     RECT  102.563 32.496 102.611 38.184 ;
     RECT  102.611 35.904 102.665 38.088 ;
     RECT  102.611 32.496 102.701 34.44 ;
     RECT  102.085 49.968 102.701 53.592 ;
     RECT  102.665 36.048 102.737 38.088 ;
     RECT  102.341 25.008 102.917 30.216 ;
     RECT  102.197 41.136 102.947 48.456 ;
     RECT  102.701 53.376 102.985 53.592 ;
     RECT  102.917 25.008 103.043 27.48 ;
     RECT  102.947 46.224 103.043 48.456 ;
     RECT  102.701 49.968 103.165 52.2 ;
     RECT  102.985 53.376 103.187 53.64 ;
     RECT  102.341 2.208 103.189 23.976 ;
     RECT  102.563 39.6 103.189 40.152 ;
     RECT  102.947 41.136 103.189 45 ;
     RECT  102.325 0.096 103.235 0.36 ;
     RECT  102.917 28.512 103.237 30.216 ;
     RECT  102.737 36.816 103.349 38.088 ;
     RECT  103.189 39.6 103.379 45 ;
     RECT  103.189 1.776 103.429 23.976 ;
     RECT  103.165 49.776 103.429 52.2 ;
     RECT  103.633 35.184 103.705 35.208 ;
     RECT  103.379 39.6 103.717 41.4 ;
     RECT  103.429 48.864 103.717 52.2 ;
     RECT  103.187 53.376 103.717 53.592 ;
     RECT  103.717 39.312 103.765 41.4 ;
     RECT  103.237 28.512 103.849 30.888 ;
     RECT  103.429 1.728 103.853 23.976 ;
     RECT  102.701 32.496 103.861 34.104 ;
     RECT  103.705 35.184 103.861 36.6 ;
     RECT  103.849 28.512 103.885 30.984 ;
     RECT  103.861 32.352 103.885 36.6 ;
     RECT  103.349 37.584 103.885 38.088 ;
     RECT  103.765 39.216 103.885 41.4 ;
     RECT  103.235 0.096 103.907 0.216 ;
     RECT  103.379 42.432 103.921 45 ;
     RECT  103.043 46.224 103.921 47.832 ;
     RECT  103.043 25.104 103.957 27.48 ;
     RECT  103.885 28.512 103.957 31.176 ;
     RECT  103.853 1.776 104.005 23.976 ;
     RECT  104.005 1.776 104.101 24.024 ;
     RECT  104.101 1.776 104.149 24.072 ;
     RECT  103.957 25.104 104.149 31.176 ;
     RECT  104.149 1.776 104.173 31.176 ;
     RECT  103.885 32.208 104.173 36.6 ;
     RECT  103.921 42.432 104.281 47.832 ;
     RECT  103.885 37.584 104.341 41.4 ;
     RECT  104.281 42.432 104.341 47.88 ;
     RECT  104.341 37.584 104.389 47.88 ;
     RECT  103.717 48.864 104.389 53.592 ;
     RECT  104.173 1.776 104.465 36.6 ;
     RECT  104.465 2.016 104.605 36.6 ;
     RECT  104.389 37.584 104.605 53.592 ;
     RECT  104.605 2.016 104.869 53.592 ;
     RECT  104.869 2.016 105.008 53.64 ;
     RECT  105.008 2.016 105.011 54.012 ;
     RECT  105.011 2.148 105.112 54.012 ;
     RECT  103.907 0.096 105.157 0.168 ;
     RECT  105.112 2.256 105.304 53.742 ;
     RECT  105.304 2.256 105.365 19.704 ;
     RECT  105.304 23.088 105.365 23.112 ;
     RECT  105.157 0.096 105.401 0.6 ;
     RECT  105.304 33.072 105.401 34.152 ;
     RECT  105.365 2.304 105.437 19.704 ;
     RECT  105.437 2.64 105.443 18.312 ;
     RECT  105.437 19.584 105.443 19.704 ;
     RECT  105.304 20.832 105.443 20.904 ;
     RECT  105.304 26.256 105.443 26.28 ;
     RECT  105.304 29.568 105.443 29.64 ;
     RECT  105.304 30.96 105.443 30.984 ;
     RECT  105.304 32.016 105.443 32.04 ;
     RECT  105.401 33.072 105.443 33.288 ;
     RECT  105.304 36.048 105.443 36.072 ;
     RECT  105.304 38.496 105.443 38.52 ;
     RECT  105.304 39.552 105.443 40.008 ;
     RECT  105.304 42.144 105.443 42.168 ;
     RECT  105.304 43.344 105.443 43.368 ;
     RECT  105.304 44.4 105.443 44.472 ;
     RECT  105.304 46.32 105.443 46.344 ;
     RECT  105.304 47.328 105.443 48.456 ;
     RECT  105.304 49.536 105.443 49.56 ;
     RECT  105.304 50.592 105.443 52.44 ;
     RECT  105.443 33.072 105.473 33.096 ;
     RECT  105.443 52.272 105.509 52.44 ;
     RECT  105.443 2.64 105.539 10.488 ;
     RECT  105.443 11.472 105.539 18.312 ;
     RECT  105.539 17.184 105.581 17.736 ;
     RECT  105.539 2.832 105.617 8.04 ;
     RECT  105.443 39.984 105.617 40.008 ;
     RECT  105.539 11.472 105.635 16.056 ;
     RECT  105.635 11.472 105.653 16.008 ;
     RECT  105.617 2.832 105.683 7.992 ;
     RECT  105.401 0.096 105.689 0.264 ;
     RECT  105.653 11.472 105.725 15.432 ;
     RECT  105.581 17.184 105.725 17.688 ;
     RECT  105.443 20.88 105.725 20.904 ;
     RECT  105.443 48.432 105.725 48.456 ;
     RECT  105.509 52.272 105.725 52.296 ;
     RECT  105.683 6.24 105.731 7.464 ;
     RECT  105.725 12.48 105.731 15.432 ;
     RECT  105.725 17.184 105.731 17.208 ;
     RECT  105.443 29.616 105.761 29.64 ;
     RECT  105.443 44.448 105.761 44.472 ;
     RECT  105.683 2.832 105.779 4.68 ;
     RECT  105.731 6.96 105.779 7.464 ;
     RECT  105.731 12.48 105.779 13.224 ;
     RECT  105.731 14.256 105.779 15.432 ;
     RECT  105.689 0.24 105.827 0.264 ;
     RECT  105.779 3.984 105.827 4.68 ;
     RECT  105.779 6.96 105.827 6.984 ;
     RECT  105.539 9.12 105.827 10.488 ;
     RECT  105.779 14.256 105.827 15.144 ;
     RECT  105.827 3.984 105.875 4.008 ;
     RECT  105.779 2.832 105.923 2.856 ;
     RECT  105.827 10.464 105.923 10.488 ;
     RECT  105.827 14.256 105.923 14.28 ;
     RECT  105.443 19.68 106.067 19.704 ;
    LAYER M5 ;
     RECT  45.264 0.016 105.864 0.131 ;
     RECT  45.36 0.131 57.384 0.491 ;
     RECT  9.072 0.117 9.096 0.611 ;
     RECT  10.224 0.181 10.248 1.187 ;
     RECT  45.552 0.491 57.384 1.845 ;
     RECT  58.416 0.131 105.864 2.003 ;
     RECT  40.656 1.397 40.68 2.037 ;
     RECT  40.656 2.037 41.592 2.101 ;
     RECT  42.672 1.461 42.696 2.101 ;
     RECT  12.528 0.245 12.552 2.137 ;
     RECT  39.216 1.909 39.24 2.137 ;
     RECT  40.656 2.101 42.696 2.137 ;
     RECT  37.008 2.101 37.032 2.195 ;
     RECT  11.376 1.781 11.4 2.197 ;
     RECT  12.528 2.137 13.32 2.197 ;
     RECT  34.8 2.137 34.92 2.197 ;
     RECT  34.8 2.197 35.64 2.229 ;
     RECT  11.376 2.197 13.656 2.245 ;
     RECT  24 2.137 24.12 2.245 ;
     RECT  34.8 2.229 35.88 2.245 ;
     RECT  44.928 1.845 57.384 2.245 ;
     RECT  2.4 2.137 2.52 2.293 ;
     RECT  16.512 1.973 16.536 2.293 ;
     RECT  7.8 2.137 7.92 2.407 ;
     RECT  18.6 2.137 18.72 2.407 ;
     RECT  23.712 2.245 24.12 2.407 ;
     RECT  29.4 2.137 29.52 2.407 ;
     RECT  16.512 2.293 16.632 2.421 ;
     RECT  44.88 2.245 57.384 2.437 ;
     RECT  58.416 2.003 63.864 2.437 ;
     RECT  23.712 2.407 24.312 2.485 ;
     RECT  25.68 0.309 25.704 2.485 ;
     RECT  44.88 2.437 63.864 2.485 ;
     RECT  25.68 2.485 26.04 2.533 ;
     RECT  27.168 2.485 27.192 2.533 ;
     RECT  33.888 2.245 35.88 2.533 ;
     RECT  38.112 2.245 38.136 2.533 ;
     RECT  39.216 2.137 42.696 2.533 ;
     RECT  44.352 2.485 63.864 2.549 ;
     RECT  23.712 2.485 24.504 2.581 ;
     RECT  7.8 2.407 8.112 2.629 ;
     RECT  15.936 2.421 16.632 2.677 ;
     RECT  25.68 2.533 27.192 2.677 ;
     RECT  7.8 2.629 8.52 2.725 ;
     RECT  10.848 2.245 13.656 2.725 ;
     RECT  25.68 2.677 27.96 2.731 ;
     RECT  21.216 2.725 21.24 2.741 ;
     RECT  38.112 2.533 42.696 2.773 ;
     RECT  7.584 2.725 8.52 2.821 ;
     RECT  21.216 2.741 21.336 2.821 ;
     RECT  27.936 2.731 27.96 2.821 ;
     RECT  33.888 2.533 36.84 2.821 ;
     RECT  43.968 2.549 63.864 2.821 ;
     RECT  64.848 2.003 105.864 2.821 ;
     RECT  2.4 2.293 3.48 2.869 ;
     RECT  33.072 2.821 36.84 2.933 ;
     RECT  20.784 2.821 22.104 2.997 ;
     RECT  23.088 2.581 24.504 2.997 ;
     RECT  25.68 2.731 26.712 2.997 ;
     RECT  32.448 2.933 36.84 3.011 ;
     RECT  38.112 2.773 42.744 3.013 ;
     RECT  43.92 2.821 63.864 3.013 ;
     RECT  2.4 2.869 3.96 3.061 ;
     RECT  2.4 3.061 4.056 3.109 ;
     RECT  10.704 2.725 13.656 3.109 ;
     RECT  38.112 3.013 63.864 3.157 ;
     RECT  64.848 2.821 105.912 3.157 ;
     RECT  7.536 2.821 8.52 3.189 ;
     RECT  7.344 3.189 8.52 3.205 ;
     RECT  33.072 3.011 36.84 3.253 ;
     RECT  38.112 3.157 105.912 3.253 ;
     RECT  18.6 2.407 18.912 3.349 ;
     RECT  18.6 3.349 19.8 3.381 ;
     RECT  20.784 2.997 26.712 3.381 ;
     RECT  6.96 3.205 8.52 3.397 ;
     RECT  27.936 2.821 28.2 3.397 ;
     RECT  29.4 2.407 29.712 3.397 ;
     RECT  18.6 3.381 26.712 3.499 ;
     RECT  10.128 3.109 13.656 3.637 ;
     RECT  15.84 2.677 17.064 3.637 ;
     RECT  18.6 3.499 26.232 3.637 ;
     RECT  15.84 3.637 26.232 3.765 ;
     RECT  27.936 3.397 30.552 3.765 ;
     RECT  5.088 3.349 5.112 3.877 ;
     RECT  6.96 3.397 8.664 3.893 ;
     RECT  9.696 3.637 13.656 3.893 ;
     RECT  33.072 3.253 105.912 4.019 ;
     RECT  27.936 3.765 30.792 4.117 ;
     RECT  31.92 3.829 32.04 4.117 ;
     RECT  6.96 3.893 13.656 4.501 ;
     RECT  15.072 3.765 26.232 4.501 ;
     RECT  6.96 4.501 26.232 4.549 ;
     RECT  27.936 4.117 32.04 4.693 ;
     RECT  33.072 4.019 52.68 4.693 ;
     RECT  6.96 4.549 26.808 4.741 ;
     RECT  27.936 4.693 52.68 4.741 ;
     RECT  5.088 3.877 5.448 4.789 ;
     RECT  6.96 4.741 52.68 4.789 ;
     RECT  2.304 3.109 4.056 4.979 ;
     RECT  5.088 4.789 52.68 4.981 ;
     RECT  53.856 4.019 105.912 4.981 ;
     RECT  5.088 4.981 105.912 5.045 ;
     RECT  5.088 5.045 106.056 5.171 ;
     RECT  5.088 5.171 51.432 5.173 ;
     RECT  5.04 5.173 51.432 5.227 ;
     RECT  2.4 4.979 4.056 5.507 ;
     RECT  5.088 5.227 51.432 5.507 ;
     RECT  21.936 5.507 51.432 5.843 ;
     RECT  36.72 5.843 51.432 6.133 ;
     RECT  52.416 5.171 106.056 6.133 ;
     RECT  36.72 6.133 106.056 6.261 ;
     RECT  5.088 5.507 20.952 6.419 ;
     RECT  6.768 6.419 20.952 6.581 ;
     RECT  21.936 5.843 35.64 6.581 ;
     RECT  36.72 6.261 106.104 6.581 ;
     RECT  5.088 6.419 5.688 6.661 ;
     RECT  2.4 5.507 3.912 6.805 ;
     RECT  5.04 6.661 5.688 6.805 ;
     RECT  6.768 6.581 35.64 6.805 ;
     RECT  36.72 6.581 106.152 6.805 ;
     RECT  2.4 6.805 5.688 6.851 ;
     RECT  6.768 6.805 106.152 6.891 ;
     RECT  6.768 6.891 8.232 7.019 ;
     RECT  9.504 6.891 106.152 7.083 ;
     RECT  9.504 7.083 26.76 7.427 ;
     RECT  2.4 6.851 5.544 7.595 ;
     RECT  27.936 7.083 106.152 7.763 ;
     RECT  6.768 7.019 8.112 7.909 ;
     RECT  6.24 7.909 8.112 7.979 ;
     RECT  31.872 7.763 106.152 8.003 ;
     RECT  27.936 7.763 30.888 8.147 ;
     RECT  31.92 8.003 43.944 8.435 ;
     RECT  9.504 7.427 25.896 8.485 ;
     RECT  45.504 8.003 106.152 8.555 ;
     RECT  27.936 8.147 30.312 8.677 ;
     RECT  27.888 8.677 30.312 8.693 ;
     RECT  31.92 8.435 43.896 8.723 ;
     RECT  9.504 8.485 26.232 8.821 ;
     RECT  27.792 8.693 30.312 8.821 ;
     RECT  34.224 8.723 43.896 8.875 ;
     RECT  9.504 8.821 30.312 8.949 ;
     RECT  6.768 7.979 8.112 9.061 ;
     RECT  31.92 8.723 33.096 9.061 ;
     RECT  9.12 8.949 30.312 9.067 ;
     RECT  31.296 9.061 33.096 9.067 ;
     RECT  14.496 9.067 28.056 9.131 ;
     RECT  34.272 8.875 43.896 9.131 ;
     RECT  14.496 9.131 26.76 9.155 ;
     RECT  27.792 9.131 28.056 9.155 ;
     RECT  20.16 9.155 26.76 9.203 ;
     RECT  6.48 9.061 8.112 9.253 ;
     RECT  6.24 9.253 8.112 9.269 ;
     RECT  9.12 9.067 13.512 9.269 ;
     RECT  6.24 9.269 13.512 9.323 ;
     RECT  29.136 9.067 30.312 9.333 ;
     RECT  31.296 9.067 33.048 9.333 ;
     RECT  20.16 9.203 26.712 9.451 ;
     RECT  34.368 9.131 43.896 9.451 ;
     RECT  45.6 8.555 106.152 9.461 ;
     RECT  14.496 9.155 19.176 9.539 ;
     RECT  2.4 7.595 5.064 9.637 ;
     RECT  20.4 9.451 26.712 9.643 ;
     RECT  37.488 9.451 43.896 9.717 ;
     RECT  45.6 9.461 106.2 9.717 ;
     RECT  20.4 9.643 26.664 9.779 ;
     RECT  37.488 9.717 106.2 9.779 ;
     RECT  21.12 9.779 26.664 9.875 ;
     RECT  50.352 9.779 106.2 9.875 ;
     RECT  53.136 9.875 106.2 9.971 ;
     RECT  50.352 9.875 51.912 10.067 ;
     RECT  29.136 9.333 33.048 10.069 ;
     RECT  6.336 9.323 13.512 10.101 ;
     RECT  14.496 9.539 19.08 10.101 ;
     RECT  37.488 9.779 49.32 10.115 ;
     RECT  21.552 9.875 26.664 10.155 ;
     RECT  21.648 10.155 26.664 10.163 ;
     RECT  27.888 9.155 28.056 10.165 ;
     RECT  29.088 10.069 33.048 10.165 ;
     RECT  6.336 10.101 19.08 10.219 ;
     RECT  50.64 10.067 51.912 10.307 ;
     RECT  27.888 10.165 33.048 10.405 ;
     RECT  34.368 9.451 36.456 10.405 ;
     RECT  27.888 10.405 36.456 10.741 ;
     RECT  37.488 10.115 38.184 10.741 ;
     RECT  27.888 10.741 38.184 10.795 ;
     RECT  39.408 10.115 49.32 10.859 ;
     RECT  53.136 9.971 64.152 10.883 ;
     RECT  20.448 10.837 20.472 10.933 ;
     RECT  39.408 10.859 43.848 11.171 ;
     RECT  65.232 9.971 106.2 11.189 ;
     RECT  13.2 10.219 19.08 11.221 ;
     RECT  22.032 10.163 26.52 11.243 ;
     RECT  39.408 11.171 43.368 11.243 ;
     RECT  13.104 11.221 19.08 11.269 ;
     RECT  20.448 10.933 20.568 11.269 ;
     RECT  20.16 11.269 20.568 11.317 ;
     RECT  22.032 11.243 26.424 11.317 ;
     RECT  55.824 10.883 64.152 11.317 ;
     RECT  65.232 11.189 106.248 11.317 ;
     RECT  6.48 10.219 11.592 11.365 ;
     RECT  27.888 10.795 35.88 11.365 ;
     RECT  50.88 10.307 51.624 11.381 ;
     RECT  20.16 11.317 26.424 11.411 ;
     RECT  50.592 11.381 51.624 11.413 ;
     RECT  2.4 9.637 5.112 11.509 ;
     RECT  6.24 11.365 11.592 11.509 ;
     RECT  2.4 11.509 11.64 11.699 ;
     RECT  12.864 11.269 19.08 11.701 ;
     RECT  20.16 11.411 21.096 11.701 ;
     RECT  50.592 11.413 51.864 11.701 ;
     RECT  53.136 10.883 54.84 11.701 ;
     RECT  36.912 10.795 38.184 11.829 ;
     RECT  39.408 11.243 43.032 11.829 ;
     RECT  4.512 11.699 11.64 11.891 ;
     RECT  36.912 11.829 43.032 11.939 ;
     RECT  27.504 11.365 35.88 11.941 ;
     RECT  36.912 11.939 41.496 11.941 ;
     RECT  12.864 11.701 21.096 11.947 ;
     RECT  27.504 11.941 41.496 11.947 ;
     RECT  44.976 10.859 49.32 11.957 ;
     RECT  50.544 11.701 54.84 11.957 ;
     RECT  44.976 11.957 54.84 12.131 ;
     RECT  27.504 11.947 37.608 12.267 ;
     RECT  22.224 11.411 26.424 12.323 ;
     RECT  4.608 11.891 11.64 12.325 ;
     RECT  12.864 11.947 20.472 12.325 ;
     RECT  22.32 12.323 26.424 12.517 ;
     RECT  27.504 12.267 30.84 12.517 ;
     RECT  45.456 12.131 54.84 12.517 ;
     RECT  55.824 11.317 106.248 12.517 ;
     RECT  22.32 12.517 30.84 12.587 ;
     RECT  4.608 12.325 20.472 12.611 ;
     RECT  4.608 12.611 20.088 12.851 ;
     RECT  38.592 11.947 41.496 12.949 ;
     RECT  42.576 11.939 43.032 12.949 ;
     RECT  38.592 12.949 43.032 12.981 ;
     RECT  31.872 12.267 37.608 13.043 ;
     RECT  2.4 11.699 3.288 13.285 ;
     RECT  4.608 12.851 19.992 13.285 ;
     RECT  27.12 12.587 30.84 13.365 ;
     RECT  31.872 13.043 35.928 13.365 ;
     RECT  38.592 12.981 43.656 13.381 ;
     RECT  45.456 12.517 106.248 13.381 ;
     RECT  27.12 13.365 35.928 13.419 ;
     RECT  22.32 12.587 26.088 13.557 ;
     RECT  22.32 13.557 26.76 13.571 ;
     RECT  37.008 13.043 37.608 13.685 ;
     RECT  38.592 13.381 44.136 13.685 ;
     RECT  27.888 13.419 35.928 13.715 ;
     RECT  2.4 13.285 19.992 13.811 ;
     RECT  34.56 13.715 35.496 13.811 ;
     RECT  13.008 13.811 19.992 13.813 ;
     RECT  21.072 13.749 21.096 13.813 ;
     RECT  37.008 13.685 44.136 13.813 ;
     RECT  45.264 13.381 106.248 13.813 ;
     RECT  13.008 13.813 21.096 13.859 ;
     RECT  37.008 13.813 106.248 13.955 ;
     RECT  34.56 13.811 35.4 14.051 ;
     RECT  37.152 13.955 106.248 14.051 ;
     RECT  23.616 13.571 26.76 14.059 ;
     RECT  27.888 13.715 33.576 14.099 ;
     RECT  27.888 14.099 30.84 14.339 ;
     RECT  13.008 13.859 20.904 14.379 ;
     RECT  37.152 14.051 37.608 14.387 ;
     RECT  13.008 14.379 13.608 14.435 ;
     RECT  14.832 14.379 20.904 14.507 ;
     RECT  29.4 14.339 30.84 14.531 ;
     RECT  23.904 14.059 26.76 14.581 ;
     RECT  22.32 13.571 22.536 14.645 ;
     RECT  14.832 14.507 15.24 14.699 ;
     RECT  22.08 14.645 22.536 14.699 ;
     RECT  38.736 14.051 106.248 14.723 ;
     RECT  31.824 14.099 33.576 14.773 ;
     RECT  34.56 14.051 35.256 14.773 ;
     RECT  2.4 13.811 11.88 14.867 ;
     RECT  14.832 14.699 14.904 14.867 ;
     RECT  16.416 14.507 20.904 14.867 ;
     RECT  31.824 14.773 35.256 14.867 ;
     RECT  22.08 14.699 22.104 14.915 ;
     RECT  18.6 14.867 20.904 14.963 ;
     RECT  16.416 14.867 17.16 15.011 ;
     RECT  16.416 15.011 16.632 15.203 ;
     RECT  33.552 14.867 35.256 15.301 ;
     RECT  31.824 14.867 32.472 15.347 ;
     RECT  13.008 14.435 13.512 15.349 ;
     RECT  29.4 14.531 30.792 15.349 ;
     RECT  23.904 14.581 27.336 15.493 ;
     RECT  19.968 14.963 20.904 15.589 ;
     RECT  23.904 15.493 27.48 15.589 ;
     RECT  23.52 15.589 27.48 15.659 ;
     RECT  11.952 15.349 13.512 15.669 ;
     RECT  14.832 14.867 14.856 15.669 ;
     RECT  37.152 14.387 37.464 15.733 ;
     RECT  38.784 14.723 106.248 15.733 ;
     RECT  23.52 15.659 26.616 15.787 ;
     RECT  37.152 15.733 106.248 15.787 ;
     RECT  33.552 15.301 35.88 15.989 ;
     RECT  2.4 14.867 10.968 16.019 ;
     RECT  16.416 15.203 16.44 16.019 ;
     RECT  37.152 15.787 37.272 16.021 ;
     RECT  29.04 15.349 30.792 16.069 ;
     RECT  31.824 15.347 31.848 16.069 ;
     RECT  19.968 15.589 21.24 16.245 ;
     RECT  23.568 15.787 26.616 16.259 ;
     RECT  33.072 15.989 35.88 16.259 ;
     RECT  33.072 16.259 35.784 16.363 ;
     RECT  37.056 16.021 37.272 16.363 ;
     RECT  19.92 16.245 21.24 16.437 ;
     RECT  19.92 16.437 22.2 16.499 ;
     RECT  38.256 15.787 106.248 16.499 ;
     RECT  11.952 15.669 14.856 16.501 ;
     RECT  18.6 14.963 18.912 16.501 ;
     RECT  19.92 16.499 21.24 16.501 ;
     RECT  29.04 16.069 31.848 16.501 ;
     RECT  6.864 16.019 10.968 16.565 ;
     RECT  11.952 16.501 16.008 16.565 ;
     RECT  6.864 16.565 16.008 16.595 ;
     RECT  2.4 16.019 5.736 16.619 ;
     RECT  5.136 16.619 5.736 16.643 ;
     RECT  23.568 16.259 25.32 16.885 ;
     RECT  23.376 16.885 25.32 16.981 ;
     RECT  6.864 16.595 10.632 17.003 ;
     RECT  28.368 16.501 31.848 17.029 ;
     RECT  18.6 16.501 21.24 17.067 ;
     RECT  22.992 16.981 25.32 17.067 ;
     RECT  37.056 16.363 37.224 17.067 ;
     RECT  11.856 16.595 16.008 17.075 ;
     RECT  34.8 16.363 35.784 17.195 ;
     RECT  33.072 16.363 33.576 17.219 ;
     RECT  11.952 17.075 16.008 17.267 ;
     RECT  11.952 17.267 14.856 17.387 ;
     RECT  39.36 16.499 106.248 17.387 ;
     RECT  11.952 17.387 14.232 17.411 ;
     RECT  26.544 16.259 26.616 17.461 ;
     RECT  27.84 17.029 31.848 17.461 ;
     RECT  39.936 17.387 106.248 17.515 ;
     RECT  39.936 17.515 53.544 17.579 ;
     RECT  23.376 17.067 25.32 17.589 ;
     RECT  26.544 17.461 31.848 17.589 ;
     RECT  5.712 16.643 5.736 17.605 ;
     RECT  6.864 17.003 8.28 17.605 ;
     RECT  18.6 17.067 21.096 17.605 ;
     RECT  23.376 17.589 31.848 17.651 ;
     RECT  5.712 17.605 8.28 17.699 ;
     RECT  9.696 17.003 10.632 17.749 ;
     RECT  23.376 17.651 24.792 17.795 ;
     RECT  9.696 17.749 10.68 17.843 ;
     RECT  10.08 17.843 10.68 17.987 ;
     RECT  10.656 17.987 10.68 18.133 ;
     RECT  11.952 17.411 13.8 18.133 ;
     RECT  37.056 17.067 37.176 18.133 ;
     RECT  38.256 16.499 38.28 18.133 ;
     RECT  15.984 17.267 16.008 18.229 ;
     RECT  5.712 17.699 8.112 18.275 ;
     RECT  34.8 17.195 35.352 18.277 ;
     RECT  36.432 18.133 37.176 18.277 ;
     RECT  10.656 18.133 13.8 18.421 ;
     RECT  38.208 18.133 38.28 18.661 ;
     RECT  15.264 18.229 16.008 18.677 ;
     RECT  18.192 17.605 21.096 18.677 ;
     RECT  2.4 16.619 3.912 18.709 ;
     RECT  17.664 18.677 21.096 18.709 ;
     RECT  15.264 18.677 16.152 18.755 ;
     RECT  17.28 18.709 21.096 18.805 ;
     RECT  15.984 18.755 16.008 18.851 ;
     RECT  26.448 17.651 31.848 18.851 ;
     RECT  34.8 18.277 37.176 18.851 ;
     RECT  54.528 17.515 106.248 18.851 ;
     RECT  17.28 18.805 21.144 18.869 ;
     RECT  33.552 17.219 33.576 18.869 ;
     RECT  34.8 18.851 35.832 18.869 ;
     RECT  17.232 18.869 21.144 18.901 ;
     RECT  38.208 18.661 38.472 18.923 ;
     RECT  10.656 18.421 14.28 18.933 ;
     RECT  17.04 18.901 21.144 18.987 ;
     RECT  10.656 18.933 14.328 18.995 ;
     RECT  17.184 18.987 21.144 18.995 ;
     RECT  17.184 18.995 21.096 19.043 ;
     RECT  40.032 17.579 53.544 19.235 ;
     RECT  5.712 18.275 5.736 19.237 ;
     RECT  6.864 18.275 8.112 19.237 ;
     RECT  17.28 19.043 21.096 19.243 ;
     RECT  5.712 19.237 8.112 19.283 ;
     RECT  54.576 18.851 106.248 19.307 ;
     RECT  9.648 19.285 9.672 19.317 ;
     RECT  10.656 18.995 14.28 19.317 ;
     RECT  24 17.795 24.792 19.333 ;
     RECT  38.256 18.923 38.472 19.333 ;
     RECT  9.648 19.317 14.28 19.371 ;
     RECT  23.088 19.333 24.792 19.381 ;
     RECT  2.4 18.709 4.056 19.427 ;
     RECT  26.448 18.851 30.216 19.523 ;
     RECT  43.632 19.235 53.544 19.755 ;
     RECT  27.84 19.523 30.216 19.813 ;
     RECT  31.248 18.851 31.848 19.813 ;
     RECT  33.552 18.869 35.832 19.813 ;
     RECT  37.056 18.851 37.176 19.909 ;
     RECT  50.64 19.755 53.544 19.955 ;
     RECT  38.256 19.333 39.048 19.957 ;
     RECT  40.032 19.235 42.36 19.957 ;
     RECT  9.936 19.371 14.28 20.003 ;
     RECT  38.256 19.957 42.36 20.051 ;
     RECT  23.088 19.381 25.128 20.139 ;
     RECT  33.168 19.813 35.832 20.197 ;
     RECT  2.4 19.427 2.712 20.437 ;
     RECT  3.888 19.427 4.056 20.437 ;
     RECT  2.4 20.437 4.056 20.469 ;
     RECT  2.4 20.469 4.872 20.523 ;
     RECT  6.24 19.283 8.112 20.523 ;
     RECT  7.8 20.523 8.112 20.533 ;
     RECT  38.256 20.051 38.328 20.533 ;
     RECT  11.616 20.003 14.28 20.579 ;
     RECT  43.632 19.755 49.608 20.579 ;
     RECT  50.64 19.955 52.584 20.579 ;
     RECT  11.712 20.579 14.28 20.581 ;
     RECT  37.056 19.909 37.224 20.587 ;
     RECT  11.712 20.581 14.808 20.627 ;
     RECT  14.784 20.627 14.808 20.651 ;
     RECT  17.28 19.243 20.808 20.651 ;
     RECT  47.04 20.579 49.608 20.819 ;
     RECT  26.448 19.523 26.616 20.821 ;
     RECT  54.816 19.307 106.248 21.035 ;
     RECT  53.664 20.341 53.688 21.109 ;
     RECT  54.816 21.035 105.912 21.109 ;
     RECT  7.8 20.533 8.664 21.155 ;
     RECT  38.208 20.533 38.328 21.155 ;
     RECT  53.664 21.109 105.912 21.163 ;
     RECT  39.36 20.051 42.36 21.203 ;
     RECT  50.64 20.579 52.44 21.227 ;
     RECT  33.168 20.197 35.88 21.301 ;
     RECT  37.056 20.587 37.176 21.301 ;
     RECT  39.888 21.203 42.36 21.347 ;
     RECT  33.072 21.301 37.176 21.355 ;
     RECT  33.168 21.355 37.176 21.395 ;
     RECT  53.664 21.163 105.864 21.419 ;
     RECT  4.032 20.523 4.872 21.445 ;
     RECT  23.088 20.139 24.456 21.541 ;
     RECT  4.032 21.445 5.016 21.637 ;
     RECT  11.712 20.627 13.512 21.637 ;
     RECT  18 20.651 20.808 21.637 ;
     RECT  22.08 20.485 22.104 21.637 ;
     RECT  23.088 21.541 24.504 21.637 ;
     RECT  9.936 20.003 9.96 21.683 ;
     RECT  18 21.637 22.104 21.683 ;
     RECT  50.688 21.227 52.44 21.739 ;
     RECT  23.088 21.637 25.176 21.867 ;
     RECT  43.632 20.579 46.008 22.133 ;
     RECT  47.04 20.819 49.56 22.133 ;
     RECT  2.4 20.523 2.712 22.165 ;
     RECT  4.032 21.637 5.112 22.165 ;
     RECT  26.448 20.821 26.76 22.165 ;
     RECT  27.84 19.813 31.848 22.165 ;
     RECT  43.632 22.133 49.56 22.197 ;
     RECT  2.4 22.165 5.112 22.251 ;
     RECT  43.632 22.197 49.608 22.251 ;
     RECT  55.872 21.419 105.864 22.315 ;
     RECT  6.24 20.523 6.264 22.325 ;
     RECT  7.8 21.155 8.112 22.325 ;
     RECT  33.216 21.395 37.176 22.355 ;
     RECT  3.984 22.251 5.112 22.389 ;
     RECT  6.24 22.325 8.112 22.389 ;
     RECT  11.52 21.637 13.512 22.389 ;
     RECT  40.032 21.347 42.36 22.405 ;
     RECT  3.984 22.389 8.112 22.451 ;
     RECT  16.8 22.389 16.824 22.453 ;
     RECT  43.632 22.251 47.112 22.499 ;
     RECT  39.984 22.405 42.36 22.507 ;
     RECT  16.512 22.453 16.824 22.517 ;
     RECT  33.216 22.355 33.576 22.549 ;
     RECT  10.224 22.325 10.392 22.645 ;
     RECT  11.52 22.389 13.608 22.645 ;
     RECT  10.224 22.645 13.608 22.709 ;
     RECT  6.24 22.451 8.112 22.739 ;
     RECT  7.632 22.739 8.112 22.741 ;
     RECT  18.48 21.683 22.104 22.773 ;
     RECT  23.088 21.867 24.6 22.773 ;
     RECT  55.872 22.315 105.432 22.827 ;
     RECT  75.984 22.827 105.432 22.835 ;
     RECT  34.8 22.355 37.176 22.837 ;
     RECT  26.448 22.165 31.848 22.965 ;
     RECT  33.072 22.549 33.576 22.965 ;
     RECT  48.192 22.251 49.608 22.981 ;
     RECT  53.664 21.419 54.552 23.019 ;
     RECT  38.256 21.155 38.328 23.029 ;
     RECT  51 21.739 52.44 23.029 ;
     RECT  55.872 22.827 75 23.083 ;
     RECT  51 23.029 53.112 23.171 ;
     RECT  15.168 22.709 15.432 23.173 ;
     RECT  16.512 22.517 17.064 23.173 ;
     RECT  15.168 23.173 17.064 23.219 ;
     RECT  15.936 23.219 17.064 23.221 ;
     RECT  55.968 23.083 75 23.315 ;
     RECT  10.032 22.709 13.608 23.317 ;
     RECT  14.688 23.285 14.904 23.317 ;
     RECT  40.032 22.507 42.36 23.317 ;
     RECT  43.632 22.499 46.776 23.317 ;
     RECT  7.632 22.741 8.568 23.403 ;
     RECT  3.984 22.451 5.112 23.411 ;
     RECT  10.032 23.317 14.904 23.413 ;
     RECT  18.48 22.773 24.6 23.413 ;
     RECT  15.936 23.221 17.304 23.467 ;
     RECT  16.08 23.467 17.304 23.509 ;
     RECT  18.336 23.413 24.6 23.509 ;
     RECT  51 23.171 51.48 23.509 ;
     RECT  50.832 23.509 51.48 23.651 ;
     RECT  40.032 23.317 46.776 23.653 ;
     RECT  48.192 22.981 49.656 23.653 ;
     RECT  7.632 23.403 8.52 23.659 ;
     RECT  16.08 23.509 24.6 23.699 ;
     RECT  40.032 23.653 49.656 23.699 ;
     RECT  2.4 22.251 2.712 23.701 ;
     RECT  3.984 23.411 4.008 23.701 ;
     RECT  6.24 22.739 6.264 23.701 ;
     RECT  7.632 23.659 8.112 23.701 ;
     RECT  6.24 23.701 8.112 23.787 ;
     RECT  16.08 23.699 17.304 23.787 ;
     RECT  50.832 23.651 51.432 23.795 ;
     RECT  52.8 23.171 53.112 23.795 ;
     RECT  34.8 22.837 37.224 23.797 ;
     RECT  18.336 23.699 24.6 23.843 ;
     RECT  34.704 23.797 37.224 23.891 ;
     RECT  40.2 23.699 49.656 23.891 ;
     RECT  56.304 23.315 75 23.925 ;
     RECT  75.984 22.835 85.128 23.925 ;
     RECT  9.648 23.413 14.904 23.987 ;
     RECT  40.2 23.891 46.776 23.987 ;
     RECT  18.432 23.843 24.6 24.037 ;
     RECT  10.032 23.987 14.904 24.083 ;
     RECT  48.192 23.891 49.656 24.085 ;
     RECT  50.832 23.795 51.312 24.085 ;
     RECT  10.8 24.083 14.904 24.179 ;
     RECT  38.256 23.029 38.664 24.181 ;
     RECT  56.304 23.925 85.128 24.227 ;
     RECT  4.992 23.411 5.112 24.245 ;
     RECT  6.24 23.787 6.408 24.245 ;
     RECT  26.448 22.965 33.576 24.309 ;
     RECT  4.992 24.245 6.408 24.323 ;
     RECT  7.632 23.787 8.112 24.323 ;
     RECT  18.432 24.037 24.648 24.325 ;
     RECT  26.016 24.309 33.576 24.325 ;
     RECT  18.432 24.325 33.576 24.371 ;
     RECT  18.432 24.371 25.08 24.427 ;
     RECT  4.992 24.323 5.016 24.515 ;
     RECT  56.4 24.227 85.128 24.563 ;
     RECT  10.848 24.179 14.904 24.629 ;
     RECT  16.08 23.787 16.104 24.629 ;
     RECT  26.448 24.371 33.576 24.683 ;
     RECT  17.28 23.787 17.304 24.805 ;
     RECT  18.432 24.427 24.792 24.805 ;
     RECT  54.528 23.019 54.552 24.805 ;
     RECT  48.192 24.085 51.312 24.821 ;
     RECT  10.848 24.629 16.104 24.853 ;
     RECT  17.28 24.805 24.792 24.853 ;
     RECT  48.192 24.821 51.432 24.853 ;
     RECT  10.848 24.853 24.792 24.875 ;
     RECT  30.768 24.683 33.576 24.885 ;
     RECT  34.8 23.891 37.176 24.885 ;
     RECT  52.8 23.795 53.064 24.899 ;
     RECT  86.16 22.835 105.432 24.901 ;
     RECT  10.848 24.875 17.4 24.939 ;
     RECT  48.096 24.853 51.432 24.939 ;
     RECT  56.4 24.563 84.888 24.939 ;
     RECT  48.192 24.939 51.432 24.997 ;
     RECT  86.016 24.901 105.432 25.003 ;
     RECT  17.28 24.939 17.4 25.043 ;
     RECT  7.8 24.323 8.112 25.045 ;
     RECT  6.288 24.323 6.408 25.091 ;
     RECT  40.2 23.987 46.728 25.139 ;
     RECT  30.768 24.885 37.176 25.189 ;
     RECT  54.144 24.805 54.552 25.189 ;
     RECT  30.768 25.189 37.272 25.235 ;
     RECT  38.256 24.181 39.144 25.237 ;
     RECT  40.2 25.139 46.152 25.237 ;
     RECT  2.4 23.701 4.008 25.285 ;
     RECT  53.472 25.189 54.552 25.429 ;
     RECT  18.384 24.875 24.792 25.461 ;
     RECT  26.448 24.683 29.712 25.461 ;
     RECT  59.04 24.939 84.888 25.475 ;
     RECT  53.472 25.429 55.32 25.515 ;
     RECT  18.384 25.461 29.712 25.523 ;
     RECT  10.848 24.939 16.104 25.619 ;
     RECT  7.8 25.045 8.52 25.715 ;
     RECT  10.848 25.619 11.4 25.715 ;
     RECT  59.088 25.475 84.888 25.715 ;
     RECT  2.4 25.285 4.872 25.859 ;
     RECT  2.4 25.859 2.856 26.051 ;
     RECT  12.528 25.619 16.104 26.053 ;
     RECT  17.376 25.043 17.4 26.053 ;
     RECT  7.8 25.715 8.112 26.197 ;
     RECT  30.768 25.235 32.472 26.197 ;
     RECT  33.456 25.235 37.272 26.197 ;
     RECT  53.616 25.515 55.32 26.197 ;
     RECT  56.4 24.939 57.912 26.197 ;
     RECT  3.984 25.859 4.872 26.243 ;
     RECT  6.288 25.091 6.312 26.243 ;
     RECT  60.144 25.715 84.888 26.243 ;
     RECT  26.448 25.523 29.712 26.245 ;
     RECT  30.768 26.197 37.272 26.245 ;
     RECT  12.528 26.053 17.4 26.291 ;
     RECT  26.448 26.245 37.272 26.291 ;
     RECT  86.208 25.003 105.432 26.291 ;
     RECT  48.192 24.997 52.488 26.293 ;
     RECT  31.104 26.291 37.272 26.389 ;
     RECT  38.256 25.237 46.152 26.389 ;
     RECT  47.76 26.293 52.488 26.435 ;
     RECT  86.208 26.291 105.312 26.435 ;
     RECT  18.384 25.523 24.888 26.485 ;
     RECT  12.768 26.291 17.4 26.677 ;
     RECT  18.384 26.485 25.128 26.677 ;
     RECT  26.448 26.291 30.072 26.677 ;
     RECT  86.208 26.435 89.496 26.771 ;
     RECT  31.104 26.389 46.152 26.819 ;
     RECT  59.088 25.715 59.112 26.819 ;
     RECT  4.848 26.243 4.872 26.821 ;
     RECT  43.344 26.819 46.152 26.869 ;
     RECT  7.392 26.197 8.112 26.915 ;
     RECT  12.768 26.677 30.072 26.963 ;
     RECT  53.616 26.197 57.912 27.061 ;
     RECT  47.808 26.435 52.488 27.109 ;
     RECT  53.616 27.061 58.584 27.109 ;
     RECT  10.896 25.715 10.92 27.253 ;
     RECT  7.68 26.915 8.112 27.301 ;
     RECT  9.888 27.157 9.912 27.301 ;
     RECT  10.896 27.253 11.112 27.301 ;
     RECT  26.064 26.963 30.072 27.301 ;
     RECT  31.104 26.819 42.36 27.301 ;
     RECT  43.344 26.869 46.488 27.301 ;
     RECT  4.848 26.821 5.64 27.347 ;
     RECT  43.344 27.301 46.728 27.371 ;
     RECT  90.624 26.435 105.312 27.395 ;
     RECT  26.064 27.301 42.36 27.499 ;
     RECT  28.8 27.499 42.36 27.635 ;
     RECT  7.68 27.301 8.52 27.685 ;
     RECT  9.888 27.301 11.112 27.685 ;
     RECT  90.624 27.395 98.424 27.685 ;
     RECT  26.064 27.499 27.816 27.755 ;
     RECT  2.4 26.051 2.712 27.829 ;
     RECT  43.488 27.371 46.728 27.829 ;
     RECT  47.808 27.109 58.584 27.829 ;
     RECT  5.616 27.347 5.64 27.883 ;
     RECT  7.68 27.685 11.304 27.883 ;
     RECT  26.784 27.755 27.816 27.947 ;
     RECT  12.768 26.963 24.888 27.971 ;
     RECT  86.496 26.771 89.496 28.213 ;
     RECT  90.576 27.685 98.424 28.213 ;
     RECT  43.488 27.829 58.584 28.261 ;
     RECT  7.68 27.883 8.52 28.309 ;
     RECT  43.488 28.261 59.208 28.331 ;
     RECT  12.768 27.971 15.048 28.405 ;
     RECT  16.08 27.971 24.888 28.405 ;
     RECT  86.496 28.213 98.424 28.405 ;
     RECT  99.504 27.395 105.312 28.405 ;
     RECT  60.24 26.243 84.888 28.453 ;
     RECT  6.816 28.309 8.52 28.523 ;
     RECT  9.792 27.883 11.304 28.533 ;
     RECT  12.624 28.405 15.048 28.533 ;
     RECT  59.712 28.453 84.888 28.587 ;
     RECT  59.712 28.587 60.456 28.643 ;
     RECT  29.04 27.635 42.36 28.661 ;
     RECT  43.488 28.331 58.728 28.661 ;
     RECT  86.496 28.405 105.312 28.693 ;
     RECT  61.584 28.587 84.888 28.725 ;
     RECT  86.208 28.693 105.312 28.779 ;
     RECT  29.04 28.661 58.728 28.787 ;
     RECT  5.136 28.453 5.16 28.789 ;
     RECT  29.28 28.787 58.728 28.883 ;
     RECT  61.584 28.725 85.128 29.027 ;
     RECT  9.792 28.533 15.048 29.029 ;
     RECT  26.928 27.947 27.816 29.029 ;
     RECT  29.28 28.883 58.632 29.099 ;
     RECT  16.08 28.405 25.656 29.109 ;
     RECT  9.648 29.029 15.048 29.123 ;
     RECT  26.928 29.029 27.96 29.173 ;
     RECT  7.68 28.523 8.52 29.237 ;
     RECT  9.648 29.123 11.304 29.237 ;
     RECT  16.08 29.109 25.752 29.301 ;
     RECT  26.928 29.173 28.056 29.301 ;
     RECT  7.68 29.237 11.304 29.315 ;
     RECT  16.08 29.301 28.056 29.315 ;
     RECT  2.4 27.829 3.528 29.317 ;
     RECT  5.088 28.789 5.16 29.365 ;
     RECT  16.08 29.315 27.96 29.461 ;
     RECT  12.528 29.123 15.048 29.493 ;
     RECT  16.032 29.461 27.96 29.493 ;
     RECT  61.68 29.027 85.128 29.507 ;
     RECT  86.64 28.779 105.312 29.557 ;
     RECT  86.64 29.557 105.432 29.611 ;
     RECT  61.68 29.507 84.936 29.651 ;
     RECT  61.68 29.651 63.192 29.747 ;
     RECT  7.68 29.315 8.472 29.803 ;
     RECT  12.528 29.493 27.96 29.843 ;
     RECT  29.4 29.099 58.632 29.891 ;
     RECT  64.608 29.651 75 29.891 ;
     RECT  12.528 29.843 16.248 29.939 ;
     RECT  59.712 28.643 59.736 29.941 ;
     RECT  29.4 29.891 55.08 30.035 ;
     RECT  86.64 29.611 98.424 30.037 ;
     RECT  86.016 30.037 98.424 30.123 ;
     RECT  56.208 29.891 58.632 30.133 ;
     RECT  29.4 30.035 42.456 30.197 ;
     RECT  9.504 29.315 11.304 30.261 ;
     RECT  12.528 29.939 16.104 30.261 ;
     RECT  5.088 29.365 6.072 30.275 ;
     RECT  61.68 29.747 63 30.275 ;
     RECT  9.504 30.261 16.104 30.419 ;
     RECT  9.504 30.419 11.832 30.443 ;
     RECT  7.8 29.803 8.472 30.517 ;
     RECT  9.504 30.443 11.544 30.517 ;
     RECT  17.28 29.843 27.96 30.613 ;
     RECT  29.28 30.197 42.456 30.613 ;
     RECT  65.664 29.891 75 30.661 ;
     RECT  76.08 29.651 84.936 30.661 ;
     RECT  13.2 30.419 16.104 30.707 ;
     RECT  86.64 30.123 98.424 30.709 ;
     RECT  99.504 29.611 105.432 30.709 ;
     RECT  59.712 29.941 60.168 30.773 ;
     RECT  43.776 30.035 55.08 30.803 ;
     RECT  61.68 30.275 62.616 30.827 ;
     RECT  15.024 30.707 16.104 30.899 ;
     RECT  16.032 30.899 16.104 30.901 ;
     RECT  17.28 30.613 42.456 30.901 ;
     RECT  65.664 30.661 84.936 30.949 ;
     RECT  2.4 29.317 3.672 30.965 ;
     RECT  16.032 30.901 42.456 30.995 ;
     RECT  47.856 30.803 55.08 31.019 ;
     RECT  86.64 30.709 105.432 31.019 ;
     RECT  86.832 31.019 105.432 31.091 ;
     RECT  56.208 30.133 58.728 31.285 ;
     RECT  59.712 30.773 60.36 31.285 ;
     RECT  17.376 30.995 42.456 31.339 ;
     RECT  26.736 31.339 42.456 31.379 ;
     RECT  64.608 29.891 64.68 31.379 ;
     RECT  65.664 30.949 85.08 31.379 ;
     RECT  7.8 30.517 11.544 31.427 ;
     RECT  9.792 31.427 11.544 31.525 ;
     RECT  13.2 30.707 13.512 31.525 ;
     RECT  64.992 31.477 65.016 31.571 ;
     RECT  26.832 31.379 42.456 31.667 ;
     RECT  43.776 30.803 46.824 31.669 ;
     RECT  9.792 31.525 13.512 31.723 ;
     RECT  66.096 31.379 85.08 31.723 ;
     RECT  26.928 31.667 42.456 31.787 ;
     RECT  2.4 30.965 4.584 31.813 ;
     RECT  5.616 30.275 6.072 31.813 ;
     RECT  61.8 30.827 62.616 31.861 ;
     RECT  56.208 31.285 60.36 31.925 ;
     RECT  61.536 31.861 62.616 31.925 ;
     RECT  2.4 31.813 6.072 31.955 ;
     RECT  27.024 31.787 42.456 32.051 ;
     RECT  43.728 31.669 46.824 32.053 ;
     RECT  47.952 31.019 55.08 32.053 ;
     RECT  56.208 31.925 62.616 32.053 ;
     RECT  7.8 31.427 8.112 32.117 ;
     RECT  43.728 32.053 62.616 32.149 ;
     RECT  9.792 31.723 11.304 32.171 ;
     RECT  43.728 32.149 63.24 32.243 ;
     RECT  5.136 31.955 6.072 32.245 ;
     RECT  5.136 32.245 6.264 32.299 ;
     RECT  7.296 32.117 8.112 32.299 ;
     RECT  43.728 32.243 60.36 32.299 ;
     RECT  15.024 30.899 15.048 32.341 ;
     RECT  16.032 30.995 16.248 32.341 ;
     RECT  86.88 31.091 105.432 32.341 ;
     RECT  27.12 32.051 42.456 32.501 ;
     RECT  86.256 32.341 105.432 32.629 ;
     RECT  61.584 32.243 63.24 32.677 ;
     RECT  13.2 31.723 13.512 32.869 ;
     RECT  5.136 32.299 6.072 32.917 ;
     RECT  13.2 32.869 13.608 32.917 ;
     RECT  15.024 32.341 16.248 32.949 ;
     RECT  17.376 31.339 25.704 32.949 ;
     RECT  13.2 32.917 13.992 32.965 ;
     RECT  15.024 32.949 25.704 32.965 ;
     RECT  61.584 32.677 63.576 33.011 ;
     RECT  61.584 33.011 63.24 33.107 ;
     RECT  61.584 33.107 63.048 33.203 ;
     RECT  61.584 33.203 62.952 33.205 ;
     RECT  43.776 32.299 60.36 33.251 ;
     RECT  61.536 33.205 62.952 33.259 ;
     RECT  86.064 32.629 105.432 33.299 ;
     RECT  61.536 33.259 62.664 33.301 ;
     RECT  7.8 32.299 8.112 33.333 ;
     RECT  10.224 32.171 11.304 33.333 ;
     RECT  13.2 32.965 25.704 33.387 ;
     RECT  7.8 33.333 8.52 33.395 ;
     RECT  27.12 32.501 42.648 33.397 ;
     RECT  86.064 33.299 105.312 33.451 ;
     RECT  66.192 31.723 85.08 33.493 ;
     RECT  13.2 33.387 14.904 33.525 ;
     RECT  64.848 33.493 64.872 33.541 ;
     RECT  66.192 33.493 85.512 33.579 ;
     RECT  10.224 33.333 11.4 33.589 ;
     RECT  12.96 33.525 14.904 33.589 ;
     RECT  64.848 33.541 64.968 33.643 ;
     RECT  66.192 33.579 85.464 33.643 ;
     RECT  2.4 31.955 3.672 33.717 ;
     RECT  4.992 32.917 6.072 33.717 ;
     RECT  27.12 33.397 42.696 33.781 ;
     RECT  43.776 33.251 59.736 33.781 ;
     RECT  81.312 33.643 85.464 33.835 ;
     RECT  64.848 33.643 64.92 33.877 ;
     RECT  26.736 33.781 42.696 33.925 ;
     RECT  43.68 33.781 59.736 33.925 ;
     RECT  81.312 33.835 85.368 34.067 ;
     RECT  61.008 33.301 62.664 34.091 ;
     RECT  2.4 33.717 6.072 34.117 ;
     RECT  15.888 33.387 25.704 34.117 ;
     RECT  26.736 33.925 59.736 34.117 ;
     RECT  64.368 33.877 64.92 34.259 ;
     RECT  86.592 33.451 105.312 34.259 ;
     RECT  2.4 34.117 6.696 34.293 ;
     RECT  7.8 33.395 8.112 34.293 ;
     RECT  2.4 34.293 8.112 34.355 ;
     RECT  10.224 33.589 14.904 34.357 ;
     RECT  15.888 34.117 59.736 34.357 ;
     RECT  61.8 34.091 62.664 34.357 ;
     RECT  10.224 34.357 59.736 34.411 ;
     RECT  66.192 33.643 80.04 34.411 ;
     RECT  6.048 34.355 8.112 34.421 ;
     RECT  6.048 34.421 8.376 34.603 ;
     RECT  10.224 34.411 25.032 34.603 ;
     RECT  2.4 34.355 5.016 34.835 ;
     RECT  74.592 34.411 80.04 34.933 ;
     RECT  81.312 34.067 85.08 34.933 ;
     RECT  26.016 34.411 59.736 35.029 ;
     RECT  10.656 34.603 25.032 35.171 ;
     RECT  61.8 34.357 63.096 35.171 ;
     RECT  66.192 34.411 73.608 35.219 ;
     RECT  86.88 34.259 105.312 35.269 ;
     RECT  26.016 35.029 60.264 35.363 ;
     RECT  15.648 35.171 25.032 35.381 ;
     RECT  26.016 35.363 42.36 35.381 ;
     RECT  43.68 35.363 60.264 35.435 ;
     RECT  61.8 35.171 62.376 35.509 ;
     RECT  61.344 35.509 62.376 35.637 ;
     RECT  65.184 34.693 65.208 35.755 ;
     RECT  74.592 34.933 85.08 35.797 ;
     RECT  86.112 35.269 105.312 35.797 ;
     RECT  69.072 35.219 73.608 35.957 ;
     RECT  74.592 35.797 105.312 35.957 ;
     RECT  6.048 34.603 8.112 35.987 ;
     RECT  10.656 35.171 14.28 35.987 ;
     RECT  61.296 35.637 62.376 35.987 ;
     RECT  69.072 35.957 105.312 36.037 ;
     RECT  61.296 35.987 62.328 36.131 ;
     RECT  10.8 35.987 14.28 36.229 ;
     RECT  69.072 36.037 105.432 36.267 ;
     RECT  66.192 35.219 67.992 36.275 ;
     RECT  67.2 36.275 67.992 36.277 ;
     RECT  67.2 36.277 68.232 36.331 ;
     RECT  66.192 36.275 66.216 36.373 ;
     RECT  15.648 35.381 42.36 36.469 ;
     RECT  6.048 35.987 6.696 36.515 ;
     RECT  69.504 36.267 105.432 36.515 ;
     RECT  87.168 36.515 105.432 36.563 ;
     RECT  10.8 36.229 14.328 36.659 ;
     RECT  15.648 36.469 42.456 36.659 ;
     RECT  67.2 36.331 67.8 36.947 ;
     RECT  2.4 34.835 4.344 36.997 ;
     RECT  61.344 36.131 62.328 37.045 ;
     RECT  43.68 35.435 59.736 37.093 ;
     RECT  65.904 36.373 66.216 37.093 ;
     RECT  10.8 36.659 14.28 37.139 ;
     RECT  43.68 37.093 60.12 37.141 ;
     RECT  61.344 37.045 62.424 37.141 ;
     RECT  43.68 37.141 62.424 37.227 ;
     RECT  37.392 36.659 42.456 37.237 ;
     RECT  43.68 37.227 59.784 37.237 ;
     RECT  10.8 37.139 11.4 37.333 ;
     RECT  65.376 37.093 66.216 37.333 ;
     RECT  69.504 36.515 83.712 37.355 ;
     RECT  10.704 37.333 11.4 37.419 ;
     RECT  15.648 36.659 36.408 37.547 ;
     RECT  61.008 37.227 62.424 37.557 ;
     RECT  63.552 35.317 63.912 37.557 ;
     RECT  87.168 36.563 96.696 37.557 ;
     RECT  97.68 36.563 105.432 37.557 ;
     RECT  84.96 36.515 86.136 37.573 ;
     RECT  87.168 37.557 105.432 37.573 ;
     RECT  2.4 36.997 5.688 37.611 ;
     RECT  37.392 37.237 59.784 37.611 ;
     RECT  61.008 37.557 63.912 37.619 ;
     RECT  69.504 37.355 69.576 37.619 ;
     RECT  70.752 37.355 83.712 37.621 ;
     RECT  84.96 37.573 105.432 37.621 ;
     RECT  15.648 37.547 26.136 37.675 ;
     RECT  70.752 37.621 105.432 37.675 ;
     RECT  27.36 37.547 36.408 37.931 ;
     RECT  6.672 36.515 6.696 38.005 ;
     RECT  7.8 35.987 8.112 38.005 ;
     RECT  67.2 36.947 67.608 38.005 ;
     RECT  5.664 37.611 5.688 38.059 ;
     RECT  9.648 36.805 9.672 38.059 ;
     RECT  27.504 37.931 36.408 38.197 ;
     RECT  37.392 37.611 42.456 38.197 ;
     RECT  63.552 37.619 63.912 38.197 ;
     RECT  65.088 37.333 66.216 38.197 ;
     RECT  61.008 37.619 62.424 38.245 ;
     RECT  67.2 38.005 67.656 38.389 ;
     RECT  43.584 37.611 59.784 38.437 ;
     RECT  60.864 38.245 62.424 38.437 ;
     RECT  67.2 38.389 67.8 38.517 ;
     RECT  27.504 38.197 42.456 38.677 ;
     RECT  84.96 37.675 105.432 38.699 ;
     RECT  15.648 37.675 26.04 38.709 ;
     RECT  10.8 37.419 11.4 38.725 ;
     RECT  27.504 38.677 42.504 38.725 ;
     RECT  43.584 38.437 62.424 38.725 ;
     RECT  15.648 38.709 26.28 38.771 ;
     RECT  67.2 38.517 68.136 38.773 ;
     RECT  2.4 37.611 4.296 38.819 ;
     RECT  69.504 37.619 69.528 38.901 ;
     RECT  13.2 37.139 14.28 39.013 ;
     RECT  10.752 38.725 11.4 39.029 ;
     RECT  10.752 39.029 11.448 39.083 ;
     RECT  13.2 39.013 14.52 39.203 ;
     RECT  63.552 38.197 66.216 39.205 ;
     RECT  11.424 39.083 11.448 39.251 ;
     RECT  27.504 38.725 62.424 39.285 ;
     RECT  63.504 39.205 66.216 39.285 ;
     RECT  6.672 38.005 8.112 39.301 ;
     RECT  9.12 38.773 9.144 39.301 ;
     RECT  27.504 39.285 66.216 39.403 ;
     RECT  69.504 38.901 69.576 39.477 ;
     RECT  70.752 37.675 83.712 39.477 ;
     RECT  70.704 39.477 83.712 39.491 ;
     RECT  70.704 39.491 79.32 39.539 ;
     RECT  6.336 39.301 9.144 39.827 ;
     RECT  70.752 39.539 79.32 39.851 ;
     RECT  85.2 38.699 105.432 39.861 ;
     RECT  15.744 38.771 26.04 39.923 ;
     RECT  69.36 39.477 69.576 39.923 ;
     RECT  80.304 39.491 83.712 39.925 ;
     RECT  85.2 39.861 105.576 39.925 ;
     RECT  27.504 39.403 64.824 39.971 ;
     RECT  67.2 38.773 68.328 39.973 ;
     RECT  69.36 39.923 69.528 39.973 ;
     RECT  15.84 39.923 26.04 40.019 ;
     RECT  84.96 39.925 105.576 40.019 ;
     RECT  27.504 39.971 64.104 40.043 ;
     RECT  67.2 39.973 69.528 40.043 ;
     RECT  70.752 39.851 70.776 40.043 ;
     RECT  75.264 39.851 79.32 40.043 ;
     RECT  84.96 40.019 105.312 40.107 ;
     RECT  80.304 39.925 83.88 40.117 ;
     RECT  66.144 39.403 66.216 40.163 ;
     RECT  13.2 39.203 14.472 40.307 ;
     RECT  80.304 40.117 84.072 40.363 ;
     RECT  2.4 38.819 4.248 40.499 ;
     RECT  9.12 39.827 9.144 40.499 ;
     RECT  72.6 39.851 73.608 40.499 ;
     RECT  75.504 40.043 79.32 40.499 ;
     RECT  66.144 40.163 66.168 40.549 ;
     RECT  75.792 40.499 79.32 40.555 ;
     RECT  85.2 40.107 105.312 40.555 ;
     RECT  69.504 40.043 69.528 40.619 ;
     RECT  66.096 40.549 66.168 40.741 ;
     RECT  76.128 40.555 79.32 40.757 ;
     RECT  80.304 40.363 83.832 40.757 ;
     RECT  15.936 40.019 26.04 40.885 ;
     RECT  27.504 40.043 62.952 40.885 ;
     RECT  67.2 40.043 68.28 40.979 ;
     RECT  86.88 40.555 105.312 40.979 ;
     RECT  76.128 40.757 83.832 41.027 ;
     RECT  87.264 40.979 105.312 41.075 ;
     RECT  64.08 40.043 64.104 41.131 ;
     RECT  9.6 41.141 9.624 41.173 ;
     RECT  65.424 40.741 66.168 41.269 ;
     RECT  67.2 40.979 68.088 41.269 ;
     RECT  9.6 41.173 10.008 41.317 ;
     RECT  9.6 41.317 10.824 41.397 ;
     RECT  9.6 41.397 10.872 41.459 ;
     RECT  74.16 41.221 74.424 41.507 ;
     RECT  64.704 41.269 68.088 41.643 ;
     RECT  76.128 41.027 80.52 41.651 ;
     RECT  96.144 41.075 105.312 41.651 ;
     RECT  15.936 40.885 62.952 41.749 ;
     RECT  70.704 41.413 70.728 41.893 ;
     RECT  81.504 41.027 83.832 41.893 ;
     RECT  85.2 40.555 85.704 41.893 ;
     RECT  81.504 41.893 85.704 41.989 ;
     RECT  81.504 41.989 86.04 42.035 ;
     RECT  15.936 41.749 63.048 42.085 ;
     RECT  72.6 40.499 72.912 42.085 ;
     RECT  74.16 41.507 74.184 42.085 ;
     RECT  6.336 39.827 8.112 42.133 ;
     RECT  9.6 41.459 10.008 42.133 ;
     RECT  98.88 41.651 105.312 42.133 ;
     RECT  15.744 42.085 63.048 42.155 ;
     RECT  81.504 42.035 84.792 42.219 ;
     RECT  13.2 40.307 14.28 42.227 ;
     RECT  72.6 42.085 74.184 42.227 ;
     RECT  64.944 41.643 68.088 42.277 ;
     RECT  85.968 42.035 86.04 42.325 ;
     RECT  6.336 42.133 10.008 42.411 ;
     RECT  76.224 41.651 80.52 42.421 ;
     RECT  81.504 42.219 84.456 42.421 ;
     RECT  76.224 42.421 84.456 42.475 ;
     RECT  15.936 42.155 63.048 42.515 ;
     RECT  11.088 41.525 11.112 42.549 ;
     RECT  10.608 42.549 11.112 42.611 ;
     RECT  87.264 41.075 95.016 42.661 ;
     RECT  96.144 41.651 97.752 42.661 ;
     RECT  13.2 42.227 14.232 42.709 ;
     RECT  5.088 42.661 5.112 42.731 ;
     RECT  64.944 42.277 68.184 42.731 ;
     RECT  87.264 42.661 97.752 42.731 ;
     RECT  81.792 42.475 84.456 42.755 ;
     RECT  49.44 42.515 63.048 42.757 ;
     RECT  85.968 42.325 86.184 42.757 ;
     RECT  87.264 42.731 95.016 42.757 ;
     RECT  2.4 40.499 4.104 42.803 ;
     RECT  15.936 42.515 48.456 42.923 ;
     RECT  49.44 42.757 63.576 42.997 ;
     RECT  64.944 42.731 65.448 42.997 ;
     RECT  70.704 41.893 71.304 42.997 ;
     RECT  72.6 42.227 73.368 42.997 ;
     RECT  76.224 42.475 80.568 42.997 ;
     RECT  85.968 42.757 95.016 43.093 ;
     RECT  70.704 42.997 73.368 43.141 ;
     RECT  69.984 43.141 73.368 43.285 ;
     RECT  96.144 42.731 97.752 43.285 ;
     RECT  98.88 42.133 105.432 43.285 ;
     RECT  12.624 42.709 14.232 43.379 ;
     RECT  96.144 43.285 105.432 43.379 ;
     RECT  69.984 43.285 73.896 43.475 ;
     RECT  37.488 42.923 48.456 43.499 ;
     RECT  81.792 42.755 83.976 43.499 ;
     RECT  15.936 42.923 36.504 43.509 ;
     RECT  39.12 43.499 48.456 43.509 ;
     RECT  49.44 42.997 65.448 43.509 ;
     RECT  85.92 43.093 95.016 43.621 ;
     RECT  11.088 42.611 11.112 43.669 ;
     RECT  15.888 43.509 36.504 43.669 ;
     RECT  75.456 42.997 80.568 43.691 ;
     RECT  85.056 43.621 95.016 43.691 ;
     RECT  39.12 43.509 65.448 43.755 ;
     RECT  15.456 43.669 36.504 43.829 ;
     RECT  80.496 43.691 80.568 43.829 ;
     RECT  86.016 43.691 95.016 43.883 ;
     RECT  72.6 43.475 73.896 43.893 ;
     RECT  87.168 43.883 95.016 43.893 ;
     RECT  96.144 43.379 96.312 43.947 ;
     RECT  72.6 43.893 74.28 43.955 ;
     RECT  75.456 43.691 79.272 43.955 ;
     RECT  87.168 43.893 95.16 43.955 ;
     RECT  6.336 42.411 9.624 44.005 ;
     RECT  15.312 43.829 36.504 44.053 ;
     RECT  10.752 43.669 11.112 44.085 ;
     RECT  12.624 43.379 13.656 44.085 ;
     RECT  15.216 44.053 36.504 44.085 ;
     RECT  69.984 43.475 71.304 44.099 ;
     RECT  10.752 44.085 13.656 44.139 ;
     RECT  70.32 44.099 71.304 44.339 ;
     RECT  2.4 42.803 3.672 44.341 ;
     RECT  10.944 44.139 13.656 44.341 ;
     RECT  14.736 44.085 36.504 44.341 ;
     RECT  37.488 43.499 38.136 44.341 ;
     RECT  97.584 43.379 105.312 44.389 ;
     RECT  10.944 44.341 38.136 44.395 ;
     RECT  72.6 43.955 73.704 44.395 ;
     RECT  6.288 44.005 9.624 44.405 ;
     RECT  49.44 43.755 65.448 44.435 ;
     RECT  77.712 43.955 79.224 44.459 ;
     RECT  6.24 44.405 9.624 44.483 ;
     RECT  75.456 43.955 76.392 44.483 ;
     RECT  71.28 44.339 71.304 44.531 ;
     RECT  49.44 44.435 62.664 44.627 ;
     RECT  67.104 42.731 68.184 44.627 ;
     RECT  77.712 44.459 78.936 44.771 ;
     RECT  80.496 43.829 80.904 44.789 ;
     RECT  81.888 43.499 83.976 44.789 ;
     RECT  86.016 43.883 86.136 44.869 ;
     RECT  87.168 43.955 95.016 44.869 ;
     RECT  6.24 44.483 9 44.917 ;
     RECT  80.496 44.789 83.976 44.917 ;
     RECT  5.376 44.917 9 44.965 ;
     RECT  39.12 43.755 48.456 44.965 ;
     RECT  49.44 44.627 58.68 44.965 ;
     RECT  80.352 44.917 83.976 45.013 ;
     RECT  97.584 44.389 105.432 45.035 ;
     RECT  5.232 44.965 9 45.045 ;
     RECT  80.352 45.013 84.168 45.059 ;
     RECT  13.2 44.395 38.136 45.099 ;
     RECT  2.4 44.341 4.056 45.205 ;
     RECT  5.136 45.045 9 45.205 ;
     RECT  10.944 44.395 11.976 45.227 ;
     RECT  2.4 45.205 9 45.395 ;
     RECT  38.016 45.099 38.136 45.429 ;
     RECT  39.12 44.965 58.68 45.429 ;
     RECT  5.232 45.395 9 45.541 ;
     RECT  10.944 45.227 11.256 45.541 ;
     RECT  67.104 44.627 67.512 45.541 ;
     RECT  86.016 44.869 95.016 45.541 ;
     RECT  2.4 45.395 4.2 45.547 ;
     RECT  64.128 44.435 65.448 45.557 ;
     RECT  38.016 45.429 58.68 45.621 ;
     RECT  59.712 44.627 62.664 45.621 ;
     RECT  70.512 45.541 70.536 45.621 ;
     RECT  64.128 45.557 65.496 45.635 ;
     RECT  96.144 43.947 96.168 45.635 ;
     RECT  69.552 45.621 70.536 45.683 ;
     RECT  66.72 45.541 67.512 45.685 ;
     RECT  80.496 45.059 84.168 45.685 ;
     RECT  97.584 45.035 103.032 45.685 ;
     RECT  85.632 45.541 95.016 45.781 ;
     RECT  13.2 45.099 37.032 45.803 ;
     RECT  80.496 45.685 84.504 45.867 ;
     RECT  66.72 45.685 68.424 45.875 ;
     RECT  38.016 45.621 62.664 45.973 ;
     RECT  85.536 45.781 95.016 45.973 ;
     RECT  75.456 44.483 76.248 46.021 ;
     RECT  97.488 45.685 103.032 46.069 ;
     RECT  104.112 45.035 105.432 46.069 ;
     RECT  96.288 46.117 96.312 46.187 ;
     RECT  38.016 45.973 62.904 46.197 ;
     RECT  84.912 45.973 95.016 46.211 ;
     RECT  5.232 45.541 11.256 46.213 ;
     RECT  77.808 44.771 78.936 46.213 ;
     RECT  97.488 46.069 105.432 46.261 ;
     RECT  72.6 44.395 73.272 46.307 ;
     RECT  74.592 46.021 76.248 46.405 ;
     RECT  72.6 46.307 72.912 46.453 ;
     RECT  37.728 46.197 62.904 46.507 ;
     RECT  74.4 46.405 76.248 46.507 ;
     RECT  5.232 46.213 11.4 46.581 ;
     RECT  72.384 46.453 72.912 46.691 ;
     RECT  3.84 46.645 3.864 46.693 ;
     RECT  4.896 46.581 11.4 46.693 ;
     RECT  84.912 46.211 94.776 46.699 ;
     RECT  53.328 46.507 62.904 46.741 ;
     RECT  64.176 45.635 65.496 46.741 ;
     RECT  13.2 45.803 36.504 46.773 ;
     RECT  77.76 46.213 78.936 46.787 ;
     RECT  80.496 45.867 83.712 46.787 ;
     RECT  13.2 46.773 36.744 46.883 ;
     RECT  37.728 46.507 52.008 46.901 ;
     RECT  74.592 46.507 76.248 46.901 ;
     RECT  77.76 46.787 78.312 46.901 ;
     RECT  53.328 46.741 65.496 46.979 ;
     RECT  74.592 46.901 78.312 46.979 ;
     RECT  63.84 46.979 65.496 46.981 ;
     RECT  66.72 45.875 67.512 46.981 ;
     RECT  13.2 46.883 36.36 47.027 ;
     RECT  53.328 46.979 62.664 47.075 ;
     RECT  3.84 46.693 11.4 47.077 ;
     RECT  63.84 46.981 67.512 47.083 ;
     RECT  74.592 46.979 76.248 47.083 ;
     RECT  3.84 47.077 11.832 47.125 ;
     RECT  66.72 47.083 67.512 47.315 ;
     RECT  96.624 46.261 105.432 47.459 ;
     RECT  72.6 46.691 72.912 47.653 ;
     RECT  72.6 47.653 73.032 47.749 ;
     RECT  70.512 45.683 70.536 47.845 ;
     RECT  85.488 46.699 94.776 47.891 ;
     RECT  68.976 47.093 69 47.939 ;
     RECT  72.6 47.749 73.08 47.941 ;
     RECT  3.84 47.125 12.024 47.989 ;
     RECT  13.2 47.027 33.816 47.989 ;
     RECT  70.128 47.845 70.536 47.989 ;
     RECT  72.6 47.941 73.128 48.117 ;
     RECT  53.328 47.075 62.424 48.133 ;
     RECT  63.84 47.083 65.496 48.181 ;
     RECT  72.6 48.117 73.56 48.245 ;
     RECT  53.328 48.133 62.472 48.309 ;
     RECT  63.84 48.181 65.592 48.309 ;
     RECT  34.8 47.027 36.36 48.325 ;
     RECT  37.44 46.901 52.008 48.325 ;
     RECT  70.128 47.989 70.728 48.373 ;
     RECT  81.36 46.787 83.712 48.373 ;
     RECT  85.488 47.891 90.072 48.373 ;
     RECT  72.6 48.245 74.088 48.419 ;
     RECT  2.4 45.547 2.712 48.421 ;
     RECT  3.84 47.989 33.816 48.421 ;
     RECT  34.8 48.325 52.008 48.421 ;
     RECT  77.712 46.979 78.312 48.421 ;
     RECT  81.36 48.373 90.072 48.427 ;
     RECT  95.952 48.229 95.976 48.427 ;
     RECT  75.36 47.083 76.248 48.437 ;
     RECT  77.712 48.421 78.984 48.437 ;
     RECT  97.104 47.459 105.432 48.467 ;
     RECT  75.36 48.437 78.984 48.515 ;
     RECT  81.36 48.427 83.712 48.515 ;
     RECT  91.056 47.891 94.776 48.515 ;
     RECT  53.328 48.309 65.592 48.565 ;
     RECT  69.36 48.373 70.728 48.619 ;
     RECT  2.4 48.421 52.008 48.629 ;
     RECT  53.328 48.565 66.12 48.629 ;
     RECT  67.104 47.315 67.512 48.629 ;
     RECT  97.104 48.467 102.264 48.757 ;
     RECT  72.6 48.419 73.896 48.805 ;
     RECT  69.408 48.619 70.728 48.821 ;
     RECT  91.152 48.515 94.776 48.949 ;
     RECT  69.408 48.821 71.256 48.995 ;
     RECT  2.4 48.629 67.512 49.189 ;
     RECT  77.472 48.515 78.984 49.195 ;
     RECT  72.384 48.805 73.896 49.259 ;
     RECT  75.36 48.515 76.248 49.259 ;
     RECT  91.152 48.949 95.208 49.259 ;
     RECT  69.408 48.995 69.432 49.283 ;
     RECT  72.384 49.259 73.752 49.323 ;
     RECT  77.76 49.195 78.984 49.333 ;
     RECT  72.384 49.323 73.56 49.477 ;
     RECT  83.28 48.515 83.712 49.525 ;
     RECT  84.912 48.427 85.56 49.525 ;
     RECT  86.64 48.427 90.072 49.525 ;
     RECT  91.152 49.259 92.088 49.525 ;
     RECT  93.264 49.259 95.208 49.573 ;
     RECT  96.288 48.757 102.264 49.573 ;
     RECT  72.336 49.477 73.56 49.579 ;
     RECT  72.336 49.579 72.912 49.619 ;
     RECT  83.184 49.525 85.56 49.619 ;
     RECT  93.264 49.573 102.264 49.619 ;
     RECT  96.912 49.619 102.264 49.765 ;
     RECT  103.44 48.467 105.432 49.765 ;
     RECT  86.64 49.525 92.088 49.781 ;
     RECT  93.264 49.619 95.784 49.963 ;
     RECT  2.4 49.189 67.8 49.973 ;
     RECT  77.76 49.333 79.56 49.973 ;
     RECT  83.184 49.619 85.32 49.973 ;
     RECT  2.4 49.973 68.424 50.037 ;
     RECT  83.136 49.973 85.32 50.051 ;
     RECT  75.408 49.259 76.248 50.101 ;
     RECT  83.184 50.051 85.32 50.155 ;
     RECT  96.912 49.765 105.432 50.195 ;
     RECT  93.312 49.963 95.784 50.243 ;
     RECT  2.4 50.037 69 50.293 ;
     RECT  70.464 48.995 70.536 50.293 ;
     RECT  75.408 50.101 76.296 50.293 ;
     RECT  77.76 49.973 80.136 50.293 ;
     RECT  81.36 48.515 82.152 50.339 ;
     RECT  93.312 50.243 95.736 50.347 ;
     RECT  97.104 50.195 102.744 50.387 ;
     RECT  83.28 50.155 85.32 50.539 ;
     RECT  75.408 50.293 80.136 50.579 ;
     RECT  81.36 50.339 82.104 50.579 ;
     RECT  86.592 49.781 92.088 50.613 ;
     RECT  83.28 50.539 84.936 50.667 ;
     RECT  86.496 50.613 92.088 50.675 ;
     RECT  86.592 50.675 92.088 50.677 ;
     RECT  2.4 50.293 70.536 50.731 ;
     RECT  83.28 50.667 84.216 50.731 ;
     RECT  86.592 50.677 92.328 50.731 ;
     RECT  97.488 50.387 102.744 50.731 ;
     RECT  97.488 50.731 102.6 50.771 ;
     RECT  2.4 50.731 63 50.805 ;
     RECT  72.6 49.619 72.912 50.805 ;
     RECT  81.456 50.579 82.104 50.867 ;
     RECT  80.112 50.579 80.136 50.965 ;
     RECT  80.112 50.965 80.472 51.107 ;
     RECT  64.416 50.731 70.536 51.179 ;
     RECT  86.64 50.731 92.328 51.253 ;
     RECT  93.312 50.347 95.208 51.253 ;
     RECT  86.64 51.253 95.208 51.307 ;
     RECT  83.28 50.731 84.168 51.317 ;
     RECT  72.6 50.805 73.56 51.347 ;
     RECT  83.088 51.317 84.168 51.347 ;
     RECT  97.488 50.771 100.392 51.347 ;
     RECT  80.448 51.107 80.472 51.371 ;
     RECT  103.776 50.195 105.432 51.381 ;
     RECT  103.728 51.381 105.432 51.395 ;
     RECT  93.312 51.307 95.208 51.541 ;
     RECT  86.64 51.307 92.136 51.587 ;
     RECT  75.408 50.579 78.6 51.635 ;
     RECT  64.416 51.179 67.848 51.731 ;
     RECT  97.776 51.347 97.8 51.755 ;
     RECT  68.976 51.179 70.536 51.765 ;
     RECT  96.624 51.701 96.648 51.779 ;
     RECT  75.408 51.635 76.296 51.781 ;
     RECT  2.304 50.805 63 51.829 ;
     RECT  86.64 51.587 89.208 51.877 ;
     RECT  98.784 51.347 100.392 51.893 ;
     RECT  68.976 51.765 71.352 51.925 ;
     RECT  72.6 51.347 73.464 51.925 ;
     RECT  101.472 50.771 102.6 52.021 ;
     RECT  86.112 51.877 89.208 52.069 ;
     RECT  93.312 51.541 95.64 52.139 ;
     RECT  86.016 52.069 89.208 52.149 ;
     RECT  101.424 52.021 102.6 52.149 ;
     RECT  103.728 51.395 105.312 52.149 ;
     RECT  101.424 52.149 105.312 52.211 ;
     RECT  80.352 52.213 80.376 52.341 ;
     RECT  81.456 50.867 81.96 52.341 ;
     RECT  83.088 51.347 83.712 52.341 ;
     RECT  104.88 52.211 105.312 52.405 ;
     RECT  90.624 51.587 92.136 52.459 ;
     RECT  104.88 52.405 105.48 52.459 ;
     RECT  2.304 51.829 63.24 52.469 ;
     RECT  64.416 51.731 65.544 52.469 ;
     RECT  92.112 52.459 92.136 52.499 ;
     RECT  93.312 52.139 95.016 52.499 ;
     RECT  103.728 52.211 103.848 52.499 ;
     RECT  68.976 51.925 73.464 52.547 ;
     RECT  79.824 52.341 80.376 52.547 ;
     RECT  2.304 52.469 65.544 52.549 ;
     RECT  66.528 51.731 67.848 52.549 ;
     RECT  68.976 52.547 69.528 52.549 ;
     RECT  75.36 51.781 76.296 52.597 ;
     RECT  81.456 52.341 83.712 52.597 ;
     RECT  85.488 52.149 89.208 52.597 ;
     RECT  79.824 52.547 79.848 52.651 ;
     RECT  66.528 52.549 69.528 52.715 ;
     RECT  98.784 51.893 100.44 52.739 ;
     RECT  66.528 52.715 67.608 52.787 ;
     RECT  98.784 52.739 100.104 52.843 ;
     RECT  2.064 52.549 65.544 52.853 ;
     RECT  101.424 52.211 102.6 52.917 ;
     RECT  2.064 52.853 65.592 52.931 ;
     RECT  77.472 51.635 78.6 52.933 ;
     RECT  85.248 52.597 89.208 52.933 ;
     RECT  69.504 52.715 69.528 52.979 ;
     RECT  75.168 52.597 76.296 52.981 ;
     RECT  85.2 52.933 89.208 52.981 ;
     RECT  90.624 52.459 90.984 52.981 ;
     RECT  2.064 52.931 65.544 53.035 ;
     RECT  2.064 53.035 65.112 53.075 ;
     RECT  85.2 52.981 90.984 53.075 ;
     RECT  101.136 52.917 102.6 53.075 ;
     RECT  85.2 53.075 90.072 53.077 ;
     RECT  101.136 53.075 102.12 53.123 ;
     RECT  2.064 53.075 62.232 53.163 ;
     RECT  81.36 52.597 83.712 53.163 ;
     RECT  84.96 53.077 90.072 53.163 ;
     RECT  75.168 52.981 76.488 53.173 ;
     RECT  63.264 53.075 65.112 53.219 ;
     RECT  70.512 52.547 73.464 53.227 ;
     RECT  93.312 52.499 94.68 53.237 ;
     RECT  63.648 53.219 65.112 53.267 ;
     RECT  70.656 53.227 73.464 53.291 ;
     RECT  63.648 53.267 64.056 53.355 ;
     RECT  98.784 52.843 99.912 53.355 ;
     RECT  101.136 53.123 102.072 53.363 ;
     RECT  74.688 53.173 76.488 53.365 ;
     RECT  77.472 52.933 79.128 53.365 ;
     RECT  82.608 53.163 83.712 53.365 ;
     RECT  65.04 53.267 65.112 53.411 ;
     RECT  96 52.405 96.024 53.413 ;
     RECT  85.488 53.163 90.072 53.419 ;
     RECT  74.688 53.365 79.128 53.459 ;
     RECT  2.064 53.163 62.184 53.483 ;
     RECT  96 53.413 96.888 53.483 ;
     RECT  65.088 53.411 65.112 53.507 ;
     RECT  98.448 53.429 98.472 53.507 ;
     RECT  81.36 53.163 81.48 53.509 ;
     RECT  85.584 53.419 89.112 53.547 ;
     RECT  91.2 53.461 91.224 53.547 ;
     RECT  92.88 53.237 94.68 53.547 ;
     RECT  88.368 53.547 89.112 53.555 ;
     RECT  93.36 53.547 94.512 53.555 ;
     RECT  63.84 53.355 64.056 53.603 ;
     RECT  70.656 53.291 70.68 53.603 ;
     RECT  71.664 53.291 73.464 53.603 ;
     RECT  74.688 53.459 76.296 53.603 ;
     RECT  82.608 53.365 84.408 53.603 ;
     RECT  86.016 53.547 87.24 53.603 ;
     RECT  96 53.483 96.024 53.603 ;
     RECT  103.728 52.499 103.752 53.603 ;
     RECT  80.928 53.509 81.48 53.611 ;
     RECT  86.064 53.603 87.24 53.651 ;
     RECT  103.152 53.605 103.176 53.675 ;
     RECT  104.88 52.459 105.312 53.675 ;
     RECT  86.064 53.651 86.616 53.699 ;
     RECT  88.416 53.555 89.112 53.739 ;
     RECT  77.472 53.459 79.128 53.747 ;
     RECT  67.2 52.787 67.512 53.753 ;
     RECT  72.6 53.603 72.912 53.753 ;
     RECT  88.8 53.739 89.112 53.753 ;
     RECT  94.2 53.555 94.512 53.753 ;
     RECT  99.6 53.355 99.912 53.753 ;
     RECT  105 53.675 105.312 53.753 ;
     RECT  63.84 53.603 63.864 53.795 ;
     RECT  75.216 53.603 76.056 53.795 ;
     RECT  78 53.747 79.128 53.795 ;
     RECT  86.592 53.699 86.616 53.795 ;
     RECT  101.136 53.363 101.16 53.795 ;
     RECT  75.216 53.795 75.24 53.803 ;
     RECT  79.104 53.795 79.128 53.803 ;
     RECT  81.456 53.611 81.48 53.803 ;
     RECT  83.4 53.603 84.408 53.803 ;
     RECT  67.2 53.753 67.32 54.023 ;
     RECT  72.6 53.753 72.72 54.023 ;
     RECT  78 53.795 78.12 54.023 ;
     RECT  83.4 53.803 83.52 54.023 ;
     RECT  88.8 53.753 88.92 54.023 ;
     RECT  94.2 53.753 94.32 54.023 ;
     RECT  99.6 53.753 99.72 54.023 ;
     RECT  105 53.753 105.12 54.023 ;
     RECT  50.544 53.483 62.184 54.421 ;
     RECT  50.544 54.421 62.472 54.469 ;
     RECT  50.544 54.469 62.568 54.709 ;
     RECT  2.064 53.483 49.512 55.285 ;
     RECT  50.544 54.709 62.664 55.285 ;
     RECT  2.064 55.285 62.664 56.144 ;
    LAYER M6 ;
     RECT  2.677 56 2.867 56.032 ;
     RECT  2.917 52.992 3.203 53.024 ;
     RECT  2.16 25.616 3.301 26.288 ;
     RECT  2.293 50.816 3.301 50.848 ;
     RECT  2.16 4.016 3.397 4.688 ;
     RECT  2.16 14.816 3.397 15.488 ;
     RECT  3.397 14.656 3.445 15.488 ;
     RECT  3.445 14.656 3.541 15.776 ;
     RECT  2.16 36.416 3.733 37.088 ;
     RECT  3.541 13.824 3.781 15.776 ;
     RECT  2.821 17.344 3.781 17.376 ;
     RECT  3.397 4.016 3.877 5.216 ;
     RECT  3.877 4.016 3.925 5.856 ;
     RECT  3.637 11.648 3.925 11.68 ;
     RECT  3.781 13.824 3.925 17.376 ;
     RECT  3.301 50.496 3.925 51.872 ;
     RECT  3.157 22.208 4.019 22.24 ;
     RECT  2.869 23.744 4.019 23.776 ;
     RECT  3.925 49.728 4.019 51.872 ;
     RECT  3.637 45.504 4.021 45.536 ;
     RECT  2.869 7.36 4.357 7.392 ;
     RECT  3.925 10.944 4.501 11.68 ;
     RECT  2.16 47.216 4.501 47.888 ;
     RECT  4.019 49.728 4.501 51.68 ;
     RECT  2.965 30.976 4.595 31.008 ;
     RECT  3.301 25.408 4.883 26.288 ;
     RECT  4.021 45.056 4.885 45.536 ;
     RECT  4.501 47.216 4.885 51.68 ;
     RECT  4.501 10.752 4.981 11.872 ;
     RECT  3.925 13.312 4.981 17.376 ;
     RECT  3.829 33.728 4.981 33.76 ;
     RECT  4.981 10.752 5.077 17.376 ;
     RECT  3.925 3.072 5.173 5.856 ;
     RECT  4.981 33.728 5.509 34.336 ;
     RECT  5.173 3.072 5.653 5.984 ;
     RECT  4.357 7.36 5.653 7.584 ;
     RECT  3.733 36.416 5.653 37.6 ;
     RECT  4.069 39.04 5.653 39.072 ;
     RECT  4.885 45.056 5.653 51.68 ;
     RECT  5.509 33.536 6.037 34.336 ;
     RECT  5.653 3.072 6.229 7.584 ;
     RECT  5.077 10.176 6.229 17.376 ;
     RECT  3.397 20.48 6.229 20.512 ;
     RECT  6.037 33.536 6.229 34.464 ;
     RECT  5.653 45.056 6.229 51.808 ;
     RECT  5.077 42.688 6.325 42.72 ;
     RECT  6.229 44.416 6.325 52.064 ;
     RECT  5.317 24.256 6.419 24.288 ;
     RECT  5.653 22.4 6.805 22.432 ;
     RECT  3.493 27.84 6.805 27.872 ;
     RECT  6.325 42.688 6.805 52.064 ;
     RECT  6.229 32.256 6.853 34.464 ;
     RECT  6.229 19.904 6.899 20.512 ;
     RECT  6.853 32.256 7.285 34.784 ;
     RECT  6.229 3.072 7.525 7.968 ;
     RECT  6.229 9.28 7.525 17.376 ;
     RECT  7.285 32.128 7.619 34.784 ;
     RECT  7.525 3.072 7.669 17.376 ;
     RECT  6.805 22.336 7.669 22.432 ;
     RECT  6.997 23.744 7.669 23.968 ;
     RECT  6.805 27.84 7.669 28.512 ;
     RECT  6.757 41.152 7.669 41.184 ;
     RECT  6.805 42.688 7.669 53.088 ;
     RECT  7.669 3.072 7.715 17.824 ;
     RECT  8.197 55.936 8.243 55.968 ;
     RECT  7.669 41.152 8.387 53.088 ;
     RECT  8.387 52.992 8.437 53.088 ;
     RECT  7.669 27.84 9.059 29.792 ;
     RECT  9.059 28.224 9.061 29.792 ;
     RECT  7.619 32.128 9.061 34.592 ;
     RECT  7.715 3.2 9.155 17.824 ;
     RECT  8.437 52.992 9.251 53.6 ;
     RECT  8.387 41.152 9.635 50.72 ;
     RECT  9.251 53.568 9.635 53.6 ;
     RECT  6.899 19.904 9.637 19.936 ;
     RECT  9.061 0.128 10.213 0.16 ;
     RECT  9.635 41.344 10.213 50.72 ;
     RECT  9.155 10.176 10.307 17.824 ;
     RECT  7.669 22.336 10.403 23.968 ;
     RECT  10.307 10.176 10.547 15.776 ;
     RECT  9.155 3.2 10.549 7.776 ;
     RECT  9.061 28.224 10.645 34.592 ;
     RECT  10.549 3.2 10.693 7.904 ;
     RECT  10.403 22.4 10.789 23.968 ;
     RECT  10.307 17.792 11.269 17.824 ;
     RECT  9.637 19.328 11.269 19.936 ;
     RECT  10.547 10.176 11.365 15.648 ;
     RECT  10.693 3.2 11.413 8.16 ;
     RECT  11.365 9.472 11.413 15.648 ;
     RECT  5.653 36.416 11.413 39.072 ;
     RECT  10.789 22.4 11.605 24.16 ;
     RECT  11.269 17.792 11.701 19.936 ;
     RECT  11.413 3.2 11.845 15.648 ;
     RECT  11.701 17.792 11.845 20.576 ;
     RECT  11.845 3.2 12.275 20.576 ;
     RECT  10.645 28.224 12.275 34.976 ;
     RECT  10.213 0.128 12.517 0.224 ;
     RECT  12.275 10.88 12.517 20.576 ;
     RECT  11.605 22.4 12.517 24.288 ;
     RECT  12.275 3.2 12.563 9.504 ;
     RECT  10.213 41.344 12.565 51.936 ;
     RECT  11.365 53.44 12.565 53.472 ;
     RECT  12.565 41.344 12.899 53.472 ;
     RECT  12.899 51.328 13.045 53.472 ;
     RECT  12.517 10.88 13.093 24.288 ;
     RECT  4.883 25.616 13.093 26.288 ;
     RECT  12.275 28.224 13.093 30.496 ;
     RECT  13.093 10.88 13.139 26.288 ;
     RECT  13.139 10.88 13.573 20.576 ;
     RECT  13.139 22.4 13.619 26.288 ;
     RECT  13.093 28.096 13.621 30.496 ;
     RECT  12.275 32.576 13.813 34.976 ;
     RECT  11.413 36.416 13.813 39.2 ;
     RECT  13.045 51.328 13.859 54.432 ;
     RECT  12.563 3.2 14.197 8.608 ;
     RECT  13.573 10.112 14.197 20.576 ;
     RECT  14.197 3.2 14.773 20.576 ;
     RECT  13.619 22.464 14.773 26.288 ;
     RECT  13.621 27.904 14.773 30.496 ;
     RECT  14.773 3.2 14.867 20.64 ;
     RECT  11.365 1.792 15.925 1.824 ;
     RECT  14.867 3.2 15.925 5.536 ;
     RECT  14.773 22.464 15.925 30.496 ;
     RECT  14.867 13.568 16.019 20.64 ;
     RECT  14.867 6.848 16.405 11.936 ;
     RECT  16.019 13.568 16.405 15.648 ;
     RECT  13.859 51.84 16.453 54.432 ;
     RECT  15.925 22.464 16.501 30.88 ;
     RECT  12.899 41.344 16.501 50.016 ;
     RECT  16.453 51.328 16.501 54.432 ;
     RECT  15.925 1.792 16.645 5.536 ;
     RECT  16.405 6.848 16.645 15.648 ;
     RECT  16.501 22.464 16.789 30.944 ;
     RECT  16.019 16.96 17.315 20.64 ;
     RECT  16.645 1.792 17.699 15.648 ;
     RECT  16.789 22.4 17.893 30.944 ;
     RECT  13.813 32.576 17.893 39.2 ;
     RECT  17.893 22.4 18.133 39.2 ;
     RECT  18.133 22.4 18.229 39.264 ;
     RECT  16.501 41.344 18.229 54.432 ;
     RECT  17.315 16.96 18.515 19.68 ;
     RECT  17.699 1.792 18.997 11.936 ;
     RECT  17.699 13.312 18.997 15.648 ;
     RECT  8.243 55.94 19.333 55.964 ;
     RECT  18.229 22.4 19.427 54.432 ;
     RECT  18.997 1.792 19.909 15.648 ;
     RECT  18.515 16.96 19.909 19.552 ;
     RECT  19.427 22.528 20.051 54.432 ;
     RECT  19.909 1.792 20.579 19.552 ;
     RECT  20.579 19.2 20.581 19.552 ;
     RECT  20.051 44.416 20.821 54.432 ;
     RECT  19.333 55.808 20.821 55.964 ;
     RECT  20.581 19.2 21.107 20.128 ;
     RECT  20.051 22.528 21.109 43.104 ;
     RECT  21.109 21.696 21.637 43.104 ;
     RECT  20.821 44.416 21.637 55.964 ;
     RECT  21.637 21.696 24.467 55.964 ;
     RECT  20.579 1.792 24.469 17.824 ;
     RECT  21.107 19.52 24.563 20.128 ;
     RECT  24.563 20.096 25.139 20.128 ;
     RECT  24.467 21.824 25.187 55.964 ;
     RECT  12.517 0.128 25.669 0.288 ;
     RECT  24.469 1.792 26.483 17.952 ;
     RECT  25.187 23.04 27.491 55.964 ;
     RECT  26.725 20.928 28.501 21.344 ;
     RECT  26.483 1.792 29.269 17.824 ;
     RECT  28.501 20.928 29.269 21.536 ;
     RECT  29.077 19.584 29.797 19.616 ;
     RECT  29.269 20.928 29.797 21.728 ;
     RECT  29.797 19.584 29.843 21.728 ;
     RECT  27.491 23.168 30.275 55.964 ;
     RECT  29.269 1.792 31.091 17.888 ;
     RECT  29.843 19.84 31.379 21.728 ;
     RECT  31.379 20.928 31.669 21.728 ;
     RECT  31.091 1.792 32.051 17.696 ;
     RECT  31.669 20.928 32.101 22.56 ;
     RECT  30.275 23.936 32.101 55.964 ;
     RECT  32.101 20.928 33.251 55.964 ;
     RECT  32.051 10.88 33.397 17.696 ;
     RECT  33.397 10.816 33.973 17.696 ;
     RECT  33.251 20.928 34.693 22.56 ;
     RECT  33.251 24.064 34.693 55.964 ;
     RECT  33.973 10.816 35.219 18.912 ;
     RECT  32.051 1.792 35.221 9.376 ;
     RECT  35.219 10.816 35.221 17.568 ;
     RECT  34.693 20.928 35.315 55.964 ;
     RECT  35.315 20.928 36.323 42.4 ;
     RECT  36.323 24.256 36.805 42.4 ;
     RECT  35.315 43.712 36.805 55.964 ;
     RECT  35.221 1.792 37.139 17.568 ;
     RECT  36.323 20.928 37.189 22.88 ;
     RECT  37.189 20.544 37.235 22.88 ;
     RECT  35.219 18.88 38.243 18.912 ;
     RECT  37.235 20.544 38.243 21.984 ;
     RECT  36.805 24.256 38.531 55.964 ;
     RECT  38.243 20.928 38.629 21.984 ;
     RECT  37.139 1.792 39.925 17.376 ;
     RECT  38.629 20.928 39.973 23.072 ;
     RECT  39.973 19.968 40.115 23.072 ;
     RECT  25.669 0.128 40.645 0.352 ;
     RECT  39.925 1.792 40.645 17.568 ;
     RECT  40.115 22.464 40.739 23.072 ;
     RECT  40.645 0.128 40.981 17.568 ;
     RECT  40.115 19.968 40.981 20.96 ;
     RECT  40.739 23.04 41.029 23.072 ;
     RECT  38.531 24.448 41.029 55.964 ;
     RECT  41.029 23.04 41.171 55.964 ;
     RECT  41.171 23.04 41.459 23.072 ;
     RECT  41.171 24.448 42.563 55.964 ;
     RECT  40.981 0.128 43.861 20.96 ;
     RECT  43.861 0.128 44.819 21.152 ;
     RECT  42.563 24.704 45.013 55.964 ;
     RECT  44.819 20.928 45.203 21.152 ;
     RECT  45.013 23.552 45.493 55.964 ;
     RECT  45.493 22.336 46.067 55.964 ;
     RECT  44.819 0.128 46.645 19.488 ;
     RECT  45.203 20.928 46.645 20.96 ;
     RECT  46.645 0.128 46.741 20.96 ;
     RECT  46.067 22.336 46.741 22.368 ;
     RECT  46.741 0.128 48.467 22.368 ;
     RECT  48.467 0.128 49.331 22.24 ;
     RECT  49.331 1.792 49.619 22.24 ;
     RECT  46.067 24.32 49.669 55.964 ;
     RECT  49.669 24.32 49.715 55.968 ;
     RECT  49.715 24.32 50.821 55.836 ;
     RECT  50.821 23.552 51.491 55.836 ;
     RECT  49.619 1.792 52.405 22.176 ;
     RECT  49.331 0.128 53.029 0.224 ;
     RECT  53.029 0.128 53.557 0.416 ;
     RECT  51.491 24.32 53.749 55.836 ;
     RECT  52.405 1.792 53.797 22.496 ;
     RECT  53.749 24.32 53.797 55.84 ;
     RECT  53.797 24.32 53.987 55.968 ;
     RECT  53.557 0.128 55.237 0.48 ;
     RECT  53.797 1.792 55.237 23.008 ;
     RECT  55.237 0.128 55.523 23.008 ;
     RECT  55.523 19.52 55.619 23.008 ;
     RECT  55.619 20.16 55.861 23.008 ;
     RECT  53.987 24.32 55.861 55.072 ;
     RECT  55.861 20.16 57.011 55.072 ;
     RECT  57.011 30.016 57.059 32.352 ;
     RECT  57.059 30.016 57.395 32.16 ;
     RECT  57.011 34.56 57.445 55.072 ;
     RECT  57.011 20.16 57.733 28.64 ;
     RECT  55.523 0.128 57.923 18.016 ;
     RECT  57.445 34.56 58.019 55.968 ;
     RECT  57.733 19.328 58.163 28.64 ;
     RECT  57.395 30.144 58.501 32.16 ;
     RECT  58.501 30.144 58.739 32.224 ;
     RECT  58.019 34.56 59.027 55.072 ;
     RECT  59.027 45.824 59.219 55.072 ;
     RECT  57.923 0.128 59.221 17.888 ;
     RECT  58.163 19.328 59.221 26.464 ;
     RECT  59.027 34.56 59.653 44.448 ;
     RECT  59.219 46.016 59.749 55.072 ;
     RECT  58.739 30.272 60.035 32.224 ;
     RECT  59.221 0.128 60.373 26.464 ;
     RECT  58.163 28.288 60.373 28.64 ;
     RECT  59.749 46.016 60.515 55.968 ;
     RECT  60.035 30.784 60.997 32.224 ;
     RECT  59.653 34.368 60.997 44.448 ;
     RECT  60.373 0.128 61.091 28.64 ;
     RECT  60.997 30.784 61.235 44.448 ;
     RECT  60.515 46.016 61.283 55.84 ;
     RECT  61.235 30.784 61.331 41.312 ;
     RECT  61.235 42.688 61.525 44.448 ;
     RECT  61.283 46.016 61.525 55.072 ;
     RECT  61.091 20.8 61.573 28.64 ;
     RECT  61.525 42.688 61.667 55.072 ;
     RECT  61.331 30.784 61.715 40.992 ;
     RECT  61.715 30.976 62.291 40.992 ;
     RECT  61.667 52.608 62.291 55.072 ;
     RECT  61.667 42.688 62.339 51.232 ;
     RECT  62.291 52.608 62.387 54.56 ;
     RECT  61.573 20.8 62.533 28.832 ;
     RECT  62.339 42.688 62.629 43.872 ;
     RECT  61.091 0.128 62.677 19.04 ;
     RECT  62.533 20.672 62.677 28.832 ;
     RECT  62.291 39.232 62.677 40.992 ;
     RECT  62.629 42.368 62.677 43.872 ;
     RECT  62.677 0.128 62.773 28.832 ;
     RECT  62.677 39.232 63.059 43.872 ;
     RECT  62.339 45.696 63.205 51.232 ;
     RECT  62.387 52.608 63.205 53.536 ;
     RECT  63.059 39.232 63.539 43.744 ;
     RECT  63.205 45.696 63.875 53.536 ;
     RECT  62.773 0.128 64.115 29.088 ;
     RECT  63.539 39.36 64.835 43.744 ;
     RECT  62.291 30.976 64.979 37.6 ;
     RECT  64.115 0.192 64.981 29.088 ;
     RECT  63.875 45.696 65.075 53.344 ;
     RECT  65.075 47.04 65.123 53.28 ;
     RECT  64.979 34.56 65.219 37.6 ;
     RECT  65.075 45.696 65.317 45.728 ;
     RECT  65.317 45.632 65.365 45.728 ;
     RECT  65.365 45.568 65.411 45.728 ;
     RECT  65.411 45.568 65.507 45.664 ;
     RECT  64.835 39.36 65.989 43.296 ;
     RECT  64.981 0.192 66.419 29.536 ;
     RECT  65.219 34.56 66.661 34.592 ;
     RECT  65.507 45.632 66.709 45.664 ;
     RECT  64.979 30.976 66.949 33.184 ;
     RECT  66.661 34.496 66.949 34.592 ;
     RECT  65.989 38.912 67.043 43.296 ;
     RECT  66.419 1.856 67.093 29.536 ;
     RECT  66.949 30.976 67.093 34.592 ;
     RECT  67.043 42.368 67.139 43.296 ;
     RECT  67.093 1.856 67.765 34.592 ;
     RECT  65.219 36.416 67.765 37.6 ;
     RECT  67.043 38.912 67.765 40.608 ;
     RECT  67.765 1.856 67.813 34.784 ;
     RECT  67.765 36.416 67.813 40.608 ;
     RECT  66.709 45.632 68.435 45.728 ;
     RECT  67.813 1.856 68.483 40.608 ;
     RECT  65.123 47.04 69.011 53.024 ;
     RECT  69.011 47.04 69.395 49.248 ;
     RECT  68.483 20.032 69.539 40.608 ;
     RECT  68.435 45.632 69.587 45.664 ;
     RECT  66.419 0.192 69.731 0.544 ;
     RECT  69.011 50.56 69.875 53.024 ;
     RECT  67.139 43.264 69.973 43.296 ;
     RECT  68.483 1.856 70.069 18.592 ;
     RECT  69.539 20.032 70.069 40.032 ;
     RECT  70.069 1.856 70.163 40.032 ;
     RECT  70.163 2.048 70.307 40.032 ;
     RECT  69.395 49.216 70.499 49.248 ;
     RECT  69.875 50.816 70.501 53.024 ;
     RECT  70.501 50.816 70.645 53.216 ;
     RECT  69.395 47.04 70.693 47.888 ;
     RECT  69.973 43.264 71.315 43.936 ;
     RECT  70.645 50.816 71.315 53.28 ;
     RECT  70.693 47.04 72.325 48.864 ;
     RECT  71.315 50.816 72.325 53.216 ;
     RECT  72.325 47.04 72.373 53.216 ;
     RECT  72.373 46.464 72.419 53.216 ;
     RECT  71.315 43.264 73.045 43.296 ;
     RECT  73.045 43.264 73.333 43.872 ;
     RECT  72.419 49.536 73.571 53.216 ;
     RECT  73.333 43.008 73.669 43.872 ;
     RECT  72.419 46.464 73.717 48.16 ;
     RECT  70.307 2.112 73.859 40.032 ;
     RECT  73.859 2.112 75.157 17.568 ;
     RECT  73.859 18.88 75.157 40.032 ;
     RECT  73.571 51.904 75.205 53.216 ;
     RECT  75.205 51.904 75.443 53.792 ;
     RECT  73.717 46.464 75.733 49.312 ;
     RECT  69.731 0.192 75.781 0.224 ;
     RECT  75.157 2.112 75.781 40.032 ;
     RECT  73.669 43.008 75.781 44.384 ;
     RECT  75.733 46.208 75.781 50.4 ;
     RECT  75.781 43.008 75.827 50.4 ;
     RECT  75.827 43.008 76.307 43.936 ;
     RECT  75.781 0.192 76.451 0.352 ;
     RECT  76.451 0.192 76.547 0.224 ;
     RECT  75.827 45.568 76.789 50.4 ;
     RECT  75.443 52.608 76.789 53.792 ;
     RECT  75.781 2.112 76.933 40.544 ;
     RECT  76.933 1.984 77.509 40.544 ;
     RECT  76.307 43.008 77.701 43.296 ;
     RECT  77.509 1.984 77.845 40.672 ;
     RECT  77.701 42.048 77.845 43.296 ;
     RECT  76.789 45.568 77.891 53.792 ;
     RECT  77.845 1.984 77.893 43.296 ;
     RECT  77.891 45.568 77.939 50.528 ;
     RECT  77.893 1.984 78.419 43.552 ;
     RECT  77.939 45.568 78.419 45.6 ;
     RECT  77.939 46.912 78.419 50.528 ;
     RECT  78.419 1.984 78.947 42.208 ;
     RECT  77.891 52.608 79.139 53.792 ;
     RECT  78.419 43.52 79.189 43.552 ;
     RECT  78.947 2.112 79.717 42.208 ;
     RECT  79.189 43.52 79.717 44.448 ;
     RECT  79.139 52.608 79.813 53.728 ;
     RECT  79.141 0.512 79.859 0.544 ;
     RECT  78.419 49.984 80.437 50.528 ;
     RECT  79.813 52.352 80.437 53.728 ;
     RECT  79.717 2.112 80.917 44.448 ;
     RECT  78.419 46.912 80.917 47.888 ;
     RECT  80.437 49.984 81.445 53.728 ;
     RECT  81.541 0.192 81.637 0.224 ;
     RECT  80.917 2.112 81.685 47.888 ;
     RECT  81.445 49.984 81.973 53.792 ;
     RECT  81.685 2.112 82.021 48.032 ;
     RECT  82.021 2.112 82.691 48.16 ;
     RECT  81.637 0.192 82.885 0.416 ;
     RECT  82.691 2.112 83.843 47.888 ;
     RECT  82.885 0.192 83.987 0.544 ;
     RECT  83.987 0.192 84.133 0.48 ;
     RECT  81.973 49.792 84.133 53.792 ;
     RECT  83.843 2.112 84.275 28.768 ;
     RECT  84.133 49.536 84.419 53.792 ;
     RECT  84.275 19.52 84.467 28.768 ;
     RECT  83.843 30.272 84.661 47.888 ;
     RECT  84.419 49.536 84.661 53.728 ;
     RECT  84.661 30.272 84.755 53.728 ;
     RECT  84.275 2.112 84.995 18.208 ;
     RECT  84.755 30.272 85.475 33.824 ;
     RECT  85.475 30.272 86.005 33.696 ;
     RECT  84.467 19.52 86.051 26.464 ;
     RECT  86.051 19.584 86.437 26.464 ;
     RECT  86.437 19.584 86.581 26.528 ;
     RECT  84.467 28.416 86.581 28.768 ;
     RECT  86.581 19.584 86.629 28.768 ;
     RECT  86.005 30.08 86.629 33.696 ;
     RECT  84.133 0.128 86.723 0.48 ;
     RECT  86.629 19.584 87.203 33.696 ;
     RECT  87.203 27.904 87.347 33.696 ;
     RECT  86.723 0.128 87.827 0.416 ;
     RECT  84.755 35.456 88.115 53.728 ;
     RECT  87.347 28.416 88.309 33.696 ;
     RECT  84.995 2.304 88.357 18.208 ;
     RECT  87.203 19.584 88.357 26.528 ;
     RECT  88.115 38.4 88.451 53.728 ;
     RECT  88.357 2.304 88.739 26.528 ;
     RECT  88.739 2.304 89.219 22.752 ;
     RECT  88.451 38.4 89.315 53.536 ;
     RECT  89.219 19.648 89.411 22.752 ;
     RECT  88.739 24.192 89.461 26.528 ;
     RECT  88.309 28.416 89.461 33.952 ;
     RECT  89.411 19.648 89.555 22.368 ;
     RECT  89.461 24.192 90.131 33.952 ;
     RECT  90.131 30.784 90.421 33.952 ;
     RECT  88.115 35.456 90.421 37.088 ;
     RECT  89.219 2.304 90.565 18.144 ;
     RECT  89.555 19.648 90.565 22.176 ;
     RECT  89.315 38.4 91.045 49.824 ;
     RECT  90.421 30.784 91.141 37.088 ;
     RECT  91.045 38.4 91.141 49.888 ;
     RECT  90.131 24.192 91.235 29.408 ;
     RECT  91.141 30.784 91.235 49.888 ;
     RECT  89.315 51.392 91.235 53.536 ;
     RECT  91.235 24.192 91.283 29.216 ;
     RECT  91.235 30.976 91.285 49.888 ;
     RECT  87.827 0.128 91.429 0.352 ;
     RECT  91.285 30.976 91.525 50.016 ;
     RECT  91.235 51.392 91.525 53.28 ;
     RECT  91.525 30.976 91.811 53.28 ;
     RECT  91.811 35.456 92.387 53.28 ;
     RECT  90.565 2.304 92.435 22.176 ;
     RECT  91.811 30.976 92.435 34.016 ;
     RECT  92.435 20.032 92.821 22.176 ;
     RECT  91.283 28.224 92.821 29.216 ;
     RECT  92.435 30.976 92.821 31.904 ;
     RECT  92.435 33.216 92.867 34.016 ;
     RECT  92.387 38.592 92.869 53.28 ;
     RECT  92.435 2.304 92.963 18.4 ;
     RECT  92.821 20.032 92.965 22.752 ;
     RECT  91.283 24.192 92.965 26.464 ;
     RECT  92.821 27.904 93.059 31.904 ;
     RECT  91.429 0.128 93.445 0.416 ;
     RECT  92.387 35.456 93.539 37.088 ;
     RECT  92.867 33.408 93.589 34.016 ;
     RECT  93.445 0.128 93.923 0.544 ;
     RECT  93.059 27.904 93.971 28.256 ;
     RECT  92.869 38.592 94.067 53.536 ;
     RECT  92.963 2.496 94.597 18.4 ;
     RECT  92.965 20.032 94.597 26.464 ;
     RECT  93.971 27.968 94.597 28.256 ;
     RECT  93.059 29.888 94.597 31.904 ;
     RECT  93.589 33.408 94.597 34.336 ;
     RECT  93.539 35.968 94.597 37.088 ;
     RECT  94.067 39.552 94.691 53.536 ;
     RECT  94.691 39.744 94.739 53.344 ;
     RECT  94.597 35.968 94.741 37.216 ;
     RECT  94.597 2.496 95.317 26.656 ;
     RECT  94.597 27.968 95.317 34.336 ;
     RECT  95.317 2.496 95.605 34.336 ;
     RECT  94.739 52.096 95.651 53.344 ;
     RECT  95.605 2.496 95.701 34.464 ;
     RECT  94.741 35.968 95.701 37.6 ;
     RECT  93.923 0.128 96.229 0.48 ;
     RECT  96.229 0.128 96.275 0.544 ;
     RECT  94.739 39.744 96.277 50.592 ;
     RECT  96.277 39.296 96.613 50.592 ;
     RECT  95.701 2.24 96.707 37.6 ;
     RECT  96.707 35.712 96.803 37.6 ;
     RECT  95.651 53.312 96.853 53.344 ;
     RECT  96.803 35.712 96.947 37.216 ;
     RECT  96.613 39.296 97.043 51.744 ;
     RECT  96.275 0.192 97.523 0.544 ;
     RECT  96.947 35.904 97.619 37.216 ;
     RECT  97.043 39.744 97.763 51.744 ;
     RECT  97.619 36.16 98.245 37.216 ;
     RECT  97.523 0.192 98.341 0.48 ;
     RECT  98.341 0.128 98.387 0.48 ;
     RECT  97.763 44.096 98.483 51.744 ;
     RECT  96.853 53.312 98.483 53.472 ;
     RECT  96.707 2.24 98.581 34.016 ;
     RECT  97.763 39.744 98.629 42.656 ;
     RECT  98.483 50.496 98.773 51.744 ;
     RECT  98.483 53.312 98.773 53.344 ;
     RECT  98.773 50.496 99.011 53.344 ;
     RECT  98.245 36.16 99.061 37.92 ;
     RECT  98.629 39.68 99.061 42.656 ;
     RECT  99.061 36.16 99.397 42.656 ;
     RECT  98.483 44.096 99.397 48.8 ;
     RECT  98.581 2.112 99.443 34.016 ;
     RECT  99.443 6.848 99.445 34.016 ;
     RECT  99.397 36.16 99.445 48.8 ;
     RECT  98.387 0.128 100.019 0.416 ;
     RECT  99.445 6.848 100.261 48.8 ;
     RECT  99.011 50.496 100.261 52.96 ;
     RECT  100.261 6.848 100.547 52.96 ;
     RECT  100.547 46.208 100.739 52.96 ;
     RECT  99.443 2.112 100.789 5.344 ;
     RECT  100.547 6.848 100.789 44.64 ;
     RECT  100.789 2.112 100.837 44.64 ;
     RECT  100.739 46.208 101.171 48.416 ;
     RECT  100.019 0.128 101.413 0.224 ;
     RECT  100.837 1.984 101.507 44.64 ;
     RECT  101.507 1.984 101.555 27.872 ;
     RECT  101.507 30.08 101.891 44.64 ;
     RECT  101.555 8.064 102.083 27.872 ;
     RECT  101.891 30.08 102.083 30.624 ;
     RECT  100.739 49.792 102.085 52.96 ;
     RECT  101.413 0.128 102.181 0.416 ;
     RECT  101.891 32.064 102.227 44.64 ;
     RECT  102.227 33.472 102.469 44.64 ;
     RECT  102.083 30.08 102.611 30.112 ;
     RECT  101.555 1.984 102.707 6.752 ;
     RECT  102.469 33.472 102.707 44.768 ;
     RECT  102.181 0.128 102.755 0.544 ;
     RECT  102.083 8.064 102.899 23.776 ;
     RECT  102.707 36.416 103.043 44.768 ;
     RECT  102.707 2.24 103.139 6.752 ;
     RECT  102.085 49.792 103.141 53.088 ;
     RECT  102.707 33.472 103.187 34.976 ;
     RECT  102.899 8.064 103.235 23.392 ;
     RECT  102.227 32.064 103.235 32.096 ;
     RECT  103.043 36.416 103.235 42.272 ;
     RECT  103.235 8.064 103.427 22.88 ;
     RECT  103.139 2.56 103.525 6.752 ;
     RECT  103.427 8.064 103.525 22.624 ;
     RECT  103.235 41.472 103.571 42.272 ;
     RECT  101.171 46.272 103.669 48.416 ;
     RECT  102.083 25.152 103.717 27.872 ;
     RECT  103.043 43.584 103.717 44.768 ;
     RECT  103.669 46.08 103.717 48.416 ;
     RECT  102.755 0.128 103.763 0.352 ;
     RECT  103.525 2.56 103.763 22.624 ;
     RECT  103.235 36.416 103.763 39.904 ;
     RECT  103.141 49.792 103.763 53.664 ;
     RECT  103.763 0.128 104.003 0.16 ;
     RECT  103.717 25.152 104.051 29.152 ;
     RECT  103.717 43.584 104.149 48.416 ;
     RECT  103.763 49.792 104.149 50.72 ;
     RECT  104.051 25.152 104.195 27.488 ;
     RECT  103.571 41.6 104.243 42.272 ;
     RECT  103.763 36.416 104.291 38.56 ;
     RECT  104.195 25.472 104.339 27.488 ;
     RECT  103.187 34.176 104.339 34.976 ;
     RECT  104.149 43.584 104.339 50.72 ;
     RECT  103.763 52.16 104.339 53.664 ;
     RECT  104.339 34.944 104.387 34.976 ;
     RECT  104.243 41.6 104.387 41.632 ;
     RECT  103.763 2.688 104.483 22.624 ;
     RECT  104.339 49.6 104.531 50.72 ;
     RECT  104.483 9.472 104.627 22.624 ;
     RECT  104.339 25.616 104.627 26.72 ;
     RECT  104.339 43.584 104.627 47.888 ;
     RECT  104.483 2.688 104.723 7.584 ;
     RECT  104.051 29.12 104.723 29.152 ;
     RECT  104.627 25.616 104.819 26.656 ;
     RECT  104.627 43.584 104.819 45.024 ;
     RECT  104.627 20.544 104.867 22.624 ;
     RECT  104.819 43.584 104.867 43.616 ;
     RECT  104.867 20.544 104.915 22.368 ;
     RECT  104.531 49.6 104.915 50.528 ;
     RECT  104.339 52.416 104.915 53.664 ;
     RECT  104.723 2.816 105.443 7.584 ;
     RECT  104.291 38.528 105.443 38.56 ;
     RECT  104.819 44.992 105.443 45.024 ;
     RECT  104.915 50.496 105.443 50.528 ;
     RECT  105.443 2.816 105.491 7.456 ;
     RECT  104.627 9.472 105.491 18.848 ;
     RECT  104.915 52.416 105.491 52.448 ;
     RECT  103.763 39.872 105.587 39.904 ;
     RECT  105.491 9.472 105.635 16.032 ;
     RECT  105.635 11.2 105.683 16.032 ;
     RECT  105.491 2.816 105.731 6.752 ;
     RECT  105.731 4.016 105.84 6.752 ;
     RECT  105.683 14.4 105.84 16.032 ;
     RECT  104.819 25.616 105.84 26.288 ;
     RECT  104.291 36.416 105.84 37.088 ;
     RECT  104.627 47.216 105.84 47.888 ;
     RECT  105.84 5.056 105.875 6.752 ;
     RECT  104.915 20.544 105.875 22.304 ;
     RECT  105.84 14.4 105.923 14.432 ;
     RECT  105.875 20.544 105.923 21.152 ;
     RECT  105.875 5.056 106.067 6.624 ;
     RECT  106.067 6.272 106.115 6.624 ;
     RECT  105.923 20.544 106.115 21.024 ;
     RECT  106.115 6.592 106.163 6.624 ;
     RECT  105.84 16 106.163 16.032 ;
     RECT  105.635 9.472 106.211 9.504 ;
     RECT  105.491 18.816 106.211 18.848 ;
     RECT  105.683 11.2 106.259 11.232 ;
     RECT  106.115 20.992 106.259 21.024 ;
  END
END hfd_qsel_pack_k
END LIBRARY
